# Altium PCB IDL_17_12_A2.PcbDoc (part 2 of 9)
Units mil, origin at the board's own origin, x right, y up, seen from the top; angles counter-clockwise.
Board outline 5119.97 x 10350 mil, 6 copper layers (Top Signal, 3.3 Volt, GND, 5 Volt, Split Plane, Bot Signal), stack 66.2 mil thick; 514 components, 178 nets, 2321 pads, 427 vias.

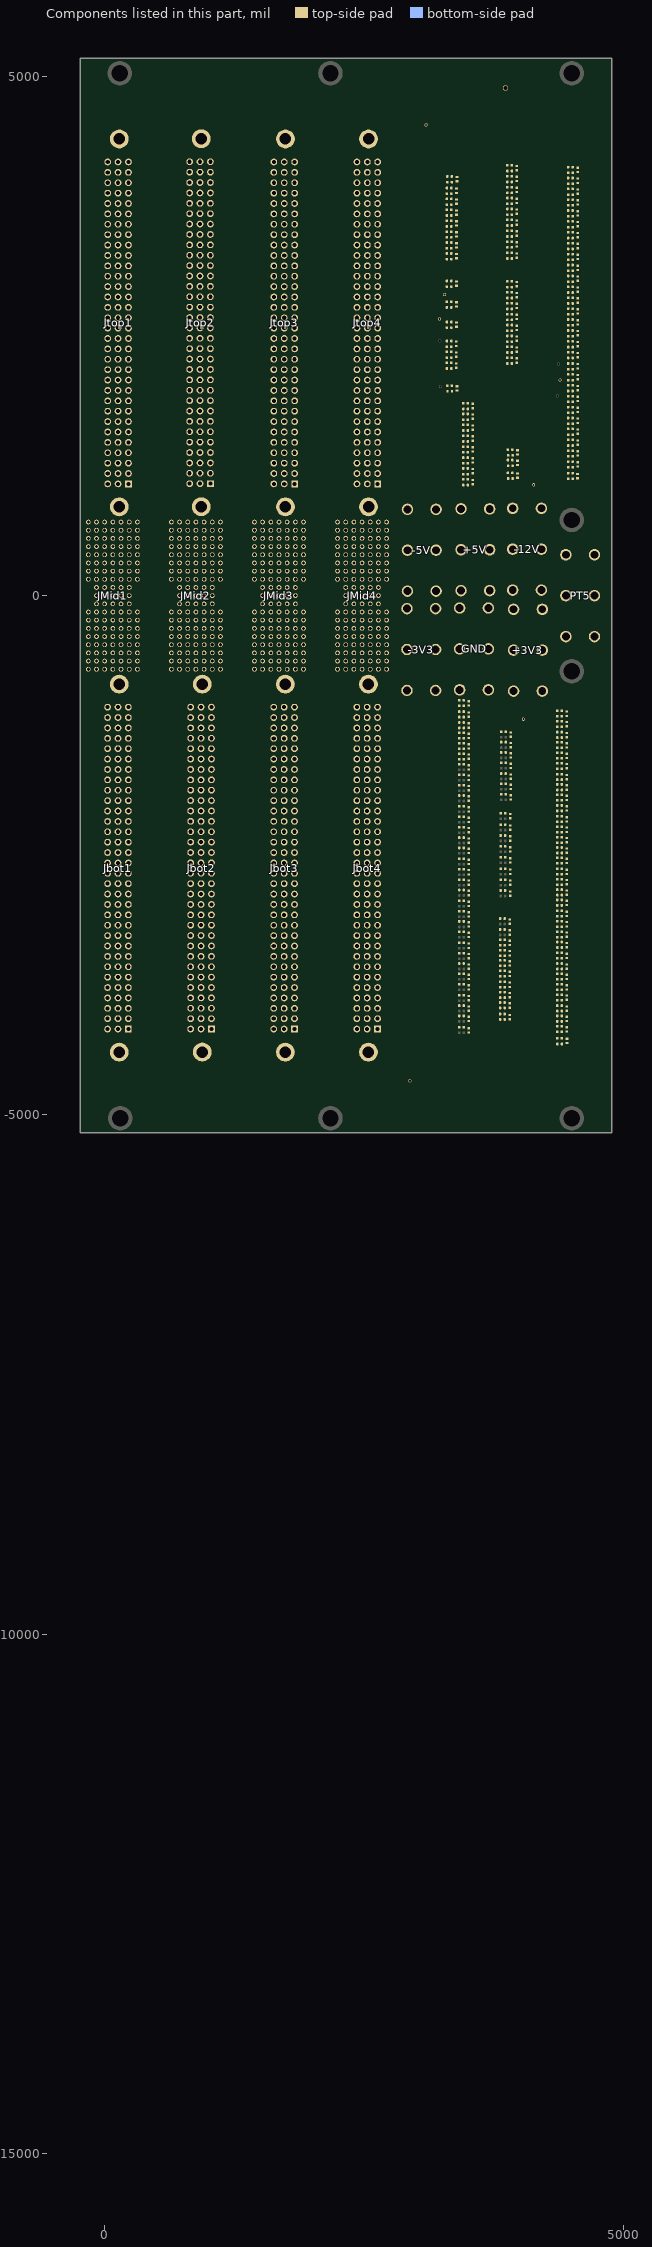
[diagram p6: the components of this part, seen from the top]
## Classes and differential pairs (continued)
component class IDL_17_12_TerB50: CRB_IDL_17_12_TerB50 R1RB_IDL_17_12_TerB50 R2RB_IDL_17_12_TerB50
component class IDL_17_12_TerB51: CRB_IDL_17_12_TerB51 R1RB_IDL_17_12_TerB51 R2RB_IDL_17_12_TerB51
component class IDL_17_12_TerB52: CRB_IDL_17_12_TerB52 R1RB_IDL_17_12_TerB52 R2RB_IDL_17_12_TerB52
component class IDL_17_12_TerB53: CRB_IDL_17_12_TerB53 R1RB_IDL_17_12_TerB53 R2RB_IDL_17_12_TerB53
component class IDL_17_12_TerB54: CRB_IDL_17_12_TerB54 R1RB_IDL_17_12_TerB54 R2RB_IDL_17_12_TerB54
component class IDL_17_12_TerB55: CRB_IDL_17_12_TerB55 R1RB_IDL_17_12_TerB55 R2RB_IDL_17_12_TerB55
component class IDL_17_12_TerB56: CRB_IDL_17_12_TerB56 R1RB_IDL_17_12_TerB56 R2RB_IDL_17_12_TerB56
component class IDL_17_12_TerB57: CRB_IDL_17_12_TerB57 R1RB_IDL_17_12_TerB57 R2RB_IDL_17_12_TerB57
component class IDL_17_12_TerB58: CRB_IDL_17_12_TerB58 R1RB_IDL_17_12_TerB58 R2RB_IDL_17_12_TerB58
component class IDL_17_12_TerB59: CRB_IDL_17_12_TerB59 R1RB_IDL_17_12_TerB59 R2RB_IDL_17_12_TerB59
component class IDL_17_12_TerB60: CRB_IDL_17_12_TerB60 R1RB_IDL_17_12_TerB60 R2RB_IDL_17_12_TerB60
component class IDL_17_12_TerB61: CRB_IDL_17_12_TerB61 R1RB_IDL_17_12_TerB61 R2RB_IDL_17_12_TerB61
component class IDL_17_12_TerB62: CRB_IDL_17_12_TerB62 R1RB_IDL_17_12_TerB62 R2RB_IDL_17_12_TerB62
component class IDL_17_12_TerB63: CRB_IDL_17_12_TerB63 R1RB_IDL_17_12_TerB63 R2RB_IDL_17_12_TerB63
component class IDL_17_12_TerB64: CRB_IDL_17_12_TerB64 R1RB_IDL_17_12_TerB64 R2RB_IDL_17_12_TerB64
component class IDL_17_12_TerB65: CRB_IDL_17_12_TerB65 R1RB_IDL_17_12_TerB65 R2RB_IDL_17_12_TerB65
component class IDL_17_12_TerB66: CRB_IDL_17_12_TerB66 R1RB_IDL_17_12_TerB66 R2RB_IDL_17_12_TerB66
component class IDL_17_12_TerB67: CRB_IDL_17_12_TerB67 R1RB_IDL_17_12_TerB67 R2RB_IDL_17_12_TerB67
component class IDL_17_12_TerB68: CRB_IDL_17_12_TerB68 R1RB_IDL_17_12_TerB68 R2RB_IDL_17_12_TerB68
component class IDL_17_12_TerB69: CRB_IDL_17_12_TerB69 R1RB_IDL_17_12_TerB69 R2RB_IDL_17_12_TerB69
component class IDL_17_12_TerB70: CRB_IDL_17_12_TerB70 R1RB_IDL_17_12_TerB70 R2RB_IDL_17_12_TerB70
component class IDL_17_12_TerB71: CRB_IDL_17_12_TerB71 R1RB_IDL_17_12_TerB71 R2RB_IDL_17_12_TerB71
component class IDL_17_12_TerB72: CRB_IDL_17_12_TerB72 R1RB_IDL_17_12_TerB72 R2RB_IDL_17_12_TerB72
component class IDL_17_12_TerB73: CRB_IDL_17_12_TerB73 R1RB_IDL_17_12_TerB73 R2RB_IDL_17_12_TerB73
component class IDL_17_12_TerB74: CRB_IDL_17_12_TerB74 R1RB_IDL_17_12_TerB74 R2RB_IDL_17_12_TerB74
component class IDL_17_12_TerB75: CRB_IDL_17_12_TerB75 R1RB_IDL_17_12_TerB75 R2RB_IDL_17_12_TerB75
component class IDL_17_12_TerB76: CRB_IDL_17_12_TerB76 R1RB_IDL_17_12_TerB76 R2RB_IDL_17_12_TerB76
component class IDL_17_12_TerB77: CRB_IDL_17_12_TerB77 R1RB_IDL_17_12_TerB77 R2RB_IDL_17_12_TerB77
component class IDL_17_12_TerB78: CRB_IDL_17_12_TerB78 R1RB_IDL_17_12_TerB78 R2RB_IDL_17_12_TerB78
component class IDL_17_12_TerB79: CRB_IDL_17_12_TerB79 R1RB_IDL_17_12_TerB79 R2RB_IDL_17_12_TerB79
component class IDL_17_12_TerB80: CRB_IDL_17_12_TerB80 R1RB_IDL_17_12_TerB80 R2RB_IDL_17_12_TerB80
component class IDL_17_12_TerB81: CRB_IDL_17_12_TerB81 R1RB_IDL_17_12_TerB81 R2RB_IDL_17_12_TerB81
component class IDL_17_12_TerB82: CRB_IDL_17_12_TerB82 R1RB_IDL_17_12_TerB82 R2RB_IDL_17_12_TerB82
component class IDL_17_12_TerB83: CRB_IDL_17_12_TerB83 R1RB_IDL_17_12_TerB83 R2RB_IDL_17_12_TerB83
component class IDL_17_12_TerB84: CRB_IDL_17_12_TerB84 R1RB_IDL_17_12_TerB84 R2RB_IDL_17_12_TerB84
component class IDL_17_12_TerB85: CRB_IDL_17_12_TerB85 R1RB_IDL_17_12_TerB85 R2RB_IDL_17_12_TerB85
component class IDL_17_12_TerB86: CRB_IDL_17_12_TerB86 R1RB_IDL_17_12_TerB86 R2RB_IDL_17_12_TerB86
component class IDL_17_12_TerB87: CRB_IDL_17_12_TerB87 R1RB_IDL_17_12_TerB87 R2RB_IDL_17_12_TerB87
component class IDL_17_12_TerB88: CRB_IDL_17_12_TerB88 R1RB_IDL_17_12_TerB88 R2RB_IDL_17_12_TerB88
component class IDL_17_12_Top: +3V3 +5V -3V3 -5V -12V GND PT5
net class JB[1..89]: JB1 JB2 JB3 JB4 JB5 JB6 JB7 JB8 JB9 JB10 JB11 JB12 JB13 JB14 JB15 JB16 JB17 JB18 JB19 JB20 JB21 JB22 JB23 JB24 JB25 JB26 JB27 JB28 JB29 JB30 JB31 JB32 JB33 JB34 JB35 JB36 JB37 JB38 JB39 JB40 JB41 JB42 JB43 JB44 JB45 JB46 JB47 JB48 JB49 JB50 JB51 JB52 JB53 JB54 JB55 JB56 JB57 JB58 JB59 JB60 JB61 JB62 JB63 JB64 JB65 JB66 JB67 JB68 JB69 JB70 JB71 JB72 JB73 JB74 JB75 JB76 JB77 JB78 JB79 JB80 JB81 JB82 JB83 JB84 JB85 JB86 JB87 JB88 JB89
net class JT[1..72]: JT1 JT2 JT3 JT4 JT5 JT6 JT7 JT8 JT9 JT10 JT11 JT12 JT13 JT14 JT15 JT16 JT17 JT18 JT19 JT20 JT21 JT22 JT23 JT24 JT25 JT26 JT27 JT28 JT29 JT30 JT31 JT32 JT33 JT34 JT35 JT36 JT37 JT38 JT39 JT40 JT41 JT42 JT43 JT44 JT45 JT46 JT47 JT48 JT49 JT50 JT51 JT52 JT53 JT54 JT55 JT56 JT57 JT58 JT59 JT60 JT61 JT62 JT63 JT64 JT65 JT66 JT67 JT68 JT69 JT70 JT71 JT72
channel class IDL_17_12_TerA: IDL_17_12_TerA1 IDL_17_12_TerA2 IDL_17_12_TerA3 IDL_17_12_TerA4 IDL_17_12_TerA5 IDL_17_12_TerA6 IDL_17_12_TerA7 IDL_17_12_TerA8 IDL_17_12_TerA9 IDL_17_12_TerA10 IDL_17_12_TerA11 IDL_17_12_TerA12 IDL_17_12_TerA13 IDL_17_12_TerA14 IDL_17_12_TerA15 IDL_17_12_TerA16 IDL_17_12_TerA17 IDL_17_12_TerA18 IDL_17_12_TerA19 IDL_17_12_TerA20 IDL_17_12_TerA21 IDL_17_12_TerA22 IDL_17_12_TerA23 IDL_17_12_TerA24 IDL_17_12_TerA25 IDL_17_12_TerA26 IDL_17_12_TerA27 IDL_17_12_TerA28 IDL_17_12_TerA29 IDL_17_12_TerA30 IDL_17_12_TerA31 IDL_17_12_TerA32 IDL_17_12_TerA33 IDL_17_12_TerA34 IDL_17_12_TerA35 IDL_17_12_TerA36 IDL_17_12_TerA37 IDL_17_12_TerA38 IDL_17_12_TerA39 IDL_17_12_TerA40 IDL_17_12_TerA41 IDL_17_12_TerA42 IDL_17_12_TerA43 IDL_17_12_TerA44 IDL_17_12_TerA45 IDL_17_12_TerA46 IDL_17_12_TerA47 IDL_17_12_TerA48 IDL_17_12_TerA49 IDL_17_12_TerA50 IDL_17_12_TerA51 IDL_17_12_TerA52 IDL_17_12_TerA53 IDL_17_12_TerA54 IDL_17_12_TerA55 IDL_17_12_TerA56 IDL_17_12_TerA57 IDL_17_12_TerA58 IDL_17_12_TerA59 IDL_17_12_TerA60 IDL_17_12_TerA61 IDL_17_12_TerA62 IDL_17_12_TerA63 IDL_17_12_TerA64 IDL_17_12_TerA65 IDL_17_12_TerA66 IDL_17_12_TerA67 IDL_17_12_TerA68 IDL_17_12_TerA69 IDL_17_12_TerA70 IDL_17_12_TerA71
channel class IDL_17_12_TerB: IDL_17_12_TerB1 IDL_17_12_TerB2 IDL_17_12_TerB3 IDL_17_12_TerB4 IDL_17_12_TerB5 IDL_17_12_TerB6 IDL_17_12_TerB7 IDL_17_12_TerB8 IDL_17_12_TerB9 IDL_17_12_TerB10 IDL_17_12_TerB11 IDL_17_12_TerB12 IDL_17_12_TerB13 IDL_17_12_TerB14 IDL_17_12_TerB15 IDL_17_12_TerB16 IDL_17_12_TerB17 IDL_17_12_TerB18 IDL_17_12_TerB19 IDL_17_12_TerB20 IDL_17_12_TerB21 IDL_17_12_TerB22 IDL_17_12_TerB23 IDL_17_12_TerB24 IDL_17_12_TerB25 IDL_17_12_TerB26 IDL_17_12_TerB27 IDL_17_12_TerB28 IDL_17_12_TerB29 IDL_17_12_TerB30 IDL_17_12_TerB31 IDL_17_12_TerB32 IDL_17_12_TerB33 IDL_17_12_TerB34 IDL_17_12_TerB35 IDL_17_12_TerB36 IDL_17_12_TerB37 IDL_17_12_TerB38 IDL_17_12_TerB39 IDL_17_12_TerB40 IDL_17_12_TerB41 IDL_17_12_TerB42 IDL_17_12_TerB43 IDL_17_12_TerB44 IDL_17_12_TerB45 IDL_17_12_TerB46 IDL_17_12_TerB47 IDL_17_12_TerB48 IDL_17_12_TerB49 IDL_17_12_TerB50 IDL_17_12_TerB51 IDL_17_12_TerB52 IDL_17_12_TerB53 IDL_17_12_TerB54 IDL_17_12_TerB55 IDL_17_12_TerB56 IDL_17_12_TerB57 IDL_17_12_TerB58 IDL_17_12_TerB59 IDL_17_12_TerB60 IDL_17_12_TerB61 IDL_17_12_TerB62 IDL_17_12_TerB63 IDL_17_12_TerB64 IDL_17_12_TerB65 IDL_17_12_TerB66 IDL_17_12_TerB67 IDL_17_12_TerB68 IDL_17_12_TerB69 IDL_17_12_TerB70 IDL_17_12_TerB71 IDL_17_12_TerB72 IDL_17_12_TerB73 IDL_17_12_TerB74 IDL_17_12_TerB75 IDL_17_12_TerB76 IDL_17_12_TerB77 IDL_17_12_TerB78 IDL_17_12_TerB79 IDL_17_12_TerB80 IDL_17_12_TerB81 IDL_17_12_TerB82 IDL_17_12_TerB83 IDL_17_12_TerB84 IDL_17_12_TerB85 IDL_17_12_TerB86 IDL_17_12_TerB87 IDL_17_12_TerB88
component class IDL_17_12_TerB89: CRB_IDL_17_12_TerB89 R1RB_IDL_17_12_TerB89 R2RB_IDL_17_12_TerB89

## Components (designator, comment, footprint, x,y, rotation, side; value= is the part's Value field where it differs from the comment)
+3V3 "*" PowerTap 3938.12,-919.16 r90 top (schematic designator PT2)
+5V "*" PowerTap 3431.95,48.27 r90 top (schematic designator PT7)
-3V3 "*" PowerTap 2911,-912.72 r90 top (schematic designator PT3)
-5V "*" PowerTap 2915.56,43.52 r90 top (schematic designator PT1)
-12V "*" PowerTap 3929.35,53.22 r90 top (schematic designator PT6)
AS "Comment" TPH0.5S#1 3272.63,2898.29 r0 top
BERR "Comment" TPH0.5S#1 4386.58,2076.24 r0 top
CR_IDL_17_12_TerA1 ".1uF" CC0402N1X 3392.34,4010.25 r90 top (schematic designator CR)
CR_IDL_17_12_TerA2 ".1uF" CC0402N1X 3387.34,3899.01 r90 top (schematic designator CR)
CR_IDL_17_12_TerA3 ".1uF" CC0402N1X 3387.34,3794.01 r90 top (schematic designator CR)
CR_IDL_17_12_TerA4 ".1uF" CC0402N1X 3387.34,3689.01 r90 top (schematic designator CR)
CR_IDL_17_12_TerA5 ".1uF" CC0402N1X 3387.34,3584.01 r90 top (schematic designator CR)
CR_IDL_17_12_TerA6 ".1uF" CC0402N1X 3387.34,3479.01 r90 top (schematic designator CR)
CR_IDL_17_12_TerA7 ".1uF" CC0402N1X 3387.34,3374.01 r90 top (schematic designator CR)
CR_IDL_17_12_TerA8 ".1uF" CC0402N1X 3387.34,3269.01 r90 top (schematic designator CR)
CR_IDL_17_12_TerA9 ".1uF" CC0402N1X 3387.34,3004.01 r90 top (schematic designator CR)
CR_IDL_17_12_TerA10 ".1uF" CC0402N1X 3387.34,2804.01 r90 top (schematic designator CR)
CR_IDL_17_12_TerA11 ".1uF" CC0402N1X 3387.34,2609.01 r90 top (schematic designator CR)
CR_IDL_17_12_TerA12 ".1uF" CC0402N1X 3386.98,2425.8 r90 top (schematic designator CR)
CR_IDL_17_12_TerA13 ".1uF" CC0402N1X 3386.98,2320.8 r90 top (schematic designator CR)
CR_IDL_17_12_TerA14 ".1uF" CC0402N1X 3386.98,2215.8 r90 top (schematic designator CR)
CR_IDL_17_12_TerA15 ".1uF" CC0402N1X 3392.98,1995.86 r90 top (schematic designator CR)
CR_IDL_17_12_TerA16 ".1uF" CC0402N1X 3545.25,1826.49 r90 top (schematic designator CR)
CR_IDL_17_12_TerA17 ".1uF" CC0402N1X 3545.25,1723.49 r90 top (schematic designator CR)
CR_IDL_17_12_TerA18 ".1uF" CC0402N1X 3545.25,1618.49 r90 top (schematic designator CR)
CR_IDL_17_12_TerA19 ".1uF" CC0402N1X 3545.25,1513.49 r90 top (schematic designator CR)
CR_IDL_17_12_TerA20 ".1uF" CC0402N1X 3545.25,1408.49 r90 top (schematic designator CR)
CR_IDL_17_12_TerA21 ".1uF" CC0402N1X 3545.25,1303.49 r90 top (schematic designator CR)
CR_IDL_17_12_TerA22 ".1uF" CC0402N1X 3545.25,1198.49 r90 top (schematic designator CR)
CR_IDL_17_12_TerA23 ".1uF" CC0402N1X 3545.25,1093.49 r90 top (schematic designator CR)
CR_IDL_17_12_TerA24 ".1uF" CC0402N1X 3969.9,4117.6 r90 top (schematic designator CR)
CR_IDL_17_12_TerA25 ".1uF" CC0402N1X 3969.9,4012.6 r90 top (schematic designator CR)
CR_IDL_17_12_TerA26 ".1uF" CC0402N1X 3969.9,3907.6 r90 top (schematic designator CR)
CR_IDL_17_12_TerA27 ".1uF" CC0402N1X 3969.9,3802.6 r90 top (schematic designator CR)
CR_IDL_17_12_TerA28 ".1uF" CC0402N1X 3969.9,3697.6 r90 top (schematic designator CR)
CR_IDL_17_12_TerA29 ".1uF" CC0402N1X 3969.9,3592.6 r90 top (schematic designator CR)
CR_IDL_17_12_TerA30 ".1uF" CC0402N1X 3969.9,3487.6 r90 top (schematic designator CR)
CR_IDL_17_12_TerA31 ".1uF" CC0402N1X 3969.9,3382.6 r90 top (schematic designator CR)
CR_IDL_17_12_TerA32 ".1uF" CC0402N1X 3969.9,3274.6 r90 top (schematic designator CR)
CR_IDL_17_12_TerA33 ".1uF" CC0402N1X 3969.9,2999.6 r90 top (schematic designator CR)
CR_IDL_17_12_TerA34 ".1uF" CC0402N1X 3969.9,2894.6 r90 top (schematic designator CR)
CR_IDL_17_12_TerA35 ".1uF" CC0402N1X 3969.9,2789.6 r90 top (schematic designator CR)
CR_IDL_17_12_TerA36 ".1uF" CC0402N1X 3969.9,2684.6 r90 top (schematic designator CR)
CR_IDL_17_12_TerA37 ".1uF" CC0402N1X 3969.9,2579.6 r90 top (schematic designator CR)
CR_IDL_17_12_TerA38 ".1uF" CC0402N1X 3969.9,2474.6 r90 top (schematic designator CR)
CR_IDL_17_12_TerA39 ".1uF" CC0402N1X 3969.9,2369.6 r90 top (schematic designator CR)
CR_IDL_17_12_TerA40 ".1uF" CC0402N1X 3969.9,2264.6 r90 top (schematic designator CR)
CR_IDL_17_12_TerA41 ".1uF" CC0402N1X 3975.8,1379.07 r90 top (schematic designator CR)
CR_IDL_17_12_TerA42 ".1uF" CC0402N1X 3975.8,1279.07 r90 top (schematic designator CR)
CR_IDL_17_12_TerA43 ".1uF" CC0402N1X 3975.73,1156.1 r90 top (schematic designator CR)
CR_IDL_17_12_TerA44 ".1uF" CC0402N1X 4555.17,4100.26 r90 top (schematic designator CR)
CR_IDL_17_12_TerA45 ".1uF" CC0402N1X 4555.17,3995.26 r90 top (schematic designator CR)
CR_IDL_17_12_TerA46 ".1uF" CC0402N1X 4555.17,3890.26 r90 top (schematic designator CR)
CR_IDL_17_12_TerA47 ".1uF" CC0402N1X 4555.17,3787.26 r90 top (schematic designator CR)
CR_IDL_17_12_TerA48 ".1uF" CC0402N1X 4555.17,3682.26 r90 top (schematic designator CR)
CR_IDL_17_12_TerA49 ".1uF" CC0402N1X 4555.17,3577.26 r90 top (schematic designator CR)
CR_IDL_17_12_TerA50 ".1uF" CC0402N1X 4555.17,3472.26 r90 top (schematic designator CR)
CR_IDL_17_12_TerA51 ".1uF" CC0402N1X 4555.17,3367.26 r90 top (schematic designator CR)
CR_IDL_17_12_TerA52 ".1uF" CC0402N1X 4555.17,3262.26 r90 top (schematic designator CR)
CR_IDL_17_12_TerA53 ".1uF" CC0402N1X 4555.17,3157.26 r90 top (schematic designator CR)
CR_IDL_17_12_TerA54 ".1uF" CC0402N1X 4555.17,3052.26 r90 top (schematic designator CR)
CR_IDL_17_12_TerA55 ".1uF" CC0402N1X 4555.17,2947.26 r90 top (schematic designator CR)
CR_IDL_17_12_TerA56 ".1uF" CC0402N1X 4555.17,2842.26 r90 top (schematic designator CR)
CR_IDL_17_12_TerA57 ".1uF" CC0402N1X 4555.17,2737.26 r90 top (schematic designator CR)
CR_IDL_17_12_TerA58 ".1uF" CC0402N1X 4555.17,2632.26 r90 top (schematic designator CR)
CR_IDL_17_12_TerA59 ".1uF" CC0402N1X 4555.17,2527.26 r90 top (schematic designator CR)
CR_IDL_17_12_TerA60 ".1uF" CC0402N1X 4555.17,2422.26 r90 top (schematic designator CR)
CR_IDL_17_12_TerA61 ".1uF" CC0402N1X 4555.17,2317.26 r90 top (schematic designator CR)
CR_IDL_17_12_TerA62 ".1uF" CC0402N1X 4555.17,2209.26 r90 top (schematic designator CR)
CR_IDL_17_12_TerA63 ".1uF" CC0402N1X 4555.17,2104.26 r90 top (schematic designator CR)
CR_IDL_17_12_TerA64 ".1uF" CC0402N1X 4555.17,1999.26 r90 top (schematic designator CR)
CR_IDL_17_12_TerA65 ".1uF" CC0402N1X 4555.17,1894.26 r90 top (schematic designator CR)
CR_IDL_17_12_TerA66 ".1uF" CC0402N1X 4555.17,1789.26 r90 top (schematic designator CR)
CR_IDL_17_12_TerA67 ".1uF" CC0402N1X 4555.17,1684.26 r90 top (schematic designator CR)
CR_IDL_17_12_TerA68 ".1uF" CC0402N1X 4555.17,1579.26 r90 top (schematic designator CR)
CR_IDL_17_12_TerA69 ".1uF" CC0402N1X 4555.17,1474.26 r90 top (schematic designator CR)
CR_IDL_17_12_TerA70 ".1uF" CC0402N1X 4555.17,1369.26 r90 top (schematic designator CR)
CR_IDL_17_12_TerA71 ".1uF" CC0402N1X 4555.17,1264.26 r90 top (schematic designator CR)
CR_IDL_17_12_TerA72 ".1uF" CC0402N1X 4553.87,1151.8 r90 top (schematic designator CR)
CRB_IDL_17_12_TerB1 ".1uF" CC0402N1X 3505.91,-1038.01 r90 top (schematic designator CRB)
CRB_IDL_17_12_TerB2 ".1uF" CC0402N1X 3506.6,-1145.48 r90 top (schematic designator CRB)
CRB_IDL_17_12_TerB3 ".1uF" CC0402N1X 3506.6,-1250.48 r90 top (schematic designator CRB)
CRB_IDL_17_12_TerB4 ".1uF" CC0402N1X 3506.6,-1350.48 r90 top (schematic designator CRB)
CRB_IDL_17_12_TerB5 ".1uF" CC0402N1X 3506.6,-1450.48 r90 top (schematic designator CRB)
CRB_IDL_17_12_TerB6 ".1uF" CC0402N1X 3506.6,-1550.48 r90 top (schematic designator CRB)
CRB_IDL_17_12_TerB7 ".1uF" CC0402N1X 3506.6,-1653.48 r90 top (schematic designator CRB)
CRB_IDL_17_12_TerB8 ".1uF" CC0402N1X 3506.6,-1753.48 r90 top (schematic designator CRB)
CRB_IDL_17_12_TerB9 ".1uF" CC0402N1X 3506.6,-1853.48 r90 top (schematic designator CRB)
CRB_IDL_17_12_TerB10 ".1uF" CC0402N1X 3506.6,-1953.48 r90 top (schematic designator CRB)
CRB_IDL_17_12_TerB11 ".1uF" CC0402N1X 3506.6,-2058.48 r90 top (schematic designator CRB)
CRB_IDL_17_12_TerB12 ".1uF" CC0402N1X 3506.6,-2158.48 r90 top (schematic designator CRB)
CRB_IDL_17_12_TerB13 ".1uF" CC0402N1X 3506.6,-2258.48 r90 top (schematic designator CRB)
CRB_IDL_17_12_TerB14 ".1uF" CC0402N1X 3506.6,-2358.48 r90 top (schematic designator CRB)
CRB_IDL_17_12_TerB15 ".1uF" CC0402N1X 3506.6,-2458.48 r90 top (schematic designator CRB)
CRB_IDL_17_12_TerB16 ".1uF" CC0402N1X 3506.6,-2563.48 r90 top (schematic designator CRB)
CRB_IDL_17_12_TerB17 ".1uF" CC0402N1X 3506.6,-2663.48 r90 top (schematic designator CRB)
CRB_IDL_17_12_TerB18 ".1uF" CC0402N1X 3506.6,-2763.48 r90 top (schematic designator CRB)
CRB_IDL_17_12_TerB19 ".1uF" CC0402N1X 3506.6,-2863.48 r90 top (schematic designator CRB)
CRB_IDL_17_12_TerB20 ".1uF" CC0402N1X 3506.6,-2968.48 r90 top (schematic designator CRB)
CRB_IDL_17_12_TerB21 ".1uF" CC0402N1X 3506.6,-3068.48 r90 top (schematic designator CRB)
CRB_IDL_17_12_TerB22 ".1uF" CC0402N1X 3506.6,-3166.48 r90 top (schematic designator CRB)
CRB_IDL_17_12_TerB23 ".1uF" CC0402N1X 3506.6,-3266.48 r90 top (schematic designator CRB)
CRB_IDL_17_12_TerB24 ".1uF" CC0402N1X 3506.6,-3371.48 r90 top (schematic designator CRB)
CRB_IDL_17_12_TerB25 ".1uF" CC0402N1X 3506.6,-3471.48 r90 top (schematic designator CRB)
CRB_IDL_17_12_TerB26 ".1uF" CC0402N1X 3506.6,-3571.48 r90 top (schematic designator CRB)
CRB_IDL_17_12_TerB27 ".1uF" CC0402N1X 3506.6,-3671.48 r90 top (schematic designator CRB)
CRB_IDL_17_12_TerB28 ".1uF" CC0402N1X 3506.6,-3771.48 r90 top (schematic designator CRB)
CRB_IDL_17_12_TerB29 ".1uF" CC0402N1X 3506.6,-3876.48 r90 top (schematic designator CRB)
CRB_IDL_17_12_TerB30 ".1uF" CC0402N1X 3506.6,-3976.48 r90 top (schematic designator CRB)
CRB_IDL_17_12_TerB31 ".1uF" CC0402N1X 3506.6,-4076.48 r90 top (schematic designator CRB)
CRB_IDL_17_12_TerB32 ".1uF" CC0402N1X 3506.2,-4185.54 r90 top (schematic designator CRB)
CRB_IDL_17_12_TerB33 ".1uF" CC0402N1X 3910.55,-1339.06 r90 top (schematic designator CRB)
CRB_IDL_17_12_TerB34 ".1uF" CC0402N1X 3910.55,-1439.06 r90 top (schematic designator CRB)
CRB_IDL_17_12_TerB35 ".1uF" CC0402N1X 3910.55,-1539.06 r90 top (schematic designator CRB)
CRB_IDL_17_12_TerB36 ".1uF" CC0402N1X 3910.55,-1639.06 r90 top (schematic designator CRB)
CRB_IDL_17_12_TerB37 ".1uF" CC0402N1X 3910.55,-1742.06 r90 top (schematic designator CRB)
CRB_IDL_17_12_TerB38 ".1uF" CC0402N1X 3910.55,-1842.06 r90 top (schematic designator CRB)
CRB_IDL_17_12_TerB39 ".1uF" CC0402N1X 3910.55,-1942.06 r90 top (schematic designator CRB)
CRB_IDL_17_12_TerB40 ".1uF" CC0402N1X 3905.55,-2123.71 r90 top (schematic designator CRB)
CRB_IDL_17_12_TerB41 ".1uF" CC0402N1X 3905.55,-2233.71 r90 top (schematic designator CRB)
CRB_IDL_17_12_TerB42 ".1uF" CC0402N1X 3905.55,-2338.71 r90 top (schematic designator CRB)
CRB_IDL_17_12_TerB43 ".1uF" CC0402N1X 3905.55,-2443.71 r90 top (schematic designator CRB)
CRB_IDL_17_12_TerB44 ".1uF" CC0402N1X 3905.55,-2548.71 r90 top (schematic designator CRB)
CRB_IDL_17_12_TerB45 ".1uF" CC0402N1X 3905.55,-2658.71 r90 top (schematic designator CRB)
CRB_IDL_17_12_TerB46 ".1uF" CC0402N1X 3905.55,-2763.71 r90 top (schematic designator CRB)
CRB_IDL_17_12_TerB47 ".1uF" CC0402N1X 3905.55,-2868.71 r90 top (schematic designator CRB)
CRB_IDL_17_12_TerB48 ".1uF" CC0402N1X 3900.55,-3138.71 r90 top (schematic designator CRB)
CRB_IDL_17_12_TerB49 ".1uF" CC0402N1X 3900.55,-3243.71 r90 top (schematic designator CRB)
CRB_IDL_17_12_TerB50 ".1uF" CC0402N1X 3900.55,-3343.71 r90 top (schematic designator CRB)
CRB_IDL_17_12_TerB51 ".1uF" CC0402N1X 3900.55,-3443.71 r90 top (schematic designator CRB)
CRB_IDL_17_12_TerB52 ".1uF" CC0402N1X 3900.55,-3541.71 r90 top (schematic designator CRB)
CRB_IDL_17_12_TerB53 ".1uF" CC0402N1X 3900.55,-3641.71 r90 top (schematic designator CRB)
CRB_IDL_17_12_TerB54 ".1uF" CC0402N1X 3900.55,-3746.71 r90 top (schematic designator CRB)
CRB_IDL_17_12_TerB55 ".1uF" CC0402N1X 3900.55,-3846.71 r90 top (schematic designator CRB)
CRB_IDL_17_12_TerB56 ".1uF" CC0402N1X 3900.55,-3946.71 r90 top (schematic designator CRB)
CRB_IDL_17_12_TerB57 ".1uF" CC0402N1X 3900.51,-4057.69 r90 top (schematic designator CRB)
CRB_IDL_17_12_TerB58 ".1uF" CC0402N1X 4450.29,-1137.42 r90 top (schematic designator CRB)
CRB_IDL_17_12_TerB59 ".1uF" CC0402N1X 4450.29,-1237.42 r90 top (schematic designator CRB)
CRB_IDL_17_12_TerB60 ".1uF" CC0402N1X 4450.29,-1342.42 r90 top (schematic designator CRB)
CRB_IDL_17_12_TerB61 ".1uF" CC0402N1X 4450.29,-1442.42 r90 top (schematic designator CRB)
CRB_IDL_17_12_TerB62 ".1uF" CC0402N1X 4450.29,-1542.42 r90 top (schematic designator CRB)
CRB_IDL_17_12_TerB63 ".1uF" CC0402N1X 4450.29,-1642.42 r90 top (schematic designator CRB)
CRB_IDL_17_12_TerB64 ".1uF" CC0402N1X 4450.29,-1747.42 r90 top (schematic designator CRB)
CRB_IDL_17_12_TerB65 ".1uF" CC0402N1X 4450.29,-1847.42 r90 top (schematic designator CRB)
CRB_IDL_17_12_TerB66 ".1uF" CC0402N1X 4450.29,-1947.42 r90 top (schematic designator CRB)
CRB_IDL_17_12_TerB67 ".1uF" CC0402N1X 4450.29,-2049.42 r90 top (schematic designator CRB)
CRB_IDL_17_12_TerB68 ".1uF" CC0402N1X 4450.29,-2154.42 r90 top (schematic designator CRB)
CRB_IDL_17_12_TerB69 ".1uF" CC0402N1X 4450.29,-2254.42 r90 top (schematic designator CRB)
CRB_IDL_17_12_TerB70 ".1uF" CC0402N1X 4450.29,-2354.42 r90 top (schematic designator CRB)
CRB_IDL_17_12_TerB71 ".1uF" CC0402N1X 4450.29,-2454.42 r90 top (schematic designator CRB)
CRB_IDL_17_12_TerB72 ".1uF" CC0402N1X 4450.29,-2554.42 r90 top (schematic designator CRB)
CRB_IDL_17_12_TerB73 ".1uF" CC0402N1X 4450.29,-2659.42 r90 top (schematic designator CRB)
CRB_IDL_17_12_TerB74 ".1uF" CC0402N1X 4450.29,-2759.42 r90 top (schematic designator CRB)
CRB_IDL_17_12_TerB75 ".1uF" CC0402N1X 4450.29,-2859.42 r90 top (schematic designator CRB)
CRB_IDL_17_12_TerB76 ".1uF" CC0402N1X 4450.29,-2959.42 r90 top (schematic designator CRB)
CRB_IDL_17_12_TerB77 ".1uF" CC0402N1X 4450.29,-3064.42 r90 top (schematic designator CRB)
CRB_IDL_17_12_TerB78 ".1uF" CC0402N1X 4450.29,-3164.42 r90 top (schematic designator CRB)
CRB_IDL_17_12_TerB79 ".1uF" CC0402N1X 4450.29,-3264.42 r90 top (schematic designator CRB)
CRB_IDL_17_12_TerB80 ".1uF" CC0402N1X 4450.29,-3364.42 r90 top (schematic designator CRB)
CRB_IDL_17_12_TerB81 ".1uF" CC0402N1X 4450.29,-3469.42 r90 top (schematic designator CRB)
CRB_IDL_17_12_TerB82 ".1uF" CC0402N1X 4450.29,-3571.42 r90 top (schematic designator CRB)
CRB_IDL_17_12_TerB83 ".1uF" CC0402N1X 4450.29,-3671.42 r90 top (schematic designator CRB)
CRB_IDL_17_12_TerB84 ".1uF" CC0402N1X 4450.29,-3771.42 r90 top (schematic designator CRB)
CRB_IDL_17_12_TerB85 ".1uF" CC0402N1X 4450.29,-3871.42 r90 top (schematic designator CRB)
CRB_IDL_17_12_TerB86 ".1uF" CC0402N1X 4450.29,-3976.42 r90 top (schematic designator CRB)
CRB_IDL_17_12_TerB87 ".1uF" CC0402N1X 4450.29,-4076.42 r90 top (schematic designator CRB)
CRB_IDL_17_12_TerB88 ".1uF" CC0402N1X 4450.29,-4176.42 r90 top (schematic designator CRB)
CRB_IDL_17_12_TerB89 ".1uF" CC0402N1X 4451.51,-4288.13 r90 top (schematic designator CRB)
DTACK "Comment" TPH0.5S#1 3224.81,2663 r0 top
GND "*" PowerTap 3418.77,-906.67 r90 top (schematic designator PT4)
GND "Comment" TPH0.5S#1 4032.27,-1189.75 r0 top
GND "Comment" TPH0.5S#1 2938.82,-4671.37 r0 top
GND "Comment" TPH0.5S#1 3095.22,4533.28 r0 top
GND "Comment" TPH0.5S#1 4130.79,1067.56 r0 top
GND1 "Comment" TPH0.5S#2 3859.27,4888.64 r0 top
Jbot1 "" 0903296x825 128.26,-2623.77 r90 top
Jbot2 "" 0903296x825 928.19,-2623.35 r90 top
Jbot3 "" 0903296x825 1728.19,-2623.77 r90 top
Jbot4 "" 0903296x825 2528.19,-2623.77 r90 top
JMid1 "" "127-Pin Conncector" 74.8,23.74 r90 top
JMid2 "" "127-Pin Conncector" 874.8,23.74 r90 top
JMid3 "" "127-Pin Conncector" 1674.8,23.74 r90 top
JMid4 "" "127-Pin Conncector" 2474.8,23.74 r90 top
Jtop1 "" 0903296x825 129.28,2626.24 r90 top
Jtop2 "" 0903296x825 918.19,2628.35 r90 top
Jtop3 "" 0903296x825 1729.28,2626.24 r90 top
Jtop4 "" 0903296x825 2529.28,2626.24 r90 top
PT5 "*" PowerTap 4440.81,-394.17 r90 top
R1R_IDL_17_12_TerA1 "330R" RC0402N1R 3321.73,4036.83 r0 top (schematic designator R1R)
R1R_IDL_17_12_TerA2 "330R" RC0402N1R 3316.73,3925.59 r0 top (schematic designator R1R)
R1R_IDL_17_12_TerA3 "330R" RC0402N1R 3316.73,3820.59 r0 top (schematic designator R1R)
R1R_IDL_17_12_TerA4 "330R" RC0402N1R 3316.73,3715.59 r0 top (schematic designator R1R)
R1R_IDL_17_12_TerA5 "330R" RC0402N1R 3316.73,3610.59 r0 top (schematic designator R1R)
R1R_IDL_17_12_TerA6 "330R" RC0402N1R 3316.73,3505.59 r0 top (schematic designator R1R)
R1R_IDL_17_12_TerA7 "330R" RC0402N1R 3316.73,3400.59 r0 top (schematic designator R1R)
R1R_IDL_17_12_TerA8 "330R" RC0402N1R 3316.73,3295.59 r0 top (schematic designator R1R)
R1R_IDL_17_12_TerA9 "330R" RC0402N1R 3316.73,3030.59 r0 top (schematic designator R1R)
R1R_IDL_17_12_TerA10 "330R" RC0402N1R 3316.73,2830.59 r0 top (schematic designator R1R)
R1R_IDL_17_12_TerA11 "330R" RC0402N1R 3316.73,2635.59 r0 top (schematic designator R1R)
R1R_IDL_17_12_TerA12 "330R" RC0402N1R 3316.36,2452.38 r0 top (schematic designator R1R)
R1R_IDL_17_12_TerA13 "330R" RC0402N1R 3316.36,2347.38 r0 top (schematic designator R1R)
R1R_IDL_17_12_TerA14 "330R" RC0402N1R 3316.36,2242.38 r0 top (schematic designator R1R)
R1R_IDL_17_12_TerA15 "330R" RC0402N1R 3322.37,2022.44 r0 top (schematic designator R1R)
R1R_IDL_17_12_TerA16 "330R" RC0402N1R 3474.64,1853.07 r0 top (schematic designator R1R)
R1R_IDL_17_12_TerA17 "330R" RC0402N1R 3474.64,1750.07 r0 top (schematic designator R1R)
R1R_IDL_17_12_TerA18 "330R" RC0402N1R 3474.64,1645.07 r0 top (schematic designator R1R)
R1R_IDL_17_12_TerA19 "330R" RC0402N1R 3474.64,1540.07 r0 top (schematic designator R1R)
R1R_IDL_17_12_TerA20 "330R" RC0402N1R 3474.64,1435.07 r0 top (schematic designator R1R)
R1R_IDL_17_12_TerA21 "330R" RC0402N1R 3474.64,1330.07 r0 top (schematic designator R1R)
R1R_IDL_17_12_TerA22 "330R" RC0402N1R 3474.64,1225.07 r0 top (schematic designator R1R)
R1R_IDL_17_12_TerA23 "330R" RC0402N1R 3474.64,1120.07 r0 top (schematic designator R1R)
R1R_IDL_17_12_TerA24 "330R" RC0402N1R 3899.29,4144.18 r0 top (schematic designator R1R)
R1R_IDL_17_12_TerA25 "330R" RC0402N1R 3899.29,4039.18 r0 top (schematic designator R1R)
R1R_IDL_17_12_TerA26 "330R" RC0402N1R 3899.29,3934.18 r0 top (schematic designator R1R)
R1R_IDL_17_12_TerA27 "330R" RC0402N1R 3899.29,3829.18 r0 top (schematic designator R1R)
R1R_IDL_17_12_TerA28 "330R" RC0402N1R 3899.29,3724.18 r0 top (schematic designator R1R)
R1R_IDL_17_12_TerA29 "330R" RC0402N1R 3899.29,3619.18 r0 top (schematic designator R1R)
R1R_IDL_17_12_TerA30 "330R" RC0402N1R 3899.29,3514.18 r0 top (schematic designator R1R)
R1R_IDL_17_12_TerA31 "330R" RC0402N1R 3899.29,3409.18 r0 top (schematic designator R1R)
R1R_IDL_17_12_TerA32 "330R" RC0402N1R 3899.29,3301.18 r0 top (schematic designator R1R)
R1R_IDL_17_12_TerA33 "330R" RC0402N1R 3899.29,3026.18 r0 top (schematic designator R1R)
R1R_IDL_17_12_TerA34 "330R" RC0402N1R 3899.29,2921.18 r0 top (schematic designator R1R)
R1R_IDL_17_12_TerA35 "330R" RC0402N1R 3899.29,2816.18 r0 top (schematic designator R1R)
R1R_IDL_17_12_TerA36 "330R" RC0402N1R 3899.29,2711.18 r0 top (schematic designator R1R)
R1R_IDL_17_12_TerA37 "330R" RC0402N1R 3899.29,2606.18 r0 top (schematic designator R1R)
R1R_IDL_17_12_TerA38 "330R" RC0402N1R 3899.29,2501.18 r0 top (schematic designator R1R)
R1R_IDL_17_12_TerA39 "330R" RC0402N1R 3899.29,2396.18 r0 top (schematic designator R1R)
R1R_IDL_17_12_TerA40 "330R" RC0402N1R 3899.29,2291.18 r0 top (schematic designator R1R)
R1R_IDL_17_12_TerA41 "330R" RC0402N1R 3905.19,1405.65 r0 top (schematic designator R1R)
R1R_IDL_17_12_TerA42 "330R" RC0402N1R 3905.19,1305.65 r0 top (schematic designator R1R)
R1R_IDL_17_12_TerA43 "330R" RC0402N1R 3905.11,1182.68 r0 top (schematic designator R1R)
R1R_IDL_17_12_TerA44 "330R" RC0402N1R 4484.56,4126.84 r0 top (schematic designator R1R)
R1R_IDL_17_12_TerA45 "330R" RC0402N1R 4484.56,4021.84 r0 top (schematic designator R1R)
R1R_IDL_17_12_TerA46 "330R" RC0402N1R 4484.56,3916.84 r0 top (schematic designator R1R)
R1R_IDL_17_12_TerA47 "330R" RC0402N1R 4484.56,3813.84 r0 top (schematic designator R1R)
R1R_IDL_17_12_TerA48 "330R" RC0402N1R 4484.56,3708.84 r0 top (schematic designator R1R)
R1R_IDL_17_12_TerA49 "330R" RC0402N1R 4484.56,3603.84 r0 top (schematic designator R1R)
R1R_IDL_17_12_TerA50 "330R" RC0402N1R 4484.56,3498.84 r0 top (schematic designator R1R)
R1R_IDL_17_12_TerA51 "330R" RC0402N1R 4484.56,3393.84 r0 top (schematic designator R1R)
R1R_IDL_17_12_TerA52 "330R" RC0402N1R 4484.56,3288.84 r0 top (schematic designator R1R)
R1R_IDL_17_12_TerA53 "330R" RC0402N1R 4484.56,3183.84 r0 top (schematic designator R1R)
R1R_IDL_17_12_TerA54 "330R" RC0402N1R 4484.56,3078.84 r0 top (schematic designator R1R)
R1R_IDL_17_12_TerA55 "330R" RC0402N1R 4484.56,2973.84 r0 top (schematic designator R1R)
R1R_IDL_17_12_TerA56 "330R" RC0402N1R 4484.56,2868.84 r0 top (schematic designator R1R)
R1R_IDL_17_12_TerA57 "330R" RC0402N1R 4484.56,2763.84 r0 top (schematic designator R1R)
R1R_IDL_17_12_TerA58 "330R" RC0402N1R 4484.56,2658.84 r0 top (schematic designator R1R)
R1R_IDL_17_12_TerA59 "330R" RC0402N1R 4484.56,2553.84 r0 top (schematic designator R1R)
R1R_IDL_17_12_TerA60 "330R" RC0402N1R 4484.56,2448.84 r0 top (schematic designator R1R)
R1R_IDL_17_12_TerA61 "330R" RC0402N1R 4484.56,2343.84 r0 top (schematic designator R1R)
R1R_IDL_17_12_TerA62 "330R" RC0402N1R 4484.56,2235.84 r0 top (schematic designator R1R)
R1R_IDL_17_12_TerA63 "330R" RC0402N1R 4484.56,2130.84 r0 top (schematic designator R1R)
R1R_IDL_17_12_TerA64 "330R" RC0402N1R 4484.56,2025.84 r0 top (schematic designator R1R)
R1R_IDL_17_12_TerA65 "330R" RC0402N1R 4484.56,1920.84 r0 top (schematic designator R1R)
R1R_IDL_17_12_TerA66 "330R" RC0402N1R 4484.56,1815.84 r0 top (schematic designator R1R)
R1R_IDL_17_12_TerA67 "330R" RC0402N1R 4484.56,1710.84 r0 top (schematic designator R1R)
R1R_IDL_17_12_TerA68 "330R" RC0402N1R 4484.56,1605.84 r0 top (schematic designator R1R)
R1R_IDL_17_12_TerA69 "330R" RC0402N1R 4484.56,1500.84 r0 top (schematic designator R1R)
R1R_IDL_17_12_TerA70 "330R" RC0402N1R 4484.56,1395.84 r0 top (schematic designator R1R)
R1R_IDL_17_12_TerA71 "330R" RC0402N1R 4484.56,1290.84 r0 top (schematic designator R1R)
R1R_IDL_17_12_TerA72 "330R" RC0402N1R 4484.58,1180.28 r0 top (schematic designator R1R)
R1RB_IDL_17_12_TerB1 "330R" RC0402N1R 3435.44,-1008.84 r0 top (schematic designator R1RB)
R1RB_IDL_17_12_TerB2 "330R" RC0402N1R 3436.13,-1116.31 r0 top (schematic designator R1RB)
R1RB_IDL_17_12_TerB3 "330R" RC0402N1R 3436.13,-1221.31 r0 top (schematic designator R1RB)
R1RB_IDL_17_12_TerB4 "330R" RC0402N1R 3436.13,-1321.31 r0 top (schematic designator R1RB)
R1RB_IDL_17_12_TerB5 "330R" RC0402N1R 3436.13,-1421.31 r0 top (schematic designator R1RB)
R1RB_IDL_17_12_TerB6 "330R" RC0402N1R 3436.13,-1521.31 r0 top (schematic designator R1RB)
R1RB_IDL_17_12_TerB7 "330R" RC0402N1R 3436.13,-1624.31 r0 top (schematic designator R1RB)
R1RB_IDL_17_12_TerB8 "330R" RC0402N1R 3436.13,-1724.31 r0 top (schematic designator R1RB)
R1RB_IDL_17_12_TerB9 "330R" RC0402N1R 3436.13,-1824.31 r0 top (schematic designator R1RB)
R1RB_IDL_17_12_TerB10 "330R" RC0402N1R 3436.13,-1924.31 r0 top (schematic designator R1RB)
R1RB_IDL_17_12_TerB11 "330R" RC0402N1R 3436.13,-2029.31 r0 top (schematic designator R1RB)
R1RB_IDL_17_12_TerB12 "330R" RC0402N1R 3436.13,-2129.31 r0 top (schematic designator R1RB)
R1RB_IDL_17_12_TerB13 "330R" RC0402N1R 3436.13,-2229.31 r0 top (schematic designator R1RB)
R1RB_IDL_17_12_TerB14 "330R" RC0402N1R 3436.13,-2329.31 r0 top (schematic designator R1RB)
R1RB_IDL_17_12_TerB15 "330R" RC0402N1R 3436.13,-2429.31 r0 top (schematic designator R1RB)
R1RB_IDL_17_12_TerB16 "330R" RC0402N1R 3436.13,-2534.31 r0 top (schematic designator R1RB)
R1RB_IDL_17_12_TerB17 "330R" RC0402N1R 3436.13,-2634.31 r0 top (schematic designator R1RB)
R1RB_IDL_17_12_TerB18 "330R" RC0402N1R 3436.13,-2734.31 r0 top (schematic designator R1RB)
R1RB_IDL_17_12_TerB19 "330R" RC0402N1R 3436.13,-2834.31 r0 top (schematic designator R1RB)
R1RB_IDL_17_12_TerB20 "330R" RC0402N1R 3436.13,-2939.31 r0 top (schematic designator R1RB)
R1RB_IDL_17_12_TerB21 "330R" RC0402N1R 3436.13,-3039.31 r0 top (schematic designator R1RB)
R1RB_IDL_17_12_TerB22 "330R" RC0402N1R 3436.13,-3137.31 r0 top (schematic designator R1RB)
R1RB_IDL_17_12_TerB23 "330R" RC0402N1R 3436.13,-3237.31 r0 top (schematic designator R1RB)
R1RB_IDL_17_12_TerB24 "330R" RC0402N1R 3436.13,-3342.31 r0 top (schematic designator R1RB)
R1RB_IDL_17_12_TerB25 "330R" RC0402N1R 3436.13,-3442.31 r0 top (schematic designator R1RB)
R1RB_IDL_17_12_TerB26 "330R" RC0402N1R 3436.13,-3542.31 r0 top (schematic designator R1RB)
R1RB_IDL_17_12_TerB27 "330R" RC0402N1R 3436.13,-3642.31 r0 top (schematic designator R1RB)
R1RB_IDL_17_12_TerB28 "330R" RC0402N1R 3436.13,-3742.31 r0 top (schematic designator R1RB)
R1RB_IDL_17_12_TerB29 "330R" RC0402N1R 3436.13,-3847.31 r0 top (schematic designator R1RB)
R1RB_IDL_17_12_TerB30 "330R" RC0402N1R 3436.13,-3947.31 r0 top (schematic designator R1RB)
R1RB_IDL_17_12_TerB31 "330R" RC0402N1R 3436.13,-4047.31 r0 top (schematic designator R1RB)
R1RB_IDL_17_12_TerB32 "330R" RC0402N1R 3435.73,-4156.37 r0 top (schematic designator R1RB)
R1RB_IDL_17_12_TerB33 "330R" RC0402N1R 3840.08,-1309.89 r0 top (schematic designator R1RB)
R1RB_IDL_17_12_TerB34 "330R" RC0402N1R 3840.08,-1409.89 r0 top (schematic designator R1RB)
R1RB_IDL_17_12_TerB35 "330R" RC0402N1R 3840.08,-1509.89 r0 top (schematic designator R1RB)
R1RB_IDL_17_12_TerB36 "330R" RC0402N1R 3840.08,-1609.89 r0 top (schematic designator R1RB)
R1RB_IDL_17_12_TerB37 "330R" RC0402N1R 3840.08,-1712.89 r0 top (schematic designator R1RB)
R1RB_IDL_17_12_TerB38 "330R" RC0402N1R 3840.08,-1812.89 r0 top (schematic designator R1RB)
R1RB_IDL_17_12_TerB39 "330R" RC0402N1R 3840.08,-1912.89 r0 top (schematic designator R1RB)
R1RB_IDL_17_12_TerB40 "330R" RC0402N1R 3835.08,-2094.54 r0 top (schematic designator R1RB)
R1RB_IDL_17_12_TerB41 "330R" RC0402N1R 3835.08,-2204.54 r0 top (schematic designator R1RB)
R1RB_IDL_17_12_TerB42 "330R" RC0402N1R 3835.08,-2309.54 r0 top (schematic designator R1RB)
R1RB_IDL_17_12_TerB43 "330R" RC0402N1R 3835.08,-2414.54 r0 top (schematic designator R1RB)
R1RB_IDL_17_12_TerB44 "330R" RC0402N1R 3835.08,-2519.54 r0 top (schematic designator R1RB)
R1RB_IDL_17_12_TerB45 "330R" RC0402N1R 3835.08,-2629.54 r0 top (schematic designator R1RB)
R1RB_IDL_17_12_TerB46 "330R" RC0402N1R 3835.08,-2734.54 r0 top (schematic designator R1RB)
R1RB_IDL_17_12_TerB47 "330R" RC0402N1R 3835.08,-2839.54 r0 top (schematic designator R1RB)
R1RB_IDL_17_12_TerB48 "330R" RC0402N1R 3830.08,-3109.54 r0 top (schematic designator R1RB)
R1RB_IDL_17_12_TerB49 "330R" RC0402N1R 3830.08,-3214.54 r0 top (schematic designator R1RB)
R1RB_IDL_17_12_TerB50 "330R" RC0402N1R 3830.08,-3314.54 r0 top (schematic designator R1RB)
R1RB_IDL_17_12_TerB51 "330R" RC0402N1R 3830.08,-3414.54 r0 top (schematic designator R1RB)
R1RB_IDL_17_12_TerB52 "330R" RC0402N1R 3830.08,-3512.54 r0 top (schematic designator R1RB)
R1RB_IDL_17_12_TerB53 "330R" RC0402N1R 3830.08,-3612.54 r0 top (schematic designator R1RB)
R1RB_IDL_17_12_TerB54 "330R" RC0402N1R 3830.08,-3717.54 r0 top (schematic designator R1RB)
R1RB_IDL_17_12_TerB55 "330R" RC0402N1R 3830.08,-3817.54 r0 top (schematic designator R1RB)
R1RB_IDL_17_12_TerB56 "330R" RC0402N1R 3830.08,-3917.54 r0 top (schematic designator R1RB)
R1RB_IDL_17_12_TerB57 "330R" RC0402N1R 3830.04,-4028.52 r0 top (schematic designator R1RB)
R1RB_IDL_17_12_TerB58 "330R" RC0402N1R 4379.81,-1108.25 r0 top (schematic designator R1RB)
R1RB_IDL_17_12_TerB59 "330R" RC0402N1R 4379.81,-1208.25 r0 top (schematic designator R1RB)
R1RB_IDL_17_12_TerB60 "330R" RC0402N1R 4379.81,-1313.25 r0 top (schematic designator R1RB)
R1RB_IDL_17_12_TerB61 "330R" RC0402N1R 4379.81,-1413.25 r0 top (schematic designator R1RB)
R1RB_IDL_17_12_TerB62 "330R" RC0402N1R 4379.81,-1513.25 r0 top (schematic designator R1RB)
R1RB_IDL_17_12_TerB63 "330R" RC0402N1R 4379.81,-1613.25 r0 top (schematic designator R1RB)
R1RB_IDL_17_12_TerB64 "330R" RC0402N1R 4379.81,-1718.25 r0 top (schematic designator R1RB)
R1RB_IDL_17_12_TerB65 "330R" RC0402N1R 4379.81,-1818.25 r0 top (schematic designator R1RB)
R1RB_IDL_17_12_TerB66 "330R" RC0402N1R 4379.81,-1918.25 r0 top (schematic designator R1RB)
R1RB_IDL_17_12_TerB67 "330R" RC0402N1R 4379.81,-2020.25 r0 top (schematic designator R1RB)
R1RB_IDL_17_12_TerB68 "330R" RC0402N1R 4379.81,-2125.25 r0 top (schematic designator R1RB)
R1RB_IDL_17_12_TerB69 "330R" RC0402N1R 4379.81,-2225.25 r0 top (schematic designator R1RB)
R1RB_IDL_17_12_TerB70 "330R" RC0402N1R 4379.81,-2325.25 r0 top (schematic designator R1RB)
R1RB_IDL_17_12_TerB71 "330R" RC0402N1R 4379.81,-2425.25 r0 top (schematic designator R1RB)
R1RB_IDL_17_12_TerB72 "330R" RC0402N1R 4379.81,-2525.25 r0 top (schematic designator R1RB)
R1RB_IDL_17_12_TerB73 "330R" RC0402N1R 4379.81,-2630.25 r0 top (schematic designator R1RB)
R1RB_IDL_17_12_TerB74 "330R" RC0402N1R 4379.81,-2730.25 r0 top (schematic designator R1RB)
R1RB_IDL_17_12_TerB75 "330R" RC0402N1R 4379.81,-2830.25 r0 top (schematic designator R1RB)
R1RB_IDL_17_12_TerB76 "330R" RC0402N1R 4379.81,-2930.25 r0 top (schematic designator R1RB)
R1RB_IDL_17_12_TerB77 "330R" RC0402N1R 4379.81,-3035.25 r0 top (schematic designator R1RB)
R1RB_IDL_17_12_TerB78 "330R" RC0402N1R 4379.81,-3135.25 r0 top (schematic designator R1RB)
R1RB_IDL_17_12_TerB79 "330R" RC0402N1R 4379.81,-3235.25 r0 top (schematic designator R1RB)
R1RB_IDL_17_12_TerB80 "330R" RC0402N1R 4379.81,-3335.25 r0 top (schematic designator R1RB)
R1RB_IDL_17_12_TerB81 "330R" RC0402N1R 4379.81,-3440.25 r0 top (schematic designator R1RB)
R1RB_IDL_17_12_TerB82 "330R" RC0402N1R 4379.81,-3542.25 r0 top (schematic designator R1RB)
R1RB_IDL_17_12_TerB83 "330R" RC0402N1R 4379.81,-3642.25 r0 top (schematic designator R1RB)
R1RB_IDL_17_12_TerB84 "330R" RC0402N1R 4379.81,-3742.25 r0 top (schematic designator R1RB)
R1RB_IDL_17_12_TerB85 "330R" RC0402N1R 4379.81,-3842.25 r0 top (schematic designator R1RB)
R1RB_IDL_17_12_TerB86 "330R" RC0402N1R 4379.81,-3947.25 r0 top (schematic designator R1RB)
R1RB_IDL_17_12_TerB87 "330R" RC0402N1R 4379.81,-4047.25 r0 top (schematic designator R1RB)
R1RB_IDL_17_12_TerB88 "330R" RC0402N1R 4379.81,-4147.25 r0 top (schematic designator R1RB)
R1RB_IDL_17_12_TerB89 "330R" RC0402N1R 4381.76,-4262.25 r0 top (schematic designator R1RB)
R2R_IDL_17_12_TerA1 "470R" RC0402N1R 3322.61,3981.81 r180 top (schematic designator R2R)
R2R_IDL_17_12_TerA2 "470R" RC0402N1R 3317.61,3870.57 r180 top (schematic designator R2R)
R2R_IDL_17_12_TerA3 "470R" RC0402N1R 3317.61,3765.57 r180 top (schematic designator R2R)
R2R_IDL_17_12_TerA4 "470R" RC0402N1R 3317.61,3660.57 r180 top (schematic designator R2R)
R2R_IDL_17_12_TerA5 "470R" RC0402N1R 3317.61,3555.57 r180 top (schematic designator R2R)
R2R_IDL_17_12_TerA6 "470R" RC0402N1R 3317.61,3450.57 r180 top (schematic designator R2R)
R2R_IDL_17_12_TerA7 "470R" RC0402N1R 3317.61,3345.57 r180 top (schematic designator R2R)
R2R_IDL_17_12_TerA8 "470R" RC0402N1R 3317.61,3240.57 r180 top (schematic designator R2R)
R2R_IDL_17_12_TerA9 "470R" RC0402N1R 3317.61,2975.57 r180 top (schematic designator R2R)
R2R_IDL_17_12_TerA10 "470R" RC0402N1R 3317.61,2775.57 r180 top (schematic designator R2R)
R2R_IDL_17_12_TerA11 "470R" RC0402N1R 3317.61,2580.57 r180 top (schematic designator R2R)
R2R_IDL_17_12_TerA12 "470R" RC0402N1R 3317.24,2397.36 r180 top (schematic designator R2R)
R2R_IDL_17_12_TerA13 "470R" RC0402N1R 3317.24,2292.36 r180 top (schematic designator R2R)
R2R_IDL_17_12_TerA14 "470R" RC0402N1R 3317.24,2187.36 r180 top (schematic designator R2R)
R2R_IDL_17_12_TerA15 "470R" RC0402N1R 3323.25,1967.42 r180 top (schematic designator R2R)
R2R_IDL_17_12_TerA16 "470R" RC0402N1R 3475.52,1798.05 r180 top (schematic designator R2R)
R2R_IDL_17_12_TerA17 "470R" RC0402N1R 3475.52,1695.05 r180 top (schematic designator R2R)
R2R_IDL_17_12_TerA18 "470R" RC0402N1R 3475.52,1590.05 r180 top (schematic designator R2R)
R2R_IDL_17_12_TerA19 "470R" RC0402N1R 3475.52,1485.05 r180 top (schematic designator R2R)
R2R_IDL_17_12_TerA20 "470R" RC0402N1R 3475.52,1380.05 r180 top (schematic designator R2R)
R2R_IDL_17_12_TerA21 "470R" RC0402N1R 3475.52,1275.05 r180 top (schematic designator R2R)
R2R_IDL_17_12_TerA22 "470R" RC0402N1R 3475.52,1170.05 r180 top (schematic designator R2R)
R2R_IDL_17_12_TerA23 "470R" RC0402N1R 3475.52,1065.05 r180 top (schematic designator R2R)
R2R_IDL_17_12_TerA24 "470R" RC0402N1R 3900.16,4089.16 r180 top (schematic designator R2R)
R2R_IDL_17_12_TerA25 "470R" RC0402N1R 3900.16,3984.16 r180 top (schematic designator R2R)
R2R_IDL_17_12_TerA26 "470R" RC0402N1R 3900.16,3879.16 r180 top (schematic designator R2R)
R2R_IDL_17_12_TerA27 "470R" RC0402N1R 3900.16,3774.16 r180 top (schematic designator R2R)
R2R_IDL_17_12_TerA28 "470R" RC0402N1R 3900.16,3669.16 r180 top (schematic designator R2R)
R2R_IDL_17_12_TerA29 "470R" RC0402N1R 3900.16,3564.16 r180 top (schematic designator R2R)
R2R_IDL_17_12_TerA30 "470R" RC0402N1R 3900.16,3459.16 r180 top (schematic designator R2R)
R2R_IDL_17_12_TerA31 "470R" RC0402N1R 3900.16,3354.16 r180 top (schematic designator R2R)
R2R_IDL_17_12_TerA32 "470R" RC0402N1R 3900.16,3246.16 r180 top (schematic designator R2R)
R2R_IDL_17_12_TerA33 "470R" RC0402N1R 3900.16,2971.16 r180 top (schematic designator R2R)
R2R_IDL_17_12_TerA34 "470R" RC0402N1R 3900.16,2866.16 r180 top (schematic designator R2R)
R2R_IDL_17_12_TerA35 "470R" RC0402N1R 3900.16,2761.16 r180 top (schematic designator R2R)
R2R_IDL_17_12_TerA36 "470R" RC0402N1R 3900.16,2656.16 r180 top (schematic designator R2R)
R2R_IDL_17_12_TerA37 "470R" RC0402N1R 3900.16,2551.16 r180 top (schematic designator R2R)
R2R_IDL_17_12_TerA38 "470R" RC0402N1R 3900.16,2446.16 r180 top (schematic designator R2R)
R2R_IDL_17_12_TerA39 "470R" RC0402N1R 3900.16,2341.16 r180 top (schematic designator R2R)
R2R_IDL_17_12_TerA40 "470R" RC0402N1R 3900.16,2236.16 r180 top (schematic designator R2R)
R2R_IDL_17_12_TerA41 "470R" RC0402N1R 3906.06,1350.63 r180 top (schematic designator R2R)
R2R_IDL_17_12_TerA42 "470R" RC0402N1R 3906.06,1250.63 r180 top (schematic designator R2R)
R2R_IDL_17_12_TerA43 "470R" RC0402N1R 3905.99,1127.66 r180 top (schematic designator R2R)
R2R_IDL_17_12_TerA44 "470R" RC0402N1R 4485.44,4071.82 r180 top (schematic designator R2R)
R2R_IDL_17_12_TerA45 "470R" RC0402N1R 4485.44,3966.82 r180 top (schematic designator R2R)
R2R_IDL_17_12_TerA46 "470R" RC0402N1R 4485.44,3861.82 r180 top (schematic designator R2R)
R2R_IDL_17_12_TerA47 "470R" RC0402N1R 4485.44,3758.82 r180 top (schematic designator R2R)
R2R_IDL_17_12_TerA48 "470R" RC0402N1R 4485.44,3653.82 r180 top (schematic designator R2R)
R2R_IDL_17_12_TerA49 "470R" RC0402N1R 4485.44,3548.82 r180 top (schematic designator R2R)
R2R_IDL_17_12_TerA50 "470R" RC0402N1R 4485.44,3443.82 r180 top (schematic designator R2R)
R2R_IDL_17_12_TerA51 "470R" RC0402N1R 4485.44,3338.82 r180 top (schematic designator R2R)
R2R_IDL_17_12_TerA52 "470R" RC0402N1R 4485.44,3233.82 r180 top (schematic designator R2R)
R2R_IDL_17_12_TerA53 "470R" RC0402N1R 4485.44,3128.82 r180 top (schematic designator R2R)
R2R_IDL_17_12_TerA54 "470R" RC0402N1R 4485.44,3023.82 r180 top (schematic designator R2R)
R2R_IDL_17_12_TerA55 "470R" RC0402N1R 4485.44,2918.82 r180 top (schematic designator R2R)
R2R_IDL_17_12_TerA56 "470R" RC0402N1R 4485.44,2813.82 r180 top (schematic designator R2R)
R2R_IDL_17_12_TerA57 "470R" RC0402N1R 4485.44,2708.82 r180 top (schematic designator R2R)
R2R_IDL_17_12_TerA58 "470R" RC0402N1R 4485.44,2603.82 r180 top (schematic designator R2R)
R2R_IDL_17_12_TerA59 "470R" RC0402N1R 4485.44,2498.82 r180 top (schematic designator R2R)
R2R_IDL_17_12_TerA60 "470R" RC0402N1R 4485.44,2393.82 r180 top (schematic designator R2R)
R2R_IDL_17_12_TerA61 "470R" RC0402N1R 4485.44,2288.82 r180 top (schematic designator R2R)
R2R_IDL_17_12_TerA62 "470R" RC0402N1R 4485.44,2180.82 r180 top (schematic designator R2R)
R2R_IDL_17_12_TerA63 "470R" RC0402N1R 4485.44,2075.82 r180 top (schematic designator R2R)
R2R_IDL_17_12_TerA64 "470R" RC0402N1R 4485.44,1970.82 r180 top (schematic designator R2R)
R2R_IDL_17_12_TerA65 "470R" RC0402N1R 4485.44,1865.82 r180 top (schematic designator R2R)
R2R_IDL_17_12_TerA66 "470R" RC0402N1R 4485.44,1760.82 r180 top (schematic designator R2R)
R2R_IDL_17_12_TerA67 "470R" RC0402N1R 4485.44,1655.82 r180 top (schematic designator R2R)
R2R_IDL_17_12_TerA68 "470R" RC0402N1R 4485.44,1550.82 r180 top (schematic designator R2R)
R2R_IDL_17_12_TerA69 "470R" RC0402N1R 4485.44,1445.82 r180 top (schematic designator R2R)
R2R_IDL_17_12_TerA70 "470R" RC0402N1R 4485.44,1340.82 r180 top (schematic designator R2R)
R2R_IDL_17_12_TerA71 "470R" RC0402N1R 4485.44,1235.82 r180 top (schematic designator R2R)
R2R_IDL_17_12_TerA72 "470R" RC0402N1R 4484.31,1125.78 r180 top (schematic designator R2R)
R2RB_IDL_17_12_TerB1 "470R" RC0402N1R 3435.95,-1061.69 r180 top (schematic designator R2RB)
R2RB_IDL_17_12_TerB2 "470R" RC0402N1R 3436.64,-1169.17 r180 top (schematic designator R2RB)
R2RB_IDL_17_12_TerB3 "470R" RC0402N1R 3436.64,-1274.17 r180 top (schematic designator R2RB)
R2RB_IDL_17_12_TerB4 "470R" RC0402N1R 3436.64,-1374.17 r180 top (schematic designator R2RB)
R2RB_IDL_17_12_TerB5 "470R" RC0402N1R 3436.64,-1474.17 r180 top (schematic designator R2RB)
R2RB_IDL_17_12_TerB6 "470R" RC0402N1R 3436.64,-1574.17 r180 top (schematic designator R2RB)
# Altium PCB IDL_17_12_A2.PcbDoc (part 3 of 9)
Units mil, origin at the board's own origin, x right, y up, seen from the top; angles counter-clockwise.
Board outline 5119.97 x 10350 mil, 6 copper layers (Top Signal, 3.3 Volt, GND, 5 Volt, Split Plane, Bot Signal), stack 66.2 mil thick; 514 components, 178 nets, 2321 pads, 427 vias.

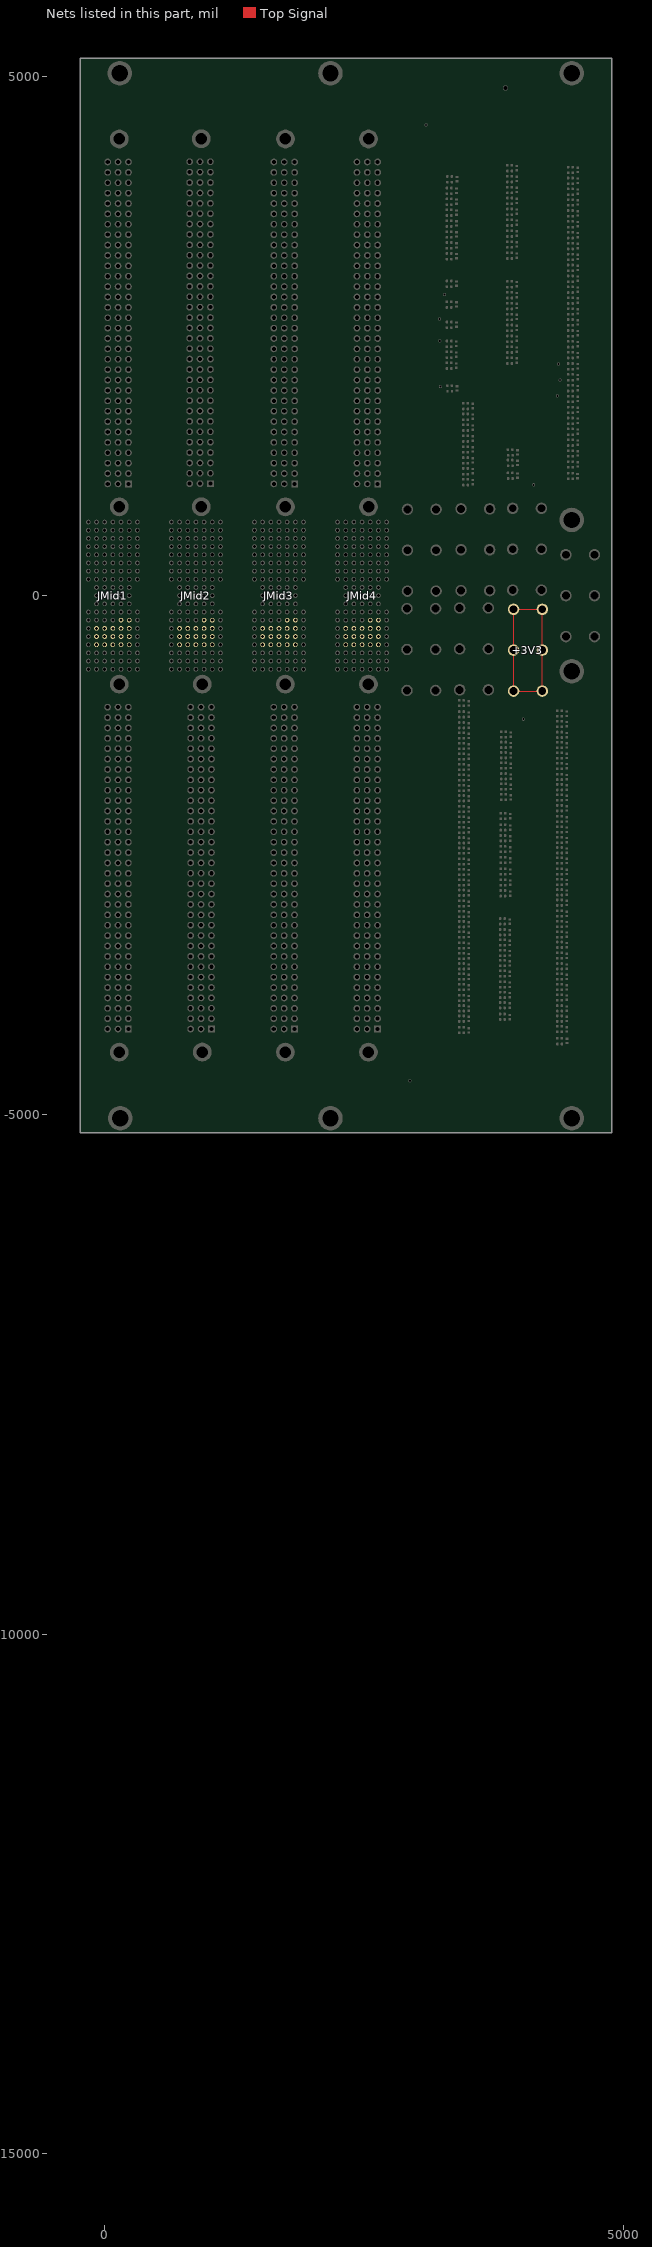
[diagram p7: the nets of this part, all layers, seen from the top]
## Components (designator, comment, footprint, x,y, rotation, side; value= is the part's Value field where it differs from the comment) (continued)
R2RB_IDL_17_12_TerB7 "470R" RC0402N1R 3436.64,-1677.17 r180 top (schematic designator R2RB)
R2RB_IDL_17_12_TerB8 "470R" RC0402N1R 3436.64,-1777.17 r180 top (schematic designator R2RB)
R2RB_IDL_17_12_TerB9 "470R" RC0402N1R 3436.64,-1877.17 r180 top (schematic designator R2RB)
R2RB_IDL_17_12_TerB10 "470R" RC0402N1R 3436.64,-1977.17 r180 top (schematic designator R2RB)
R2RB_IDL_17_12_TerB11 "470R" RC0402N1R 3436.64,-2082.17 r180 top (schematic designator R2RB)
R2RB_IDL_17_12_TerB12 "470R" RC0402N1R 3436.64,-2182.17 r180 top (schematic designator R2RB)
R2RB_IDL_17_12_TerB13 "470R" RC0402N1R 3436.64,-2282.17 r180 top (schematic designator R2RB)
R2RB_IDL_17_12_TerB14 "470R" RC0402N1R 3436.64,-2382.17 r180 top (schematic designator R2RB)
R2RB_IDL_17_12_TerB15 "470R" RC0402N1R 3436.64,-2482.17 r180 top (schematic designator R2RB)
R2RB_IDL_17_12_TerB16 "470R" RC0402N1R 3436.64,-2587.17 r180 top (schematic designator R2RB)
R2RB_IDL_17_12_TerB17 "470R" RC0402N1R 3436.64,-2687.17 r180 top (schematic designator R2RB)
R2RB_IDL_17_12_TerB18 "470R" RC0402N1R 3436.64,-2787.17 r180 top (schematic designator R2RB)
R2RB_IDL_17_12_TerB19 "470R" RC0402N1R 3436.64,-2887.17 r180 top (schematic designator R2RB)
R2RB_IDL_17_12_TerB20 "470R" RC0402N1R 3436.64,-2992.17 r180 top (schematic designator R2RB)
R2RB_IDL_17_12_TerB21 "470R" RC0402N1R 3436.64,-3092.17 r180 top (schematic designator R2RB)
R2RB_IDL_17_12_TerB22 "470R" RC0402N1R 3436.64,-3190.17 r180 top (schematic designator R2RB)
R2RB_IDL_17_12_TerB23 "470R" RC0402N1R 3436.64,-3290.17 r180 top (schematic designator R2RB)
R2RB_IDL_17_12_TerB24 "470R" RC0402N1R 3436.64,-3395.17 r180 top (schematic designator R2RB)
R2RB_IDL_17_12_TerB25 "470R" RC0402N1R 3436.64,-3495.17 r180 top (schematic designator R2RB)
R2RB_IDL_17_12_TerB26 "470R" RC0402N1R 3436.64,-3595.17 r180 top (schematic designator R2RB)
R2RB_IDL_17_12_TerB27 "470R" RC0402N1R 3436.64,-3695.17 r180 top (schematic designator R2RB)
R2RB_IDL_17_12_TerB28 "470R" RC0402N1R 3436.64,-3795.17 r180 top (schematic designator R2RB)
R2RB_IDL_17_12_TerB29 "470R" RC0402N1R 3436.64,-3900.17 r180 top (schematic designator R2RB)
R2RB_IDL_17_12_TerB30 "470R" RC0402N1R 3436.64,-4000.17 r180 top (schematic designator R2RB)
R2RB_IDL_17_12_TerB31 "470R" RC0402N1R 3436.64,-4100.17 r180 top (schematic designator R2RB)
R2RB_IDL_17_12_TerB32 "470R" RC0402N1R 3436.24,-4209.23 r180 top (schematic designator R2RB)
R2RB_IDL_17_12_TerB33 "470R" RC0402N1R 3840.59,-1362.75 r180 top (schematic designator R2RB)
R2RB_IDL_17_12_TerB34 "470R" RC0402N1R 3840.59,-1462.75 r180 top (schematic designator R2RB)
R2RB_IDL_17_12_TerB35 "470R" RC0402N1R 3840.59,-1562.75 r180 top (schematic designator R2RB)
R2RB_IDL_17_12_TerB36 "470R" RC0402N1R 3840.59,-1662.75 r180 top (schematic designator R2RB)
R2RB_IDL_17_12_TerB37 "470R" RC0402N1R 3840.59,-1765.75 r180 top (schematic designator R2RB)
R2RB_IDL_17_12_TerB38 "470R" RC0402N1R 3840.59,-1865.75 r180 top (schematic designator R2RB)
R2RB_IDL_17_12_TerB39 "470R" RC0402N1R 3840.59,-1965.75 r180 top (schematic designator R2RB)
R2RB_IDL_17_12_TerB40 "470R" RC0402N1R 3835.59,-2147.4 r180 top (schematic designator R2RB)
R2RB_IDL_17_12_TerB41 "470R" RC0402N1R 3835.59,-2257.4 r180 top (schematic designator R2RB)
R2RB_IDL_17_12_TerB42 "470R" RC0402N1R 3835.59,-2362.4 r180 top (schematic designator R2RB)
R2RB_IDL_17_12_TerB43 "470R" RC0402N1R 3835.59,-2467.4 r180 top (schematic designator R2RB)
R2RB_IDL_17_12_TerB44 "470R" RC0402N1R 3835.59,-2572.4 r180 top (schematic designator R2RB)
R2RB_IDL_17_12_TerB45 "470R" RC0402N1R 3835.59,-2682.4 r180 top (schematic designator R2RB)
R2RB_IDL_17_12_TerB46 "470R" RC0402N1R 3835.59,-2787.4 r180 top (schematic designator R2RB)
R2RB_IDL_17_12_TerB47 "470R" RC0402N1R 3835.59,-2892.4 r180 top (schematic designator R2RB)
R2RB_IDL_17_12_TerB48 "470R" RC0402N1R 3830.59,-3162.4 r180 top (schematic designator R2RB)
R2RB_IDL_17_12_TerB49 "470R" RC0402N1R 3830.59,-3267.4 r180 top (schematic designator R2RB)
R2RB_IDL_17_12_TerB50 "470R" RC0402N1R 3830.59,-3367.4 r180 top (schematic designator R2RB)
R2RB_IDL_17_12_TerB51 "470R" RC0402N1R 3830.59,-3467.4 r180 top (schematic designator R2RB)
R2RB_IDL_17_12_TerB52 "470R" RC0402N1R 3830.59,-3565.4 r180 top (schematic designator R2RB)
R2RB_IDL_17_12_TerB53 "470R" RC0402N1R 3830.59,-3665.4 r180 top (schematic designator R2RB)
R2RB_IDL_17_12_TerB54 "470R" RC0402N1R 3830.59,-3770.4 r180 top (schematic designator R2RB)
R2RB_IDL_17_12_TerB55 "470R" RC0402N1R 3830.59,-3870.4 r180 top (schematic designator R2RB)
R2RB_IDL_17_12_TerB56 "470R" RC0402N1R 3830.59,-3970.4 r180 top (schematic designator R2RB)
R2RB_IDL_17_12_TerB57 "470R" RC0402N1R 3830.55,-4081.38 r180 top (schematic designator R2RB)
R2RB_IDL_17_12_TerB58 "470R" RC0402N1R 4380.33,-1161.11 r180 top (schematic designator R2RB)
R2RB_IDL_17_12_TerB59 "470R" RC0402N1R 4380.33,-1261.11 r180 top (schematic designator R2RB)
R2RB_IDL_17_12_TerB60 "470R" RC0402N1R 4380.33,-1366.11 r180 top (schematic designator R2RB)
R2RB_IDL_17_12_TerB61 "470R" RC0402N1R 4380.33,-1466.11 r180 top (schematic designator R2RB)
R2RB_IDL_17_12_TerB62 "470R" RC0402N1R 4380.33,-1566.11 r180 top (schematic designator R2RB)
R2RB_IDL_17_12_TerB63 "470R" RC0402N1R 4380.33,-1666.11 r180 top (schematic designator R2RB)
R2RB_IDL_17_12_TerB64 "470R" RC0402N1R 4380.33,-1771.11 r180 top (schematic designator R2RB)
R2RB_IDL_17_12_TerB65 "470R" RC0402N1R 4380.33,-1871.11 r180 top (schematic designator R2RB)
R2RB_IDL_17_12_TerB66 "470R" RC0402N1R 4380.33,-1971.11 r180 top (schematic designator R2RB)
R2RB_IDL_17_12_TerB67 "470R" RC0402N1R 4380.33,-2073.11 r180 top (schematic designator R2RB)
R2RB_IDL_17_12_TerB68 "470R" RC0402N1R 4380.33,-2178.11 r180 top (schematic designator R2RB)
R2RB_IDL_17_12_TerB69 "470R" RC0402N1R 4380.33,-2278.11 r180 top (schematic designator R2RB)
R2RB_IDL_17_12_TerB70 "470R" RC0402N1R 4380.33,-2378.11 r180 top (schematic designator R2RB)
R2RB_IDL_17_12_TerB71 "470R" RC0402N1R 4380.33,-2478.11 r180 top (schematic designator R2RB)
R2RB_IDL_17_12_TerB72 "470R" RC0402N1R 4380.33,-2578.11 r180 top (schematic designator R2RB)
R2RB_IDL_17_12_TerB73 "470R" RC0402N1R 4380.33,-2683.11 r180 top (schematic designator R2RB)
R2RB_IDL_17_12_TerB74 "470R" RC0402N1R 4380.33,-2783.11 r180 top (schematic designator R2RB)
R2RB_IDL_17_12_TerB75 "470R" RC0402N1R 4380.33,-2883.11 r180 top (schematic designator R2RB)
R2RB_IDL_17_12_TerB76 "470R" RC0402N1R 4380.33,-2983.11 r180 top (schematic designator R2RB)
R2RB_IDL_17_12_TerB77 "470R" RC0402N1R 4380.33,-3088.11 r180 top (schematic designator R2RB)
R2RB_IDL_17_12_TerB78 "470R" RC0402N1R 4380.33,-3188.11 r180 top (schematic designator R2RB)
R2RB_IDL_17_12_TerB79 "470R" RC0402N1R 4380.33,-3288.11 r180 top (schematic designator R2RB)
R2RB_IDL_17_12_TerB80 "470R" RC0402N1R 4380.33,-3388.11 r180 top (schematic designator R2RB)
R2RB_IDL_17_12_TerB81 "470R" RC0402N1R 4380.33,-3493.11 r180 top (schematic designator R2RB)
R2RB_IDL_17_12_TerB82 "470R" RC0402N1R 4380.33,-3595.11 r180 top (schematic designator R2RB)
R2RB_IDL_17_12_TerB83 "470R" RC0402N1R 4380.33,-3695.11 r180 top (schematic designator R2RB)
R2RB_IDL_17_12_TerB84 "470R" RC0402N1R 4380.33,-3795.11 r180 top (schematic designator R2RB)
R2RB_IDL_17_12_TerB85 "470R" RC0402N1R 4380.33,-3895.11 r180 top (schematic designator R2RB)
R2RB_IDL_17_12_TerB86 "470R" RC0402N1R 4380.33,-4000.11 r180 top (schematic designator R2RB)
R2RB_IDL_17_12_TerB87 "470R" RC0402N1R 4380.33,-4100.11 r180 top (schematic designator R2RB)
R2RB_IDL_17_12_TerB88 "470R" RC0402N1R 4380.33,-4200.11 r180 top (schematic designator R2RB)
R2RB_IDL_17_12_TerB89 "470R" RC0402N1R 4381.73,-4317.34 r180 top (schematic designator R2RB)
SYSCLK "Comment" TPH0.5S#1 3232.47,2013.01 r180 top
SYSFAIL "Comment" TPH0.5S#1 4359.11,1923.62 r0 top
SYSRESET "Comment" TPH0.5S#1 4369.31,2230.12 r0 top
WRITE "Comment" TPH0.5S#1 3226.9,2453.31 r0 top

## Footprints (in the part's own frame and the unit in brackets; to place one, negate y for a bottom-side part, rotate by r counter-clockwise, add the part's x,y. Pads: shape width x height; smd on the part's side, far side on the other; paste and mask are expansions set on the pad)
"127-Pin Conncector" [mil] "Har-Bus male connector type AB-19"
  round 45 hole 30: 1(-732.28,-240.16) 2(-653.54,-240.16) 3(-574.8,-240.16) 4(-496.06,-240.16) 5(-417.32,-240.16) 6(-338.58,-240.16) 7(-259.84,-240.16) 8(-181.1,-240.16) 9(133.86,-240.16) 10(212.6,-240.16) 11(291.34,-240.16) 12(370.08,-240.16) 13(448.82,-240.16) 14(527.56,-240.16) 15(606.3,-240.16) 16(685.04,-240.16) 17(-732.28,-161.42) 18(-653.54,-161.42) 19(-574.8,-161.42) 20(-496.06,-161.42) 21(-417.32,-161.42) 22(-338.58,-161.42) 23(-259.84,-161.42) 24(-181.1,-161.42) 25(-102.36,-161.42) 26(-23.62,-161.42) 27(55.12,-161.42) 28(133.86,-161.42) 29(212.6,-161.42) 30(291.34,-161.42) 31(370.08,-161.42) 32(448.82,-161.42) 33(527.56,-161.42) 34(606.3,-161.42) 35(685.04,-161.42) 36(-732.28,-82.68) 37(-653.54,-82.68) 38(-574.8,-82.68) 39(-496.06,-82.68) 40(-417.32,-82.68) 41(-338.58,-82.68) 42(-259.84,-82.68) 43(-181.1,-82.68) 44(-102.36,-82.68) 45(-23.62,-82.68) 46(55.12,-82.68) 47(133.86,-82.68) 48(212.6,-82.68) 49(291.34,-82.68) 50(370.08,-82.68) 51(448.82,-82.68) 52(527.56,-82.68) 53(606.3,-82.68) 54(685.04,-82.68) 55(-732.28,-3.94) 56(-653.54,-3.94) 57(-574.8,-3.94) 58(-496.06,-3.94) 59(-417.32,-3.94) 60(-338.58,-3.94) 61(-259.84,-3.94) 62(-181.1,-3.94) 63(-102.36,-3.94) 64(-23.62,-3.94) 65(55.12,-3.94) 66(133.86,-3.94) 67(212.6,-3.94) 68(291.34,-3.94) 69(370.08,-3.94) 70(448.82,-3.94) 71(527.56,-3.94) 72(606.3,-3.94) 73(685.04,-3.94) 74(-732.28,74.8) 75(-653.54,74.8) 76(-574.8,74.8) 77(-496.06,74.8) 78(-417.32,74.8) 79(-338.58,74.8) 80(-259.84,74.8) 81(-181.1,74.8) 82(-102.36,74.8) 83(-23.62,74.8) 84(55.12,74.8) 85(133.86,74.8) 86(212.6,74.8) 87(291.34,74.8) 88(370.08,74.8) 89(448.82,74.8) 90(527.56,74.8) 91(606.3,74.8) 92(685.04,74.8) 93(-732.28,153.54) 94(-653.54,153.54) 95(-574.8,153.54) 96(-496.06,153.54) 97(-417.32,153.54) 98(-338.58,153.54) 99(-259.84,153.54) 100(-181.1,153.54) 101(-102.36,153.54) 102(-23.62,153.54) 103(55.12,153.54) 104(133.86,153.54) 105(212.6,153.54) 106(291.34,153.54) 107(370.08,153.54) 108(448.82,153.54) 109(527.56,153.54) 110(606.3,153.54) 111(685.04,153.54) 112(-732.28,232.28) 113(-653.54,232.28) 114(-574.8,232.28) 115(-496.06,232.28) 116(-417.32,232.28) 117(-338.58,232.28) 118(-259.84,232.28) 119(-181.1,232.28) 120(133.86,232.28) 121(212.6,232.28) 122(291.34,232.28) 123(370.08,232.28) 124(448.82,232.28) 125(527.56,232.28) 126(606.3,232.28) 127(685.04,232.28)
  Top Signal lines w7.87: -771.65,299.21 -771.65,-307.09 724.41,-307.09 724.41,299.21 -771.65,299.21
  body extent -732,-276 685,276, height 528
0903296x825 [mm] "Connector; DIN 41612, Type C, Thru-Hole; Rows a+b+c, 96 Position; Vertical"
  round 4.6 hole 2.8: 33(-45,-0.3) 34(45,-0.3)
  rect 1.65x1.65 hole 1: A1(-39.37,-2.54)
  round 1.65 hole 1: A2(-36.83,-2.54) A3(-34.29,-2.54) A4(-31.75,-2.54) A5(-29.21,-2.54) A6(-26.67,-2.54) A7(-24.13,-2.54) A8(-21.59,-2.54) A9(-19.05,-2.54) A10(-16.51,-2.54) A11(-13.97,-2.54) A12(-11.43,-2.54) A13(-8.89,-2.54) A14(-6.35,-2.54) A15(-3.81,-2.54) A16(-1.27,-2.54) A17(1.27,-2.54) A18(3.81,-2.54) A19(6.35,-2.54) A20(8.89,-2.54) A21(11.43,-2.54) A22(13.97,-2.54) A23(16.51,-2.54) A24(19.05,-2.54) A25(21.59,-2.54) A26(24.13,-2.54) A27(26.67,-2.54) A28(29.21,-2.54) A29(31.75,-2.54) A30(34.29,-2.54) A31(36.83,-2.54) A32(39.37,-2.54) B1(-39.37,0) B2(-36.83,0) B3(-34.29,0) B4(-31.75,0) B5(-29.21,0) B6(-26.67,0) B7(-24.13,0) B8(-21.59,0) B9(-19.05,0) B10(-16.51,0) B11(-13.97,0) B12(-11.43,0) B13(-8.89,0) B14(-6.35,0) B15(-3.81,0) B16(-1.27,0) B17(1.27,0) B18(3.81,0) B19(6.35,0) B20(8.89,0) B21(11.43,0) B22(13.97,0) B23(16.51,0) B24(19.05,0) B25(21.59,0) B26(24.13,0) B27(26.67,0) B28(29.21,0) B29(31.75,0) B30(34.29,0) B31(36.83,0) B32(39.37,0) C1(-39.37,2.54) C2(-36.83,2.54) C3(-34.29,2.54) C4(-31.75,2.54) C5(-29.21,2.54) C6(-26.67,2.54) C7(-24.13,2.54) C8(-21.59,2.54) C9(-19.05,2.54) C10(-16.51,2.54) C11(-13.97,2.54) C12(-11.43,2.54) C13(-8.89,2.54) C14(-6.35,2.54) C15(-3.81,2.54) C16(-1.27,2.54) C17(1.27,2.54) C18(3.81,2.54) C19(6.35,2.54) C20(8.89,2.54) C21(11.43,2.54) C22(13.97,2.54) C23(16.51,2.54) C24(19.05,2.54) C25(21.59,2.54) C26(24.13,2.54) C27(26.67,2.54) C28(29.21,2.54) C29(31.75,2.54) C30(34.29,2.54) C31(36.83,2.54) C32(39.37,2.54)
  silkscreen extent -47.5,-5.55 47.5,5.55
CC0402N1X [mm] "Chip capacitor 0402"
  rect 0.55x0.65 smd mask+0.025: 1(-0.525,0) 2(0.525,0)
  silkscreen extent 0,-0.25 0,0.25, body extent -0.51,-0.25 0.51,0.25, height 0.5
PowerTap [mil] "Power Tap 6 pin"
  round 110 hole 76: 1(0,0) 2(0,-276) 3(394,0) 4(788,0) 5(394,-276) 6(788,-276)
  Top Signal lines w10: 0,0 0,-276 394,-276 788,-276 788,0 394,0 0,0
  body extent 0,-276 788,0, height 453
RC0402N1R [mm] "Chip capacitor 0402 ROUNDED PAD"
  rrect50% 0.6x0.65 smd: 1(-0.55,0) 2(0.55,0)
  silkscreen extent 0,-0.25 0,0.25, body extent -0.51,-0.25 0.51,0.25, height 0.36
TPH0.5S#1 [mil] "Test point TH 0.5mm slim"
  round 30 hole 19.68: 1(0,0)
  silkscreen extent -25,-25 25,25
TPH0.5S#2 [mil] "Test point TH 0.5mm slim"
  round 50 hole 39.37: 1(0,0)
  silkscreen extent -40,-40 40,40

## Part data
+3V3 +5V -3V3 -5V -12V GND PT5: library part PowerTap, "Power tap 6 pin", Manufacturer="Keystone Electronics", Part No.=8197, Supplier Part Number 1=36-8197-ND
CR_IDL_17_12_TerA1 CR_IDL_17_12_TerA2 CR_IDL_17_12_TerA3 CR_IDL_17_12_TerA4 CR_IDL_17_12_TerA5 CR_IDL_17_12_TerA6 CR_IDL_17_12_TerA7 CR_IDL_17_12_TerA8 CR_IDL_17_12_TerA9 CR_IDL_17_12_TerA10 CR_IDL_17_12_TerA11 CR_IDL_17_12_TerA12 CR_IDL_17_12_TerA13 CR_IDL_17_12_TerA14 CR_IDL_17_12_TerA15 CR_IDL_17_12_TerA16 CR_IDL_17_12_TerA17 CR_IDL_17_12_TerA18 CR_IDL_17_12_TerA19 CR_IDL_17_12_TerA20 CR_IDL_17_12_TerA21 CR_IDL_17_12_TerA22 CR_IDL_17_12_TerA23 CR_IDL_17_12_TerA24 CR_IDL_17_12_TerA25 CR_IDL_17_12_TerA26 CR_IDL_17_12_TerA27 CR_IDL_17_12_TerA28 CR_IDL_17_12_TerA29 CR_IDL_17_12_TerA30 CR_IDL_17_12_TerA31 CR_IDL_17_12_TerA32 CR_IDL_17_12_TerA33 CR_IDL_17_12_TerA34 CR_IDL_17_12_TerA35 CR_IDL_17_12_TerA36 CR_IDL_17_12_TerA37 CR_IDL_17_12_TerA38 CR_IDL_17_12_TerA39 CR_IDL_17_12_TerA40 CR_IDL_17_12_TerA41 CR_IDL_17_12_TerA42 CR_IDL_17_12_TerA43 CR_IDL_17_12_TerA44 CR_IDL_17_12_TerA45 CR_IDL_17_12_TerA46 CR_IDL_17_12_TerA47 CR_IDL_17_12_TerA48 CR_IDL_17_12_TerA49 CR_IDL_17_12_TerA50 CR_IDL_17_12_TerA51 CR_IDL_17_12_TerA52 CR_IDL_17_12_TerA53 CR_IDL_17_12_TerA54 CR_IDL_17_12_TerA55 CR_IDL_17_12_TerA56 CR_IDL_17_12_TerA57 CR_IDL_17_12_TerA58 CR_IDL_17_12_TerA59 CR_IDL_17_12_TerA60 CR_IDL_17_12_TerA61 CR_IDL_17_12_TerA62 CR_IDL_17_12_TerA63 CR_IDL_17_12_TerA64 CR_IDL_17_12_TerA65 CR_IDL_17_12_TerA66 CR_IDL_17_12_TerA67 CR_IDL_17_12_TerA68 CR_IDL_17_12_TerA69 CR_IDL_17_12_TerA70 CR_IDL_17_12_TerA71 CR_IDL_17_12_TerA72 CRB_IDL_17_12_TerB1 CRB_IDL_17_12_TerB2 CRB_IDL_17_12_TerB3 CRB_IDL_17_12_TerB4 CRB_IDL_17_12_TerB5 CRB_IDL_17_12_TerB6 CRB_IDL_17_12_TerB7 CRB_IDL_17_12_TerB8 CRB_IDL_17_12_TerB9 CRB_IDL_17_12_TerB10 CRB_IDL_17_12_TerB11 CRB_IDL_17_12_TerB12 CRB_IDL_17_12_TerB13 CRB_IDL_17_12_TerB14 CRB_IDL_17_12_TerB15 CRB_IDL_17_12_TerB16 CRB_IDL_17_12_TerB17 CRB_IDL_17_12_TerB18 CRB_IDL_17_12_TerB19 CRB_IDL_17_12_TerB20 CRB_IDL_17_12_TerB21 CRB_IDL_17_12_TerB22 CRB_IDL_17_12_TerB23 CRB_IDL_17_12_TerB24 CRB_IDL_17_12_TerB25 CRB_IDL_17_12_TerB26 CRB_IDL_17_12_TerB27 CRB_IDL_17_12_TerB28 CRB_IDL_17_12_TerB29 CRB_IDL_17_12_TerB30 CRB_IDL_17_12_TerB31 CRB_IDL_17_12_TerB32 CRB_IDL_17_12_TerB33 CRB_IDL_17_12_TerB34 CRB_IDL_17_12_TerB35 CRB_IDL_17_12_TerB36 CRB_IDL_17_12_TerB37 CRB_IDL_17_12_TerB38 CRB_IDL_17_12_TerB39 CRB_IDL_17_12_TerB40 CRB_IDL_17_12_TerB41 CRB_IDL_17_12_TerB42 CRB_IDL_17_12_TerB43 CRB_IDL_17_12_TerB44 CRB_IDL_17_12_TerB45 CRB_IDL_17_12_TerB46 CRB_IDL_17_12_TerB47 CRB_IDL_17_12_TerB48 CRB_IDL_17_12_TerB49 CRB_IDL_17_12_TerB50 CRB_IDL_17_12_TerB51 CRB_IDL_17_12_TerB52 CRB_IDL_17_12_TerB53 CRB_IDL_17_12_TerB54 CRB_IDL_17_12_TerB55 CRB_IDL_17_12_TerB56 CRB_IDL_17_12_TerB57 CRB_IDL_17_12_TerB58 CRB_IDL_17_12_TerB59 CRB_IDL_17_12_TerB60 CRB_IDL_17_12_TerB61 CRB_IDL_17_12_TerB62 CRB_IDL_17_12_TerB63 CRB_IDL_17_12_TerB64 CRB_IDL_17_12_TerB65 CRB_IDL_17_12_TerB66 CRB_IDL_17_12_TerB67 CRB_IDL_17_12_TerB68 CRB_IDL_17_12_TerB69 CRB_IDL_17_12_TerB70 CRB_IDL_17_12_TerB71 CRB_IDL_17_12_TerB72 CRB_IDL_17_12_TerB73 CRB_IDL_17_12_TerB74 CRB_IDL_17_12_TerB75 CRB_IDL_17_12_TerB76 CRB_IDL_17_12_TerB77 CRB_IDL_17_12_TerB78 CRB_IDL_17_12_TerB79 CRB_IDL_17_12_TerB80 CRB_IDL_17_12_TerB81 CRB_IDL_17_12_TerB82 CRB_IDL_17_12_TerB83 CRB_IDL_17_12_TerB84 CRB_IDL_17_12_TerB85 CRB_IDL_17_12_TerB86 CRB_IDL_17_12_TerB87 CRB_IDL_17_12_TerB88 CRB_IDL_17_12_TerB89: library part CAPCC0402_2_1.0U_50VX7R, "Capacitor chip ceramic 0402 6.3V X7R", Manufacturer=TDK, Manufacturer No=GRM155R70J105KA12D, Package="Cap Chip 0402", Supplier Part Number 1=81-GRM155R70J105KA2D, Voltage rating=6.3V
Jbot1 Jbot2 Jbot3 Jbot4 Jtop1 Jtop2 Jtop3 Jtop4: library part "09 03 296 2825", "Eurocard DIN 41612, Type C, 96 Position, Rows a+b+c, Performance level 1, Female, Lead 4.5 mm, Pitch 2.54 mm", PackageDocument=21-Feb-2002
JMid1 JMid2 JMid3 JMid4: library part "127-pin connector", "127-pin connector", Part No.=17131271201, Supplier Part Number 1=1195-5281-ND
R1R_IDL_17_12_TerA1 R1R_IDL_17_12_TerA2 R1R_IDL_17_12_TerA3 R1R_IDL_17_12_TerA4 R1R_IDL_17_12_TerA5 R1R_IDL_17_12_TerA6 R1R_IDL_17_12_TerA7 R1R_IDL_17_12_TerA8 R1R_IDL_17_12_TerA9 R1R_IDL_17_12_TerA10 R1R_IDL_17_12_TerA11 R1R_IDL_17_12_TerA12 R1R_IDL_17_12_TerA13 R1R_IDL_17_12_TerA14 R1R_IDL_17_12_TerA15 R1R_IDL_17_12_TerA16 R1R_IDL_17_12_TerA17 R1R_IDL_17_12_TerA18 R1R_IDL_17_12_TerA19 R1R_IDL_17_12_TerA20 R1R_IDL_17_12_TerA21 R1R_IDL_17_12_TerA22 R1R_IDL_17_12_TerA23 R1R_IDL_17_12_TerA24 R1R_IDL_17_12_TerA25 R1R_IDL_17_12_TerA26 R1R_IDL_17_12_TerA27 R1R_IDL_17_12_TerA28 R1R_IDL_17_12_TerA29 R1R_IDL_17_12_TerA30 R1R_IDL_17_12_TerA31 R1R_IDL_17_12_TerA32 R1R_IDL_17_12_TerA33 R1R_IDL_17_12_TerA34 R1R_IDL_17_12_TerA35 R1R_IDL_17_12_TerA36 R1R_IDL_17_12_TerA37 R1R_IDL_17_12_TerA38 R1R_IDL_17_12_TerA39 R1R_IDL_17_12_TerA40 R1R_IDL_17_12_TerA41 R1R_IDL_17_12_TerA42 R1R_IDL_17_12_TerA43 R1R_IDL_17_12_TerA44 R1R_IDL_17_12_TerA45 R1R_IDL_17_12_TerA46 R1R_IDL_17_12_TerA47 R1R_IDL_17_12_TerA48 R1R_IDL_17_12_TerA49 R1R_IDL_17_12_TerA50 R1R_IDL_17_12_TerA51 R1R_IDL_17_12_TerA52 R1R_IDL_17_12_TerA53 R1R_IDL_17_12_TerA54 R1R_IDL_17_12_TerA55 R1R_IDL_17_12_TerA56 R1R_IDL_17_12_TerA57 R1R_IDL_17_12_TerA58 R1R_IDL_17_12_TerA59 R1R_IDL_17_12_TerA60 R1R_IDL_17_12_TerA61 R1R_IDL_17_12_TerA62 R1R_IDL_17_12_TerA63 R1R_IDL_17_12_TerA64 R1R_IDL_17_12_TerA65 R1R_IDL_17_12_TerA66 R1R_IDL_17_12_TerA67 R1R_IDL_17_12_TerA68 R1R_IDL_17_12_TerA69 R1R_IDL_17_12_TerA70 R1R_IDL_17_12_TerA71 R1R_IDL_17_12_TerA72 R1RB_IDL_17_12_TerB1 R1RB_IDL_17_12_TerB2 R1RB_IDL_17_12_TerB3 R1RB_IDL_17_12_TerB4 R1RB_IDL_17_12_TerB5 R1RB_IDL_17_12_TerB6 R1RB_IDL_17_12_TerB7 R1RB_IDL_17_12_TerB8 R1RB_IDL_17_12_TerB9 R1RB_IDL_17_12_TerB10 R1RB_IDL_17_12_TerB11 R1RB_IDL_17_12_TerB12 R1RB_IDL_17_12_TerB13 R1RB_IDL_17_12_TerB14 R1RB_IDL_17_12_TerB15 R1RB_IDL_17_12_TerB16 R1RB_IDL_17_12_TerB17 R1RB_IDL_17_12_TerB18 R1RB_IDL_17_12_TerB19 R1RB_IDL_17_12_TerB20 R1RB_IDL_17_12_TerB21 R1RB_IDL_17_12_TerB22 R1RB_IDL_17_12_TerB23 R1RB_IDL_17_12_TerB24 R1RB_IDL_17_12_TerB25 R1RB_IDL_17_12_TerB26 R1RB_IDL_17_12_TerB27 R1RB_IDL_17_12_TerB28 R1RB_IDL_17_12_TerB29 R1RB_IDL_17_12_TerB30 R1RB_IDL_17_12_TerB31 R1RB_IDL_17_12_TerB32 R1RB_IDL_17_12_TerB33 R1RB_IDL_17_12_TerB34 R1RB_IDL_17_12_TerB35 R1RB_IDL_17_12_TerB36 R1RB_IDL_17_12_TerB37 R1RB_IDL_17_12_TerB38 R1RB_IDL_17_12_TerB39 R1RB_IDL_17_12_TerB40 R1RB_IDL_17_12_TerB41 R1RB_IDL_17_12_TerB42 R1RB_IDL_17_12_TerB43 R1RB_IDL_17_12_TerB44 R1RB_IDL_17_12_TerB45 R1RB_IDL_17_12_TerB46 R1RB_IDL_17_12_TerB47 R1RB_IDL_17_12_TerB48 R1RB_IDL_17_12_TerB49 R1RB_IDL_17_12_TerB50 R1RB_IDL_17_12_TerB51 R1RB_IDL_17_12_TerB52 R1RB_IDL_17_12_TerB53 R1RB_IDL_17_12_TerB54 R1RB_IDL_17_12_TerB55 R1RB_IDL_17_12_TerB56 R1RB_IDL_17_12_TerB57 R1RB_IDL_17_12_TerB58 R1RB_IDL_17_12_TerB59 R1RB_IDL_17_12_TerB60 R1RB_IDL_17_12_TerB61 R1RB_IDL_17_12_TerB62 R1RB_IDL_17_12_TerB63 R1RB_IDL_17_12_TerB64 R1RB_IDL_17_12_TerB65 R1RB_IDL_17_12_TerB66 R1RB_IDL_17_12_TerB67 R1RB_IDL_17_12_TerB68 R1RB_IDL_17_12_TerB69 R1RB_IDL_17_12_TerB70 R1RB_IDL_17_12_TerB71 R1RB_IDL_17_12_TerB72 R1RB_IDL_17_12_TerB73 R1RB_IDL_17_12_TerB74 R1RB_IDL_17_12_TerB75 R1RB_IDL_17_12_TerB76 R1RB_IDL_17_12_TerB77 R1RB_IDL_17_12_TerB78 R1RB_IDL_17_12_TerB79 R1RB_IDL_17_12_TerB80 R1RB_IDL_17_12_TerB81 R1RB_IDL_17_12_TerB82 R1RB_IDL_17_12_TerB83 R1RB_IDL_17_12_TerB84 R1RB_IDL_17_12_TerB85 R1RB_IDL_17_12_TerB86 R1RB_IDL_17_12_TerB87 R1RB_IDL_17_12_TerB88 R1RB_IDL_17_12_TerB89 R2R_IDL_17_12_TerA1 R2R_IDL_17_12_TerA2 R2R_IDL_17_12_TerA3 R2R_IDL_17_12_TerA4 R2R_IDL_17_12_TerA5 R2R_IDL_17_12_TerA6 R2R_IDL_17_12_TerA7 R2R_IDL_17_12_TerA8 R2R_IDL_17_12_TerA9 R2R_IDL_17_12_TerA10 R2R_IDL_17_12_TerA11 R2R_IDL_17_12_TerA12 R2R_IDL_17_12_TerA13 R2R_IDL_17_12_TerA14 R2R_IDL_17_12_TerA15 R2R_IDL_17_12_TerA16 R2R_IDL_17_12_TerA17 R2R_IDL_17_12_TerA18 R2R_IDL_17_12_TerA19 R2R_IDL_17_12_TerA20 R2R_IDL_17_12_TerA21 R2R_IDL_17_12_TerA22 R2R_IDL_17_12_TerA23 R2R_IDL_17_12_TerA24 R2R_IDL_17_12_TerA25 R2R_IDL_17_12_TerA26 R2R_IDL_17_12_TerA27 R2R_IDL_17_12_TerA28 R2R_IDL_17_12_TerA29 R2R_IDL_17_12_TerA30 R2R_IDL_17_12_TerA31 R2R_IDL_17_12_TerA32 R2R_IDL_17_12_TerA33 R2R_IDL_17_12_TerA34 R2R_IDL_17_12_TerA35 R2R_IDL_17_12_TerA36 R2R_IDL_17_12_TerA37 R2R_IDL_17_12_TerA38 R2R_IDL_17_12_TerA39 R2R_IDL_17_12_TerA40 R2R_IDL_17_12_TerA41 R2R_IDL_17_12_TerA42 R2R_IDL_17_12_TerA43 R2R_IDL_17_12_TerA44 R2R_IDL_17_12_TerA45 R2R_IDL_17_12_TerA46 R2R_IDL_17_12_TerA47 R2R_IDL_17_12_TerA48 R2R_IDL_17_12_TerA49 R2R_IDL_17_12_TerA50 R2R_IDL_17_12_TerA51 R2R_IDL_17_12_TerA52 R2R_IDL_17_12_TerA53 R2R_IDL_17_12_TerA54 R2R_IDL_17_12_TerA55 R2R_IDL_17_12_TerA56 R2R_IDL_17_12_TerA57 R2R_IDL_17_12_TerA58 R2R_IDL_17_12_TerA59 R2R_IDL_17_12_TerA60 R2R_IDL_17_12_TerA61 R2R_IDL_17_12_TerA62 R2R_IDL_17_12_TerA63 R2R_IDL_17_12_TerA64 R2R_IDL_17_12_TerA65 R2R_IDL_17_12_TerA66 R2R_IDL_17_12_TerA67 R2R_IDL_17_12_TerA68 R2R_IDL_17_12_TerA69 R2R_IDL_17_12_TerA70 R2R_IDL_17_12_TerA71 R2R_IDL_17_12_TerA72 R2RB_IDL_17_12_TerB1 R2RB_IDL_17_12_TerB2 R2RB_IDL_17_12_TerB3 R2RB_IDL_17_12_TerB4 R2RB_IDL_17_12_TerB5 R2RB_IDL_17_12_TerB6 R2RB_IDL_17_12_TerB7 R2RB_IDL_17_12_TerB8 R2RB_IDL_17_12_TerB9 R2RB_IDL_17_12_TerB10 R2RB_IDL_17_12_TerB11 R2RB_IDL_17_12_TerB12 R2RB_IDL_17_12_TerB13 R2RB_IDL_17_12_TerB14 R2RB_IDL_17_12_TerB15 R2RB_IDL_17_12_TerB16 R2RB_IDL_17_12_TerB17 R2RB_IDL_17_12_TerB18 R2RB_IDL_17_12_TerB19 R2RB_IDL_17_12_TerB20 R2RB_IDL_17_12_TerB21 R2RB_IDL_17_12_TerB22 R2RB_IDL_17_12_TerB23 R2RB_IDL_17_12_TerB24 R2RB_IDL_17_12_TerB25 R2RB_IDL_17_12_TerB26 R2RB_IDL_17_12_TerB27 R2RB_IDL_17_12_TerB28 R2RB_IDL_17_12_TerB29 R2RB_IDL_17_12_TerB30 R2RB_IDL_17_12_TerB31 R2RB_IDL_17_12_TerB32 R2RB_IDL_17_12_TerB33 R2RB_IDL_17_12_TerB34 R2RB_IDL_17_12_TerB35 R2RB_IDL_17_12_TerB36 R2RB_IDL_17_12_TerB37 R2RB_IDL_17_12_TerB38 R2RB_IDL_17_12_TerB39 R2RB_IDL_17_12_TerB40 R2RB_IDL_17_12_TerB41 R2RB_IDL_17_12_TerB42 R2RB_IDL_17_12_TerB43 R2RB_IDL_17_12_TerB44 R2RB_IDL_17_12_TerB45 R2RB_IDL_17_12_TerB46 R2RB_IDL_17_12_TerB47 R2RB_IDL_17_12_TerB48 R2RB_IDL_17_12_TerB49 R2RB_IDL_17_12_TerB50 R2RB_IDL_17_12_TerB51 R2RB_IDL_17_12_TerB52 R2RB_IDL_17_12_TerB53 R2RB_IDL_17_12_TerB54 R2RB_IDL_17_12_TerB55 R2RB_IDL_17_12_TerB56 R2RB_IDL_17_12_TerB57 R2RB_IDL_17_12_TerB58 R2RB_IDL_17_12_TerB59 R2RB_IDL_17_12_TerB60 R2RB_IDL_17_12_TerB61 R2RB_IDL_17_12_TerB62 R2RB_IDL_17_12_TerB63 R2RB_IDL_17_12_TerB64 R2RB_IDL_17_12_TerB65 R2RB_IDL_17_12_TerB66 R2RB_IDL_17_12_TerB67 R2RB_IDL_17_12_TerB68 R2RB_IDL_17_12_TerB69 R2RB_IDL_17_12_TerB70 R2RB_IDL_17_12_TerB71 R2RB_IDL_17_12_TerB72 R2RB_IDL_17_12_TerB73 R2RB_IDL_17_12_TerB74 R2RB_IDL_17_12_TerB75 R2RB_IDL_17_12_TerB76 R2RB_IDL_17_12_TerB77 R2RB_IDL_17_12_TerB78 R2RB_IDL_17_12_TerB79 R2RB_IDL_17_12_TerB80 R2RB_IDL_17_12_TerB81 R2RB_IDL_17_12_TerB82 R2RB_IDL_17_12_TerB83 R2RB_IDL_17_12_TerB84 R2RB_IDL_17_12_TerB85 R2RB_IDL_17_12_TerB86 R2RB_IDL_17_12_TerB87 R2RB_IDL_17_12_TerB88 R2RB_IDL_17_12_TerB89: library part RES0402-0-499R-1%100PPM, "Chip Resistor 0402 62.5mW 1% 100ppm", Manufacturer=Panasonic, Manufacturer No=ERJ-2RKF4990X, Package="Res Chip 0402", Supplier Part Number 1=P499LDKR-ND

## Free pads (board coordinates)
  round 40 / inner round 205 / far side round 40 hole 157 mask+58.5: 1(248.66,-15274.23)
  round 236.22 hole 157: M3(144.72,5031.5) M3(148.83,-5031.5) M3(2174.09,-5031.5) M3(2174.09,5031.5) M3(4497,-5031.5) M3(4497.14,-729) M3(4497.14,729) M3(4497.14,5031.5)

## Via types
v1: diameter 25.59, hole 11.81, Top Signal to Bot Signal, 427 vias

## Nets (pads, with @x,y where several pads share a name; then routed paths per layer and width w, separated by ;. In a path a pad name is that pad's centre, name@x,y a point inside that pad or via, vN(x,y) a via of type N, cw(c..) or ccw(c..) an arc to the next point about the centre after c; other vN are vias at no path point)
3V3: +3V3.1 +3V3.2 +3V3.3 +3V3.4 +3V3.5 +3V3.6 JMid1.20 JMid1.21 JMid1.22 JMid1.23 JMid1.39 JMid1.40 JMid1.41 JMid1.42 JMid1.58 JMid1.59 JMid1.60 JMid1.77 JMid1.78 JMid1.79 JMid1.96 JMid1.97 JMid1.98 JMid2.20 JMid2.21 JMid2.22 JMid2.23 JMid2.39 JMid2.40 JMid2.41 JMid2.42 JMid2.58 JMid2.59 JMid2.60 JMid2.77 JMid2.78 JMid2.79 JMid2.96 JMid2.97 JMid2.98 JMid3.20 JMid3.21 JMid3.22 JMid3.23 JMid3.39 JMid3.40 JMid3.41 JMid3.42 JMid3.58 JMid3.59 JMid3.60 JMid3.77 JMid3.78 JMid3.79 JMid3.96 JMid3.97 JMid3.98 JMid4.20 JMid4.21 JMid4.22 JMid4.23 JMid4.39 JMid4.40 JMid4.41 JMid4.42 JMid4.58 JMid4.59 JMid4.60 JMid4.77 JMid4.78 JMid4.79 JMid4.96 JMid4.97 JMid4.98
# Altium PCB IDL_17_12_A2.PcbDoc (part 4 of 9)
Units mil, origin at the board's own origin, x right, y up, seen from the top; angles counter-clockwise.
Board outline 5119.97 x 10350 mil, 6 copper layers (Top Signal, 3.3 Volt, GND, 5 Volt, Split Plane, Bot Signal), stack 66.2 mil thick; 514 components, 178 nets, 2321 pads, 427 vias.

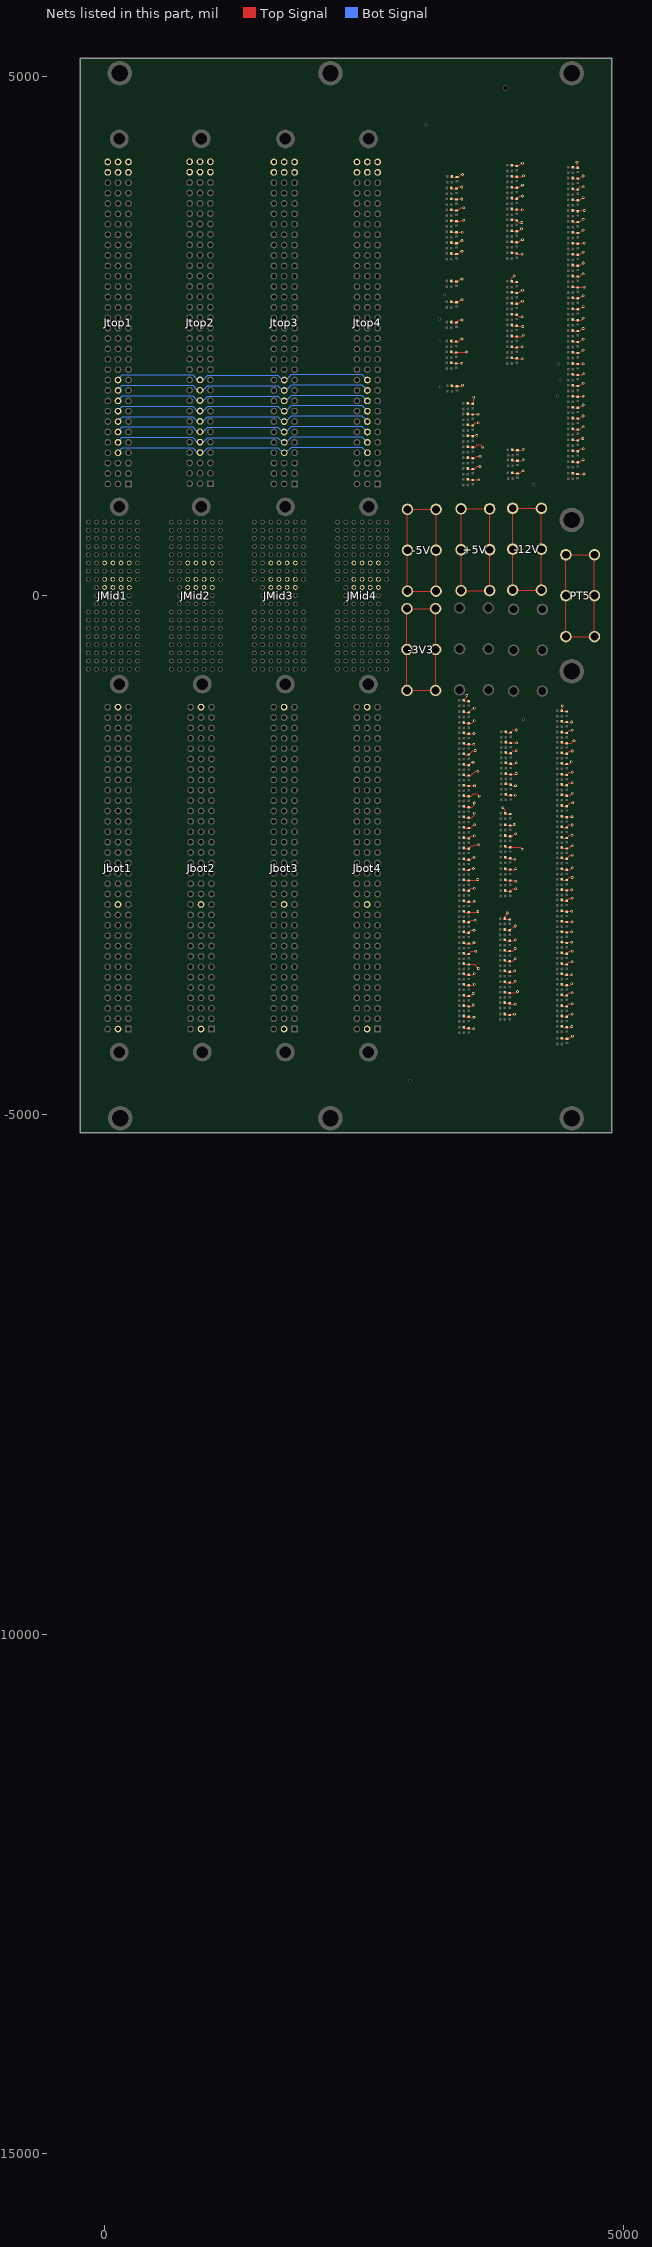
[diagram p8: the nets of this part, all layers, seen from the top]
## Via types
v1: diameter 25.59, hole 11.81, Top Signal to Bot Signal, 427 vias

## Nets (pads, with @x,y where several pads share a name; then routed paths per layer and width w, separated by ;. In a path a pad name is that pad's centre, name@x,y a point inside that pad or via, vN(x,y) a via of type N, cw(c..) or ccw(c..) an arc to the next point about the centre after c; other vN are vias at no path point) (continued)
5V: +5V.1 +5V.2 +5V.3 +5V.4 +5V.5 +5V.6 CR_IDL_17_12_TerA1.2 CR_IDL_17_12_TerA2.2 CR_IDL_17_12_TerA3.2 CR_IDL_17_12_TerA4.2 CR_IDL_17_12_TerA5.2 CR_IDL_17_12_TerA6.2 CR_IDL_17_12_TerA7.2 CR_IDL_17_12_TerA8.2 CR_IDL_17_12_TerA9.2 CR_IDL_17_12_TerA10.2 CR_IDL_17_12_TerA11.2 CR_IDL_17_12_TerA12.2 CR_IDL_17_12_TerA13.2 CR_IDL_17_12_TerA14.2 CR_IDL_17_12_TerA15.2 CR_IDL_17_12_TerA16.2 CR_IDL_17_12_TerA17.2 CR_IDL_17_12_TerA18.2 CR_IDL_17_12_TerA19.2 CR_IDL_17_12_TerA20.2 CR_IDL_17_12_TerA21.2 CR_IDL_17_12_TerA22.2 CR_IDL_17_12_TerA23.2 CR_IDL_17_12_TerA24.2 CR_IDL_17_12_TerA25.2 CR_IDL_17_12_TerA26.2 CR_IDL_17_12_TerA27.2 CR_IDL_17_12_TerA28.2 CR_IDL_17_12_TerA29.2 CR_IDL_17_12_TerA30.2 CR_IDL_17_12_TerA31.2 CR_IDL_17_12_TerA32.2 CR_IDL_17_12_TerA33.2 CR_IDL_17_12_TerA34.2 CR_IDL_17_12_TerA35.2 CR_IDL_17_12_TerA36.2 CR_IDL_17_12_TerA37.2 CR_IDL_17_12_TerA38.2 CR_IDL_17_12_TerA39.2 CR_IDL_17_12_TerA40.2 CR_IDL_17_12_TerA41.2 CR_IDL_17_12_TerA42.2 CR_IDL_17_12_TerA43.2 CR_IDL_17_12_TerA44.2 CR_IDL_17_12_TerA45.2 CR_IDL_17_12_TerA46.2 CR_IDL_17_12_TerA47.2 CR_IDL_17_12_TerA48.2 CR_IDL_17_12_TerA49.2 CR_IDL_17_12_TerA50.2 CR_IDL_17_12_TerA51.2 CR_IDL_17_12_TerA52.2 CR_IDL_17_12_TerA53.2 CR_IDL_17_12_TerA54.2 CR_IDL_17_12_TerA55.2 CR_IDL_17_12_TerA56.2 CR_IDL_17_12_TerA57.2 CR_IDL_17_12_TerA58.2 CR_IDL_17_12_TerA59.2 CR_IDL_17_12_TerA60.2 CR_IDL_17_12_TerA61.2 CR_IDL_17_12_TerA62.2 CR_IDL_17_12_TerA63.2 CR_IDL_17_12_TerA64.2 CR_IDL_17_12_TerA65.2 CR_IDL_17_12_TerA66.2 CR_IDL_17_12_TerA67.2 CR_IDL_17_12_TerA68.2 CR_IDL_17_12_TerA69.2 CR_IDL_17_12_TerA70.2 CR_IDL_17_12_TerA71.2 CR_IDL_17_12_TerA72.2 CRB_IDL_17_12_TerB1.2 CRB_IDL_17_12_TerB2.2 CRB_IDL_17_12_TerB3.2 CRB_IDL_17_12_TerB4.2 CRB_IDL_17_12_TerB5.2 CRB_IDL_17_12_TerB6.2 CRB_IDL_17_12_TerB7.2 CRB_IDL_17_12_TerB8.2 CRB_IDL_17_12_TerB9.2 CRB_IDL_17_12_TerB10.2 CRB_IDL_17_12_TerB11.2 CRB_IDL_17_12_TerB12.2 CRB_IDL_17_12_TerB13.2 CRB_IDL_17_12_TerB14.2 CRB_IDL_17_12_TerB15.2 CRB_IDL_17_12_TerB16.2 CRB_IDL_17_12_TerB17.2 CRB_IDL_17_12_TerB18.2 CRB_IDL_17_12_TerB19.2 CRB_IDL_17_12_TerB20.2 CRB_IDL_17_12_TerB21.2 CRB_IDL_17_12_TerB22.2 CRB_IDL_17_12_TerB23.2 CRB_IDL_17_12_TerB24.2 CRB_IDL_17_12_TerB25.2 CRB_IDL_17_12_TerB26.2 CRB_IDL_17_12_TerB27.2 CRB_IDL_17_12_TerB28.2 CRB_IDL_17_12_TerB29.2 CRB_IDL_17_12_TerB30.2 CRB_IDL_17_12_TerB31.2 CRB_IDL_17_12_TerB32.2 CRB_IDL_17_12_TerB33.2 CRB_IDL_17_12_TerB34.2 CRB_IDL_17_12_TerB35.2 CRB_IDL_17_12_TerB36.2 CRB_IDL_17_12_TerB37.2 CRB_IDL_17_12_TerB38.2 CRB_IDL_17_12_TerB39.2 CRB_IDL_17_12_TerB40.2 CRB_IDL_17_12_TerB41.2 CRB_IDL_17_12_TerB42.2 CRB_IDL_17_12_TerB43.2 CRB_IDL_17_12_TerB44.2 CRB_IDL_17_12_TerB45.2 CRB_IDL_17_12_TerB46.2 CRB_IDL_17_12_TerB47.2 CRB_IDL_17_12_TerB48.2 CRB_IDL_17_12_TerB49.2 CRB_IDL_17_12_TerB50.2 CRB_IDL_17_12_TerB51.2 CRB_IDL_17_12_TerB52.2 CRB_IDL_17_12_TerB53.2 CRB_IDL_17_12_TerB54.2 CRB_IDL_17_12_TerB55.2 CRB_IDL_17_12_TerB56.2 CRB_IDL_17_12_TerB57.2 CRB_IDL_17_12_TerB58.2 CRB_IDL_17_12_TerB59.2 CRB_IDL_17_12_TerB60.2 CRB_IDL_17_12_TerB61.2 CRB_IDL_17_12_TerB62.2 CRB_IDL_17_12_TerB63.2 CRB_IDL_17_12_TerB64.2 CRB_IDL_17_12_TerB65.2 CRB_IDL_17_12_TerB66.2 CRB_IDL_17_12_TerB67.2 CRB_IDL_17_12_TerB68.2 CRB_IDL_17_12_TerB69.2 CRB_IDL_17_12_TerB70.2 CRB_IDL_17_12_TerB71.2 CRB_IDL_17_12_TerB72.2 CRB_IDL_17_12_TerB73.2 CRB_IDL_17_12_TerB74.2 CRB_IDL_17_12_TerB75.2 CRB_IDL_17_12_TerB76.2 CRB_IDL_17_12_TerB77.2 CRB_IDL_17_12_TerB78.2 CRB_IDL_17_12_TerB79.2 CRB_IDL_17_12_TerB80.2 CRB_IDL_17_12_TerB81.2 CRB_IDL_17_12_TerB82.2 CRB_IDL_17_12_TerB83.2 CRB_IDL_17_12_TerB84.2 CRB_IDL_17_12_TerB85.2 CRB_IDL_17_12_TerB86.2 CRB_IDL_17_12_TerB87.2 CRB_IDL_17_12_TerB88.2 CRB_IDL_17_12_TerB89.2 Jbot1.B1 Jbot1.B13 Jbot1.B32 Jbot2.B1 Jbot2.B13 Jbot2.B32 Jbot3.B1 Jbot3.B13 Jbot3.B32 Jbot4.B1 Jbot4.B13 Jbot4.B32 Jtop1.A32 Jtop1.B31 Jtop1.B32 Jtop1.C32 Jtop2.A32 Jtop2.B31 Jtop2.B32 Jtop2.C32 Jtop3.A32 Jtop3.B31 Jtop3.B32 Jtop3.C32 Jtop4.A32 Jtop4.B31 Jtop4.B32 Jtop4.C32 R1R_IDL_17_12_TerA1.2 R1R_IDL_17_12_TerA2.2 R1R_IDL_17_12_TerA3.2 R1R_IDL_17_12_TerA4.2 R1R_IDL_17_12_TerA5.2 R1R_IDL_17_12_TerA6.2 R1R_IDL_17_12_TerA7.2 R1R_IDL_17_12_TerA8.2 R1R_IDL_17_12_TerA9.2 R1R_IDL_17_12_TerA10.2 R1R_IDL_17_12_TerA11.2 R1R_IDL_17_12_TerA12.2 R1R_IDL_17_12_TerA13.2 R1R_IDL_17_12_TerA14.2 R1R_IDL_17_12_TerA15.2 R1R_IDL_17_12_TerA16.2 R1R_IDL_17_12_TerA17.2 R1R_IDL_17_12_TerA18.2 R1R_IDL_17_12_TerA19.2 R1R_IDL_17_12_TerA20.2 R1R_IDL_17_12_TerA21.2 R1R_IDL_17_12_TerA22.2 R1R_IDL_17_12_TerA23.2 R1R_IDL_17_12_TerA24.2 R1R_IDL_17_12_TerA25.2 R1R_IDL_17_12_TerA26.2 R1R_IDL_17_12_TerA27.2 R1R_IDL_17_12_TerA28.2 R1R_IDL_17_12_TerA29.2 R1R_IDL_17_12_TerA30.2 R1R_IDL_17_12_TerA31.2 R1R_IDL_17_12_TerA32.2 R1R_IDL_17_12_TerA33.2 R1R_IDL_17_12_TerA34.2 R1R_IDL_17_12_TerA35.2 R1R_IDL_17_12_TerA36.2 R1R_IDL_17_12_TerA37.2 R1R_IDL_17_12_TerA38.2 R1R_IDL_17_12_TerA39.2 R1R_IDL_17_12_TerA40.2 R1R_IDL_17_12_TerA41.2 R1R_IDL_17_12_TerA42.2 R1R_IDL_17_12_TerA43.2 R1R_IDL_17_12_TerA44.2 R1R_IDL_17_12_TerA45.2 R1R_IDL_17_12_TerA46.2 R1R_IDL_17_12_TerA47.2 R1R_IDL_17_12_TerA48.2 R1R_IDL_17_12_TerA49.2 R1R_IDL_17_12_TerA50.2 R1R_IDL_17_12_TerA51.2 R1R_IDL_17_12_TerA52.2 R1R_IDL_17_12_TerA53.2 R1R_IDL_17_12_TerA54.2 R1R_IDL_17_12_TerA55.2 R1R_IDL_17_12_TerA56.2 R1R_IDL_17_12_TerA57.2 R1R_IDL_17_12_TerA58.2 R1R_IDL_17_12_TerA59.2 R1R_IDL_17_12_TerA60.2 R1R_IDL_17_12_TerA61.2 R1R_IDL_17_12_TerA62.2 R1R_IDL_17_12_TerA63.2 R1R_IDL_17_12_TerA64.2 R1R_IDL_17_12_TerA65.2 R1R_IDL_17_12_TerA66.2 R1R_IDL_17_12_TerA67.2 R1R_IDL_17_12_TerA68.2 R1R_IDL_17_12_TerA69.2 R1R_IDL_17_12_TerA70.2 R1R_IDL_17_12_TerA71.2 R1R_IDL_17_12_TerA72.2 R1RB_IDL_17_12_TerB1.2 R1RB_IDL_17_12_TerB2.2 R1RB_IDL_17_12_TerB3.2 R1RB_IDL_17_12_TerB4.2 R1RB_IDL_17_12_TerB5.2 R1RB_IDL_17_12_TerB6.2 R1RB_IDL_17_12_TerB7.2 R1RB_IDL_17_12_TerB8.2 R1RB_IDL_17_12_TerB9.2 R1RB_IDL_17_12_TerB10.2 R1RB_IDL_17_12_TerB11.2 R1RB_IDL_17_12_TerB12.2 R1RB_IDL_17_12_TerB13.2 R1RB_IDL_17_12_TerB14.2 R1RB_IDL_17_12_TerB15.2 R1RB_IDL_17_12_TerB16.2 R1RB_IDL_17_12_TerB17.2 R1RB_IDL_17_12_TerB18.2 R1RB_IDL_17_12_TerB19.2 R1RB_IDL_17_12_TerB20.2 R1RB_IDL_17_12_TerB21.2 R1RB_IDL_17_12_TerB22.2 R1RB_IDL_17_12_TerB23.2 R1RB_IDL_17_12_TerB24.2 R1RB_IDL_17_12_TerB25.2 R1RB_IDL_17_12_TerB26.2 R1RB_IDL_17_12_TerB27.2 R1RB_IDL_17_12_TerB28.2 R1RB_IDL_17_12_TerB29.2 R1RB_IDL_17_12_TerB30.2 R1RB_IDL_17_12_TerB31.2 R1RB_IDL_17_12_TerB32.2 R1RB_IDL_17_12_TerB33.2 R1RB_IDL_17_12_TerB34.2 R1RB_IDL_17_12_TerB35.2 R1RB_IDL_17_12_TerB36.2 R1RB_IDL_17_12_TerB37.2 R1RB_IDL_17_12_TerB38.2 R1RB_IDL_17_12_TerB39.2 R1RB_IDL_17_12_TerB40.2 R1RB_IDL_17_12_TerB41.2 R1RB_IDL_17_12_TerB42.2 R1RB_IDL_17_12_TerB43.2 R1RB_IDL_17_12_TerB44.2 R1RB_IDL_17_12_TerB45.2 R1RB_IDL_17_12_TerB46.2 R1RB_IDL_17_12_TerB47.2 R1RB_IDL_17_12_TerB48.2 R1RB_IDL_17_12_TerB49.2 R1RB_IDL_17_12_TerB50.2 R1RB_IDL_17_12_TerB51.2 R1RB_IDL_17_12_TerB52.2 R1RB_IDL_17_12_TerB53.2 R1RB_IDL_17_12_TerB54.2 R1RB_IDL_17_12_TerB55.2 R1RB_IDL_17_12_TerB56.2 R1RB_IDL_17_12_TerB57.2 R1RB_IDL_17_12_TerB58.2 R1RB_IDL_17_12_TerB59.2 R1RB_IDL_17_12_TerB60.2 R1RB_IDL_17_12_TerB61.2 R1RB_IDL_17_12_TerB62.2 R1RB_IDL_17_12_TerB63.2 R1RB_IDL_17_12_TerB64.2 R1RB_IDL_17_12_TerB65.2 R1RB_IDL_17_12_TerB66.2 R1RB_IDL_17_12_TerB67.2 R1RB_IDL_17_12_TerB68.2 R1RB_IDL_17_12_TerB69.2 R1RB_IDL_17_12_TerB70.2 R1RB_IDL_17_12_TerB71.2 R1RB_IDL_17_12_TerB72.2 R1RB_IDL_17_12_TerB73.2 R1RB_IDL_17_12_TerB74.2 R1RB_IDL_17_12_TerB75.2 R1RB_IDL_17_12_TerB76.2 R1RB_IDL_17_12_TerB77.2 R1RB_IDL_17_12_TerB78.2 R1RB_IDL_17_12_TerB79.2 R1RB_IDL_17_12_TerB80.2 R1RB_IDL_17_12_TerB81.2 R1RB_IDL_17_12_TerB82.2 R1RB_IDL_17_12_TerB83.2 R1RB_IDL_17_12_TerB84.2 R1RB_IDL_17_12_TerB85.2 R1RB_IDL_17_12_TerB86.2 R1RB_IDL_17_12_TerB87.2 R1RB_IDL_17_12_TerB88.2 R1RB_IDL_17_12_TerB89.2 | length 18549.9
  Top Signal w8: Jtop4.A32@2628.72,4176.52 Jtop4.A32@2628.72,4182.06 ; R1R_IDL_17_12_TerA14.2@3338.02,2242.38 3381.07,2242.38 CR_IDL_17_12_TerA14.2@3386.98,2236.47 3396.15,2236.47 3396.2,2236.52 v1(3439.84,2236.52) ; R1R_IDL_17_12_TerA12.2@3338.02,2452.38 3343.93,2446.47 CR_IDL_17_12_TerA12.2@3386.98,2446.47 3405.31,2446.47 3430.64,2471.8 v1(3440.5,2471.8) ; R1R_IDL_17_12_TerA11.2@3338.39,2635.59 3344.29,2629.68 CR_IDL_17_12_TerA11.2@3387.34,2629.68 3412.67,2655.01 v1(3440.86,2655.01) ; R1R_IDL_17_12_TerA10.2@3338.39,2830.59 3344.29,2824.68 CR_IDL_17_12_TerA10.2@3387.34,2824.68 3405.68,2824.68 3431.01,2850.01 v1(3440.86,2850.01) ; R1R_IDL_17_12_TerA9.2@3338.39,3030.59 3344.29,3024.68 CR_IDL_17_12_TerA9.2@3387.34,3024.68 3405.68,3024.68 3431.01,3050.01 v1(3440.86,3050.01) ; R1R_IDL_17_12_TerA8.2@3338.39,3295.59 3344.29,3289.68 CR_IDL_17_12_TerA8.2@3387.34,3289.68 3405.68,3289.68 3431.01,3315.01 v1(3440.86,3315.01) ; R1R_IDL_17_12_TerA7.2@3338.39,3400.59 3344.29,3394.68 CR_IDL_17_12_TerA7.2@3387.34,3394.68 3405.68,3394.68 3431.01,3420.01 v1(3440.86,3420.01) ; R1R_IDL_17_12_TerA6.2@3338.39,3506.43 3338.8,3506.01 3345.13,3499.68 CR_IDL_17_12_TerA6.2@3387.34,3499.68 ; R1R_IDL_17_12_TerA5.2@3338.39,3610.59 3381.44,3610.59 CR_IDL_17_12_TerA5.2@3387.34,3604.68 3431.53,3604.68 3440.86,3614.01 v1(3456.86,3614.01) ; R1R_IDL_17_12_TerA4.2@3338.39,3715.59 3344.29,3709.68 CR_IDL_17_12_TerA4.2@3387.34,3709.68 3405.68,3709.68 3431.01,3735.01 v1(3456.86,3735.01) ; R1R_IDL_17_12_TerA2.2@3338.39,3925.59 3344.29,3919.68 CR_IDL_17_12_TerA2.2@3387.34,3919.68 3403.63,3935.97 v1(3438.78,3935.97) ; R1R_IDL_17_12_TerA13.2@3341.09,2346.29 3340,2347.38 R1R_IDL_17_12_TerA13.2@3338.02,2347.38 3343.93,2341.47 CR_IDL_17_12_TerA13.2@3386.98,2341.47 3391.79,2346.29 v1(3483.99,2346.29) ; R1R_IDL_17_12_TerA3.2@3343.27,3819.57 3343.91,3820.22 3387.34,3820.22 v1(3438.44,3820.22) ; R1R_IDL_17_12_TerA1.2@3343.39,4036.83 3349.29,4030.92 CR_IDL_17_12_TerA1.2@3392.34,4030.92 3410.68,4030.92 3436.01,4056.25 v1(3445.86,4056.25) ; R1R_IDL_17_12_TerA15.2@3344.02,2022.44 3349.93,2016.53 CR_IDL_17_12_TerA15.2@3392.98,2016.53 3437.17,2016.53 v1(3446.5,2025.86) ; CR_IDL_17_12_TerA6.2@3394.79,3500.13 v1(3444.58,3500.13) ; R1RB_IDL_17_12_TerB31.2@3457.78,-4047.31 3457.78,-4055.81 CRB_IDL_17_12_TerB31.2@3506.6,-4055.81 3512.11,-4061.32 v1(3556.4,-4061.32) ; R1RB_IDL_17_12_TerB30.2@3457.78,-3947.31 3498.1,-3947.31 CRB_IDL_17_12_TerB30.2@3506.6,-3955.81 3535.75,-3955.81 v1(3549.99,-3941.58) ; R1RB_IDL_17_12_TerB29.2@3457.78,-3847.31 3466.29,-3855.81 CRB_IDL_17_12_TerB29.2@3506.6,-3855.81 3524.94,-3855.81 v1(3550.27,-3830.48) ; R1RB_IDL_17_12_TerB28.2@3457.78,-3742.31 3466.29,-3750.81 CRB_IDL_17_12_TerB28.2@3506.6,-3750.81 3550.79,-3750.81 v1(3560.12,-3741.48) ; R1RB_IDL_17_12_TerB27.2@3457.78,-3642.31 3466.29,-3650.81 CRB_IDL_17_12_TerB27.2@3506.6,-3650.81 3550.79,-3650.81 v1(3560.12,-3641.48) ; R1RB_IDL_17_12_TerB26.2@3457.78,-3542.31 3466.29,-3550.81 CRB_IDL_17_12_TerB26.2@3506.6,-3550.81 ; R1RB_IDL_17_12_TerB25.2@3457.78,-3442.31 3466.29,-3450.81 CRB_IDL_17_12_TerB25.2@3506.6,-3450.81 3532.34,-3425.08 v1(3574.01,-3425.08) 3579.11,-3425.08 3582.06,-3428.02 v1@3574.01,-3428.02 ; R1RB_IDL_17_12_TerB23.2@3457.78,-3237.31 3466.29,-3245.81 CRB_IDL_17_12_TerB23.2@3506.6,-3245.81 3529,-3223.41 v1(3557.19,-3223.41) ; R1RB_IDL_17_12_TerB22.2@3457.78,-3137.31 3466.29,-3145.81 CRB_IDL_17_12_TerB22.2@3506.6,-3145.81 3525.99,-3126.43 v1(3569.38,-3126.43) ; R1RB_IDL_17_12_TerB21.2@3457.78,-3039.31 3466.29,-3047.81 CRB_IDL_17_12_TerB21.2@3506.6,-3047.81 3588.51,-3047.81 v1(3594.38,-3041.94) ; R1RB_IDL_17_12_TerB20.2@3457.78,-2939.31 3466.29,-2947.81 CRB_IDL_17_12_TerB20.2@3506.6,-2947.81 3551.14,-2947.81 v1(3557.68,-2941.28) ; R1RB_IDL_17_12_TerB19.2@3457.78,-2834.31 3466.29,-2842.81 CRB_IDL_17_12_TerB19.2@3506.6,-2842.81 3531.93,-2817.48 v1(3560.12,-2817.48) ; R1RB_IDL_17_12_TerB18.2@3457.78,-2734.31 3466.29,-2742.81 CRB_IDL_17_12_TerB18.2@3506.6,-2742.81 3582.79,-2742.81 v1(3592.12,-2733.48) ; R1RB_IDL_17_12_TerB17.2@3457.78,-2634.31 3466.29,-2642.81 CRB_IDL_17_12_TerB17.2@3506.6,-2642.81 3521.78,-2627.63 v1(3551.65,-2627.63) ; R1RB_IDL_17_12_TerB16.2@3457.78,-2534.31 3466.29,-2542.81 CRB_IDL_17_12_TerB16.2@3506.6,-2542.81 3524.94,-2542.81 3550.27,-2517.48 v1(3560.12,-2517.48) ; R1RB_IDL_17_12_TerB15.2@3457.78,-2429.31 3469,-2429.31 3477.5,-2437.81 CRB_IDL_17_12_TerB15.2@3506.6,-2437.81 3534.91,-2409.51 3554.87,-2409.51 3566.41,-2397.97 v1(3603.72,-2397.97) ; R1RB_IDL_17_12_TerB14.2@3457.78,-2329.31 3498.1,-2329.31 CRB_IDL_17_12_TerB14.2@3506.6,-2337.81 3525.45,-2318.96 3553.64,-2318.96 v1(3560.12,-2312.48) ; R1RB_IDL_17_12_TerB13.2@3457.78,-2229.31 3466.29,-2237.81 CRB_IDL_17_12_TerB13.2@3506.6,-2237.81 3524.94,-2237.81 3560.12,-2202.63 3563.45,-2205.96 v1(3564.24,-2205.96) ; R1RB_IDL_17_12_TerB12.2@3457.78,-2129.31 3466.29,-2137.81 CRB_IDL_17_12_TerB12.2@3506.6,-2137.81 3534.79,-2137.81 3560.12,-2112.48 v1(3560.12,-2096.48) ; R1RB_IDL_17_12_TerB11.2@3457.78,-2029.31 3466.29,-2037.81 CRB_IDL_17_12_TerB11.2@3506.6,-2037.81 3534.79,-2037.81 3560.12,-2012.48 v1(3560.12,-1996.48) ; R1RB_IDL_17_12_TerB10.2@3457.78,-1924.31 3466.29,-1932.81 CRB_IDL_17_12_TerB10.2@3506.6,-1932.81 3527.88,-1932.81 3550.68,-1910.02 3583.33,-1910.02 3605.89,-1932.58 v1@3606.12,-1932.81 ; R1RB_IDL_17_12_TerB9.2@3457.78,-1824.31 3466.29,-1832.81 CRB_IDL_17_12_TerB9.2@3506.6,-1832.81 3559.96,-1832.81 v1(3560.95,-1831.82) ; R1RB_IDL_17_12_TerB8.2@3457.78,-1724.31 3466.29,-1732.81 CRB_IDL_17_12_TerB8.2@3506.6,-1732.81 3527.31,-1732.81 3568.64,-1691.48 v1(3592.12,-1691.48) ; R1RB_IDL_17_12_TerB7.2@3457.78,-1624.31 3466.29,-1632.81 CRB_IDL_17_12_TerB7.2@3506.6,-1632.81 3536.29,-1603.13 v1(3546.97,-1603.13) ; R1RB_IDL_17_12_TerB6.2@3457.78,-1521.31 3466.29,-1529.81 CRB_IDL_17_12_TerB6.2@3506.6,-1529.81 3544.9,-1491.52 v1(3569.4,-1491.52) ; R1RB_IDL_17_12_TerB5.2@3457.78,-1421.31 3466.29,-1429.81 CRB_IDL_17_12_TerB5.2@3506.6,-1429.81 v1@3553.65,-1429.81 ; R1RB_IDL_17_12_TerB4.2@3457.78,-1321.31 3466.29,-1329.81 CRB_IDL_17_12_TerB4.2@3506.6,-1329.81 v1@3556.23,-1329.81 ; R1RB_IDL_17_12_TerB3.2@3457.78,-1221.31 3466.29,-1229.81 CRB_IDL_17_12_TerB3.2@3506.6,-1229.81 3534.79,-1229.81 v1(3560.12,-1204.48) ; R1RB_IDL_17_12_TerB2.2@3457.78,-1116.31 3466.29,-1124.81 CRB_IDL_17_12_TerB2.2@3506.6,-1124.81 3547.93,-1083.48 v1(3560.12,-1083.48) ; R1RB_IDL_17_12_TerB32.2@3457.87,-4164.87 CRB_IDL_17_12_TerB32.2@3506.2,-4164.87 3513.39,-4172.06 v1(3554.44,-4172.06) ; v1(3487.68,-960.63) 3486.47,-960.63 3486.47,-979.46 R1RB_IDL_17_12_TerB1.2@3457.09,-1008.84 3465.59,-1017.34 CRB_IDL_17_12_TerB1.2@3505.91,-1017.34 ; R1R_IDL_17_12_TerA23.2@3496.29,1120.07 3502.2,1114.16 CR_IDL_17_12_TerA23.2@3545.25,1114.16 3545.74,1114.66 v1(3601.29,1114.66) ; R1R_IDL_17_12_TerA22.2@3496.29,1225.07 3502.2,1219.16 CR_IDL_17_12_TerA22.2@3545.25,1219.16 3563.59,1219.16 3588.92,1244.49 v1(3614.77,1244.49) ; R1R_IDL_17_12_TerA21.2@3496.29,1330.07 3539.34,1330.07 CR_IDL_17_12_TerA21.2@3545.25,1324.16 3563.59,1324.16 3581.55,1342.12 v1(3614.97,1342.12) ; R1R_IDL_17_12_TerA20.2@3496.29,1435.07 3539.34,1435.07 CR_IDL_17_12_TerA20.2@3545.25,1429.16 3546.67,1430.58 3568.1,1430.58 3589.33,1451.8 3619.87,1451.8 v1(3641.09,1430.58) ; R1R_IDL_17_12_TerA19.2@3496.29,1540.07 3499.72,1543.49 3545.25,1543.49 v1(3582.77,1543.49) ; R1R_IDL_17_12_TerA18.2@3496.29,1645.07 3502.2,1639.16 CR_IDL_17_12_TerA18.2@3545.25,1639.16 3570.58,1664.49 v1(3598.77,1664.49) ; R1R_IDL_17_12_TerA17.2@3496.29,1747.68 3545.25,1747.68 v1(3595.34,1747.68) ; R1R_IDL_17_12_TerA16.2@3496.29,1853.07 3502.2,1847.16 CR_IDL_17_12_TerA16.2@3545.25,1847.16 3552.63,1854.55 v1(3552.63,1911.09) ; CRB_IDL_17_12_TerB26.2@3506.59,-3550.24 3514.6,-3550.08 3558.63,-3550.08 v1(3598.99,-3590.44) ; v1@3560.44,-3344.08 v1(3556.33,-3344.08) 3549.59,-3350.81 CRB_IDL_17_12_TerB24.2@3506.6,-3350.81 3477.5,-3350.81 ; v1(3835.08,-2041.02) 3856.73,-2062.68 R1RB_IDL_17_12_TerB40.2@3856.73,-2094.54 3865.24,-2103.05 CRB_IDL_17_12_TerB40.2@3905.55,-2103.05 ; R1RB_IDL_17_12_TerB57.2@3847.52,-4037.02 3851.69,-4037.02 CRB_IDL_17_12_TerB57.2@3900.51,-4037.02 3907.21,-4030.33 v1(3946.67,-4030.33) ; R1RB_IDL_17_12_TerB56.2@3851.73,-3917.54 3851.73,-3926.05 CRB_IDL_17_12_TerB56.2@3900.55,-3926.05 3908.32,-3933.81 v1(3953.35,-3933.81) ; R1RB_IDL_17_12_TerB55.2@3851.73,-3817.54 3860.24,-3826.05 CRB_IDL_17_12_TerB55.2@3900.55,-3826.05 3961.69,-3826.05 v1(3975.74,-3812) ; R1RB_IDL_17_12_TerB54.2@3851.73,-3717.54 3851.73,-3726.05 CRB_IDL_17_12_TerB54.2@3900.55,-3726.05 3939.37,-3726.05 v1(3952.88,-3712.54) ; R1RB_IDL_17_12_TerB53.2@3851.73,-3612.54 3860.24,-3621.05 CRB_IDL_17_12_TerB53.2@3900.55,-3621.05 3939.18,-3621.05 ; R1RB_IDL_17_12_TerB52.2@3851.73,-3512.54 3860.24,-3521.05 CRB_IDL_17_12_TerB52.2@3900.55,-3521.05 3928.74,-3521.05 v1(3954.07,-3495.72) ; R1RB_IDL_17_12_TerB51.2@3851.73,-3414.54 3860.24,-3423.05 CRB_IDL_17_12_TerB51.2@3900.55,-3423.05 3928.74,-3423.05 v1(3954.07,-3397.72) ; R1RB_IDL_17_12_TerB50.2@3851.73,-3314.54 3860.24,-3323.05 CRB_IDL_17_12_TerB50.2@3900.55,-3323.05 3944.74,-3323.05 v1(3954.07,-3313.72) ; R1RB_IDL_17_12_TerB49.2@3852.45,-3223.05 CRB_IDL_17_12_TerB49.2@3900.55,-3223.05 3941.88,-3181.72 v1(3954.07,-3181.72) ; R1RB_IDL_17_12_TerB47.2@3854.98,-2848.05 3856.73,-2848.05 CRB_IDL_17_12_TerB47.2@3905.55,-2848.05 3930.88,-2822.72 v1(3959.07,-2822.72) ; R1RB_IDL_17_12_TerB46.2@3856.66,-2743.05 3856.73,-2743.05 CRB_IDL_17_12_TerB46.2@3905.55,-2743.05 3952.4,-2743.05 v1(3959.07,-2749.72) ; R1RB_IDL_17_12_TerB44.2@3856.73,-2519.54 3856.73,-2528.05 CRB_IDL_17_12_TerB44.2@3905.55,-2528.05 3914.52,-2537.01 v1(3948.08,-2537.01) ; R1RB_IDL_17_12_TerB43.2@3856.73,-2414.54 3865.24,-2423.05 CRB_IDL_17_12_TerB43.2@3905.55,-2423.05 4000.4,-2423.05 v1(4021.07,-2443.72) ; R1RB_IDL_17_12_TerB42.2@3856.73,-2309.54 3865.24,-2318.05 CRB_IDL_17_12_TerB42.2@3905.55,-2318.05 3923.89,-2318.05 3949.22,-2292.72 v1(3959.07,-2292.72) ; R1RB_IDL_17_12_TerB41.2@3856.76,-2213.05 CRB_IDL_17_12_TerB41.2@3905.55,-2213.05 3933.74,-2213.05 v1(3943.07,-2203.72) ; R1RB_IDL_17_12_TerB45.2@3858.06,-2638.05 CRB_IDL_17_12_TerB45.2@3905.55,-2638.05 3949.74,-2638.05 v1(3959.07,-2628.72) ; R1RB_IDL_17_12_TerB39.2@3861.73,-1912.89 3861.73,-1921.39 CRB_IDL_17_12_TerB39.2@3910.55,-1921.39 v1@3955.44,-1921.39 ; R1RB_IDL_17_12_TerB38.2@3861.73,-1812.89 3902.05,-1812.89 CRB_IDL_17_12_TerB38.2@3910.55,-1821.39 3918.34,-1829.18 v1(3955.89,-1829.18) ; R1RB_IDL_17_12_TerB37.2@3861.73,-1712.89 3870.24,-1721.39 CRB_IDL_17_12_TerB37.2@3910.55,-1721.39 3954.74,-1721.39 v1(3964.07,-1712.06) ; R1RB_IDL_17_12_TerB36.2@3861.73,-1609.89 3870.24,-1618.39 CRB_IDL_17_12_TerB36.2@3910.55,-1618.39 3953.59,-1618.39 v1(3962.92,-1609.06) ; R1RB_IDL_17_12_TerB35.2@3861.73,-1509.89 3870.24,-1518.39 CRB_IDL_17_12_TerB35.2@3910.55,-1518.39 3935.88,-1493.06 v1(3964.07,-1493.06) ; R1RB_IDL_17_12_TerB34.2@3861.73,-1409.89 3870.24,-1418.39 CRB_IDL_17_12_TerB34.2@3910.55,-1418.39 v1@3968.21,-1418.39 ; R1RB_IDL_17_12_TerB33.2@3863.95,-1318.39 CRB_IDL_17_12_TerB33.2@3910.55,-1318.39 3935.88,-1293.06 v1(3964.07,-1293.06) ; v1(3876.08,-3056.02) 3876.08,-3066.37 3851.73,-3090.71 R1RB_IDL_17_12_TerB48.2@3851.73,-3109.54 3860.24,-3118.05 CRB_IDL_17_12_TerB48.2@3900.55,-3118.05 ; R1R_IDL_17_12_TerA40.2@3920.94,2291.18 3926.85,2285.27 CR_IDL_17_12_TerA40.2@3969.9,2285.27 ; R1R_IDL_17_12_TerA39.2@3920.94,2396.18 3926.85,2390.27 CR_IDL_17_12_TerA39.2@3969.9,2390.27 3976.45,2396.82 v1(4021.26,2396.82) ; R1R_IDL_17_12_TerA38.2@3920.94,2501.18 3926.85,2495.27 CR_IDL_17_12_TerA38.2@3969.9,2495.27 4016.63,2495.27 v1(4030.43,2509.06) ; R1R_IDL_17_12_TerA37.2@3920.94,2606.18 3926.85,2600.27 CR_IDL_17_12_TerA37.2@3969.9,2600.27 3978.01,2592.16 v1(4026.76,2592.16) ; R1R_IDL_17_12_TerA36.2@3920.94,2711.18 3949.24,2705.27 CR_IDL_17_12_TerA36.2@3969.9,2705.27 3990.41,2684.75 v1(4021.17,2684.75) ; R1R_IDL_17_12_TerA35.2@3920.94,2816.18 3926.85,2810.27 CR_IDL_17_12_TerA35.2@3969.9,2810.27 3988.24,2810.27 4013.57,2835.6 v1(4023.42,2835.6) ; R1R_IDL_17_12_TerA34.2@3920.94,2921.18 3963.99,2921.18 CR_IDL_17_12_TerA34.2@3969.9,2915.27 3988.24,2915.27 4013.57,2940.6 v1(4023.42,2940.6) ; R1R_IDL_17_12_TerA32.2@3920.94,3301.18 3963.99,3301.18 CR_IDL_17_12_TerA32.2@3969.9,3295.27 3977.31,3287.85 v1(4021.79,3287.85) ; R1R_IDL_17_12_TerA31.2@3920.94,3409.18 3926.85,3403.27 CR_IDL_17_12_TerA31.2@3969.9,3403.27 3988.24,3403.27 4013.57,3428.6 v1(4023.42,3428.6) ; R1R_IDL_17_12_TerA30.2@3920.94,3514.18 3926.85,3508.27 CR_IDL_17_12_TerA30.2@3969.9,3508.27 3988.24,3508.27 v1(4013.57,3533.6) ; R1R_IDL_17_12_TerA29.2@3920.94,3619.18 3963.99,3619.18 CR_IDL_17_12_TerA29.2@3969.9,3613.27 3990.08,3593.08 v1(4015.98,3593.08) ; R1R_IDL_17_12_TerA28.2@3920.94,3724.18 3926.85,3718.27 CR_IDL_17_12_TerA28.2@3969.9,3718.27 4019.97,3718.27 v1(4022.54,3715.7) ; R1R_IDL_17_12_TerA27.2@3920.94,3829.18 3926.85,3823.27 CR_IDL_17_12_TerA27.2@3969.9,3823.27 3995.23,3848.6 v1(4023.42,3848.6) ; R1R_IDL_17_12_TerA26.2@3920.94,3934.18 3926.85,3928.27 CR_IDL_17_12_TerA26.2@3969.9,3928.27 3988.24,3928.27 4013.57,3953.6 v1(4023.42,3953.6) ; R1R_IDL_17_12_TerA25.2@3920.94,4039.18 3926.85,4033.27 CR_IDL_17_12_TerA25.2@3969.9,4033.27 CR_IDL_17_12_TerA25.2@3971.36,4033.27 ; R1R_IDL_17_12_TerA24.2@3920.94,4144.18 3963.99,4144.18 CR_IDL_17_12_TerA24.2@3969.9,4138.27 3988.24,4138.27 4013.57,4163.6 v1(4023.42,4163.6) ; R1R_IDL_17_12_TerA43.2@3926.77,1176.77 CR_IDL_17_12_TerA43.2@3975.73,1176.77 3997.27,1176.77 4022.38,1201.89 v1(4030.31,1201.89) ; R1R_IDL_17_12_TerA42.2@3926.84,1305.65 3932.75,1299.74 CR_IDL_17_12_TerA42.2@3975.8,1299.74 4019.99,1299.74 v1(4029.32,1309.07) ; R1R_IDL_17_12_TerA41.2@3926.84,1399.74 CR_IDL_17_12_TerA41.2@3975.8,1399.74 4019.99,1399.74 v1(4029.32,1409.07) ; v1(3945.29,3079.7) 3920.94,3055.35 R1R_IDL_17_12_TerA33.2@3920.94,3026.18 3926.85,3020.27 CR_IDL_17_12_TerA33.2@3969.9,3020.27 ; CR_IDL_17_12_TerA25.2@3969.63,4031.54 3970.63,4032.54 CR_IDL_17_12_TerA25.2@3971.36,4033.27 ; CR_IDL_17_12_TerA40.2@3969.9,2280.56 v1(4019.62,2280.56) ; v1(4033.1,4044.15) 4022.22,4033.27 CR_IDL_17_12_TerA25.2@3971.36,4033.27 ; R1RB_IDL_17_12_TerB88.2@4401.47,-4147.25 4409.97,-4155.75 CRB_IDL_17_12_TerB88.2@4450.29,-4155.75 4491.11,-4155.75 v1(4498.65,-4148.21) ; R1RB_IDL_17_12_TerB87.2@4401.47,-4047.25 4409.97,-4055.75 CRB_IDL_17_12_TerB87.2@4450.29,-4055.75 4475.62,-4030.42 v1(4503.81,-4030.42) ; R1RB_IDL_17_12_TerB86.2@4401.47,-3947.25 4409.97,-3955.75 CRB_IDL_17_12_TerB86.2@4450.29,-3955.75 4475.62,-3930.42 v1(4503.81,-3930.42) ; R1RB_IDL_17_12_TerB85.2@4401.47,-3842.25 4409.97,-3850.75 CRB_IDL_17_12_TerB85.2@4450.29,-3850.75 4475.62,-3825.42 v1(4503.81,-3825.42) ; R1RB_IDL_17_12_TerB84.2@4401.47,-3742.25 4409.97,-3750.75 CRB_IDL_17_12_TerB84.2@4450.29,-3750.75 4483.81,-3750.75 v1(4496.45,-3738.11) ; R1RB_IDL_17_12_TerB83.2@4401.47,-3642.25 4402.47,-3641.25 4411.39,-3650.17 4450.29,-3650.17 v1(4499.28,-3650.17) ; R1RB_IDL_17_12_TerB82.2@4401.47,-3542.25 4409.97,-3550.75 CRB_IDL_17_12_TerB82.2@4450.29,-3550.75 4475.62,-3525.42 v1(4503.81,-3525.42) ; R1RB_IDL_17_12_TerB81.2@4401.47,-3440.25 4409.97,-3448.75 CRB_IDL_17_12_TerB81.2@4450.29,-3448.75 4475.62,-3423.42 v1(4503.81,-3423.42) ; R1RB_IDL_17_12_TerB80.2@4401.47,-3335.25 4404.19,-3337.97 4450.29,-3337.97 v1(4498.45,-3337.97) ; R1RB_IDL_17_12_TerB79.2@4401.47,-3235.25 4402.54,-3236.32 4450.29,-3236.32 v1(4497.78,-3236.32) ; R1RB_IDL_17_12_TerB78.2@4401.47,-3135.25 4406.56,-3140.34 CRB_IDL_17_12_TerB78.2@4450.29,-3140.34 ; R1RB_IDL_17_12_TerB77.2@4401.47,-3035.25 4404.48,-3038.27 4450.29,-3038.27 v1(4498.52,-3038.27) ; R1RB_IDL_17_12_TerB76.2@4401.47,-2930.25 4409.97,-2938.75 CRB_IDL_17_12_TerB76.2@4450.29,-2938.75 4475.62,-2913.42 v1(4503.81,-2913.42) ; R1RB_IDL_17_12_TerB75.2@4401.47,-2830.25 4403.4,-2832.18 4450.29,-2832.18 v1(4497.12,-2832.18) ; R1RB_IDL_17_12_TerB74.2@4401.47,-2730.25 4409.97,-2738.75 CRB_IDL_17_12_TerB74.2@4450.29,-2738.75 4475.62,-2713.42 v1(4503.81,-2713.42) ; R1RB_IDL_17_12_TerB73.2@4401.47,-2630.25 4409.97,-2638.75 CRB_IDL_17_12_TerB73.2@4450.29,-2638.75 4483.92,-2638.75 v1(4502.24,-2620.43) ; R1RB_IDL_17_12_TerB72.2@4401.47,-2525.25 4409.97,-2533.75 CRB_IDL_17_12_TerB72.2@4450.29,-2533.75 4485.47,-2498.56 v1(4503.81,-2498.56) ; R1RB_IDL_17_12_TerB71.2@4401.47,-2425.25 4409.97,-2433.75 CRB_IDL_17_12_TerB71.2@4450.29,-2433.75 4468.62,-2433.75 4493.95,-2408.42 v1(4503.81,-2408.42) ; R1RB_IDL_17_12_TerB70.2@4401.47,-2325.25 4409.97,-2333.75 CRB_IDL_17_12_TerB70.2@4450.29,-2333.75 4475.62,-2308.42 v1(4503.81,-2308.42) ; R1RB_IDL_17_12_TerB69.2@4401.47,-2225.25 4409.97,-2233.75 CRB_IDL_17_12_TerB69.2@4450.29,-2233.75 4475.62,-2208.42 v1(4503.81,-2208.42) ; R1RB_IDL_17_12_TerB68.2@4401.47,-2125.25 4403.97,-2127.76 CRB_IDL_17_12_TerB68.2@4450.29,-2127.76 ; R1RB_IDL_17_12_TerB67.2@4401.47,-2020.25 4409.97,-2028.75 CRB_IDL_17_12_TerB67.2@4450.29,-2028.75 4483.32,-1995.71 v1(4506.08,-1995.71) ; R1RB_IDL_17_12_TerB66.2@4401.47,-1918.25 4441.78,-1918.25 CRB_IDL_17_12_TerB66.2@4450.29,-1926.75 4478.48,-1926.75 v1(4503.81,-1901.42) ; R1RB_IDL_17_12_TerB65.2@4401.47,-1818.25 4409.97,-1826.75 CRB_IDL_17_12_TerB65.2@4450.29,-1826.75 4475.62,-1801.42 v1(4503.81,-1801.42) ; R1RB_IDL_17_12_TerB64.2@4401.47,-1718.25 4409.97,-1726.75 CRB_IDL_17_12_TerB64.2@4450.29,-1726.75 4475.62,-1701.42 v1(4503.81,-1701.42) ; R1RB_IDL_17_12_TerB63.2@4401.47,-1613.25 4409.97,-1621.75 CRB_IDL_17_12_TerB63.2@4450.29,-1621.75 4471.57,-1621.75 v1(4494.36,-1598.96) ; R1RB_IDL_17_12_TerB62.2@4401.47,-1513.25 4409.97,-1521.75 CRB_IDL_17_12_TerB62.2@4450.29,-1521.75 4475.62,-1496.42 v1(4503.81,-1496.42) ; R1RB_IDL_17_12_TerB61.2@4401.47,-1413.25 4409.97,-1421.75 CRB_IDL_17_12_TerB61.2@4450.29,-1421.75 4491.27,-1421.75 4516.6,-1396.42 v1(4519.81,-1396.42) ; R1RB_IDL_17_12_TerB60.2@4401.47,-1313.25 4409.97,-1321.75 CRB_IDL_17_12_TerB60.2@4450.29,-1321.75 4475.62,-1296.42 v1(4503.81,-1296.42) ; R1RB_IDL_17_12_TerB59.2@4401.47,-1208.25 4409.97,-1216.75 CRB_IDL_17_12_TerB59.2@4450.29,-1216.75 4498.05,-1216.75 v1(4498.56,-1217.26) ; R1RB_IDL_17_12_TerB58.2@4401.47,-1114.15 CRB_IDL_17_12_TerB58.2@4450.29,-1114.15 ; R1RB_IDL_17_12_TerB58.2@4401.47,-1108.25 4407.57,-1102.15 v1(4407.57,-1058.61) ; R1RB_IDL_17_12_TerB89.2@4403.41,-4262.25 4408.62,-4267.46 CRB_IDL_17_12_TerB89.2@4451.51,-4267.46 4469.85,-4267.46 4495.18,-4242.13 v1(4505.03,-4242.13) ; CRB_IDL_17_12_TerB78.2@4450.29,-3143.75 CRB_IDL_17_12_TerB78.2@4450.29,-3140.34 ; CRB_IDL_17_12_TerB68.2@4450.29,-2133.75 CRB_IDL_17_12_TerB68.2@4450.29,-2127.76 ; v1(4500.57,-2127.76) CRB_IDL_17_12_TerB68.2@4450.29,-2127.76 ; v1(4502.78,-3140.34) CRB_IDL_17_12_TerB78.2@4450.29,-3140.34 ; R1R_IDL_17_12_TerA71.2@4506.21,1290.84 4512.12,1284.93 CR_IDL_17_12_TerA71.2@4555.17,1284.93 4573.51,1284.93 4598.84,1310.26 v1(4608.69,1310.26) ; R1R_IDL_17_12_TerA70.2@4506.21,1395.84 4549.26,1395.84 CR_IDL_17_12_TerA70.2@4555.17,1389.93 4580.5,1415.26 v1(4608.69,1415.26) ; R1R_IDL_17_12_TerA69.2@4506.21,1500.84 4512.12,1494.93 CR_IDL_17_12_TerA69.2@4555.17,1494.93 4573.37,1513.13 v1(4605.44,1513.13) ; R1R_IDL_17_12_TerA68.2@4506.21,1605.84 4512.12,1599.93 CR_IDL_17_12_TerA68.2@4555.17,1599.93 4573.51,1599.93 4598.84,1625.26 v1(4608.69,1625.26) ; R1R_IDL_17_12_TerA67.2@4506.21,1710.84 4512.12,1704.93 CR_IDL_17_12_TerA67.2@4555.17,1704.93 4573.51,1704.93 4598.84,1730.26 v1(4608.69,1730.26) ; R1R_IDL_17_12_TerA66.2@4506.21,1815.84 4512.12,1809.93 CR_IDL_17_12_TerA66.2@4555.17,1809.93 4573.51,1809.93 4598.84,1835.26 v1(4608.69,1835.26) ; R1R_IDL_17_12_TerA65.2@4506.21,1920.84 4506.78,1921.41 4555.17,1921.41 v1(4607.39,1921.41) ; R1R_IDL_17_12_TerA64.2@4506.21,2025.84 4512.12,2019.93 CR_IDL_17_12_TerA64.2@4555.17,2019.93 4573.51,2019.93 4598.84,2045.26 v1(4608.69,2045.26) ; R1R_IDL_17_12_TerA63.2@4506.21,2130.84 4512.12,2124.93 CR_IDL_17_12_TerA63.2@4555.17,2124.93 4603.38,2124.93 v1(4614.59,2136.14) ; R1R_IDL_17_12_TerA61.2@4506.21,2343.84 4512.12,2337.93 CR_IDL_17_12_TerA61.2@4555.17,2337.93 4573.51,2337.93 4598.84,2363.26 v1(4608.69,2363.26) ; R1R_IDL_17_12_TerA60.2@4506.21,2448.84 4512.12,2442.93 CR_IDL_17_12_TerA60.2@4555.17,2442.93 4573.51,2442.93 4598.84,2468.26 v1(4608.69,2468.26) ; R1R_IDL_17_12_TerA59.2@4506.21,2553.84 4512.12,2547.93 CR_IDL_17_12_TerA59.2@4555.17,2547.93 4573.51,2547.93 4598.84,2573.26 v1(4608.69,2573.26) ; R1R_IDL_17_12_TerA57.2@4506.21,2763.84 4512.12,2757.93 CR_IDL_17_12_TerA57.2@4555.17,2757.93 4573.51,2757.93 4598.84,2783.26 v1(4608.69,2783.26) ; R1R_IDL_17_12_TerA56.2@4506.21,2868.84 4512.12,2862.93 CR_IDL_17_12_TerA56.2@4555.17,2862.93 4573.51,2862.93 4598.84,2888.26 v1(4608.69,2888.26) ; R1R_IDL_17_12_TerA55.2@4506.21,2973.84 4510.37,2969.68 4555.17,2969.68 v1(4617.06,2969.68) ; R1R_IDL_17_12_TerA54.2@4506.21,3078.84 4512.12,3072.93 CR_IDL_17_12_TerA54.2@4555.17,3072.93 4573.51,3072.93 4598.84,3098.26 v1(4608.69,3098.26) ; R1R_IDL_17_12_TerA53.2@4506.21,3183.84 4512.12,3177.93 CR_IDL_17_12_TerA53.2@4555.17,3177.93 4573.51,3177.93 4598.84,3203.26 v1(4608.69,3203.26) ; R1R_IDL_17_12_TerA52.2@4506.21,3288.84 4512.12,3282.93 CR_IDL_17_12_TerA52.2@4555.17,3282.93 4573.51,3282.93 4598.84,3308.26 v1(4608.69,3308.26) ; R1R_IDL_17_12_TerA50.2@4506.21,3498.84 4512.12,3492.93 CR_IDL_17_12_TerA50.2@4555.17,3492.93 4573.51,3492.93 4598.84,3518.26 v1(4608.69,3518.26) ; R1R_IDL_17_12_TerA49.2@4506.21,3603.84 4512.12,3597.93 CR_IDL_17_12_TerA49.2@4555.17,3597.93 4573.51,3597.93 4598.84,3623.26 v1(4608.69,3623.26) ; R1R_IDL_17_12_TerA48.2@4506.21,3708.84 4507.08,3709.7 4555.17,3709.7 v1(4618.83,3709.7) ; R1R_IDL_17_12_TerA47.2@4506.21,3813.84 4512.12,3807.93 CR_IDL_17_12_TerA47.2@4555.17,3807.93 4573.51,3807.93 4598.84,3833.26 v1(4608.69,3833.26) ; R1R_IDL_17_12_TerA46.2@4506.21,3916.84 4512.12,3910.93 CR_IDL_17_12_TerA46.2@4555.17,3910.93 4580.5,3936.26 v1(4608.69,3936.26) ; R1R_IDL_17_12_TerA45.2@4506.21,4021.84 4512.12,4015.93 CR_IDL_17_12_TerA45.2@4555.17,4015.93 4573.51,4015.93 4598.84,4041.26 v1(4608.69,4041.26) ; R1R_IDL_17_12_TerA44.2@4506.21,4126.84 4512.12,4120.93 CR_IDL_17_12_TerA44.2@4555.17,4120.93 4548.95,4127.15 v1(4548.95,4173.18) ; R1R_IDL_17_12_TerA72.2@4506.23,1180.28 4514.04,1172.47 CR_IDL_17_12_TerA72.2@4550.78,1172.47 ; R1R_IDL_17_12_TerA51.2@4506.21,3393.84 4555.17,3393.82 v1(4617.57,3393.82) ; R1R_IDL_17_12_TerA62.2@4511.09,2235.84 R1R_IDL_17_12_TerA62.2@4506.21,2235.84 4509.86,2232.19 4555.17,2232.19 v1(4609.47,2232.19) ; R1R_IDL_17_12_TerA58.2@4511.23,2663.86 R1R_IDL_17_12_TerA58.2@4506.21,2658.84 4512.12,2652.93 CR_IDL_17_12_TerA58.2@4555.17,2652.93 4589.79,2652.93 v1(4607.84,2670.98) ; CR_IDL_17_12_TerA72.2@4553.87,1172.47 CR_IDL_17_12_TerA72.2@4550.78,1172.47 ; v1(4615.25,1170.83) 4556.3,1170.83 4555.9,1170.43 4554.36,1168.89 4552.32,1170.93 CR_IDL_17_12_TerA72.2@4550.78,1172.47 ; 3477.5,-3350.81 3466.29,-3350.81 R1RB_IDL_17_12_TerB24.2@3457.78,-3342.31 3469,-3342.31 3477.5,-3350.81
  other v1: 3949.95,-3612.7 3608.27,-1930.2 3955.44,-1921.61 3553.65,-1432.21 3968.21,-1416.77 3556.23,-1327.37
12V: Jtop1.C31 Jtop2.C31 Jtop3.C31 Jtop4.C31 PT5.1 PT5.2 PT5.3 PT5.4 PT5.5 PT5.6
-3V3: -3V3.1 -3V3.2 -3V3.3 -3V3.4 -3V3.5 -3V3.6 JMid1.27 JMid1.28 JMid1.46 JMid1.47 JMid1.65 JMid1.66 JMid1.83 JMid1.84 JMid1.85 JMid2.27 JMid2.28 JMid2.46 JMid2.47 JMid2.65 JMid2.66 JMid2.83 JMid2.84 JMid2.85 JMid3.27 JMid3.28 JMid3.46 JMid3.47 JMid3.65 JMid3.66 JMid3.83 JMid3.84 JMid3.85 JMid4.27 JMid4.28 JMid4.46 JMid4.47 JMid4.65 JMid4.66 JMid4.83 JMid4.84 JMid4.85
-5V: -5V.1 -5V.2 -5V.3 -5V.4 -5V.5 -5V.6 JMid1.30 JMid1.49 JMid1.68 JMid1.87 JMid2.30 JMid2.49 JMid2.68 JMid2.87 JMid3.30 JMid3.49 JMid3.68 JMid3.87 JMid4.30 JMid4.49 JMid4.68 JMid4.87
-12V: -12V.1 -12V.2 -12V.3 -12V.4 -12V.5 -12V.6 Jtop1.A31 Jtop2.A31 Jtop3.A31 Jtop4.A31
BG0IN_5: Jtop1.B4 Jtop2.B4 Jtop3.B4 Jtop4.B4 | length 2505.9
  Bot Signal w8: Jtop1.B4@128.79,1382.06 171.69,1424.96 846.32,1424.96 888.8,1382.48 918.19,1382.48 Jtop2.B4@928.72,1382.48 ; Jtop2.B4@948.2,1379.26 991.1,1422.16 1665.73,1422.16 1708.21,1379.68 1729.28,1379.68 Jtop3.B4@1748.13,1379.68 ; Jtop3.B4@1756.8,1388.51 1799.7,1431.41 2474.33,1431.41 2516.81,1388.93 2529.28,1388.93 Jtop4.B4@2556.73,1388.93
BG0OUT_5: Jtop1.B5 Jtop2.B5 Jtop3.B5 Jtop4.B5 | length 2505.9
  Bot Signal w8: Jtop1.B5@128.79,1482.06 171.69,1524.96 846.32,1524.96 888.8,1482.48 918.19,1482.48 Jtop2.B5@928.72,1482.48 ; Jtop2.B5@948.2,1479.26 991.1,1522.16 1665.73,1522.16 1708.21,1479.68 1729.28,1479.68 Jtop3.B5@1748.13,1479.68 ; Jtop3.B5@1756.8,1488.51 1799.7,1531.41 2474.33,1531.41 2516.81,1488.93 2529.28,1488.93 Jtop4.B5@2556.73,1488.93
BG1IN_5: Jtop1.B6 Jtop2.B6 Jtop3.B6 Jtop4.B6 | length 2505.9
  Bot Signal w8: Jtop1.B6@128.79,1582.06 171.69,1624.96 846.32,1624.96 888.8,1582.48 918.19,1582.48 Jtop2.B6@928.72,1582.48 ; Jtop2.B6@948.2,1579.26 991.1,1622.16 1665.73,1622.16 1708.21,1579.68 1729.28,1579.68 Jtop3.B6@1748.13,1579.68 ; Jtop3.B6@1756.8,1588.51 1799.7,1631.41 2474.33,1631.41 2516.81,1588.93 2529.28,1588.93 Jtop4.B6@2556.73,1588.93
BG1OUT_5: Jtop1.B7 Jtop2.B7 Jtop3.B7 Jtop4.B7 | length 2505.9
  Bot Signal w8: Jtop1.B7@128.79,1682.06 171.69,1724.96 846.32,1724.96 888.8,1682.48 918.19,1682.48 Jtop2.B7@928.72,1682.48 ; Jtop2.B7@948.2,1679.26 991.1,1722.16 1665.73,1722.16 1708.21,1679.68 1729.28,1679.68 Jtop3.B7@1748.13,1679.68 ; Jtop3.B7@1756.8,1688.51 1799.7,1731.41 2474.33,1731.41 2516.81,1688.93 2529.28,1688.93 Jtop4.B7@2556.73,1688.93
BG2IN_5: Jtop1.B8 Jtop2.B8 Jtop3.B8 Jtop4.B8 | length 2505.9
  Bot Signal w8: Jtop1.B8@128.79,1782.06 171.69,1824.96 846.32,1824.96 888.8,1782.48 918.19,1782.48 Jtop2.B8@928.72,1782.48 ; Jtop2.B8@948.2,1779.26 991.1,1822.16 1665.73,1822.16 1708.21,1779.68 1729.28,1779.68 Jtop3.B8@1748.13,1779.68 ; Jtop3.B8@1756.8,1788.51 1799.7,1831.41 2474.33,1831.41 2516.81,1788.93 2529.28,1788.93 Jtop4.B8@2556.73,1788.93
BG2OUT_5: Jtop1.B9 Jtop2.B9 Jtop3.B9 Jtop4.B9 | length 2505.9
  Bot Signal w8: Jtop1.B9@128.79,1882.06 171.69,1924.96 846.32,1924.96 888.8,1882.48 918.19,1882.48 Jtop2.B9@928.72,1882.48 ; Jtop2.B9@948.2,1879.26 991.1,1922.16 1665.73,1922.16 1708.21,1879.68 1729.28,1879.68 Jtop3.B9@1748.13,1879.68 ; Jtop3.B9@1756.8,1888.51 1799.7,1931.41 2474.33,1931.41 2516.81,1888.93 2529.28,1888.93 Jtop4.B9@2556.73,1888.93
BG3IN_5: Jtop1.B10 Jtop2.B10 Jtop3.B10 Jtop4.B10 | length 2505.9
  Bot Signal w8: Jtop1.B10@128.79,1982.06 171.69,2024.96 846.32,2024.96 888.8,1982.48 918.19,1982.48 Jtop2.B10@928.72,1982.48 ; Jtop2.B10@948.2,1979.26 991.1,2022.16 1665.73,2022.16 1708.21,1979.68 1729.28,1979.68 Jtop3.B10@1748.13,1979.68 ; Jtop3.B10@1756.8,1988.51 1799.7,2031.41 2474.33,2031.41 2516.81,1988.93 2529.28,1988.93 Jtop4.B10@2556.73,1988.93
BG3OUT_5: Jtop1.B11 Jtop2.B11 Jtop3.B11 Jtop4.B11 | length 2505.9
  Bot Signal w8: Jtop1.B11@128.79,2082.06 171.69,2124.96 846.32,2124.96 888.8,2082.48 918.19,2082.48 Jtop2.B11@928.72,2082.48 ; Jtop2.B11@948.2,2079.26 991.1,2122.16 1665.73,2122.16 1708.21,2079.68 1729.28,2079.68 Jtop3.B11@1748.13,2079.68 ; Jtop3.B11@1756.8,2088.51 1799.7,2131.41 2474.33,2131.41 2516.81,2088.93 2529.28,2088.93 Jtop4.B11@2556.73,2088.93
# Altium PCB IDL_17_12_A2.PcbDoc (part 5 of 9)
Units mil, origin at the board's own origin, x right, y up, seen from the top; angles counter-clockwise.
Board outline 5119.97 x 10350 mil, 6 copper layers (Top Signal, 3.3 Volt, GND, 5 Volt, Split Plane, Bot Signal), stack 66.2 mil thick; 514 components, 178 nets, 2321 pads, 427 vias.

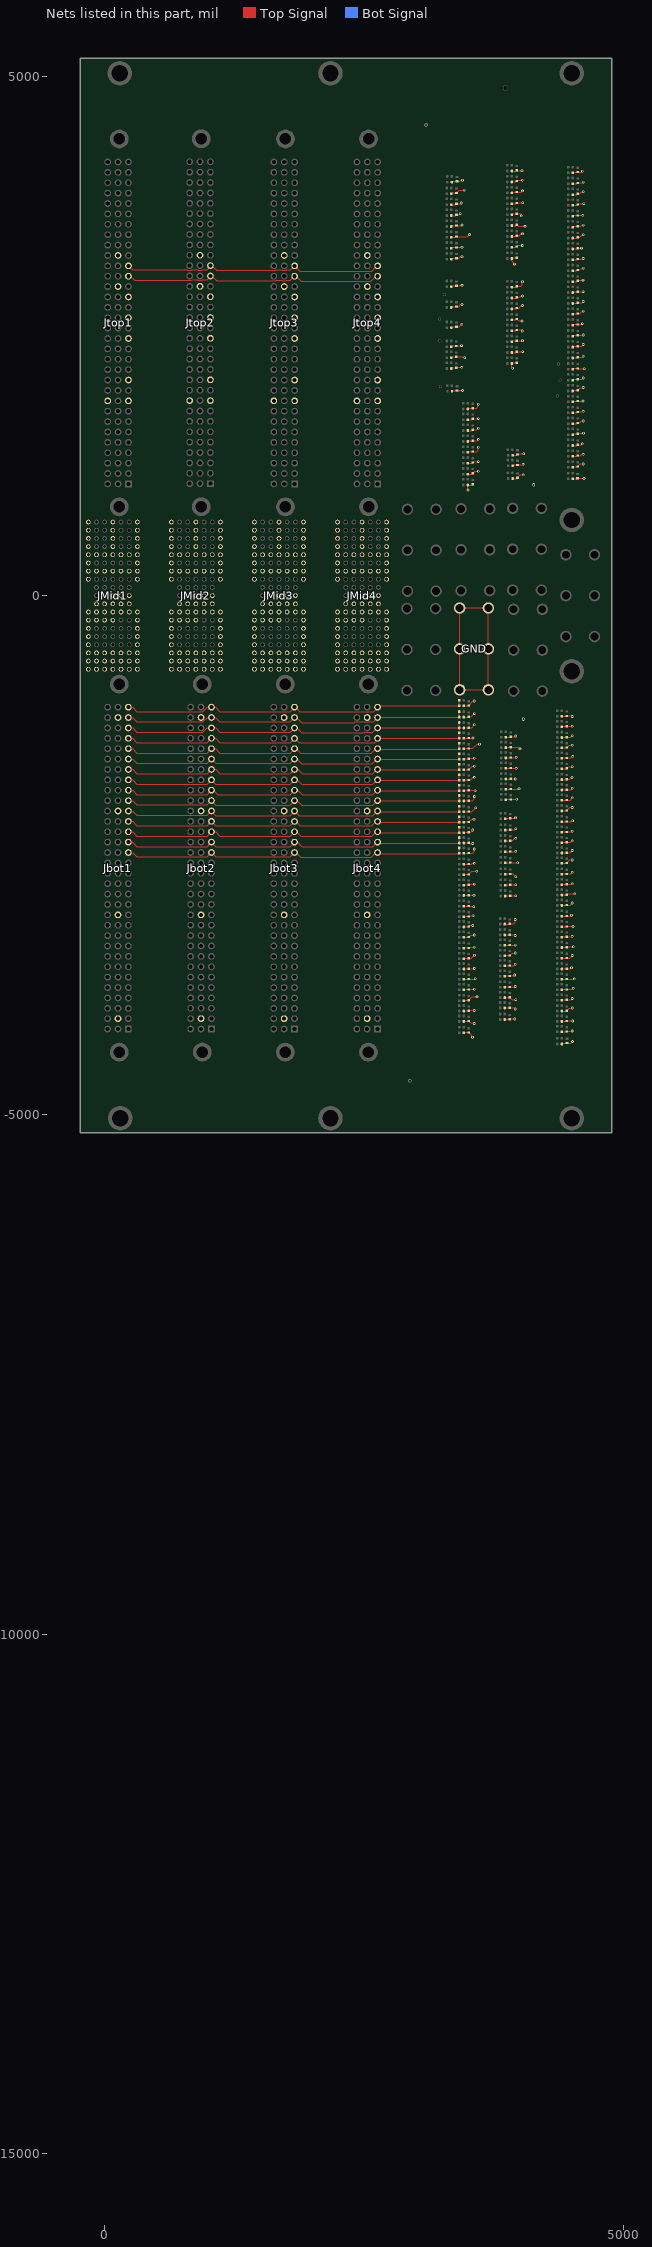
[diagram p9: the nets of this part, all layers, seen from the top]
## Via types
v1: diameter 25.59, hole 11.81, Top Signal to Bot Signal, 427 vias

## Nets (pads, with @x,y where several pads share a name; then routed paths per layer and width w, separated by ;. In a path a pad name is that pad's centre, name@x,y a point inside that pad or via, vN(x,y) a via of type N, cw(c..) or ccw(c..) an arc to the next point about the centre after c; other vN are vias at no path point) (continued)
GND: CR_IDL_17_12_TerA1.1 CR_IDL_17_12_TerA2.1 CR_IDL_17_12_TerA3.1 CR_IDL_17_12_TerA4.1 CR_IDL_17_12_TerA5.1 CR_IDL_17_12_TerA6.1 CR_IDL_17_12_TerA7.1 CR_IDL_17_12_TerA8.1 CR_IDL_17_12_TerA9.1 CR_IDL_17_12_TerA10.1 CR_IDL_17_12_TerA11.1 CR_IDL_17_12_TerA12.1 CR_IDL_17_12_TerA13.1 CR_IDL_17_12_TerA14.1 CR_IDL_17_12_TerA15.1 CR_IDL_17_12_TerA16.1 CR_IDL_17_12_TerA17.1 CR_IDL_17_12_TerA18.1 CR_IDL_17_12_TerA19.1 CR_IDL_17_12_TerA20.1 CR_IDL_17_12_TerA21.1 CR_IDL_17_12_TerA22.1 CR_IDL_17_12_TerA23.1 CR_IDL_17_12_TerA24.1 CR_IDL_17_12_TerA25.1 CR_IDL_17_12_TerA26.1 CR_IDL_17_12_TerA27.1 CR_IDL_17_12_TerA28.1 CR_IDL_17_12_TerA29.1 CR_IDL_17_12_TerA30.1 CR_IDL_17_12_TerA31.1 CR_IDL_17_12_TerA32.1 CR_IDL_17_12_TerA33.1 CR_IDL_17_12_TerA34.1 CR_IDL_17_12_TerA35.1 CR_IDL_17_12_TerA36.1 CR_IDL_17_12_TerA37.1 CR_IDL_17_12_TerA38.1 CR_IDL_17_12_TerA39.1 CR_IDL_17_12_TerA40.1 CR_IDL_17_12_TerA41.1 CR_IDL_17_12_TerA42.1 CR_IDL_17_12_TerA43.1 CR_IDL_17_12_TerA44.1 CR_IDL_17_12_TerA45.1 CR_IDL_17_12_TerA46.1 CR_IDL_17_12_TerA47.1 CR_IDL_17_12_TerA48.1 CR_IDL_17_12_TerA49.1 CR_IDL_17_12_TerA50.1 CR_IDL_17_12_TerA51.1 CR_IDL_17_12_TerA52.1 CR_IDL_17_12_TerA53.1 CR_IDL_17_12_TerA54.1 CR_IDL_17_12_TerA55.1 CR_IDL_17_12_TerA56.1 CR_IDL_17_12_TerA57.1 CR_IDL_17_12_TerA58.1 CR_IDL_17_12_TerA59.1 CR_IDL_17_12_TerA60.1 CR_IDL_17_12_TerA61.1 CR_IDL_17_12_TerA62.1 CR_IDL_17_12_TerA63.1 CR_IDL_17_12_TerA64.1 CR_IDL_17_12_TerA65.1 CR_IDL_17_12_TerA66.1 CR_IDL_17_12_TerA67.1 CR_IDL_17_12_TerA68.1 CR_IDL_17_12_TerA69.1 CR_IDL_17_12_TerA70.1 CR_IDL_17_12_TerA71.1 CR_IDL_17_12_TerA72.1 CRB_IDL_17_12_TerB1.1 CRB_IDL_17_12_TerB2.1 CRB_IDL_17_12_TerB3.1 CRB_IDL_17_12_TerB4.1 CRB_IDL_17_12_TerB5.1 CRB_IDL_17_12_TerB6.1 CRB_IDL_17_12_TerB7.1 CRB_IDL_17_12_TerB8.1 CRB_IDL_17_12_TerB9.1 CRB_IDL_17_12_TerB10.1 CRB_IDL_17_12_TerB11.1 CRB_IDL_17_12_TerB12.1 CRB_IDL_17_12_TerB13.1 CRB_IDL_17_12_TerB14.1 CRB_IDL_17_12_TerB15.1 CRB_IDL_17_12_TerB16.1 CRB_IDL_17_12_TerB17.1 CRB_IDL_17_12_TerB18.1 CRB_IDL_17_12_TerB19.1 CRB_IDL_17_12_TerB20.1 CRB_IDL_17_12_TerB21.1 CRB_IDL_17_12_TerB22.1 CRB_IDL_17_12_TerB23.1 CRB_IDL_17_12_TerB24.1 CRB_IDL_17_12_TerB25.1 CRB_IDL_17_12_TerB26.1 CRB_IDL_17_12_TerB27.1 CRB_IDL_17_12_TerB28.1 CRB_IDL_17_12_TerB29.1 CRB_IDL_17_12_TerB30.1 CRB_IDL_17_12_TerB31.1 CRB_IDL_17_12_TerB32.1 CRB_IDL_17_12_TerB33.1 CRB_IDL_17_12_TerB34.1 CRB_IDL_17_12_TerB35.1 CRB_IDL_17_12_TerB36.1 CRB_IDL_17_12_TerB37.1 CRB_IDL_17_12_TerB38.1 CRB_IDL_17_12_TerB39.1 CRB_IDL_17_12_TerB40.1 CRB_IDL_17_12_TerB41.1 CRB_IDL_17_12_TerB42.1 CRB_IDL_17_12_TerB43.1 CRB_IDL_17_12_TerB44.1 CRB_IDL_17_12_TerB45.1 CRB_IDL_17_12_TerB46.1 CRB_IDL_17_12_TerB47.1 CRB_IDL_17_12_TerB48.1 CRB_IDL_17_12_TerB49.1 CRB_IDL_17_12_TerB50.1 CRB_IDL_17_12_TerB51.1 CRB_IDL_17_12_TerB52.1 CRB_IDL_17_12_TerB53.1 CRB_IDL_17_12_TerB54.1 CRB_IDL_17_12_TerB55.1 CRB_IDL_17_12_TerB56.1 CRB_IDL_17_12_TerB57.1 CRB_IDL_17_12_TerB58.1 CRB_IDL_17_12_TerB59.1 CRB_IDL_17_12_TerB60.1 CRB_IDL_17_12_TerB61.1 CRB_IDL_17_12_TerB62.1 CRB_IDL_17_12_TerB63.1 CRB_IDL_17_12_TerB64.1 CRB_IDL_17_12_TerB65.1 CRB_IDL_17_12_TerB66.1 CRB_IDL_17_12_TerB67.1 CRB_IDL_17_12_TerB68.1 CRB_IDL_17_12_TerB69.1 CRB_IDL_17_12_TerB70.1 CRB_IDL_17_12_TerB71.1 CRB_IDL_17_12_TerB72.1 CRB_IDL_17_12_TerB73.1 CRB_IDL_17_12_TerB74.1 CRB_IDL_17_12_TerB75.1 CRB_IDL_17_12_TerB76.1 CRB_IDL_17_12_TerB77.1 CRB_IDL_17_12_TerB78.1 CRB_IDL_17_12_TerB79.1 CRB_IDL_17_12_TerB80.1 CRB_IDL_17_12_TerB81.1 CRB_IDL_17_12_TerB82.1 CRB_IDL_17_12_TerB83.1 CRB_IDL_17_12_TerB84.1 CRB_IDL_17_12_TerB85.1 CRB_IDL_17_12_TerB86.1 CRB_IDL_17_12_TerB87.1 CRB_IDL_17_12_TerB88.1 CRB_IDL_17_12_TerB89.1 GND.1 GND.2 GND.3 GND.4 GND.5 GND.6 Jbot1.B2 Jbot1.B12 Jbot1.B22 Jbot1.B31 Jbot2.B2 Jbot2.B12 Jbot2.B22 Jbot2.B31 Jbot3.B2 Jbot3.B12 Jbot3.B22 Jbot3.B31 Jbot4.B2 Jbot4.B12 Jbot4.B22 Jbot4.B31 JMid1.1 JMid1.2 JMid1.3 JMid1.4 JMid1.5 JMid1.6 JMid1.7 JMid1.8 JMid1.9 JMid1.10 JMid1.11 JMid1.12 JMid1.13 JMid1.14 JMid1.15 JMid1.16 JMid1.17 JMid1.18 JMid1.19 JMid1.24 JMid1.25 JMid1.26 JMid1.29 JMid1.31 JMid1.36 JMid1.37 JMid1.38 JMid1.43 JMid1.44 JMid1.45 JMid1.48 JMid1.50 JMid1.55 JMid1.56 JMid1.57 JMid1.61 JMid1.62 JMid1.63 JMid1.64 JMid1.67 JMid1.69 JMid1.70 JMid1.71 JMid1.72 JMid1.73 JMid1.74 JMid1.75 JMid1.76 JMid1.80 JMid1.81 JMid1.82 JMid1.86 JMid1.88 JMid1.93 JMid1.94 JMid1.95 JMid1.99 JMid1.100 JMid1.101 JMid1.105 JMid1.107 JMid1.112 JMid1.113 JMid1.114 JMid1.115 JMid1.116 JMid1.117 JMid1.118 JMid1.119 JMid1.120 JMid1.121 JMid1.122 JMid1.123 JMid1.124 JMid1.125 JMid1.126 JMid1.127 JMid2.1 JMid2.2 JMid2.3 JMid2.4 JMid2.5 JMid2.6 JMid2.7 JMid2.8 JMid2.9 JMid2.10 JMid2.11 JMid2.12 JMid2.13 JMid2.14 JMid2.15 JMid2.16 JMid2.17 JMid2.18 JMid2.19 JMid2.24 JMid2.25 JMid2.26 JMid2.29 JMid2.31 JMid2.36 JMid2.37 JMid2.38 JMid2.43 JMid2.44 JMid2.45 JMid2.48 JMid2.50 JMid2.55 JMid2.56 JMid2.57 JMid2.61 JMid2.62 JMid2.63 JMid2.64 JMid2.67 JMid2.69 JMid2.70 JMid2.71 JMid2.72 JMid2.73 JMid2.74 JMid2.75 JMid2.76 JMid2.80 JMid2.81 JMid2.82 JMid2.86 JMid2.88 JMid2.93 JMid2.94 JMid2.95 JMid2.99 JMid2.100 JMid2.101 JMid2.105 JMid2.107 JMid2.112 JMid2.113 JMid2.114 JMid2.115 JMid2.116 JMid2.117 JMid2.118 JMid2.119 JMid2.120 JMid2.121 JMid2.122 JMid2.123 JMid2.124 JMid2.125 JMid2.126 JMid2.127 JMid3.1 JMid3.2 JMid3.3 JMid3.4 JMid3.5 JMid3.6 JMid3.7 JMid3.8 JMid3.9 JMid3.10 JMid3.11 JMid3.12 JMid3.13 JMid3.14 JMid3.15 JMid3.16 JMid3.17 JMid3.18 JMid3.19 JMid3.24 JMid3.25 JMid3.26 JMid3.29 JMid3.31 JMid3.36 JMid3.37 JMid3.38 JMid3.43 JMid3.44 JMid3.45 JMid3.48 JMid3.50 JMid3.55 JMid3.56 JMid3.57 JMid3.61 JMid3.62 JMid3.63 JMid3.64 JMid3.67 JMid3.69 JMid3.70 JMid3.71 JMid3.72 JMid3.73 JMid3.74 JMid3.75 JMid3.76 JMid3.80 JMid3.81 JMid3.82 JMid3.86 JMid3.88 JMid3.93 JMid3.94 JMid3.95 JMid3.99 JMid3.100 JMid3.101 JMid3.105 JMid3.107 JMid3.112 JMid3.113 JMid3.114 JMid3.115 JMid3.116 JMid3.117 JMid3.118 JMid3.119 JMid3.120 JMid3.121 JMid3.122 JMid3.123 JMid3.124 JMid3.125 JMid3.126 JMid3.127 JMid4.1 JMid4.2 JMid4.3 JMid4.4 JMid4.5 JMid4.6 JMid4.7 JMid4.8 JMid4.9 JMid4.10 JMid4.11 JMid4.12 JMid4.13 JMid4.14 JMid4.15 JMid4.16 JMid4.17 JMid4.18 JMid4.19 JMid4.24 JMid4.25 JMid4.26 JMid4.29 JMid4.31 JMid4.36 JMid4.37 JMid4.38 JMid4.43 JMid4.44 JMid4.45 JMid4.48 JMid4.50 JMid4.55 JMid4.56 JMid4.57 JMid4.61 JMid4.62 JMid4.63 JMid4.64 JMid4.67 JMid4.69 JMid4.70 JMid4.71 JMid4.72 JMid4.73 JMid4.74 JMid4.75 JMid4.76 JMid4.80 JMid4.81 JMid4.82 JMid4.86 JMid4.88 JMid4.93 JMid4.94 JMid4.95 JMid4.99 JMid4.100 JMid4.101 JMid4.105 JMid4.107 JMid4.112 JMid4.113 JMid4.114 JMid4.115 JMid4.116 JMid4.117 JMid4.118 JMid4.119 JMid4.120 JMid4.121 JMid4.122 JMid4.123 JMid4.124 JMid4.125 JMid4.126 JMid4.127 Jtop1.A9 Jtop1.A11 Jtop1.A15 Jtop1.A17 Jtop1.A19 Jtop1.B20 Jtop1.B23 Jtop1.C9 Jtop2.A9 Jtop2.A11 Jtop2.A15 Jtop2.A17 Jtop2.A19 Jtop2.B20 Jtop2.B23 Jtop2.C9 Jtop3.A9 Jtop3.A11 Jtop3.A15 Jtop3.A17 Jtop3.A19 Jtop3.B20 Jtop3.B23 Jtop3.C9 Jtop4.A9 Jtop4.A11 Jtop4.A15 Jtop4.A17 Jtop4.A19 Jtop4.B20 Jtop4.B23 Jtop4.C9 R2R_IDL_17_12_TerA1.1 R2R_IDL_17_12_TerA2.1 R2R_IDL_17_12_TerA3.1 R2R_IDL_17_12_TerA4.1 R2R_IDL_17_12_TerA5.1 R2R_IDL_17_12_TerA6.1 R2R_IDL_17_12_TerA7.1 R2R_IDL_17_12_TerA8.1 R2R_IDL_17_12_TerA9.1 R2R_IDL_17_12_TerA10.1 R2R_IDL_17_12_TerA11.1 R2R_IDL_17_12_TerA12.1 R2R_IDL_17_12_TerA13.1 R2R_IDL_17_12_TerA14.1 R2R_IDL_17_12_TerA15.1 R2R_IDL_17_12_TerA16.1 R2R_IDL_17_12_TerA17.1 R2R_IDL_17_12_TerA18.1 R2R_IDL_17_12_TerA19.1 R2R_IDL_17_12_TerA20.1 R2R_IDL_17_12_TerA21.1 R2R_IDL_17_12_TerA22.1 R2R_IDL_17_12_TerA23.1 R2R_IDL_17_12_TerA24.1 R2R_IDL_17_12_TerA25.1 R2R_IDL_17_12_TerA26.1 R2R_IDL_17_12_TerA27.1 R2R_IDL_17_12_TerA28.1 R2R_IDL_17_12_TerA29.1 R2R_IDL_17_12_TerA30.1 R2R_IDL_17_12_TerA31.1 R2R_IDL_17_12_TerA32.1 R2R_IDL_17_12_TerA33.1 R2R_IDL_17_12_TerA34.1 R2R_IDL_17_12_TerA35.1 R2R_IDL_17_12_TerA36.1 R2R_IDL_17_12_TerA37.1 R2R_IDL_17_12_TerA38.1 R2R_IDL_17_12_TerA39.1 R2R_IDL_17_12_TerA40.1 R2R_IDL_17_12_TerA41.1 R2R_IDL_17_12_TerA42.1 R2R_IDL_17_12_TerA43.1 R2R_IDL_17_12_TerA44.1 R2R_IDL_17_12_TerA45.1 R2R_IDL_17_12_TerA46.1 R2R_IDL_17_12_TerA47.1 R2R_IDL_17_12_TerA48.1 R2R_IDL_17_12_TerA49.1 R2R_IDL_17_12_TerA50.1 R2R_IDL_17_12_TerA51.1 R2R_IDL_17_12_TerA52.1 R2R_IDL_17_12_TerA53.1 R2R_IDL_17_12_TerA54.1 R2R_IDL_17_12_TerA55.1 R2R_IDL_17_12_TerA56.1 R2R_IDL_17_12_TerA57.1 R2R_IDL_17_12_TerA58.1 R2R_IDL_17_12_TerA59.1 R2R_IDL_17_12_TerA60.1 R2R_IDL_17_12_TerA61.1 R2R_IDL_17_12_TerA62.1 R2R_IDL_17_12_TerA63.1 R2R_IDL_17_12_TerA64.1 R2R_IDL_17_12_TerA65.1 R2R_IDL_17_12_TerA66.1 R2R_IDL_17_12_TerA67.1 R2R_IDL_17_12_TerA68.1 R2R_IDL_17_12_TerA69.1 R2R_IDL_17_12_TerA70.1 R2R_IDL_17_12_TerA71.1 R2R_IDL_17_12_TerA72.1 R2RB_IDL_17_12_TerB1.1 R2RB_IDL_17_12_TerB2.1 R2RB_IDL_17_12_TerB3.1 R2RB_IDL_17_12_TerB4.1 R2RB_IDL_17_12_TerB5.1 R2RB_IDL_17_12_TerB6.1 R2RB_IDL_17_12_TerB7.1 R2RB_IDL_17_12_TerB8.1 R2RB_IDL_17_12_TerB9.1 R2RB_IDL_17_12_TerB10.1 R2RB_IDL_17_12_TerB11.1 R2RB_IDL_17_12_TerB12.1 R2RB_IDL_17_12_TerB13.1 R2RB_IDL_17_12_TerB14.1 R2RB_IDL_17_12_TerB15.1 R2RB_IDL_17_12_TerB16.1 R2RB_IDL_17_12_TerB17.1 R2RB_IDL_17_12_TerB18.1 R2RB_IDL_17_12_TerB19.1 R2RB_IDL_17_12_TerB20.1 R2RB_IDL_17_12_TerB21.1 R2RB_IDL_17_12_TerB22.1 R2RB_IDL_17_12_TerB23.1 R2RB_IDL_17_12_TerB24.1 R2RB_IDL_17_12_TerB25.1 R2RB_IDL_17_12_TerB26.1 R2RB_IDL_17_12_TerB27.1 R2RB_IDL_17_12_TerB28.1 R2RB_IDL_17_12_TerB29.1 R2RB_IDL_17_12_TerB30.1 R2RB_IDL_17_12_TerB31.1 R2RB_IDL_17_12_TerB32.1 R2RB_IDL_17_12_TerB33.1 R2RB_IDL_17_12_TerB34.1 R2RB_IDL_17_12_TerB35.1 R2RB_IDL_17_12_TerB36.1 R2RB_IDL_17_12_TerB37.1 R2RB_IDL_17_12_TerB38.1 R2RB_IDL_17_12_TerB39.1 R2RB_IDL_17_12_TerB40.1 R2RB_IDL_17_12_TerB41.1 R2RB_IDL_17_12_TerB42.1 R2RB_IDL_17_12_TerB43.1 R2RB_IDL_17_12_TerB44.1 R2RB_IDL_17_12_TerB45.1 R2RB_IDL_17_12_TerB46.1 R2RB_IDL_17_12_TerB47.1 R2RB_IDL_17_12_TerB48.1 R2RB_IDL_17_12_TerB49.1 R2RB_IDL_17_12_TerB50.1 R2RB_IDL_17_12_TerB51.1 R2RB_IDL_17_12_TerB52.1 R2RB_IDL_17_12_TerB53.1 R2RB_IDL_17_12_TerB54.1 R2RB_IDL_17_12_TerB55.1 R2RB_IDL_17_12_TerB56.1 R2RB_IDL_17_12_TerB57.1 R2RB_IDL_17_12_TerB58.1 R2RB_IDL_17_12_TerB59.1 R2RB_IDL_17_12_TerB60.1 R2RB_IDL_17_12_TerB61.1 R2RB_IDL_17_12_TerB62.1 R2RB_IDL_17_12_TerB63.1 R2RB_IDL_17_12_TerB64.1 R2RB_IDL_17_12_TerB65.1 R2RB_IDL_17_12_TerB66.1 R2RB_IDL_17_12_TerB67.1 R2RB_IDL_17_12_TerB68.1 R2RB_IDL_17_12_TerB69.1 R2RB_IDL_17_12_TerB70.1 R2RB_IDL_17_12_TerB71.1 R2RB_IDL_17_12_TerB72.1 R2RB_IDL_17_12_TerB73.1 R2RB_IDL_17_12_TerB74.1 R2RB_IDL_17_12_TerB75.1 R2RB_IDL_17_12_TerB76.1 R2RB_IDL_17_12_TerB77.1 R2RB_IDL_17_12_TerB78.1 R2RB_IDL_17_12_TerB79.1 R2RB_IDL_17_12_TerB80.1 R2RB_IDL_17_12_TerB81.1 R2RB_IDL_17_12_TerB82.1 R2RB_IDL_17_12_TerB83.1 R2RB_IDL_17_12_TerB84.1 R2RB_IDL_17_12_TerB85.1 R2RB_IDL_17_12_TerB86.1 R2RB_IDL_17_12_TerB87.1 R2RB_IDL_17_12_TerB88.1 R2RB_IDL_17_12_TerB89.1 | length 17970.2
  Top Signal w8: Jtop1.A11@228.79,2082.06 Jtop1.A11@229.21,2082.48 ; Jtop3.C9@1628.3,1882.48 Jtop3.C9@1628.72,1882.06 ; Jtop3.A19@1817.47,2880.07 Jtop3.A19@1826.73,2880.07 ; Jtop3.A19@1828.72,2882.06 Jtop3.A19@1826.73,2880.07 ; Jtop3.A19@1857.75,2880.07 1829.28,2880.07 Jtop3.A19@1826.73,2880.07 ; R2R_IDL_17_12_TerA14.1@3338.89,2187.36 3346.67,2195.13 CR_IDL_17_12_TerA14.1@3386.98,2195.13 3389.8,2197.95 v1(3438.25,2197.95) ; R2R_IDL_17_12_TerA13.1@3338.89,2292.36 3346.67,2300.13 CR_IDL_17_12_TerA13.1@3386.98,2300.13 3456.61,2300.13 v1(3466.47,2290.27) ; R2R_IDL_17_12_TerA12.1@3338.89,2397.36 3346.67,2405.13 CR_IDL_17_12_TerA12.1@3386.98,2405.13 3433.35,2405.13 v1(3436.1,2407.89) ; R2R_IDL_17_12_TerA11.1@3339.26,2580.57 3347.03,2588.34 CR_IDL_17_12_TerA11.1@3387.34,2588.34 3413.81,2588.34 v1(3439.82,2614.35) ; R2R_IDL_17_12_TerA10.1@3339.26,2775.57 3347.03,2783.34 CR_IDL_17_12_TerA10.1@3387.34,2783.34 3408.02,2783.34 3428.68,2804 v1(3440.86,2804) ; R2R_IDL_17_12_TerA9.1@3339.26,2975.57 3347.03,2983.34 CR_IDL_17_12_TerA9.1@3387.34,2983.34 3416.02,2983.34 3420.68,2988 v1(3440.86,2988) ; R2R_IDL_17_12_TerA8.1@3339.26,3240.57 3347.03,3248.34 CR_IDL_17_12_TerA8.1@3387.34,3248.34 3410.52,3248.34 3426.18,3264 v1(3440.86,3264) ; R2R_IDL_17_12_TerA7.1@3339.26,3345.57 3347.03,3353.34 CR_IDL_17_12_TerA7.1@3387.34,3353.34 3417.02,3353.34 3419.68,3356 v1(3440.86,3356) ; R2R_IDL_17_12_TerA6.1@3339.26,3450.57 3379.57,3450.57 CR_IDL_17_12_TerA6.1@3387.34,3458.34 3493.78,3458.34 v1(3513.87,3478.43) ; R2R_IDL_17_12_TerA5.1@3339.26,3555.57 3347.03,3563.34 CR_IDL_17_12_TerA5.1@3387.34,3563.34 3434.21,3563.34 v1(3440.86,3570) ; R2R_IDL_17_12_TerA4.1@3339.26,3660.57 3379.57,3660.57 CR_IDL_17_12_TerA4.1@3387.34,3668.34 3413.52,3668.34 3423.18,3678 v1(3424.86,3678) ; R2R_IDL_17_12_TerA3.1@3339.26,3765.57 3379.57,3765.57 CR_IDL_17_12_TerA3.1@3387.34,3773.34 3424.75,3773.34 v1(3432.8,3781.4) ; R2R_IDL_17_12_TerA2.1@3339.26,3870.57 3347.03,3878.34 CR_IDL_17_12_TerA2.1@3387.34,3878.34 3414.43,3905.43 v1(3463.8,3905.43) ; R2R_IDL_17_12_TerA1.1@3344.26,3981.81 3352.03,3989.58 CR_IDL_17_12_TerA1.1@3392.34,3989.58 3418.14,3989.58 3428.56,4000 v1(3445.86,4000) ; R2R_IDL_17_12_TerA15.1@3352.67,1975.19 CR_IDL_17_12_TerA15.1@3392.98,1975.19 3423.58,1975.19 3424.39,1976 v1(3446.5,1976) ; R2RB_IDL_17_12_TerB1.1@3457.61,-1061.69 3502.89,-1061.69 CRB_IDL_17_12_TerB1.1@3505.91,-1058.68 3550.59,-1014 v1(3559.43,-1014) ; R2RB_IDL_17_12_TerB30.1@3458.3,-4000.17 3461.31,-3997.15 CRB_IDL_17_12_TerB30.1@3506.6,-3997.15 3509.55,-3994.21 v1(3559.31,-3994.21) ; R2RB_IDL_17_12_TerB29.1@3458.3,-3900.17 3461.31,-3897.15 CRB_IDL_17_12_TerB29.1@3506.6,-3897.15 3540.08,-3863.68 v1(3585.44,-3863.68) ; R2RB_IDL_17_12_TerB28.1@3458.3,-3795.17 3461.31,-3792.15 CRB_IDL_17_12_TerB28.1@3506.6,-3792.15 3557.97,-3792.15 v1(3560.12,-3790) ; R2RB_IDL_17_12_TerB27.1@3458.3,-3695.17 3461.31,-3692.15 CRB_IDL_17_12_TerB27.1@3506.6,-3692.15 3566.01,-3692.15 v1(3569.31,-3688.85) ; R2RB_IDL_17_12_TerB26.1@3458.3,-3595.17 3461.31,-3592.15 CRB_IDL_17_12_TerB26.1@3506.6,-3592.15 3557.97,-3592.15 v1(3560.12,-3590) ; R2RB_IDL_17_12_TerB25.1@3458.3,-3495.17 3461.31,-3492.15 CRB_IDL_17_12_TerB25.1@3506.6,-3492.15 3531.92,-3492.15 v1(3560.76,-3463.32) ; R2RB_IDL_17_12_TerB24.1@3458.3,-3395.17 3461.31,-3392.15 CRB_IDL_17_12_TerB24.1@3506.6,-3392.15 3514.35,-3384.4 v1(3559.62,-3384.4) ; R2RB_IDL_17_12_TerB23.1@3458.3,-3290.17 3461.31,-3287.15 CRB_IDL_17_12_TerB23.1@3506.6,-3287.15 3525.75,-3268 v1(3560.12,-3268) ; R2RB_IDL_17_12_TerB22.1@3458.3,-3190.17 3461.31,-3187.15 CRB_IDL_17_12_TerB22.1@3506.6,-3187.15 3521.67,-3172.08 3540.2,-3172.08 v1(3544.12,-3176) ; R2RB_IDL_17_12_TerB21.1@3458.3,-3092.17 3461.31,-3089.15 CRB_IDL_17_12_TerB21.1@3506.6,-3089.15 3512.92,-3082.83 v1(3548.27,-3082.83) ; R2RB_IDL_17_12_TerB20.1@3458.3,-2992.17 3503.59,-2992.17 CRB_IDL_17_12_TerB20.1@3506.6,-2989.15 3546.79,-2989.15 v1(3553.18,-2995.54) ; R2RB_IDL_17_12_TerB19.1@3458.3,-2887.17 3506.6,-2887.17 3551.61,-2887.17 3554.63,-2884.15 v1(3556.39,-2885.92) ; R2RB_IDL_17_12_TerB18.1@3458.3,-2787.17 3461.31,-2784.15 CRB_IDL_17_12_TerB18.1@3506.6,-2784.15 3512.75,-2778 v1(3560.12,-2778) ; R2RB_IDL_17_12_TerB17.1@3458.3,-2687.17 3461.31,-2684.15 CRB_IDL_17_12_TerB17.1@3506.6,-2684.15 3535.8,-2654.95 v1(3583.75,-2654.95) ; R2RB_IDL_17_12_TerB16.1@3458.3,-2587.17 3461.31,-2584.15 CRB_IDL_17_12_TerB16.1@3506.6,-2584.15 3534.53,-2584.15 3540.68,-2578 v1(3560.12,-2578) ; R2RB_IDL_17_12_TerB15.1@3458.3,-2482.17 3481,-2482.17 3484.02,-2479.15 CRB_IDL_17_12_TerB15.1@3506.6,-2479.15 3544,-2479.15 3560.12,-2463.03 v1(3560.12,-2440) ; R2RB_IDL_17_12_TerB14.1@3458.3,-2382.17 3461.31,-2379.15 CRB_IDL_17_12_TerB14.1@3506.6,-2379.15 3514.16,-2386.71 v1(3545.43,-2386.71) ; R2RB_IDL_17_12_TerB13.1@3458.3,-2282.17 3461.31,-2279.15 CRB_IDL_17_12_TerB13.1@3506.6,-2279.15 3525.4,-2279.15 3544.12,-2260.43 v1(3544.12,-2256) ; R2RB_IDL_17_12_TerB12.1@3458.3,-2182.17 3461.31,-2179.15 CRB_IDL_17_12_TerB12.1@3506.6,-2179.15 3533.23,-2152.53 v1(3555.98,-2152.53) ; R2RB_IDL_17_12_TerB11.1@3458.3,-2082.17 3461.31,-2079.15 CRB_IDL_17_12_TerB11.1@3506.6,-2079.15 3536.97,-2079.15 v1(3572.88,-2043.24) ; R2RB_IDL_17_12_TerB10.1@3458.3,-1977.17 3461.31,-1974.15 CRB_IDL_17_12_TerB10.1@3506.6,-1974.15 3544,-1974.15 3560.12,-1958.03 v1(3560.12,-1934) ; R2RB_IDL_17_12_TerB9.1@3458.3,-1877.17 3461.31,-1874.15 CRB_IDL_17_12_TerB9.1@3506.6,-1874.15 3562.02,-1874.15 v1(3567.05,-1879.19) ; R2RB_IDL_17_12_TerB8.1@3458.3,-1777.17 3481,-1777.17 3484.02,-1774.15 CRB_IDL_17_12_TerB8.1@3506.6,-1774.15 3525.53,-1774.15 3549.68,-1750 v1(3560.12,-1750) ; R2RB_IDL_17_12_TerB7.1@3458.3,-1677.17 3461.31,-1674.15 CRB_IDL_17_12_TerB7.1@3506.6,-1674.15 3538.75,-1642 v1(3560.12,-1642) ; R2RB_IDL_17_12_TerB6.1@3458.3,-1574.17 3461.31,-1571.15 CRB_IDL_17_12_TerB6.1@3506.6,-1571.15 3511.75,-1566 v1(3560.12,-1566) ; R2RB_IDL_17_12_TerB5.1@3458.3,-1474.17 3461.31,-1471.15 CRB_IDL_17_12_TerB5.1@3506.6,-1471.15 3546.94,-1471.15 3587.39,-1430.7 v1(3608.85,-1430.7) ; R2RB_IDL_17_12_TerB4.1@3458.3,-1374.17 3461.31,-1371.15 CRB_IDL_17_12_TerB4.1@3506.6,-1371.15 v1(3546.62,-1371.15) ; R2RB_IDL_17_12_TerB3.1@3458.3,-1274.17 3461.31,-1271.15 CRB_IDL_17_12_TerB3.1@3506.6,-1271.15 3532.97,-1271.15 v1(3560.12,-1244) ; R2RB_IDL_17_12_TerB2.1@3458.3,-1169.17 3503.59,-1169.17 CRB_IDL_17_12_TerB2.1@3506.6,-1166.15 3529.97,-1166.15 v1(3560.12,-1136) ; R2RB_IDL_17_12_TerB31.1@3463.14,-4097.15 CRB_IDL_17_12_TerB31.1@3506.6,-4097.15 3529.08,-4119.63 v1(3558.85,-4119.63) ; R2RB_IDL_17_12_TerB32.1@3465.91,-4206.21 CRB_IDL_17_12_TerB32.1@3506.2,-4206.21 3541.7,-4241.71 v1(3541.7,-4252.42) ; R2R_IDL_17_12_TerA22.1@3497.17,1170.05 3537.48,1170.05 CR_IDL_17_12_TerA22.1@3545.25,1177.82 3566.44,1199.01 v1(3598.77,1199.01) ; R2R_IDL_17_12_TerA21.1@3497.17,1275.05 3537.48,1275.05 CR_IDL_17_12_TerA21.1@3545.25,1282.82 3553.44,1291.01 v1(3598.77,1291.01) ; R2R_IDL_17_12_TerA20.1@3497.17,1380.05 3504.94,1387.82 CR_IDL_17_12_TerA20.1@3545.25,1387.82 3582.65,1387.82 3598.77,1403.94 v1(3598.77,1429.01) ; R2R_IDL_17_12_TerA19.1@3497.17,1485.05 3504.94,1492.82 CR_IDL_17_12_TerA19.1@3545.25,1492.82 3586.59,1492.82 v1(3598.77,1505.01) ; R2R_IDL_17_12_TerA18.1@3497.17,1590.05 3537.48,1590.05 CR_IDL_17_12_TerA18.1@3545.25,1597.82 3583.59,1597.82 v1(3598.77,1613.01) ; R2R_IDL_17_12_TerA17.1@3497.17,1695.05 3537.48,1695.05 CR_IDL_17_12_TerA17.1@3545.25,1702.82 3547.44,1705.01 v1(3598.77,1705.01) ; R2R_IDL_17_12_TerA16.1@3497.17,1798.05 3504.94,1805.82 CR_IDL_17_12_TerA16.1@3545.25,1805.82 3582.65,1805.82 3598.77,1821.94 v1(3598.77,1843.01) ; v1(3498.16,1017.74) 3498.16,1064.06 R2R_IDL_17_12_TerA23.1@3497.17,1065.05 3537.48,1065.05 CR_IDL_17_12_TerA23.1@3545.25,1072.82 ; R2RB_IDL_17_12_TerB57.1@3849,-4081.98 3850.9,-4080.08 3852.62,-4078.36 CRB_IDL_17_12_TerB57.1@3900.51,-4078.36 3902.59,-4076.28 v1(3949.29,-4076.28) ; R2RB_IDL_17_12_TerB47.1@3851.47,-2889.39 3857.25,-2889.39 CRB_IDL_17_12_TerB47.1@3905.55,-2889.39 v1@3959.07,-2889.39 ; R2RB_IDL_17_12_TerB55.1@3852.25,-3870.4 3897.54,-3870.4 CRB_IDL_17_12_TerB55.1@3900.55,-3867.39 3923.27,-3890.1 v1(3959.21,-3890.1) ; R2RB_IDL_17_12_TerB53.1@3852.25,-3665.4 3855.26,-3662.39 CRB_IDL_17_12_TerB53.1@3900.55,-3662.39 3937.95,-3662.39 v1(3947.65,-3652.6) v1(3947.65,-3652.6) v1(3947.65,-3652.6) ; R2RB_IDL_17_12_TerB52.1@3852.25,-3565.4 3855.26,-3562.39 CRB_IDL_17_12_TerB52.1@3900.55,-3562.39 3940.92,-3562.39 v1(3954.07,-3549.23) ; R2RB_IDL_17_12_TerB51.1@3852.25,-3467.4 3855.26,-3464.39 CRB_IDL_17_12_TerB51.1@3900.55,-3464.39 3923.7,-3441.23 v1(3954.07,-3441.23) ; R2RB_IDL_17_12_TerB50.1@3852.25,-3367.4 3855.26,-3364.39 CRB_IDL_17_12_TerB50.1@3900.55,-3364.39 3953.22,-3364.39 v1(3954.07,-3365.23) ; R2RB_IDL_17_12_TerB48.1@3852.25,-3162.4 3897.54,-3162.4 CRB_IDL_17_12_TerB48.1@3900.55,-3159.39 3937.95,-3159.39 3954.07,-3143.27 v1(3954.07,-3119.23) ; R2RB_IDL_17_12_TerB56.1@3854.52,-3967.39 CRB_IDL_17_12_TerB56.1@3900.55,-3967.39 3941.41,-3967.39 v1(3954.7,-3980.68) ; R2RB_IDL_17_12_TerB41.1@3855.13,-2254.39 3857.25,-2254.39 CRB_IDL_17_12_TerB41.1@3905.55,-2254.39 3949.92,-2254.39 v1(3959.07,-2245.23) ; R2RB_IDL_17_12_TerB54.1@3855.52,-3767.39 CRB_IDL_17_12_TerB54.1@3900.55,-3767.39 3949.92,-3767.39 v1(3954.07,-3763.23) ; R2RB_IDL_17_12_TerB49.1@3857.2,-3264.39 CRB_IDL_17_12_TerB49.1@3900.55,-3264.39 3945.22,-3264.39 v1(3954.07,-3273.23) ; R2RB_IDL_17_12_TerB43.1@3857.25,-2467.4 3879.95,-2467.4 3882.97,-2464.39 CRB_IDL_17_12_TerB43.1@3905.55,-2464.39 3955.92,-2464.39 v1(3959.07,-2461.23) ; R2RB_IDL_17_12_TerB42.1@3857.25,-2362.4 3902.54,-2362.4 CRB_IDL_17_12_TerB42.1@3905.55,-2359.39 3925.48,-2359.39 3947.63,-2337.23 v1(3959.07,-2337.23) ; R2RB_IDL_17_12_TerB40.1@3857.25,-2147.4 3860.26,-2144.39 CRB_IDL_17_12_TerB40.1@3905.55,-2144.39 3951.51,-2144.39 v1(3955.76,-2140.13) ; R2RB_IDL_17_12_TerB46.1@3857.78,-2784.39 CRB_IDL_17_12_TerB46.1@3905.55,-2784.39 3957.92,-2784.39 v1(3959.07,-2783.23) ; R2RB_IDL_17_12_TerB44.1@3858.34,-2571.76 3905.55,-2571.76 v1(3976.53,-2571.76) ; R2RB_IDL_17_12_TerB45.1@3858.62,-2679.39 CRB_IDL_17_12_TerB45.1@3905.55,-2679.39 3931.22,-2679.39 v1(3959.07,-2707.23) ; R2RB_IDL_17_12_TerB38.1@3862.25,-1865.75 3865.26,-1862.73 CRB_IDL_17_12_TerB38.1@3910.55,-1862.73 3985.91,-1862.73 v1(3990.07,-1858.57) ; R2RB_IDL_17_12_TerB36.1@3862.25,-1662.75 3865.26,-1659.73 CRB_IDL_17_12_TerB36.1@3910.55,-1659.73 3960.57,-1659.73 v1(3964.07,-1663.23) ; R2RB_IDL_17_12_TerB35.1@3862.25,-1562.75 3865.26,-1559.73 CRB_IDL_17_12_TerB35.1@3910.55,-1559.73 3959.57,-1559.73 v1(3964.07,-1555.23) ; R2RB_IDL_17_12_TerB34.1@3862.25,-1462.75 3865.26,-1459.73 CRB_IDL_17_12_TerB34.1@3910.55,-1459.73 3979.92,-1459.73 ; R2RB_IDL_17_12_TerB33.1@3862.25,-1362.75 3907.54,-1362.75 CRB_IDL_17_12_TerB33.1@3910.55,-1359.73 3947.95,-1359.73 3957.33,-1350.36 3958.34,-1349.34 v1(3958.34,-1351.37) ; R2RB_IDL_17_12_TerB37.1@3865.26,-1762.73 R2RB_IDL_17_12_TerB37.1@3862.25,-1765.75 3907.54,-1765.75 CRB_IDL_17_12_TerB37.1@3910.55,-1762.73 3955.31,-1762.73 3956.57,-1762.73 3955.31,-1763.99 v1(3955.31,-1765.31) ; R2RB_IDL_17_12_TerB39.1@3866.86,-1962.73 CRB_IDL_17_12_TerB39.1@3910.55,-1962.73 3911.66,-1961.63 v1(3967.03,-1961.63) ; CRB_IDL_17_12_TerB44.1@3905.55,-2569.39 CRB_IDL_17_12_TerB44.1@3907.7,-2567.23 ; R2R_IDL_17_12_TerA39.1@3921.82,2341.16 3962.13,2341.16 CR_IDL_17_12_TerA39.1@3969.9,2348.93 3971.19,2350.22 v1(4024.81,2350.22) ; R2R_IDL_17_12_TerA38.1@3921.82,2446.16 3929.59,2453.93 CR_IDL_17_12_TerA38.1@3969.9,2453.93 3971.05,2455.08 v1(4023.93,2455.08) ; R2R_IDL_17_12_TerA37.1@3921.82,2551.16 3962.13,2551.16 CR_IDL_17_12_TerA37.1@3969.9,2558.93 4009.46,2558.93 v1(4020.49,2547.9) ; R2R_IDL_17_12_TerA36.1@3921.82,2656.16 3962.13,2656.16 CR_IDL_17_12_TerA36.1@3969.9,2663.93 3988.46,2645.37 v1(4019.38,2645.37) ; R2R_IDL_17_12_TerA35.1@3921.82,2761.16 3962.13,2761.16 CR_IDL_17_12_TerA35.1@3969.9,2768.93 3988.57,2768.93 4013.23,2793.58 v1(4023.42,2793.58) ; R2R_IDL_17_12_TerA34.1@3921.82,2866.16 3962.13,2866.16 CR_IDL_17_12_TerA34.1@3969.9,2873.93 3995.07,2873.93 4006.73,2885.58 v1(4023.42,2885.58) ; R2R_IDL_17_12_TerA33.1@3921.82,2971.16 3962.13,2971.16 CR_IDL_17_12_TerA33.1@3969.9,2978.93 4007.3,2978.93 4023.42,2995.05 v1(4023.42,3023.58) ; R2R_IDL_17_12_TerA31.1@3921.82,3354.16 3962.13,3354.16 CR_IDL_17_12_TerA31.1@3969.9,3361.93 3980.56,3372.59 v1(4022.89,3372.59) ; R2R_IDL_17_12_TerA30.1@3921.82,3459.16 3962.13,3459.16 CR_IDL_17_12_TerA30.1@3969.9,3466.93 3992.57,3466.93 4009.23,3483.58 v1(4023.42,3483.58) ; R2R_IDL_17_12_TerA29.1@3921.82,3564.16 3962.13,3564.16 CR_IDL_17_12_TerA29.1@3969.9,3571.93 3985.43,3556.39 4047.24,3556.39 v1(4047.42,3556.21) ; R2R_IDL_17_12_TerA28.1@3921.82,3669.16 3929.59,3676.93 CR_IDL_17_12_TerA28.1@3969.9,3676.93 4007.3,3676.93 4013.26,3670.96 v1(4013.26,3657.1) ; R2R_IDL_17_12_TerA27.1@3921.82,3774.16 3962.13,3774.16 CR_IDL_17_12_TerA27.1@3969.9,3781.93 3970.86,3782.89 v1(4025.25,3782.89) ; R2R_IDL_17_12_TerA26.1@3921.82,3879.16 3929.59,3886.93 CR_IDL_17_12_TerA26.1@3969.9,3886.93 4012.76,3886.93 v1(4023.42,3897.58) ; R2R_IDL_17_12_TerA25.1@3921.82,3984.16 3961.09,3984.16 3968.87,3991.93 CR_IDL_17_12_TerA25.1@3969.9,3991.93 3977.48,3999.51 v1(4022.55,3999.51) ; R2R_IDL_17_12_TerA24.1@3921.82,4089.16 3962.13,4089.16 CR_IDL_17_12_TerA24.1@3969.9,4096.93 3974.48,4092.35 v1(4019.29,4092.35) ; R2R_IDL_17_12_TerA43.1@3927.64,1127.66 3967.95,1127.66 CR_IDL_17_12_TerA43.1@3975.73,1135.43 4003.17,1162.88 v1(4030.31,1162.88) ; R2R_IDL_17_12_TerA41.1@3927.72,1350.63 3968.03,1350.63 CR_IDL_17_12_TerA41.1@3975.8,1358.4 3982.94,1365.54 v1(4034.49,1365.54) ; v1(3928.2,2190.79) 3921.82,2197.18 R2R_IDL_17_12_TerA40.1@3921.82,2236.16 3929.59,2243.93 CR_IDL_17_12_TerA40.1@3969.9,2243.93 ; R2R_IDL_17_12_TerA42.1@3931.32,1258.4 CR_IDL_17_12_TerA42.1@3975.8,1258.4 4023.66,1258.4 v1(4029.32,1264.06) ; v1(3946.16,3192.64) 3946.16,3202.98 3921.82,3227.33 R2R_IDL_17_12_TerA32.1@3921.82,3246.16 3929.59,3253.93 CR_IDL_17_12_TerA32.1@3969.9,3253.93 ; 3980.17,-1459.71 3995.86,-1475.4 v1(3999.54,-1475.4) ; R2RB_IDL_17_12_TerB88.1@4401.98,-4200.11 4447.27,-4200.11 CRB_IDL_17_12_TerB88.1@4450.29,-4197.09 4487.69,-4197.09 4497.19,-4187.59 4501.53,-4183.25 v1(4501.53,-4191.94) ; R2RB_IDL_17_12_TerB87.1@4401.98,-4100.11 4405,-4097.09 CRB_IDL_17_12_TerB87.1@4450.29,-4097.09 4452.08,-4095.3 v1(4506.46,-4095.3) ; R2RB_IDL_17_12_TerB86.1@4401.98,-4000.11 4447.27,-4000.11 CRB_IDL_17_12_TerB86.1@4450.29,-3997.09 4475.92,-3971.46 v1(4503.81,-3971.46) ; R2RB_IDL_17_12_TerB85.1@4401.98,-3895.11 4405,-3892.09 CRB_IDL_17_12_TerB85.1@4450.29,-3892.09 4491.17,-3892.09 v1(4503.81,-3879.46) ; R2RB_IDL_17_12_TerB84.1@4401.98,-3795.11 4405,-3792.09 CRB_IDL_17_12_TerB84.1@4450.29,-3792.09 4502.4,-3792.09 v1(4513.2,-3781.29) ; R2RB_IDL_17_12_TerB83.1@4401.98,-3695.11 4447.27,-3695.11 CRB_IDL_17_12_TerB83.1@4450.29,-3692.09 4521.75,-3692.09 v1(4523.3,-3690.54) ; R2RB_IDL_17_12_TerB82.1@4401.98,-3595.11 4405,-3592.09 CRB_IDL_17_12_TerB82.1@4450.29,-3592.09 4487.69,-3592.09 v1(4495.75,-3584.03) ; R2RB_IDL_17_12_TerB81.1@4401.98,-3493.11 4405,-3490.09 CRB_IDL_17_12_TerB81.1@4450.29,-3490.09 4479.17,-3490.09 v1(4503.81,-3465.46) ; R2RB_IDL_17_12_TerB80.1@4401.98,-3388.11 4405,-3385.09 CRB_IDL_17_12_TerB80.1@4450.29,-3385.09 4455.39,-3379.98 v1(4513.61,-3379.98) ; R2RB_IDL_17_12_TerB79.1@4401.98,-3288.11 4405,-3285.09 CRB_IDL_17_12_TerB79.1@4450.29,-3285.09 4500.17,-3285.09 v1(4503.81,-3281.46) ; R2RB_IDL_17_12_TerB78.1@4401.98,-3188.11 4447.27,-3188.11 CRB_IDL_17_12_TerB78.1@4450.29,-3185.09 4508.68,-3185.09 v1(4509.36,-3185.77) ; R2RB_IDL_17_12_TerB77.1@4401.98,-3088.11 4405,-3085.09 CRB_IDL_17_12_TerB77.1@4450.29,-3085.09 4487.69,-3085.09 v1(4495.75,-3077.03) ; R2RB_IDL_17_12_TerB76.1@4401.98,-2983.11 4405,-2980.09 CRB_IDL_17_12_TerB76.1@4450.29,-2980.09 4483.17,-2980.09 v1(4503.81,-2959.46) ; R2RB_IDL_17_12_TerB75.1@4401.98,-2883.11 4405,-2880.09 CRB_IDL_17_12_TerB75.1@4450.29,-2880.09 4458.66,-2871.72 v1(4526.24,-2871.72) ; R2RB_IDL_17_12_TerB74.1@4401.98,-2783.11 4405,-2780.09 CRB_IDL_17_12_TerB74.1@4450.29,-2780.09 4499.17,-2780.09 v1(4503.81,-2775.46) ; R2RB_IDL_17_12_TerB73.1@4401.98,-2683.11 4405,-2680.09 CRB_IDL_17_12_TerB73.1@4450.29,-2680.09 4487.69,-2680.09 v1(4503.81,-2663.97) ; R2RB_IDL_17_12_TerB72.1@4401.98,-2578.11 4405,-2575.09 CRB_IDL_17_12_TerB72.1@4450.29,-2575.09 4479.92,-2545.46 v1(4503.81,-2545.46) ; R2RB_IDL_17_12_TerB71.1@4401.98,-2478.11 4405,-2475.09 CRB_IDL_17_12_TerB71.1@4450.29,-2475.09 4482.17,-2475.09 v1(4503.81,-2453.46) ; R2RB_IDL_17_12_TerB70.1@4401.98,-2378.11 4405,-2375.09 CRB_IDL_17_12_TerB70.1@4450.29,-2375.09 4490.17,-2375.09 v1(4503.81,-2361.46) ; R2RB_IDL_17_12_TerB69.1@4401.98,-2278.11 4405,-2275.09 CRB_IDL_17_12_TerB69.1@4450.29,-2275.09 4498.17,-2275.09 v1(4503.81,-2269.46) ; R2RB_IDL_17_12_TerB68.1@4401.98,-2178.11 4405,-2175.09 CRB_IDL_17_12_TerB68.1@4450.29,-2175.09 4497.94,-2175.09 v1(4506.16,-2166.87) ; R2RB_IDL_17_12_TerB67.1@4401.98,-2073.11 4447.27,-2073.11 CRB_IDL_17_12_TerB67.1@4450.29,-2070.09 4480.92,-2039.46 v1(4503.81,-2039.46) ; R2RB_IDL_17_12_TerB66.1@4401.98,-1971.11 4405,-1968.09 CRB_IDL_17_12_TerB66.1@4450.29,-1968.09 4483.17,-1968.09 v1(4503.81,-1947.46) ; R2RB_IDL_17_12_TerB65.1@4401.98,-1871.11 4405,-1868.09 CRB_IDL_17_12_TerB65.1@4450.29,-1868.09 4491.17,-1868.09 v1(4503.81,-1855.46) ; R2RB_IDL_17_12_TerB64.1@4401.98,-1771.11 4447.27,-1771.11 CRB_IDL_17_12_TerB64.1@4450.29,-1768.09 4478.97,-1768.09 4495.84,-1751.22 v1(4500.23,-1751.22) ; R2RB_IDL_17_12_TerB63.1@4401.98,-1666.11 4447.27,-1666.11 CRB_IDL_17_12_TerB63.1@4450.29,-1663.09 4466.4,-1646.97 v1(4503.81,-1646.97) ; R2RB_IDL_17_12_TerB62.1@4401.98,-1566.11 4405,-1563.09 CRB_IDL_17_12_TerB62.1@4450.29,-1563.09 4492.79,-1563.09 v1(4508.25,-1547.63) ; R2RB_IDL_17_12_TerB61.1@4401.98,-1466.11 4447.27,-1466.11 CRB_IDL_17_12_TerB61.1@4450.29,-1463.09 4471.92,-1441.46 v1(4503.81,-1441.46) ; R2RB_IDL_17_12_TerB60.1@4401.98,-1366.11 4405,-1363.09 CRB_IDL_17_12_TerB60.1@4450.29,-1363.09 4490.17,-1363.09 v1(4503.81,-1349.46) ; R2RB_IDL_17_12_TerB59.1@4401.98,-1261.11 4405,-1258.09 CRB_IDL_17_12_TerB59.1@4450.29,-1258.09 4503.17,-1258.09 v1(4503.81,-1257.46) ; R2RB_IDL_17_12_TerB58.1@4401.98,-1161.11 4447.27,-1161.11 CRB_IDL_17_12_TerB58.1@4450.29,-1158.09 4498.31,-1158.09 v1(4503.8,-1163.58) ; R2RB_IDL_17_12_TerB89.1@4403.38,-4317.34 4411.92,-4308.8 CRB_IDL_17_12_TerB89.1@4451.51,-4308.8 4489.69,-4308.8 v1(4505.03,-4293.46) ; R2R_IDL_17_12_TerA72.1@4505.96,1125.78 4548.51,1125.78 CR_IDL_17_12_TerA72.1@4553.87,1131.13 4556.18,1128.82 v1(4615.25,1128.82) ; R2R_IDL_17_12_TerA71.1@4507.09,1235.82 4514.86,1243.59 CR_IDL_17_12_TerA71.1@4555.17,1243.59 4579.83,1268.25 v1(4608.69,1268.25) ; R2R_IDL_17_12_TerA70.1@4507.09,1340.82 4547.4,1340.82 CR_IDL_17_12_TerA70.1@4555.17,1348.59 4580.35,1348.59 4592,1360.25 v1(4608.69,1360.25) ; R2R_IDL_17_12_TerA69.1@4507.09,1445.82 4547.4,1445.82 CR_IDL_17_12_TerA69.1@4555.17,1453.59 4592.57,1453.59 v1(4600.63,1461.65) ; R2R_IDL_17_12_TerA68.1@4507.09,1550.82 4514.86,1558.59 CR_IDL_17_12_TerA68.1@4555.17,1558.59 4559.58,1563 v1(4611.36,1563) ; R2R_IDL_17_12_TerA67.1@4507.09,1655.82 4547.4,1655.82 CR_IDL_17_12_TerA67.1@4555.17,1663.59 4576.85,1663.59 4595.5,1682.25 v1(4608.69,1682.25) ; R2R_IDL_17_12_TerA66.1@4507.09,1760.82 4547.4,1760.82 CR_IDL_17_12_TerA66.1@4555.17,1768.59 4603.04,1768.59 v1(4608.69,1774.25) ; R2R_IDL_17_12_TerA65.1@4507.09,1865.82 4514.86,1873.59 CR_IDL_17_12_TerA65.1@4555.17,1873.59 4555.72,1874.14 v1(4605.57,1874.14) ; R2R_IDL_17_12_TerA64.1@4507.09,1970.82 4514.86,1978.59 CR_IDL_17_12_TerA64.1@4555.17,1978.59 4580.83,2004.25 v1(4608.69,2004.25) ; R2R_IDL_17_12_TerA63.1@4507.09,2075.82 4514.86,2083.59 CR_IDL_17_12_TerA63.1@4555.17,2083.59 4596.04,2083.59 v1(4608.69,2096.25) ; R2R_IDL_17_12_TerA62.1@4507.09,2180.82 4514.86,2188.59 CR_IDL_17_12_TerA62.1@4555.17,2188.59 4558.43,2185.33 v1(4618.25,2185.33) ; R2R_IDL_17_12_TerA61.1@4507.09,2288.82 4547.4,2288.82 CR_IDL_17_12_TerA61.1@4555.17,2296.59 4598.91,2296.59 v1(4607.4,2305.07) ; R2R_IDL_17_12_TerA60.1@4507.09,2393.82 4514.86,2401.59 CR_IDL_17_12_TerA60.1@4555.17,2401.59 4592.04,2401.59 v1(4608.69,2418.25) ; R2R_IDL_17_12_TerA59.1@4507.09,2498.82 4514.86,2506.59 CR_IDL_17_12_TerA59.1@4555.17,2506.59 4605.04,2506.59 v1(4608.69,2510.25) ; R2R_IDL_17_12_TerA58.1@4507.09,2603.82 4514.86,2611.59 CR_IDL_17_12_TerA58.1@4555.17,2611.59 4592.57,2611.59 v1(4600.63,2619.65) ; R2R_IDL_17_12_TerA57.1@4507.09,2708.82 4514.86,2716.59 CR_IDL_17_12_TerA57.1@4555.17,2716.59 4574.35,2716.59 4598,2740.25 v1(4608.69,2740.25) ; R2R_IDL_17_12_TerA56.1@4507.09,2813.82 4547.4,2813.82 CR_IDL_17_12_TerA56.1@4555.17,2821.59 4598.04,2821.59 v1(4608.69,2832.25) ; R2R_IDL_17_12_TerA55.1@4507.09,2918.82 4514.86,2926.59 CR_IDL_17_12_TerA55.1@4555.17,2926.59 4556.64,2928.06 v1(4607.09,2928.06) ; R2R_IDL_17_12_TerA54.1@4507.09,3023.82 4547.4,3023.82 CR_IDL_17_12_TerA54.1@4555.17,3031.59 4562.22,3038.64 v1(4606.52,3038.64) ; R2R_IDL_17_12_TerA53.1@4507.09,3128.82 4547.4,3128.82 CR_IDL_17_12_TerA53.1@4555.17,3136.59 4577.35,3136.59 4595,3154.25 v1(4608.69,3154.25) ; R2R_IDL_17_12_TerA52.1@4507.09,3233.82 4547.4,3233.82 CR_IDL_17_12_TerA52.1@4555.17,3241.59 4583.85,3241.59 4588.5,3246.25 v1(4608.69,3246.25) ; R2R_IDL_17_12_TerA51.1@4507.09,3338.82 4547.4,3338.82 CR_IDL_17_12_TerA51.1@4555.17,3346.59 v1(4592.57,3346.59) ; R2R_IDL_17_12_TerA50.1@4507.09,3443.82 4547.4,3443.82 CR_IDL_17_12_TerA50.1@4555.17,3451.59 4573.85,3451.59 4598.5,3476.25 v1(4608.69,3476.25) ; R2R_IDL_17_12_TerA49.1@4507.09,3548.82 4514.86,3556.59 CR_IDL_17_12_TerA49.1@4555.17,3556.59 4580.35,3556.59 4592,3568.25 v1(4608.69,3568.25) ; R2R_IDL_17_12_TerA48.1@4507.09,3653.82 4514.86,3661.59 CR_IDL_17_12_TerA48.1@4555.17,3661.59 v1@4603.5,3661.59 ; R2R_IDL_17_12_TerA47.1@4507.09,3758.82 4547.4,3758.82 CR_IDL_17_12_TerA47.1@4555.17,3766.59 4563.69,3775.1 v1(4614.37,3775.1) ; R2R_IDL_17_12_TerA46.1@4507.09,3861.82 4547.4,3861.82 CR_IDL_17_12_TerA46.1@4555.17,3869.59 4575.85,3869.59 4596.5,3890.25 v1(4608.69,3890.25) ; R2R_IDL_17_12_TerA45.1@4507.09,3966.82 4547.4,3966.82 CR_IDL_17_12_TerA45.1@4555.17,3974.59 4601.04,3974.59 v1(4608.69,3982.25) ; R2R_IDL_17_12_TerA44.1@4507.09,4071.82 4514.86,4079.59 CR_IDL_17_12_TerA44.1@4555.17,4079.59 4592.57,4079.59 v1(4600.63,4087.65)
  Bot Signal w8: Jtop1.B23@128.79,3282.06 129.28,3282.06 Jtop1.B23@132.51,3282.06 ; Jtop3.B20@1708.21,2979.68 1729.28,2979.68 Jtop3.B20@1748.13,2979.68
  other v1: 3959.07,-2889.23 4603.5,3662.12
IACKIN_5: Jtop1.A21 Jtop2.A21 Jtop3.A21 Jtop4.A21 | length 2525.3
  Top Signal w8: Jtop1.A21@228.79,3082.06 229.28,3082.06 241.64,3082.06 287.83,3035.87 835.78,3035.87 841.3,3041.38 895.08,3041.38 900.59,3035.87 935.78,3035.87 941.3,3041.38 987.61,3041.38 1021.39,3075.15 1028.72,3082.48 1077.45,3033.76 1646.87,3033.76 1652.75,3039.63 1705.81,3039.63 1711.68,3033.76 1746.87,3033.76 1752.75,3039.63 1786.29,3039.63 Jtop3.A21@1823.97,3077.31 ; Jtop3.A21@1805.98,3077.31 Jtop3.A21@1823.97,3077.31 ; Jtop3.A21@1828.72,3082.06 1826.09,3079.43 Jtop3.A21@1823.97,3077.31 ; Jtop4.A21@2605.98,3071.78 2563.73,3029.52 1894.05,3029.52 1846.26,3077.31 1829.28,3077.31 Jtop3.A21@1823.97,3077.31
IACKOUT_5: Jtop1.A22 Jtop2.A22 Jtop3.A22 Jtop4.A22 | length 2525.9
  Top Signal w8: Jtop1.A22@228.79,3182.06 231.95,3178.91 270.85,3140 796.46,3140 800.59,3135.87 835.78,3135.87 839.92,3140 896.46,3140 900.59,3135.87 935.78,3135.87 939.92,3140 986.24,3140 Jtop2.A22@1018.19,3171.95 ; Jtop2.A22@1018.19,3178.35 Jtop2.A22@1018.19,3171.95 ; Jtop4.A22@2622.31,3177.05 2569.81,3124.54 1880.97,3124.54 Jtop3.A22@1829.28,3176.24 1790.6,3137.55 1750.67,3137.55 1746.87,3133.76 1711.68,3133.76 1707.89,3137.55 1650.67,3137.55 1646.87,3133.76 1077.45,3133.76 1028.72,3182.48 1021.39,3175.15 Jtop2.A22@1018.19,3171.95
JB1: Jbot1.A32 Jbot2.A32 Jbot3.A32 Jbot4.A32 R1RB_IDL_17_12_TerB1.1 R2RB_IDL_17_12_TerB1.2 | length 3349.7
  Top Signal w8: Jbot1.A32@228.26,-1073.77 268.54,-1073.77 310.6,-1115.83 857.77,-1115.83 ; 857.79,-1115.8 910.57,-1115.8 ; 910.59,-1115.83 945.79,-1115.83 988.27,-1073.35 Jbot2.A32@1028.19,-1073.35 1067.63,-1073.35 1110.53,-1116.25 1785.71,-1116.25 Jbot3.A32@1828.19,-1073.77 1837.73,-1073.77 1880.21,-1116.25 2591.25,-1116.25 2630.96,-1076.54 2645.8,-1061.69 R2RB_IDL_17_12_TerB1.2@3414.3,-1061.69 3414.3,-1036 3413.79,-1035.49 R1RB_IDL_17_12_TerB1.1@3413.79,-1008.84
JB2: Jbot1.A31 Jbot2.A31 Jbot3.A31 Jbot4.A31 R1RB_IDL_17_12_TerB2.1 R2RB_IDL_17_12_TerB2.2 | length 3352.3
  Top Signal w8: Jbot1.A31@228.26,-1173.77 268.54,-1173.77 310.6,-1215.83 945.79,-1215.83 988.27,-1173.35 Jbot2.A31@1028.19,-1173.35 1067.63,-1173.35 1110.53,-1216.25 1785.71,-1216.25 Jbot3.A31@1828.19,-1173.77 ; Jbot3.A31@1830.51,-1173.38 1847.8,-1173.38 1899.29,-1224.87 2401.97,-1224.87 2410.59,-1216.25 2593.18,-1216.25 2631.92,-1177.5 2640.26,-1169.17 R2RB_IDL_17_12_TerB2.2@3414.99,-1169.17 3414.99,-1143 3414.48,-1142.49 R1RB_IDL_17_12_TerB2.1@3414.48,-1116.31
JB3: Jbot1.A30 Jbot2.A30 Jbot3.A30 Jbot4.A30 R1RB_IDL_17_12_TerB3.1 R2RB_IDL_17_12_TerB3.2 | length 3345
  Top Signal w8: Jbot1.A30@228.26,-1273.77 268.54,-1273.77 310.6,-1315.83 858.56,-1315.83 858.98,-1315.4 910.17,-1315.4 910.59,-1315.83 945.79,-1315.83 988.27,-1273.35 Jbot2.A30@1028.19,-1273.35 1067.63,-1273.35 1110.53,-1316.25 1785.71,-1316.25 Jbot3.A30@1825.49,-1276.46 ; Jbot3.A30@1815.45,-1276.46 Jbot3.A30@1825.49,-1276.46 ; Jbot3.A30@1828.19,-1273.77 Jbot3.A30@1825.49,-1276.46 ; Jbot4.A30@2615.45,-1282 2578.51,-1318.94 2553.24,-1318.94 2551.58,-1317.29 2504.8,-1317.29 2503.14,-1318.94 1898.21,-1318.94 1855.73,-1276.46 1828.19,-1276.46 Jbot3.A30@1825.49,-1276.46 ; Jbot4.A30@2628.19,-1273.77 2628.59,-1274.17 R2RB_IDL_17_12_TerB3.2@3414.99,-1274.17 3414.99,-1248 3414.48,-1247.49 R1RB_IDL_17_12_TerB3.1@3414.48,-1221.31
JB4: Jbot1.A29 Jbot2.A29 Jbot3.A29 Jbot4.A29 R1RB_IDL_17_12_TerB4.1 R2RB_IDL_17_12_TerB4.2 | length 3354.2
  Top Signal w8: Jbot1.A29@228.26,-1373.77 268.54,-1373.77 310.6,-1415.83 985.71,-1415.83 Jbot2.A29@1028.19,-1373.35 1067.63,-1373.35 1110.53,-1416.25 1785.71,-1416.25 Jbot3.A29@1828.19,-1373.77 1871.82,-1417.4 2504.68,-1417.4 2504.8,-1417.29 2551.58,-1417.29 2551.7,-1417.4 2601.67,-1417.4 2636.75,-1382.32 Jbot4.A29@2638.61,-1380.46 ; Jbot4.A29@2628.19,-1373.77 2628.59,-1374.17 R2RB_IDL_17_12_TerB4.2@3414.99,-1374.17 3414.99,-1348 3414.48,-1347.49 R1RB_IDL_17_12_TerB4.1@3414.48,-1321.31
JB5: Jbot1.A28 Jbot2.A28 Jbot3.A28 Jbot4.A28 R1RB_IDL_17_12_TerB5.1 R2RB_IDL_17_12_TerB5.2 | length 3346.6
  Top Signal w8: Jbot1.A28@228.26,-1473.77 268.54,-1473.77 310.6,-1515.83 985.71,-1515.83 Jbot2.A28@1028.19,-1473.35 1067.63,-1473.35 1110.53,-1516.25 1785.71,-1516.25 Jbot3.A28@1828.19,-1473.77 ; Jbot3.A28@1806.18,-1473.37 1828.19,-1473.37 1846.46,-1473.37 1889.34,-1516.25 2568.85,-1516.25 Jbot4.A28@2606.18,-1478.91 ; Jbot4.A28@2628.19,-1473.77 2632.22,-1477.8 3411.36,-1477.8 R2RB_IDL_17_12_TerB5.2@3414.99,-1474.17 3414.99,-1448 3414.48,-1447.49 R1RB_IDL_17_12_TerB5.1@3414.48,-1421.31
JB6: Jbot1.A27 Jbot2.A27 Jbot3.A27 Jbot4.A27 R1RB_IDL_17_12_TerB6.1 R2RB_IDL_17_12_TerB6.2 | length 3343.2
  Top Signal w8: Jbot1.A27@228.26,-1573.77 268.54,-1573.77 310.6,-1615.83 985.71,-1615.83 Jbot2.A27@1028.19,-1573.35 1071.09,-1616.25 1785.71,-1616.25 Jbot3.A27@1826.06,-1575.9 ; Jbot3.A27@1815.13,-1575.9 Jbot3.A27@1826.06,-1575.9 ; Jbot3.A27@1828.19,-1573.77 Jbot3.A27@1826.06,-1575.9 ; Jbot4.A27@2615.13,-1581.44 2578.19,-1618.38 1897.89,-1618.38 1855.4,-1575.9 1828.19,-1575.9 Jbot3.A27@1826.06,-1575.9 ; Jbot4.A27@2628.19,-1573.77 2628.59,-1574.17 R2RB_IDL_17_12_TerB6.2@3414.99,-1574.17 3414.99,-1548 3414.48,-1547.49 R1RB_IDL_17_12_TerB6.1@3414.48,-1521.31
JB7: Jbot1.A26 Jbot2.A26 Jbot3.A26 Jbot4.A26 R1RB_IDL_17_12_TerB7.1 R2RB_IDL_17_12_TerB7.2 | length 3345.4
  Top Signal w8: Jbot1.A26@228.26,-1673.77 268.54,-1673.77 310.6,-1715.83 985.71,-1715.83 Jbot2.A26@1028.19,-1673.35 1067.63,-1673.35 1110.53,-1716.25 1785.71,-1716.25 Jbot3.A26@1828.19,-1673.77 ; Jbot3.A26@1819.36,-1672.7 1828.19,-1672.7 1859.64,-1672.7 1903.18,-1716.25 2581.36,-1716.25 Jbot4.A26@2619.36,-1678.24 ; Jbot4.A26@2628.19,-1673.77 2631.59,-1677.17 R2RB_IDL_17_12_TerB7.2@3414.99,-1677.17 3414.99,-1651 3414.48,-1650.49 R1RB_IDL_17_12_TerB7.1@3414.48,-1624.31
JB8: Jbot1.A25 Jbot2.A25 Jbot3.A25 Jbot4.A25 R1RB_IDL_17_12_TerB8.1 R2RB_IDL_17_12_TerB8.2 | length 3345.1
  Top Signal w8: Jbot1.A25@228.26,-1773.77 268.54,-1773.77 310.6,-1815.83 985.71,-1815.83 Jbot2.A25@1028.19,-1773.35 1071.09,-1816.25 1785.71,-1816.25 Jbot3.A25@1826.4,-1775.56 ; Jbot3.A25@1816.34,-1775.56 Jbot3.A25@1826.4,-1775.56 ; Jbot3.A25@1828.19,-1773.77 Jbot3.A25@1826.4,-1775.56 ; Jbot4.A25@2616.34,-1781.1 2579.4,-1818.04 2552.34,-1818.04 2551.58,-1817.29 2504.8,-1817.29 2504.04,-1818.04 1899.1,-1818.04 1856.61,-1775.56 1828.19,-1775.56 Jbot3.A25@1826.4,-1775.56 ; Jbot4.A25@2628.19,-1773.77 2631.59,-1777.17 R2RB_IDL_17_12_TerB8.2@3414.99,-1777.17 3414.99,-1724.82 R1RB_IDL_17_12_TerB8.1@3414.48,-1724.31
JB9: Jbot1.A24 Jbot2.A24 Jbot3.A24 Jbot4.A24 R1RB_IDL_17_12_TerB9.1 R2RB_IDL_17_12_TerB9.2 | length 3344.6
  Top Signal w8: Jbot1.A24@228.26,-1873.77 268.54,-1873.77 310.6,-1915.83 985.71,-1915.83 Jbot2.A24@1028.19,-1873.35 1044.05,-1873.35 1086.95,-1916.25 1785.71,-1916.25 Jbot3.A24@1827.17,-1874.79 ; Jbot3.A24@1818.15,-1874.79 Jbot3.A24@1827.17,-1874.79 ; Jbot3.A24@1828.19,-1873.77 Jbot3.A24@1827.17,-1874.79 ; Jbot4.A24@2618.15,-1880.33 2581.21,-1917.27 1900.91,-1917.27 1858.43,-1874.79 1828.19,-1874.79 Jbot3.A24@1827.17,-1874.79 ; Jbot4.A24@2628.19,-1873.77 2631.73,-1877.31 3022.26,-1877.31 3022.4,-1877.17 R2RB_IDL_17_12_TerB9.2@3414.99,-1877.17 3414.99,-1851 3414.48,-1850.49 R1RB_IDL_17_12_TerB9.1@3414.48,-1824.31
JB10: Jbot1.A23 Jbot2.A23 Jbot3.A23 Jbot4.A23 R1RB_IDL_17_12_TerB10.1 R2RB_IDL_17_12_TerB10.2 | length 3345
  Top Signal w8: Jbot1.A23@228.26,-1973.77 268.54,-1973.77 310.6,-2015.83 985.71,-2015.83 Jbot2.A23@1028.19,-1973.35 1071.66,-2016.81 1785.14,-2016.81 Jbot3.A23@1823.71,-1978.25 ; Jbot3.A23@1816.94,-1978.25 Jbot3.A23@1823.71,-1978.25 ; Jbot3.A23@1828.19,-1973.77 Jbot3.A23@1823.71,-1978.25 ; Jbot4.A23@2616.94,-1983.79 2580,-2020.73 1899.7,-2020.73 1857.22,-1978.25 1828.19,-1978.25 Jbot3.A23@1823.71,-1978.25 ; Jbot4.A23@2628.19,-1973.77 2631.63,-1977.21 3022.36,-1977.21 3022.4,-1977.17 R2RB_IDL_17_12_TerB10.2@3414.99,-1977.17 3414.99,-1951 3414.48,-1950.49 R1RB_IDL_17_12_TerB10.1@3414.48,-1924.31
JB11: Jbot1.A22 Jbot2.A22 Jbot3.A22 Jbot4.A22 R1RB_IDL_17_12_TerB11.1 R2RB_IDL_17_12_TerB11.2 | length 3348.6
  Top Signal w8: Jbot1.A22@228.26,-2073.77 268.54,-2073.77 310.6,-2115.83 985.71,-2115.83 Jbot2.A22@1028.19,-2073.35 1072.03,-2117.18 1784.77,-2117.18 Jbot3.A22@1828.19,-2073.77 ; Jbot3.A22@1821.78,-2073.24 1828.19,-2073.24 1828.45,-2073.5 1872.23,-2117.28 2583.28,-2117.28 Jbot4.A22@2621.78,-2078.78 ; Jbot4.A22@2628.19,-2073.77 2636.59,-2082.17 R2RB_IDL_17_12_TerB11.2@3414.99,-2082.17 3414.99,-2056 3414.48,-2055.49 R1RB_IDL_17_12_TerB11.1@3414.48,-2029.31
JB12: Jbot1.A21 Jbot2.A21 Jbot3.A21 Jbot4.A21 R1RB_IDL_17_12_TerB12.1 R2RB_IDL_17_12_TerB12.2 | length 3343.2
  Top Signal w8: Jbot1.A21@228.26,-2173.77 268.54,-2173.77 310.6,-2215.83 985.71,-2215.83 Jbot2.A21@1028.19,-2173.35 1071.09,-2216.25 1785.71,-2216.25 Jbot3.A21@1823.44,-2178.51 ; Jbot3.A21@1805.45,-2178.51 Jbot3.A21@1823.44,-2178.51 ; Jbot3.A21@1828.19,-2173.77 Jbot3.A21@1823.44,-2178.51 ; Jbot4.A21@2605.45,-2184.05 2572.51,-2216.99 1884.2,-2216.99 1845.72,-2178.51 1828.19,-2178.51 Jbot3.A21@1823.44,-2178.51 ; Jbot4.A21@2628.19,-2173.77 2636.59,-2182.17 R2RB_IDL_17_12_TerB12.2@3414.99,-2182.17 3414.99,-2156 3414.48,-2155.49 R1RB_IDL_17_12_TerB12.1@3414.48,-2129.31
JB13: Jbot1.A20 Jbot2.A20 Jbot3.A20 Jbot4.A20 R1RB_IDL_17_12_TerB13.1 R2RB_IDL_17_12_TerB13.2 | length 3344.4
  Top Signal w8: Jbot1.A20@228.26,-2273.77 268.54,-2273.77 310.6,-2315.83 985.71,-2315.83 Jbot2.A20@1028.19,-2273.35 1067.63,-2273.35 1110.53,-2316.25 1785.71,-2316.25 Jbot3.A20@1825.43,-2276.53 ; Jbot3.A20@1807.26,-2276.53 Jbot3.A20@1825.43,-2276.53 ; Jbot3.A20@1828.19,-2273.77 Jbot3.A20@1825.43,-2276.53 ; Jbot4.A20@2607.26,-2282.07 2572.98,-2316.35 1887.36,-2316.35 1847.54,-2276.53 1828.19,-2276.53 Jbot3.A20@1825.43,-2276.53 ; Jbot4.A20@2628.19,-2273.77 2636.59,-2282.17 R2RB_IDL_17_12_TerB13.2@3414.99,-2282.17 3414.99,-2256 3414.48,-2255.49 R1RB_IDL_17_12_TerB13.1@3414.48,-2229.31
JB14: Jbot1.A19 Jbot2.A19 Jbot3.A19 Jbot4.A19 R1RB_IDL_17_12_TerB14.1 R2RB_IDL_17_12_TerB14.2 | length 3347.3
  Top Signal w8: Jbot1.A19@228.26,-2373.77 268.54,-2373.77 310.6,-2415.83 985.71,-2415.83 Jbot2.A19@1028.19,-2373.35 1071.09,-2416.25 1785.71,-2416.25 Jbot3.A19@1826.2,-2375.76 ; Jbot3.A19@1816.94,-2375.76 Jbot3.A19@1826.2,-2375.76 ; Jbot3.A19@1828.19,-2373.77 Jbot3.A19@1826.2,-2375.76 ; Jbot4.A19@2616.94,-2381.3 2580,-2418.24 2552.54,-2418.24 2551.58,-2417.29 2504.8,-2417.29 2503.84,-2418.24 1899.7,-2418.24 1857.22,-2375.76 1828.19,-2375.76 Jbot3.A19@1826.2,-2375.76 ; Jbot4.A19@2628.19,-2373.77 2636.59,-2382.17 R2RB_IDL_17_12_TerB14.2@3414.99,-2382.17 3414.99,-2356 3414.48,-2355.49 R1RB_IDL_17_12_TerB14.1@3414.48,-2329.31
JB15: Jbot1.A18 Jbot2.A18 Jbot3.A18 Jbot4.A18 R1RB_IDL_17_12_TerB15.1 R2RB_IDL_17_12_TerB15.2 | length 3349.2
  Top Signal w8: Jbot1.A18@228.26,-2473.77 268.54,-2473.77 310.6,-2515.83 985.71,-2515.83 Jbot2.A18@1028.19,-2473.35 1071.09,-2516.25 1785.71,-2516.25 Jbot3.A18@1826.37,-2475.59 ; Jbot3.A18@1804.84,-2475.59 Jbot3.A18@1826.37,-2475.59 ; Jbot3.A18@1828.19,-2473.77 Jbot3.A18@1826.37,-2475.59 ; Jbot4.A18@2604.84,-2481.13 2567.9,-2518.07 1887.6,-2518.07 1845.12,-2475.59 1828.19,-2475.59 Jbot3.A18@1826.37,-2475.59 ; Jbot4.A18@2628.19,-2473.77 2639.79,-2485.36 3411.8,-2485.36 R2RB_IDL_17_12_TerB15.2@3414.99,-2482.17 3414.99,-2456 3414.48,-2455.49 R1RB_IDL_17_12_TerB15.1@3414.48,-2429.31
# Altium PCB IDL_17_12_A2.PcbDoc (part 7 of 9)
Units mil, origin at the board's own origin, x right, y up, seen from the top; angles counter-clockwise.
Board outline 5119.97 x 10350 mil, 6 copper layers (Top Signal, 3.3 Volt, GND, 5 Volt, Split Plane, Bot Signal), stack 66.2 mil thick; 514 components, 178 nets, 2321 pads, 427 vias.

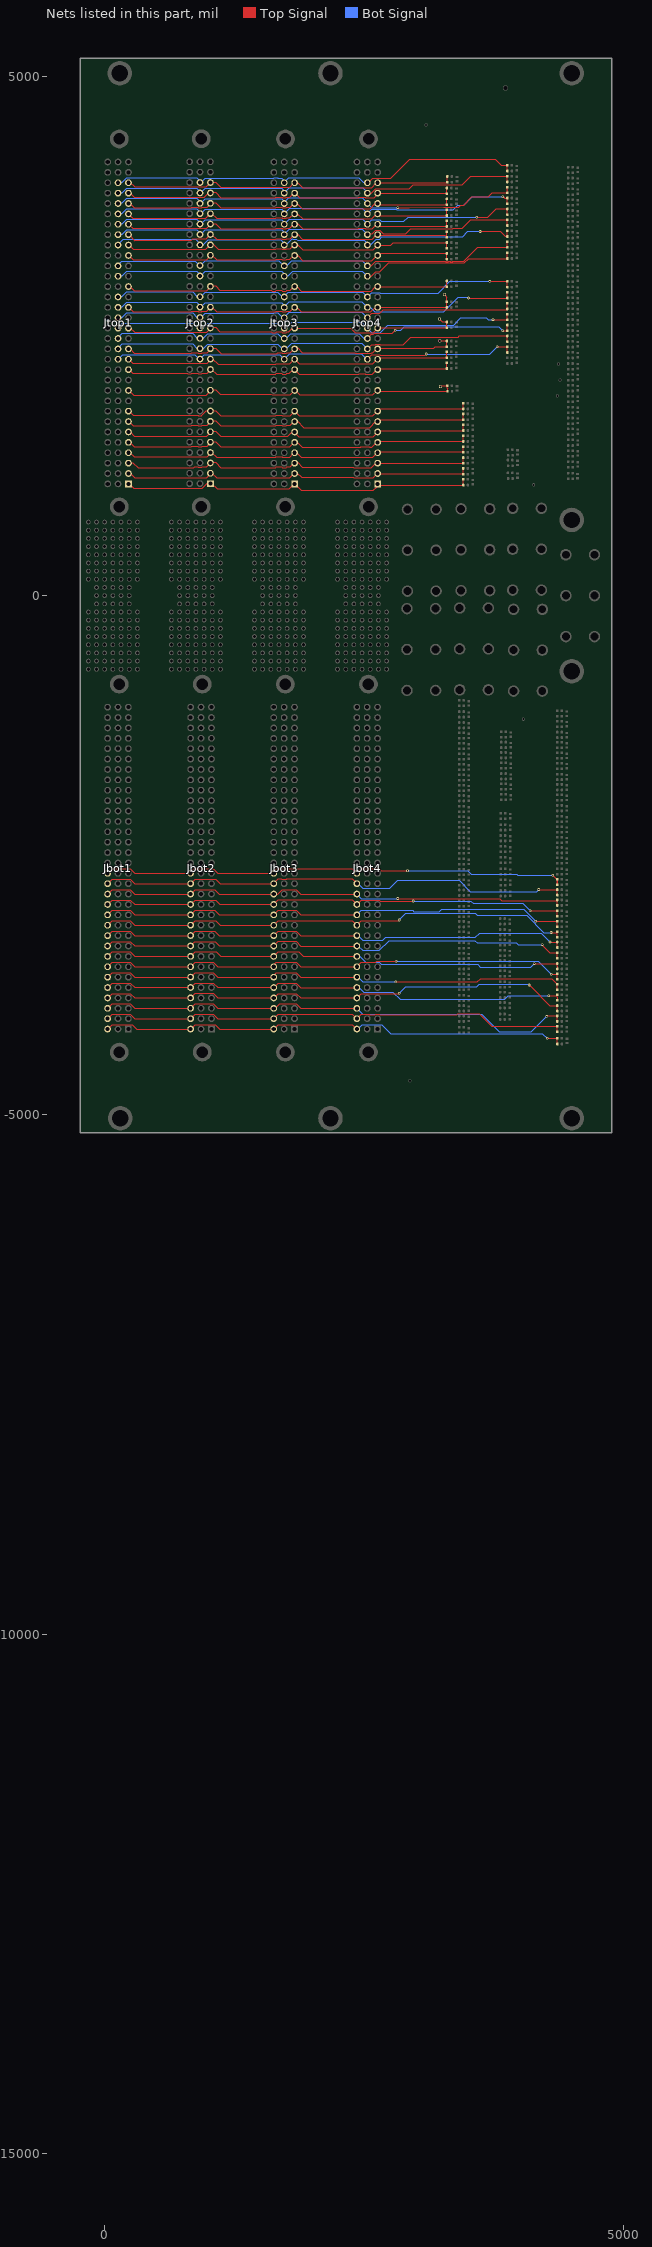
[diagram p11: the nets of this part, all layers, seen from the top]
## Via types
v1: diameter 25.59, hole 11.81, Top Signal to Bot Signal, 427 vias

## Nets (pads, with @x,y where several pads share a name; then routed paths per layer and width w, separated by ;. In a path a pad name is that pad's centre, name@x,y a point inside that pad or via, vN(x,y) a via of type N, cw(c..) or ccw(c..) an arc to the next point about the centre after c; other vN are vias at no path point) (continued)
JB74: Jbot1.C16 Jbot2.C16 Jbot3.C16 Jbot4.C16 R1RB_IDL_17_12_TerB74.1 R2RB_IDL_17_12_TerB74.2 | length 4608.1
  Top Signal w8: Jbot1.C16@28.26,-2673.77 70.74,-2631.29 245.86,-2631.29 287.92,-2673.35 Jbot2.C16@828.19,-2673.35 828.19,-2662.25 859.57,-2630.87 1045.79,-2630.87 1088.27,-2673.35 1608.49,-2673.35 1618.13,-2663.7 1650.55,-2631.29 2385.71,-2631.29 Jbot4.C16@2428.19,-2673.77 2470.67,-2631.29 2645.79,-2631.29 2664.14,-2649.64 v1(2916.16,-2649.64) ; v1(4315.57,-2692.8) 4355.59,-2732.82 4356.82,-2734.05 4358.16,-2750.98 ; R1RB_IDL_17_12_TerB74.1@4358.16,-2730.25 4358.16,-2750.98 ; 4358.16,-2750.98 4360.69,-2782.95 4360.88,-2785.31 R2RB_IDL_17_12_TerB74.2@4358.67,-2783.11 4358.16,-2782.6 4358.16,-2750.98
  Bot Signal w8: v1(2916.16,-2649.64) 3494.17,-2649.64 3528.97,-2684.44 3968.51,-2684.44 3976.87,-2692.8 v1(4315.57,-2692.8)
JB75: Jbot1.C15 Jbot2.C15 Jbot3.C15 Jbot4.C15 R1RB_IDL_17_12_TerB75.1 R2RB_IDL_17_12_TerB75.2 | length 4595.1
  Top Signal w8: Jbot1.C15@28.26,-2773.77 70.74,-2731.29 245.86,-2731.29 287.92,-2773.35 Jbot2.C15@828.19,-2773.35 870.67,-2730.87 1071.16,-2730.87 1113.64,-2773.35 1627.77,-2773.35 Jbot3.C15@1628.19,-2773.77 1673.84,-2728.12 1702.67,-2728.12 1704.79,-2730.25 1751.58,-2730.25 1753.71,-2728.12 2382.54,-2728.12 Jbot4.C15@2428.19,-2773.77 ; v1(4179.33,-2830.25) R1RB_IDL_17_12_TerB75.1@4358.16,-2830.25 4358.16,-2856.94 4358.67,-2857.46 R2RB_IDL_17_12_TerB75.2@4358.67,-2883.11
  Bot Signal w8: Jbot4.C15@2428.19,-2773.77 2442.94,-2773.77 2487.26,-2818.08 2604,-2818.08 2604.8,-2817.29 2651.58,-2817.29 2652.38,-2818.08 2747.11,-2818.08 2822.66,-2742.54 3413.54,-2742.54 3520,-2849 4160.58,-2849 v1(4179.33,-2830.25)
JB76: Jbot1.C14 Jbot2.C14 Jbot3.C14 Jbot4.C14 R1RB_IDL_17_12_TerB76.1 R2RB_IDL_17_12_TerB76.2 | length 4520.8
  Top Signal w8: Jbot1.C14@28.26,-2873.77 70.74,-2831.29 245.86,-2831.29 287.92,-2873.35 Jbot2.C14@828.19,-2873.35 870.67,-2830.87 1061.41,-2830.87 1103.89,-2873.35 1627.77,-2873.35 Jbot3.C14@1628.19,-2873.77 1668.11,-2873.77 1710.59,-2831.29 1750.99,-2831.29 1752.47,-2829.8 1844.3,-2829.8 1888.27,-2873.77 Jbot4.C14@2428.19,-2873.77 ; v1(2821.33,-2916.52) 3401.98,-2916.52 3802.76,-2916.51 3825.67,-2939.42 4348.99,-2939.42 R1RB_IDL_17_12_TerB76.1@4358.16,-2930.25 4358.16,-2956.94 4358.67,-2957.46 R2RB_IDL_17_12_TerB76.2@4358.67,-2983.11
  Bot Signal w8: Jbot4.C14@2428.19,-2873.77 2470.94,-2916.52 v1(2821.33,-2916.52)
JB77: Jbot1.C13 Jbot2.C13 Jbot3.C13 Jbot4.C13 R1RB_IDL_17_12_TerB77.1 R2RB_IDL_17_12_TerB77.2 | length 4550.1
  Top Signal w8: Jbot1.C13@28.26,-2973.77 70.74,-2931.29 245.86,-2931.29 287.92,-2973.35 Jbot2.C13@828.19,-2973.35 870.67,-2930.87 1067.91,-2930.87 1110.39,-2973.35 1627.77,-2973.35 Jbot3.C13@1628.19,-2973.77 1671.71,-2930.25 2384.67,-2930.25 Jbot4.C13@2428.19,-2973.77 2470.67,-2931.29 2645.79,-2931.29 2655.2,-2940.7 v1(2971.76,-2940.7) ; v1(4096.79,-3035.25) R1RB_IDL_17_12_TerB77.1@4358.16,-3035.25 4358.16,-3061.94 4358.67,-3062.46 R2RB_IDL_17_12_TerB77.2@4358.67,-3088.11
  Bot Signal w8: v1(2971.76,-2940.7) 3524.86,-2940.7 3548.24,-2964.07 4025.61,-2964.07 v1(4096.79,-3035.25)
JB78: Jbot1.C12 Jbot2.C12 Jbot3.C12 Jbot4.C12 R1RB_IDL_17_12_TerB78.1 R2RB_IDL_17_12_TerB78.2 | length 4569.5
  Top Signal w8: Jbot1.C12@28.26,-3073.77 70.74,-3031.29 245.86,-3031.29 287.92,-3073.35 Jbot2.C12@828.19,-3073.35 870.67,-3030.87 1062.13,-3030.87 1104.61,-3073.35 1627.77,-3073.35 Jbot3.C12@1628.19,-3073.77 1671.99,-3029.97 1704.52,-3029.97 1704.8,-3030.25 1751.58,-3030.25 1751.86,-3029.97 1844.47,-3029.97 1888.27,-3073.77 Jbot4.C12@2428.19,-3073.77 ; v1(4151.68,-3135.25) R1RB_IDL_17_12_TerB78.1@4358.16,-3135.25 4358.67,-3135.76 R2RB_IDL_17_12_TerB78.2@4358.67,-3188.11
  Bot Signal w8: Jbot4.C12@2428.19,-3073.77 2470.67,-3031.29 2967.69,-3031.29 2978.45,-3042.05 3220.99,-3042.05 3243.9,-3019.15 4035.58,-3019.15 v1(4151.68,-3135.25)
JB79: Jbot1.C11 Jbot2.C11 Jbot3.C11 Jbot4.C11 R1RB_IDL_17_12_TerB79.1 R2RB_IDL_17_12_TerB79.2 | length 4617.8
  Top Signal w8: Jbot1.C11@28.26,-3173.77 70.74,-3131.29 245.86,-3131.29 287.92,-3173.35 Jbot2.C11@828.19,-3173.35 870.67,-3130.87 1069.53,-3130.87 1111.84,-3173.17 1111.84,-3173.35 1627.77,-3173.35 Jbot3.C11@1628.19,-3173.77 1672.34,-3129.61 1704.16,-3129.61 1704.8,-3130.25 1751.58,-3130.25 1752.22,-3129.61 2384.04,-3129.61 Jbot4.C11@2428.19,-3173.77 2470.67,-3131.29 2827.29,-3131.29 v1(2835.72,-3122.86) ; v1(4298.99,-3244.35) 4349.06,-3244.35 R1RB_IDL_17_12_TerB79.1@4358.16,-3235.25 4358.16,-3287.6 R2RB_IDL_17_12_TerB79.2@4358.67,-3288.11
  Bot Signal w8: v1(2835.72,-3122.86) 2898.54,-3060.04 3568.4,-3060.04 3587.18,-3078.82 4062.43,-3078.82 4227.97,-3244.35 v1(4298.99,-3244.35)
JB80: Jbot1.C10 Jbot2.C10 Jbot3.C10 Jbot4.C10 R1RB_IDL_17_12_TerB80.1 R2RB_IDL_17_12_TerB80.2 | length 4570.5
  Top Signal w8: Jbot1.C10@28.26,-3273.77 70.74,-3231.29 245.86,-3231.29 287.92,-3273.35 Jbot2.C10@828.19,-3273.35 870.67,-3230.87 1060.69,-3230.87 1103.17,-3273.35 1627.77,-3273.35 Jbot3.C10@1628.19,-3273.77 1671.99,-3229.97 1704.52,-3229.97 1704.8,-3230.25 1751.58,-3230.25 1751.86,-3229.97 1844.47,-3229.97 1888.27,-3273.77 Jbot4.C10@2428.19,-3273.77 ; v1(4288.68,-3335.25) R1RB_IDL_17_12_TerB80.1@4358.16,-3335.25 4358.16,-3387.6 R2RB_IDL_17_12_TerB80.2@4358.67,-3388.11
  Bot Signal w8: Jbot4.C10@2428.19,-3273.77 2442.94,-3273.77 2486.18,-3317 2486.93,-3316.25 2679.84,-3316.25 2705.3,-3290.8 3569.56,-3290.8 3609.92,-3250.44 4203.87,-3250.44 v1(4288.68,-3335.25)
JB81: Jbot1.C9 Jbot2.C9 Jbot3.C9 Jbot4.C9 R1RB_IDL_17_12_TerB81.1 R2RB_IDL_17_12_TerB81.2 | length 4603.5
  Top Signal w8: Jbot1.C9@28.26,-3373.77 70.74,-3331.29 245.86,-3331.29 287.92,-3373.35 Jbot2.C9@828.19,-3373.35 868.69,-3332.84 908.62,-3332.84 910.59,-3330.87 1062.85,-3330.87 1105.33,-3373.35 1627.77,-3373.35 Jbot3.C9@1628.19,-3373.77 1671.99,-3329.97 1704.52,-3329.97 1704.79,-3330.25 1751.58,-3330.25 1751.86,-3329.97 1844.47,-3329.97 1888.27,-3373.77 Jbot4.C9@2428.19,-3373.77 ; v1(4213.24,-3360.4) 4209.54,-3364.11 4285.68,-3440.25 R1RB_IDL_17_12_TerB81.1@4358.16,-3440.25 4358.16,-3466.94 4358.67,-3467.46 R2RB_IDL_17_12_TerB81.2@4358.67,-3493.11
  Bot Signal w8: Jbot4.C9@2428.19,-3373.77 2442.94,-3373.77 2485.43,-3416.25 2645.79,-3416.25 2740.75,-3321.28 3565.77,-3321.28 3586.93,-3342.44 3963.51,-3342.44 3981.48,-3360.4 v1(4213.24,-3360.4)
JB82: Jbot1.C8 Jbot2.C8 Jbot3.C8 Jbot4.C8 R1RB_IDL_17_12_TerB82.1 R2RB_IDL_17_12_TerB82.2 | length 4546.5
  Top Signal w8: Jbot1.C8@28.26,-3473.77 70.74,-3431.29 245.86,-3431.29 287.92,-3473.35 Jbot2.C8@828.19,-3473.35 870.67,-3430.87 1075.14,-3430.87 1117.62,-3473.35 1627.77,-3473.35 Jbot3.C8@1628.19,-3473.77 1671.99,-3429.97 1704.52,-3429.97 1704.8,-3430.25 1751.58,-3430.25 1751.86,-3429.97 1869.72,-3429.97 1913.52,-3473.77 Jbot4.C8@2428.19,-3473.77 ; v1(4137.6,-3543.46) R1RB_IDL_17_12_TerB82.1@4358.16,-3543.46 ; R1RB_IDL_17_12_TerB82.1@4358.16,-3542.25 R1RB_IDL_17_12_TerB82.1@4358.16,-3543.46 ; R2RB_IDL_17_12_TerB82.2@4358.67,-3595.11 4358.16,-3568.94 R1RB_IDL_17_12_TerB82.1@4358.16,-3543.46
  Bot Signal w8: Jbot4.C8@2428.19,-3473.77 2455.15,-3473.77 2512.67,-3531.29 2645.79,-3531.29 2665.7,-3551.2 3591.99,-3551.2 3617.94,-3577.16 4103.89,-3577.16 v1(4137.6,-3543.46)
JB83: Jbot1.C7 Jbot2.C7 Jbot3.C7 Jbot4.C7 R1RB_IDL_17_12_TerB83.1 R2RB_IDL_17_12_TerB83.2 | length 4563.4
  Top Signal w8: Jbot1.C7@28.26,-3573.77 70.74,-3531.29 245.86,-3531.29 287.92,-3573.35 Jbot2.C7@828.19,-3573.35 871.62,-3529.92 1044.84,-3529.92 1088.27,-3573.35 1608.49,-3573.35 1618.13,-3563.7 1650.55,-3531.29 1845.79,-3531.29 1888.27,-3573.77 Jbot4.C7@2428.19,-3573.77 2470.67,-3531.29 2610.59,-3531.29 2620.76,-3521.12 2800.73,-3521.12 2803.47,-3523.87 2806.45,-3526.84 v1(2806.45,-3520.89) ; v1(4299.9,-3645.48) 4354.93,-3645.48 R1RB_IDL_17_12_TerB83.1@4358.16,-3642.25 4358.16,-3694.6 R2RB_IDL_17_12_TerB83.2@4358.67,-3695.11
  Bot Signal w8: v1@2815.7,-3521.75 2816.79,-3520.66 4175.08,-3520.66 v1(4299.9,-3645.48)
JB84: Jbot1.C6 Jbot2.C6 Jbot3.C6 Jbot4.C6 R1RB_IDL_17_12_TerB84.1 R2RB_IDL_17_12_TerB84.2 | length 4543.9
  Top Signal w8: Jbot1.C6@28.26,-3673.77 70.74,-3631.29 245.86,-3631.29 287.92,-3673.35 Jbot2.C6@828.19,-3673.35 871.01,-3630.52 1045.44,-3630.52 1088.27,-3673.35 1608.49,-3673.35 1618.13,-3663.7 1650.55,-3631.29 1845.79,-3631.29 1888.27,-3673.77 Jbot4.C6@2428.19,-3673.77 ; v1(2802.08,-3719.17) 3550.2,-3719.17 3550.68,-3718.69 3586.72,-3718.69 3587.94,-3719.9 3620.16,-3687.68 3748.83,-3687.68 3749.35,-3688.2 4304.11,-3688.2 R1RB_IDL_17_12_TerB84.1@4358.16,-3742.25 4358.16,-3768.94 4358.67,-3769.46 R2RB_IDL_17_12_TerB84.2@4358.67,-3795.11
  Bot Signal w8: Jbot4.C6@2428.19,-3673.77 2442.94,-3673.77 2486.46,-3717.29 2800.2,-3717.29 v1(2802.08,-3719.17)
JB85: Jbot1.C5 Jbot2.C5 Jbot3.C5 Jbot4.C5 R1RB_IDL_17_12_TerB85.1 R2RB_IDL_17_12_TerB85.2 | length 4551
  Top Signal w8: Jbot1.C5@28.26,-3773.77 70.74,-3731.29 245.86,-3731.29 287.92,-3773.35 Jbot2.C5@828.19,-3773.35 870.67,-3730.87 1045.79,-3730.87 1088.27,-3773.35 1627.77,-3773.35 Jbot3.C5@1628.19,-3773.77 1670.67,-3731.29 1845.79,-3731.29 1888.27,-3773.77 Jbot4.C5@2428.19,-3773.77 ; v1(4275.93,-3852.46) R1RB_IDL_17_12_TerB85.1@4358.16,-3852.46 ; R1RB_IDL_17_12_TerB85.1@4358.16,-3842.25 R1RB_IDL_17_12_TerB85.1@4358.16,-3852.46 ; R2RB_IDL_17_12_TerB85.2@4358.67,-3895.11 4358.16,-3868.94 R1RB_IDL_17_12_TerB85.1@4358.16,-3852.46
  Bot Signal w8: Jbot4.C5@2428.19,-3773.77 2451.37,-3773.77 2497.23,-3819.62 2774.9,-3819.62 2844.07,-3888.8 3851.52,-3888.8 3887.86,-3852.46 v1(4275.93,-3852.46)
JB86: Jbot1.C4 Jbot2.C4 Jbot3.C4 Jbot4.C4 R1RB_IDL_17_12_TerB86.1 R2RB_IDL_17_12_TerB86.2 | length 4630.8
  Top Signal w8: Jbot1.C4@28.26,-3873.77 70.74,-3831.29 245.86,-3831.29 287.92,-3873.35 Jbot2.C4@828.19,-3873.35 870.67,-3830.87 1045.79,-3830.87 1088.27,-3873.35 1627.77,-3873.35 Jbot3.C4@1628.19,-3873.77 1670.67,-3831.29 1845.79,-3831.29 1888.27,-3873.77 Jbot4.C4@2428.19,-3873.77 2470.67,-3831.29 2834.4,-3831.29 v1(2836.02,-3829.66) ; v1(4087.23,-3750) 4100.68,-3763.46 4101.89,-3763.46 4285.68,-3947.25 R1RB_IDL_17_12_TerB86.1@4358.16,-3947.25 4358.16,-3973.94 4358.67,-3974.46 R2RB_IDL_17_12_TerB86.2@4358.67,-4000.11
  Bot Signal w8: v1(2836.02,-3829.66) 2836.02,-3827.35 2899.09,-3764.28 3582.92,-3764.28 3606.76,-3740.44 4077.66,-3740.44 v1(4087.23,-3750)
JB87: Jbot1.C3 Jbot2.C3 Jbot3.C3 Jbot4.C3 R1RB_IDL_17_12_TerB87.1 R2RB_IDL_17_12_TerB87.2 | length 4645
  Top Signal w8: Jbot1.C3@28.26,-3973.77 70.74,-3931.29 245.86,-3931.29 287.92,-3973.35 Jbot2.C3@828.19,-3973.35 870.67,-3930.87 1045.79,-3930.87 1088.27,-3973.35 1627.77,-3973.35 Jbot3.C3@1628.19,-3973.77 1642.67,-3973.77 1685.9,-3930.53 ; 1685.9,-3930.25 1844.68,-3930.25 ; 1844.68,-3930.18 1888.27,-3973.77 Jbot4.C3@2428.19,-3973.77 ; v1(4256.68,-4051.46) 4260.89,-4047.25 R1RB_IDL_17_12_TerB87.1@4358.16,-4047.25 4358.16,-4099.6 R2RB_IDL_17_12_TerB87.2@4358.67,-4100.11
  Bot Signal w8: Jbot4.C3@2428.19,-3973.77 2485.71,-4031.29 3631.64,-4031.29 3798.81,-4198.46 4109.68,-4198.46 v1(4256.68,-4051.46)
JB88: Jbot1.C2 Jbot2.C2 Jbot3.C2 Jbot4.C2 R1RB_IDL_17_12_TerB88.1 R2RB_IDL_17_12_TerB88.2 | length 4564.8
  Top Signal w8: Jbot1.C2@28.26,-4073.77 70.74,-4031.29 245.86,-4031.29 287.92,-4073.35 Jbot2.C2@828.19,-4073.35 870.67,-4030.87 1045.79,-4030.87 1088.27,-4073.35 1627.77,-4073.35 Jbot3.C2@1628.19,-4073.77 1670.67,-4031.29 2385.71,-4031.29 Jbot4.C2@2428.19,-4073.77 2470.67,-4031.29 2545.78,-4031.29 2548.82,-4034.32 2607.56,-4034.32 2610.59,-4031.29 2645.78,-4031.29 2648.82,-4034.32 3392.18,-4034.32 3401.98,-4024.51 3607.12,-4024.51 3729.86,-4147.25 R1RB_IDL_17_12_TerB88.1@4358.16,-4147.25 4358.16,-4173.94 4358.67,-4174.46 R2RB_IDL_17_12_TerB88.2@4358.67,-4200.11
JB89: Jbot1.C1 Jbot2.C1 Jbot3.C1 Jbot4.C1 R1RB_IDL_17_12_TerB89.1 R2RB_IDL_17_12_TerB89.2 | length 4564.4
  Top Signal w8: Jbot1.C1@28.26,-4173.77 70.74,-4131.29 264.88,-4131.29 306.94,-4173.35 Jbot2.C1@828.19,-4173.35 870.67,-4130.87 1064.81,-4130.87 1107.29,-4173.35 1627.77,-4173.35 Jbot3.C1@1628.19,-4173.77 1670.67,-4131.29 2385.71,-4131.29 Jbot4.C1@2428.19,-4173.77 ; v1(4261.68,-4262.25) R1RB_IDL_17_12_TerB89.1@4360.11,-4262.25 4360.11,-4290.42 ; R2RB_IDL_17_12_TerB89.2@4360.08,-4317.34 4360.08,-4290.46
  Bot Signal w8: Jbot4.C1@2428.19,-4173.77 2436.88,-4173.77 2479.36,-4131.29 2670.67,-4131.29 2755.84,-4216.46 4215.89,-4216.46 v1(4261.68,-4262.25)
JT1: Jtop1.A30 Jtop2.A30 Jtop3.A30 Jtop4.A30 R1R_IDL_17_12_TerA1.1 R2R_IDL_17_12_TerA1.2 | length 3249
  Top Signal w8: Jtop1.A30@228.79,3982.06 229.28,3982.06 241.96,3982.06 288.16,3935.87 978.39,3935.87 1018.19,3975.66 Jtop2.A30@1018.19,3978.35 ; Jtop2.A30@1018.19,3982.48 1068.16,3982.48 1116.89,3933.76 1646.87,3933.76 1648.28,3935.16 1710.28,3935.16 1711.68,3933.76 1780.41,3933.76 Jtop3.A30@1826.02,3979.37 ; Jtop3.A30@1815.98,3979.37 Jtop3.A30@1826.02,3979.37 ; Jtop3.A30@1828.72,3982.06 1826.09,3979.43 Jtop3.A30@1826.02,3979.37 ; Jtop4.A30@2615.98,3973.83 2570.47,3928.31 1907.31,3928.31 1856.26,3979.37 1829.28,3979.37 Jtop3.A30@1826.02,3979.37 ; Jtop4.A30@2629.28,3976.24 3295.38,3976.24 R2R_IDL_17_12_TerA1.2@3300.96,3981.81 3300.96,4008 3300.08,4008.88 R1R_IDL_17_12_TerA1.1@3300.08,4036.83
JT2: Jtop1.A29 Jtop2.A29 Jtop3.A29 Jtop4.A29 R1R_IDL_17_12_TerA2.1 R2R_IDL_17_12_TerA2.2 | length 3240.2
  Top Signal w8: Jtop1.A29@228.79,3882.06 Jtop1.A29@229.28,3882.06 ; Jtop1.A29@229.28,3876.24 245.63,3876.24 286,3835.87 835.78,3835.87 837.4,3837.48 898.98,3837.48 900.59,3835.87 935.78,3835.87 937.4,3837.48 960.44,3837.48 1001.31,3878.35 Jtop2.A29@1018.19,3878.35 ; Jtop2.A29@1028.72,3882.48 1068.16,3882.48 1116.89,3833.76 1646.87,3833.76 1649.86,3836.75 1708.69,3836.75 1711.68,3833.76 1746.87,3833.76 1749.86,3836.75 1783.4,3836.75 1826.09,3879.43 1828.72,3882.06 1831.91,3878.87 1877.03,3833.76 2446.87,3833.76 2447.33,3834.21 2511.23,3834.21 2511.68,3833.76 2597.53,3833.76 2634.64,3870.87 Jtop4.A29@2639.15,3875.37 ; Jtop4.A29@2629.28,3876.24 3290.29,3876.24 R2R_IDL_17_12_TerA2.2@3295.96,3870.57 3295.96,3897 3295.08,3897.88 R1R_IDL_17_12_TerA2.1@3295.08,3925.59
JT3: Jtop1.A28 Jtop2.A28 Jtop3.A28 Jtop4.A28 R1R_IDL_17_12_TerA3.1 R2R_IDL_17_12_TerA3.2 | length 3255.2
  Top Signal w8: Jtop1.A28@228.79,3782.06 229.28,3782.06 237.3,3782.06 283.5,3735.87 835.78,3735.87 839.92,3740 896.46,3740 900.59,3735.87 935.78,3735.87 939.92,3740 986.24,3740 1021.39,3775.15 1028.72,3782.48 1068.16,3782.48 1116.89,3733.76 1646.87,3733.76 1651.44,3738.32 1707.12,3738.32 1711.68,3733.76 1746.87,3733.76 1751.44,3738.32 1784.98,3738.32 1826.09,3779.43 Jtop3.A28@1828.72,3782.06 ; Jtop3.A28@1806.71,3782.46 1829.28,3782.46 1846.99,3782.46 1901.62,3727.83 2557.62,3727.83 Jtop4.A28@2606.71,3776.92 ; Jtop4.A28@2629.28,3776.24 2639.94,3765.57 R2R_IDL_17_12_TerA3.2@3295.96,3765.57 3295.96,3819.72 R1R_IDL_17_12_TerA3.1@3295.08,3820.59
JT4: Jtop1.A27 Jtop2.A27 Jtop3.A27 Jtop4.A27 R1R_IDL_17_12_TerA4.1 R2R_IDL_17_12_TerA4.2 | length 3236.1
  Top Signal w8: Jtop1.A27@228.79,3682.06 Jtop1.A27@229.28,3682.06 ; Jtop1.A27@229.28,3676.24 270.54,3634.97 974.81,3634.97 Jtop2.A27@1018.19,3678.35 ; Jtop2.A27@1028.72,3682.48 1077.45,3633.76 1646.87,3633.76 1650.52,3637.4 1708.04,3637.4 1711.68,3633.76 1746.87,3633.76 1750.52,3637.4 1784.06,3637.4 1826.09,3679.43 Jtop3.A27@1826.59,3679.93 ; Jtop3.A27@1815.66,3679.93 Jtop3.A27@1826.59,3679.93 ; Jtop3.A27@1828.72,3682.06 Jtop3.A27@1826.59,3679.93 ; Jtop4.A27@2615.66,3674.39 2570.25,3628.98 1906.89,3628.98 1855.94,3679.93 1829.28,3679.93 Jtop3.A27@1826.59,3679.93 ; Jtop4.A27@2629.28,3676.24 2644.94,3660.57 R2R_IDL_17_12_TerA4.2@3295.96,3660.57 3295.96,3687 3295.08,3687.88 R1R_IDL_17_12_TerA4.1@3295.08,3715.59
JT5: Jtop1.A26 Jtop2.A26 Jtop3.A26 Jtop4.A26 R1R_IDL_17_12_TerA5.1 R2R_IDL_17_12_TerA5.2 | length 3252.6
  Top Signal w8: Jtop1.A26@228.79,3582.06 Jtop1.A26@229.28,3582.06 ; Jtop1.A26@229.28,3576.24 269.65,3535.87 835.78,3535.87 838.26,3538.34 898.12,3538.34 900.59,3535.87 982.1,3535.87 1021.39,3575.15 1028.72,3582.48 1068.16,3582.48 1116.89,3533.76 1646.87,3533.76 1650.85,3537.73 1707.71,3537.73 1711.68,3533.76 1746.87,3533.76 1750.85,3537.73 1784.39,3537.73 1826.09,3579.43 Jtop3.A26@1828.72,3582.06 ; Jtop3.A26@1819.89,3583.13 1829.28,3583.13 1860.17,3583.13 1909.54,3533.76 2446.87,3533.76 2449.11,3535.99 2509.44,3535.99 2511.68,3533.76 2576.06,3533.76 Jtop4.A26@2619.89,3577.59 ; Jtop4.A26@2629.28,3576.24 2649.94,3555.57 R2R_IDL_17_12_TerA5.2@3295.96,3555.57 3295.96,3582 3295.08,3582.88 R1R_IDL_17_12_TerA5.1@3295.08,3610.59
JT6: Jtop1.A25 Jtop2.A25 Jtop3.A25 Jtop4.A25 R1R_IDL_17_12_TerA6.1 R2R_IDL_17_12_TerA6.2 | length 3251.5
  Top Signal w8: Jtop1.A25@228.79,3482.06 231.95,3478.91 290.99,3419.86 291.95,3420.83 834.76,3420.83 849.8,3435.87 935.78,3435.87 937.07,3437.15 977,3437.15 Jtop2.A25@1018.19,3478.35 ; Jtop2.A25@1028.72,3482.48 1077.45,3433.76 1646.87,3433.76 1651.93,3438.81 1706.63,3438.81 1711.68,3433.76 1746.87,3433.76 1751.93,3438.81 1785.47,3438.81 1826.09,3479.43 Jtop3.A25@1826.93,3480.27 ; Jtop3.A25@1816.87,3480.27 Jtop3.A25@1826.93,3480.27 ; Jtop3.A25@1828.72,3482.06 Jtop3.A25@1826.93,3480.27 ; Jtop4.A25@2616.87,3474.73 2575.9,3433.76 1903.66,3433.76 1857.15,3480.27 1829.28,3480.27 Jtop3.A25@1826.93,3480.27 ; Jtop4.A25@2629.28,3476.24 2635.77,3469.75 3276.78,3469.75 R2R_IDL_17_12_TerA6.2@3295.08,3451.45 ; R1R_IDL_17_12_TerA6.1@3295.08,3505.59 R2R_IDL_17_12_TerA6.2@3295.08,3451.45 ; R2R_IDL_17_12_TerA6.2@3295.96,3450.57 R2R_IDL_17_12_TerA6.2@3295.08,3451.45
JT7: Jtop1.A24 Jtop2.A24 Jtop3.A24 Jtop4.A24 R1R_IDL_17_12_TerA7.1 R2R_IDL_17_12_TerA7.2 | length 3273.8
  Top Signal w8: Jtop1.A24@228.79,3382.06 231.95,3378.91 274.99,3335.87 975.71,3335.87 Jtop2.A24@1018.19,3378.35 1018.19,3371.95 1021.39,3375.15 1028.72,3382.48 1044.58,3382.48 1093.31,3333.76 1646.87,3333.76 1652.76,3339.64 1705.8,3339.64 1711.68,3333.76 1746.87,3333.76 1752.76,3339.64 1786.3,3339.64 1826.09,3379.43 Jtop3.A24@1827.7,3381.04 ; Jtop3.A24@1818.68,3381.04 Jtop3.A24@1827.7,3381.04 ; Jtop3.A24@1828.72,3382.06 Jtop3.A24@1827.7,3381.04 ; R2R_IDL_17_12_TerA7.2@3295.96,3345.57 3295.96,3372 3295.08,3372.88 R1R_IDL_17_12_TerA7.1@3295.08,3400.59 2780.88,3400.59 2756.52,3376.24 Jtop4.A24@2629.28,3376.24 2584.05,3331.01 1909,3331.01 1858.96,3381.04 1829.28,3381.04 Jtop3.A24@1827.7,3381.04
JT8: Jtop1.A23 Jtop2.A23 Jtop3.A23 Jtop4.A23 R1R_IDL_17_12_TerA8.1 R2R_IDL_17_12_TerA8.2 | length 3265
  Top Signal w8: Jtop1.A23@228.79,3282.06 231.95,3278.91 274.99,3235.87 835.78,3235.87 836.16,3236.25 900.21,3236.25 900.59,3235.87 982.1,3235.87 1021.39,3275.15 1028.72,3282.48 1077.45,3233.76 1646.87,3233.76 1651.09,3237.97 1707.47,3237.97 1711.68,3233.76 1746.87,3233.76 1751.09,3237.97 1784.63,3237.97 Jtop3.A23@1824.24,3277.58 ; Jtop3.A23@1817.47,3277.58 Jtop3.A23@1824.24,3277.58 ; Jtop3.A23@1828.72,3282.06 1826.09,3279.43 Jtop3.A23@1824.24,3277.58 ; R2R_IDL_17_12_TerA8.2@3295.96,3240.57 3295.96,3267 3295.08,3267.88 R1R_IDL_17_12_TerA8.1@3295.08,3295.59 2641.02,3295.59 2625.47,3280.04 2572.07,3226.63 1908.7,3226.63 1857.75,3277.58 1829.28,3277.58 Jtop3.A23@1824.24,3277.58
JT9: Jtop1.A20 Jtop2.A20 Jtop3.A20 Jtop4.A20 R1R_IDL_17_12_TerA9.1 R2R_IDL_17_12_TerA9.2 | length 3244.7
  Top Signal w8: Jtop1.A20@228.79,2982.06 229.28,2982.06 238.83,2982.06 285.02,2935.87 835.78,2935.87 837.51,2937.59 898.87,2937.59 900.59,2935.87 935.78,2935.87 937.51,2937.59 983.83,2937.59 1021.39,2975.15 1028.72,2982.48 1068.16,2982.48 1109.69,2940.95 1604.49,2940.95 1611.68,2933.76 1646.87,2933.76 1654.07,2940.95 1704.49,2940.95 1711.68,2933.76 1746.87,2933.76 1754.07,2940.95 1787.61,2940.95 Jtop3.A20@1825.96,2979.3 ; Jtop3.A20@1807.79,2979.3 Jtop3.A20@1825.96,2979.3 ; Jtop3.A20@1828.72,2982.06 1826.09,2979.43 Jtop3.A20@1825.96,2979.3 ; Jtop4.A20@2607.79,2973.76 2566.59,2932.55 1894.82,2932.55 1848.07,2979.3 1829.28,2979.3 Jtop3.A20@1825.96,2979.3 ; Jtop4.A20@2629.28,2976.24 2629.94,2975.57 R2R_IDL_17_12_TerA9.2@3295.96,2975.57 3295.96,3002 3295.08,3002.88 R1R_IDL_17_12_TerA9.1@3295.08,3030.59
JT10: AS.1 Jtop1.A18 Jtop2.A18 Jtop3.A18 Jtop4.A18 R1R_IDL_17_12_TerA10.1 R2R_IDL_17_12_TerA10.2 | length 3321.3
  Top Signal w8: Jtop1.A18@228.79,2782.06 231.95,2778.91 274.99,2735.87 835.78,2735.87 836.67,2736.76 899.7,2736.76 900.59,2735.87 935.78,2735.87 936.67,2736.76 982.99,2736.76 1021.39,2775.15 1028.72,2782.48 1077.45,2733.76 1646.87,2733.76 1652.99,2739.87 1705.57,2739.87 1711.68,2733.76 1746.87,2733.76 1752.99,2739.87 1786.53,2739.87 1826.09,2779.43 Jtop3.A18@1826.9,2780.24 ; Jtop3.A18@1805.37,2780.24 Jtop3.A18@1826.9,2780.24 ; Jtop3.A18@1828.72,2782.06 Jtop3.A18@1826.9,2780.24 ; Jtop4.A18@2605.37,2774.7 2564.43,2733.76 2511.68,2733.76 2510,2735.44 2448.56,2735.44 2446.87,2733.76 1892.14,2733.76 1845.65,2780.24 1829.28,2780.24 Jtop3.A18@1826.9,2780.24 ; Jtop4.A18@2629.28,2776.24 2629.94,2775.57 R2R_IDL_17_12_TerA10.2@3295.96,2775.57 3295.96,2802 3295.08,2802.88 R1R_IDL_17_12_TerA10.1@3295.08,2830.59 3295.08,2875.85 AS.1@3272.63,2898.29
JT11: DTACK.1 Jtop1.A16 Jtop2.A16 Jtop3.A16 Jtop4.A16 R1R_IDL_17_12_TerA11.1 R2R_IDL_17_12_TerA11.2 | length 3326.8
  Top Signal w8: Jtop1.A16@228.79,2582.06 229.28,2582.06 242.31,2582.06 288.51,2535.87 835.78,2535.87 835.94,2536.02 900.44,2536.02 900.59,2535.87 982.1,2535.87 1021.39,2575.15 1028.72,2582.48 1069,2582.48 1108.96,2542.52 1602.92,2542.52 1611.68,2533.76 1646.87,2533.76 1655.64,2542.52 1702.92,2542.52 1711.68,2533.76 1746.87,2533.76 1754.83,2541.71 1771.16,2541.71 1805.69,2576.24 Jtop3.A16@1829.28,2576.24 2367.9,2576.24 2412.85,2531.29 2584.33,2531.29 Jtop4.A16@2629.28,2576.24 2633.62,2580.57 R2R_IDL_17_12_TerA11.2@3295.96,2580.57 3295.08,2581.45 R1R_IDL_17_12_TerA11.1@3295.08,2635.59 3252.21,2635.59 DTACK.1@3224.81,2663
JT12: Jtop1.A14 Jtop2.A14 Jtop3.A14 Jtop4.A14 R1R_IDL_17_12_TerA12.1 R2R_IDL_17_12_TerA12.2 WRITE.1 | length 3330.4
  Top Signal w8: Jtop1.A14@228.79,2382.06 229.28,2382.06 239.95,2382.06 286.15,2335.87 835.78,2335.87 839.92,2340 896.46,2340 900.59,2335.87 935.78,2335.87 939.92,2340 986.24,2340 1021.39,2375.15 1028.72,2382.48 1069,2382.48 1120.52,2330.97 1657.83,2330.97 1666.44,2339.58 1705.86,2339.58 1711.68,2333.76 1746.87,2333.76 1752.7,2339.58 1786.24,2339.58 1826.09,2379.43 Jtop3.A14@1828.72,2382.06 ; Jtop3.A14@1818.29,2385.05 1829.28,2385.05 1858.56,2385.05 1904.03,2339.58 2405.86,2339.58 2411.68,2333.76 2446.87,2333.76 2449.84,2336.72 2508.72,2336.72 2511.68,2333.76 2567,2333.76 2574.31,2341.07 2579.84,2341.07 Jtop4.A14@2618.29,2379.51 ; Jtop4.A14@2629.28,2376.24 2633.47,2380.43 3168.64,2380.43 3185.57,2397.36 R2R_IDL_17_12_TerA12.2@3295.59,2397.36 3294.71,2398.23 R1R_IDL_17_12_TerA12.1@3294.71,2452.38 3227.83,2452.38 WRITE.1@3226.9,2453.31
JT13: Jtop1.A13 Jtop2.A13 Jtop3.A13 Jtop4.A13 R1R_IDL_17_12_TerA13.1 R2R_IDL_17_12_TerA13.2 | length 3239.3
  Top Signal w8: Jtop1.A13@228.79,2282.06 231.95,2278.91 270.85,2240 796.46,2240 800.59,2235.87 835.78,2235.87 839.92,2240 896.46,2240 900.59,2235.87 935.78,2235.87 939.92,2240 986.24,2240 1021.39,2275.15 1028.72,2282.48 1038.36,2282.48 1091.54,2229.3 1646.32,2229.3 1650.77,2233.76 1780.41,2233.76 Jtop3.A13@1826.09,2279.43 ; Jtop3.A13@1829.28,2276.24 1872.53,2232.99 2581.09,2232.99 Jtop4.A13@2623,2274.9 ; Jtop4.A13@2629.28,2276.24 2645.4,2292.36 R2R_IDL_17_12_TerA13.2@3295.59,2292.36 3294.71,2293.23 R1R_IDL_17_12_TerA13.1@3294.71,2347.38
JT14: Jtop1.A12 Jtop2.A12 Jtop3.A12 Jtop4.A12 R1R_IDL_17_12_TerA14.1 R2R_IDL_17_12_TerA14.2 | length 3250.3
  Top Signal w8: Jtop1.A12@228.79,2182.06 231.95,2178.91 270.85,2140 796.46,2140 800.59,2135.87 835.78,2135.87 839.92,2140 896.46,2140 900.59,2135.87 935.78,2135.87 939.92,2140 986.24,2140 1021.39,2175.15 1028.72,2182.48 1077.45,2133.76 1646.87,2133.76 1653.34,2140.22 1705.22,2140.22 1711.68,2133.76 1746.87,2133.76 1753.34,2140.22 1779.44,2140.22 1815.46,2176.24 Jtop3.A12@1829.28,2176.24 1871.76,2133.76 2446.87,2133.76 2449.86,2136.74 2508.7,2136.74 2511.68,2133.76 2578.6,2133.76 Jtop4.A12@2623,2178.16 ; Jtop3.A12@1823,2183.7 Jtop3.A12@1829.28,2183.7 ; Jtop4.A12@2629.28,2176.24 2640.4,2187.36 R2R_IDL_17_12_TerA14.2@3295.59,2187.36 3295.59,2214 3294.71,2214.88 R1R_IDL_17_12_TerA14.1@3294.71,2242.38
JT15: Jtop1.A10 Jtop2.A10 Jtop3.A10 Jtop4.A10 R1R_IDL_17_12_TerA15.1 R2R_IDL_17_12_TerA15.2 SYSCLK.1 | length 3316.1
  Top Signal w8: Jtop1.A10@228.79,1982.06 231.95,1978.91 280.9,1929.96 976.19,1929.96 1021.39,1975.15 1028.72,1982.48 1069,1982.48 1111.9,1939.58 1605.86,1939.58 1611.68,1933.76 1787.73,1933.76 1829.74,1975.77 1832.38,1978.41 1878.1,1932.69 2583.61,1932.69 Jtop4.A10@2623.79,1972.87 ; Jtop4.A10@2629.28,1976.24 2638.1,1967.42 R2R_IDL_17_12_TerA15.2@3301.59,1967.42 3301.59,1994 3300.72,1994.88 R1R_IDL_17_12_TerA15.1@3300.72,2022.44 3241.91,2022.44 SYSCLK.1@3232.47,2013.01
JT16: Jtop1.A8 Jtop2.A8 Jtop3.A8 Jtop4.A8 R1R_IDL_17_12_TerA16.1 R2R_IDL_17_12_TerA16.2 | length 3408.7
  Top Signal w8: Jtop1.A8@228.79,1782.06 231.95,1778.91 274.99,1735.87 900.53,1735.87 ; 900.56,1735.9 901.63,1734.83 934.75,1734.83 ; 935.78,1735.87 978.27,1778.35 Jtop2.A8@1018.19,1778.35 ; Jtop2.A8@1018.19,1782.48 1069,1782.48 1117.73,1733.76 1646.87,1733.76 1652.68,1739.56 1705.88,1739.56 1711.68,1733.76 1786.77,1733.76 Jtop3.A8@1829.28,1776.24 ; Jtop3.A8@1823,1776.26 1829.28,1776.26 1874.62,1730.93 2504.09,1730.93 2505.88,1732.72 2552.67,1732.72 2554.46,1730.93 2583.21,1730.93 Jtop4.A8@2623,1770.72 ; Jtop3.A8@1826.09,1779.43 Jtop3.A8@1828.72,1782.06 ; Jtop4.A8@2629.28,1776.24 2651.1,1798.05 R2R_IDL_17_12_TerA16.2@3453.86,1798.05 3452.99,1798.93 R1R_IDL_17_12_TerA16.1@3452.99,1853.07
JT17: Jtop1.A7 Jtop2.A7 Jtop3.A7 Jtop4.A7 R1R_IDL_17_12_TerA17.1 R2R_IDL_17_12_TerA17.2 | length 3425
  Top Signal w8: Jtop1.A7@228.79,1682.06 231.95,1678.91 274.99,1635.87 835.78,1635.87 839.23,1639.31 897.15,1639.31 900.59,1635.87 935.78,1635.87 939.92,1640 986.24,1640 1021.39,1675.15 1028.72,1682.48 1069,1682.48 1117.73,1633.76 1646.87,1633.76 1652.68,1639.56 1705.88,1639.56 1711.68,1633.76 1746.87,1633.76 1752.68,1639.56 1786.21,1639.56 1826.09,1679.43 Jtop3.A7@1828.72,1682.06 ; Jtop3.A7@1811.99,1682.66 1829.28,1682.66 1852.27,1682.66 1916.34,1618.59 2411.56,1618.59 2411.68,1618.72 2446.87,1618.72 2447,1618.59 2511.56,1618.59 2511.68,1618.72 2546.87,1618.72 2547,1618.59 2553.46,1618.59 Jtop4.A7@2611.99,1677.12 ; Jtop4.A7@2629.28,1676.24 2648.1,1695.05 R2R_IDL_17_12_TerA17.2@3453.86,1695.05 3453.86,1722.01 3452.99,1722.88 R1R_IDL_17_12_TerA17.1@3452.99,1750.07
JT18: Jtop1.A6 Jtop2.A6 Jtop3.A6 Jtop4.A6 R1R_IDL_17_12_TerA18.1 R2R_IDL_17_12_TerA18.2 | length 3392.3
  Top Signal w8: Jtop1.A6@228.79,1582.06 229.28,1582.06 241.05,1582.06 287.24,1535.87 835.78,1535.87 836.53,1536.61 899.85,1536.61 900.59,1535.87 982.1,1535.87 1021.39,1575.15 1028.72,1582.48 1069,1582.48 1117.73,1533.76 1646.87,1533.76 1649.36,1536.24 1709.2,1536.24 1711.68,1533.76 1764.22,1533.76 1806.7,1576.24 Jtop3.A6@1829.28,1576.24 ; Jtop3.A6@1828.72,1574.12 1871.2,1531.64 2586.06,1531.64 Jtop4.A6@2623,1568.58 ; Jtop4.A6@2629.28,1576.24 2643.1,1590.05 R2R_IDL_17_12_TerA18.2@3453.86,1590.05 3453.86,1617.01 3452.99,1617.88 R1R_IDL_17_12_TerA18.1@3452.99,1645.07
JT19: Jtop1.A5 Jtop2.A5 Jtop3.A5 Jtop4.A5 R1R_IDL_17_12_TerA19.1 R2R_IDL_17_12_TerA19.2 | length 3404.6
  Top Signal w8: Jtop1.A5@228.79,1482.06 229.28,1482.06 236.94,1482.06 283.13,1435.87 835.78,1435.87 839.92,1440 896.46,1440 900.59,1435.87 935.78,1435.87 939.92,1440 986.24,1440 1021.39,1475.15 1028.72,1482.48 1069,1482.48 1117.73,1433.76 1646.87,1433.76 1647.9,1434.78 1710.66,1434.78 1711.68,1433.76 1780.41,1433.76 Jtop3.A5@1824.03,1477.37 ; Jtop3.A5@1815.14,1477.37 Jtop3.A5@1824.03,1477.37 ; Jtop3.A5@1828.72,1482.06 1826.09,1479.43 Jtop3.A5@1824.03,1477.37 ; Jtop4.A5@2615.14,1471.83 2573.96,1430.66 2554.73,1430.66 2552.67,1432.72 2465.96,1432.72 2463.9,1430.66 1902.13,1430.66 1855.42,1477.37 1829.28,1477.37 Jtop3.A5@1824.03,1477.37 ; Jtop4.A5@2629.28,1476.24 2638.1,1485.05 R2R_IDL_17_12_TerA19.2@3453.86,1485.05 3453.86,1512.01 3452.99,1512.88 R1R_IDL_17_12_TerA19.1@3452.99,1540.07
JT20: Jtop1.A4 Jtop2.A4 Jtop3.A4 Jtop4.A4 R1R_IDL_17_12_TerA20.1 R2R_IDL_17_12_TerA20.2 | length 3398.5
  Top Signal w8: Jtop1.A4@228.79,1382.06 229.28,1382.06 238.26,1382.06 284.45,1335.87 835.78,1335.87 839.92,1340 896.46,1340 900.59,1335.87 935.78,1335.87 939.92,1340 986.24,1340 1021.39,1375.15 1028.72,1382.48 1077.45,1333.76 1646.87,1333.76 1648.66,1335.54 1709.9,1335.54 1711.68,1333.76 1780.41,1333.76 Jtop3.A4@1817.06,1370.4 ; Jtop3.A4@1814.35,1370.4 Jtop3.A4@1817.06,1370.4 ; Jtop3.A4@1828.72,1382.06 1826.09,1379.43 Jtop3.A4@1817.06,1370.4 ; Jtop4.A4@2614.35,1364.86 2583.01,1333.52 1891.52,1333.52 1854.63,1370.4 1829.28,1370.4 Jtop3.A4@1817.06,1370.4 ; Jtop4.A4@2629.28,1376.24 2639.43,1386.39 3447.53,1386.39 R2R_IDL_17_12_TerA20.2@3453.86,1380.05 3453.86,1434.2 R1R_IDL_17_12_TerA20.1@3452.99,1435.07
JT21: Jtop1.A3 Jtop2.A3 Jtop3.A3 Jtop4.A3 R1R_IDL_17_12_TerA21.1 R2R_IDL_17_12_TerA21.2 | length 3415
  Top Signal w8: Jtop1.A3@228.79,1282.06 229.28,1282.06 269.07,1282.06 321.24,1229.89 856.33,1229.89 865.4,1238.96 897.5,1238.96 900.59,1235.87 935.78,1235.87 938.88,1238.96 985.2,1238.96 1021.39,1275.15 1028.72,1282.48 1069,1282.48 1117.73,1233.76 1646.87,1233.76 1654.16,1241.04 1704.4,1241.04 1711.68,1233.76 1746.87,1233.76 1752.7,1239.58 1786.24,1239.58 1826.09,1279.43 Jtop3.A3@1828.72,1282.06 ; Jtop3.A3@1816.71,1283.88 1829.28,1283.88 1856.99,1283.88 1902.33,1238.54 2392.04,1238.54 2400.72,1229.86 2568.23,1229.86 Jtop4.A3@2616.71,1278.34 ; Jtop4.A3@2629.28,1276.24 2630.46,1275.05 R2R_IDL_17_12_TerA21.2@3453.86,1275.05 3453.86,1302.01 3452.99,1302.88 R1R_IDL_17_12_TerA21.1@3452.99,1330.07
JT22: Jtop1.A2 Jtop2.A2 Jtop3.A2 Jtop4.A2 R1R_IDL_17_12_TerA22.1 R2R_IDL_17_12_TerA22.2 | length 3432.8
  Top Signal w8: Jtop1.A2@228.79,1182.06 229.28,1182.06 243.29,1182.06 289.49,1135.87 835.78,1135.87 836.21,1136.29 900.16,1136.29 900.59,1135.87 982.1,1135.87 1021.39,1175.15 1028.72,1182.48 1077.69,1133.52 1780.18,1133.52 1826.09,1179.43 Jtop3.A2@1828.72,1182.06 ; Jtop3.A2@1810.42,1184.78 1829.28,1184.78 1850.7,1184.78 1896.93,1138.54 2392.04,1138.54 2396.83,1133.76 2586.8,1133.76 Jtop4.A2@2629.28,1176.24 3447.68,1176.24 R2R_IDL_17_12_TerA22.2@3453.86,1170.05 3453.86,1197.01 3452.99,1197.88 R1R_IDL_17_12_TerA22.1@3452.99,1225.07
  Bot Signal w8: Jtop4.A2@2615.69,1176.24 Jtop4.A2@2629.28,1176.24
JT23: Jtop1.A1 Jtop2.A1 Jtop3.A1 Jtop4.A1 R1R_IDL_17_12_TerA23.1 R2R_IDL_17_12_TerA23.2 | length 3403.3
  Top Signal w8: Jtop1.A1@228.79,1082.06 229.21,1082.48 232.37,1079.33 279.33,1032.36 938.68,1032.36 988.8,1082.48 1018.19,1082.48 1028.72,1082.48 1082.18,1029.03 1775.69,1029.03 Jtop3.A1@1826.09,1079.43 ; Jtop3.A1@1829.28,1076.24 1892.21,1013.3 2587.64,1013.3 Jtop4.A1@2624.58,1050.24 ; Jtop4.A1@2629.28,1076.24 2640.46,1065.05 R2R_IDL_17_12_TerA23.2@3453.86,1065.05 3453.86,1092.01 3452.99,1092.88 R1R_IDL_17_12_TerA23.1@3452.99,1120.07
JT24: Jtop1.B30 Jtop2.B30 Jtop3.B30 Jtop4.B30 R1R_IDL_17_12_TerA24.1 R2R_IDL_17_12_TerA24.2 | length 4044.2
  Top Signal w8: Jtop4.B30@2529.28,3976.24 2540.26,3976.24 2582.8,4018.78 2753.15,4018.78 2935.96,4201.58 3759.55,4201.58 3816.96,4144.18 R1R_IDL_17_12_TerA24.1@3877.63,4144.18 3877.63,4116.46 3878.51,4115.58 R2R_IDL_17_12_TerA24.2@3878.51,4089.16
  Bot Signal w8: Jtop1.B30@128.79,3982.06 129.28,3982.06 168.72,3982.06 211.2,4024.54 810.71,4024.54 811.13,4024.96 846.32,4024.96 846.74,4024.54 886.66,4024.54 925.52,3985.68 928.72,3982.48 967.98,4021.74 1630.11,4021.74 ; 1630.53,4022.16 1665.73,4022.16 1666.15,4021.74 1706.07,4021.74 Jtop3.B30@1737.24,3990.58 ; Jtop3.B30@1728.72,3982.06 Jtop3.B30@1737.24,3990.58 ; Jtop3.B30@1748.13,3979.68 1740.43,3987.39 Jtop3.B30@1737.24,3990.58 ; Jtop4.B30@2528.72,3982.06 2488.8,3982.06 2446.32,4024.54 1771.2,4024.54 Jtop3.B30@1737.24,3990.58
JT25: Jtop1.B29 Jtop2.B29 Jtop3.B29 Jtop4.B29 R1R_IDL_17_12_TerA25.1 R2R_IDL_17_12_TerA25.2 | length 3982.6
  Top Signal w8: Jtop4.B29@2529.28,3876.24 2569.2,3876.24 2611.68,3918.72 2933.05,3918.72 2971.92,3957.59 3428.17,3957.59 3429.34,3958.77 3445.18,3958.77 3525.59,4039.18 R1R_IDL_17_12_TerA25.1@3877.63,4039.18 3877.63,3985.03 R2R_IDL_17_12_TerA25.2@3878.51,3984.16
  Bot Signal w8: Jtop1.B29@128.79,3882.06 129.28,3882.06 168.72,3882.06 211.2,3924.54 810.71,3924.54 811.13,3924.96 846.32,3924.96 846.74,3924.54 886.66,3924.54 925.52,3885.68 928.72,3882.48 967.98,3921.74 1630.11,3921.74 ; 1630.53,3922.16 1706.07,3922.16 ; 1706.07,3921.74 Jtop3.B29@1738.43,3889.39 ; Jtop3.B29@1728.72,3882.06 1729.28,3882.06 1731.1,3882.06 Jtop3.B29@1738.43,3889.39 ; Jtop4.B29@2528.72,3882.06 2483.94,3926.85 1775.88,3926.85 Jtop3.B29@1738.43,3889.39
JT26: Jtop1.B28 Jtop2.B28 Jtop3.B28 Jtop4.B28 R1R_IDL_17_12_TerA26.1 R2R_IDL_17_12_TerA26.2 | length 3994
  Top Signal w8: v1(2821.85,3736.63) 2932.47,3736.63 3267,3740 3410,3740 3428.61,3758.61 3455.6,3758.61 3536.58,3839.58 3692.55,3839.58 3732.13,3879.16 R2R_IDL_17_12_TerA26.2@3878.51,3879.16 3878.51,3905.58 3877.63,3906.46 R1R_IDL_17_12_TerA26.1@3877.63,3934.18
  Bot Signal w8: Jtop1.B28@128.79,3782.06 129.28,3782.06 168.72,3782.06 211.2,3824.54 810.71,3824.54 811.13,3824.96 846.32,3824.96 846.74,3824.54 886.66,3824.54 925.52,3785.68 928.72,3782.48 967.98,3821.74 1630.11,3821.74 ; 1630.53,3822.16 1665.73,3822.16 1666.15,3821.74 1706.07,3821.74 Jtop3.B28@1735.2,3792.61 ; Jtop3.B28@1728.72,3782.06 1728.72,3786.13 Jtop3.B28@1735.2,3792.61 ; Jtop4.B28@2528.72,3782.06 2479.54,3831.24 1773.84,3831.24 Jtop3.B28@1735.2,3792.61 ; Jtop4.B28@2529.28,3776.24 2571.76,3733.76 2818.98,3733.76 v1(2821.85,3736.63)
JT27: Jtop1.B27 Jtop2.B27 Jtop3.B27 Jtop4.B27 R1R_IDL_17_12_TerA27.1 R2R_IDL_17_12_TerA27.2 | length 3999.3
  Top Signal w8: v1(3833.34,3840.58) 3843.15,3840.58 3854.55,3829.18 R1R_IDL_17_12_TerA27.1@3877.63,3829.18 3877.63,3801.46 3878.51,3800.58 R2R_IDL_17_12_TerA27.2@3878.51,3774.16
  Bot Signal w8: Jtop1.B27@128.79,3682.06 129.28,3682.06 168.72,3682.06 211.2,3724.54 810.71,3724.54 811.13,3724.96 846.32,3724.96 846.74,3724.54 886.66,3724.54 925.52,3685.68 928.72,3682.48 967.98,3721.74 1630.11,3721.74 ; 1630.53,3722.16 1665.73,3722.16 1666.15,3721.74 1706.07,3721.74 Jtop3.B27@1739.5,3688.32 ; Jtop3.B27@1728.72,3682.06 1729.28,3682.06 1733.24,3682.06 Jtop3.B27@1739.5,3688.32 ; Jtop4.B27@2528.72,3682.06 2478.57,3732.22 1783.4,3732.22 Jtop3.B27@1739.5,3688.32 ; Jtop4.B27@2529.28,3676.24 2572.8,3719.76 2806.49,3719.76 2812.41,3713.83 3356.83,3713.83 3402,3759 3422.97,3759 3423.36,3758.61 3455.6,3758.61 3537.58,3840.58 v1(3833.34,3840.58)
JT28: Jtop1.B26 Jtop2.B26 Jtop3.B26 Jtop4.B26 R1R_IDL_17_12_TerA28.1 R2R_IDL_17_12_TerA28.2 | length 3989.6
  Top Signal w8: v1(3582.33,3643.4) 3687.84,3643.4 3768.62,3724.18 R1R_IDL_17_12_TerA28.1@3877.63,3724.18 3878.51,3723.3 R2R_IDL_17_12_TerA28.2@3878.51,3669.16
  Bot Signal w8: Jtop1.B26@128.79,3582.06 129.28,3582.06 168.72,3582.06 211.2,3624.54 810.71,3624.54 811.13,3624.96 846.32,3624.96 846.74,3624.54 886.66,3624.54 925.52,3585.68 928.72,3582.48 967.98,3621.74 1630.11,3621.74 ; 1630.53,3622.16 1665.73,3622.16 1666.15,3621.74 1706.07,3621.74 Jtop3.B26@1739.69,3588.12 ; Jtop3.B26@1728.72,3582.06 1729.28,3582.06 1733.63,3582.06 Jtop3.B26@1739.69,3588.12 ; Jtop4.B26@2528.72,3582.06 2485.1,3625.69 1777.25,3625.69 Jtop3.B26@1739.69,3588.12 ; Jtop4.B26@2529.28,3576.24 2571.76,3618.72 2646.88,3618.72 2661.63,3603.97 2882.53,3603.97 2921.97,3643.4 v1(3582.33,3643.4)
JT29: Jtop1.B25 Jtop2.B25 Jtop3.B25 Jtop4.B25 R1R_IDL_17_12_TerA29.1 R2R_IDL_17_12_TerA29.2 | length 4019.6
  Top Signal w8: Jtop4.B25@2529.28,3476.24 2536.79,3483.75 2576.71,3483.75 2611.68,3518.72 2646.88,3518.72 2681.85,3483.75 2897.63,3483.75 2946.66,3532.78 3351.76,3532.78 3356.57,3537.59 3444.19,3537.59 3525.77,3619.18 R1R_IDL_17_12_TerA29.1@3877.63,3619.18 3877.63,3591.46 3878.51,3590.58 R2R_IDL_17_12_TerA29.2@3878.51,3564.16
  Bot Signal w8: Jtop1.B25@128.79,3482.06 129.28,3482.06 168.72,3482.06 211.62,3524.96 846.32,3524.96 847.16,3524.12 887.09,3524.12 925.52,3485.68 928.72,3482.48 968.4,3522.16 1665.73,3522.16 1666.57,3521.32 1706.49,3521.32 Jtop3.B25@1737.24,3490.58 ; Jtop3.B25@1728.72,3482.06 Jtop3.B25@1737.24,3490.58 ; Jtop3.B25@1748.13,3479.68 1740.43,3487.39 Jtop3.B25@1737.24,3490.58 ; Jtop4.B25@2528.72,3482.06 2481.69,3529.09 1775.75,3529.09 Jtop3.B25@1737.24,3490.58
JT30: Jtop1.B24 Jtop2.B24 Jtop3.B24 Jtop4.B24 R1R_IDL_17_12_TerA30.1 R2R_IDL_17_12_TerA30.2 | length 3992.8
  Top Signal w8: v1(3615.41,3507.41) 3810.3,3507.41 3858.55,3459.16 R2R_IDL_17_12_TerA30.2@3878.51,3459.16 3878.51,3485.58 3877.63,3486.46 R1R_IDL_17_12_TerA30.1@3877.63,3514.18
  Bot Signal w8: Jtop1.B24@128.79,3382.06 177.8,3431.07 874.76,3431.07 922.84,3383 923.35,3382.48 Jtop2.B24@928.72,3382.48 ; Jtop2.B24@948.2,3379.26 997.21,3428.28 1694.17,3428.28 1737.74,3384.7 1742.76,3379.68 Jtop3.B24@1748.13,3379.68 ; Jtop3.B24@1756.8,3388.51 1805.81,3437.52 1807.92,3437.52 1811.68,3433.76 1846.88,3433.76 1858.28,3422.35 2498.83,3422.35 2537.11,3384.07 Jtop4.B24@2544.49,3376.69 ; Jtop4.B24@2529.28,3376.24 2556.3,3376.24 2613.82,3433.76 2646.88,3433.76 2669.96,3456.84 3447.74,3456.84 3498.31,3507.41 v1(3615.41,3507.41)
JT31: Jtop1.B22 Jtop2.B22 Jtop3.B22 Jtop4.B22 R1R_IDL_17_12_TerA31.1 R2R_IDL_17_12_TerA31.2 | length 4003.3
  Top Signal w8: Jtop4.B22@2529.28,3176.24 2569.2,3176.24 2611.68,3218.72 3282.52,3218.72 3283.46,3217.78 3308.45,3217.78 3309.39,3218.72 3325.83,3218.72 3326.77,3217.78 3351.76,3217.78 3352.7,3218.72 3458.6,3218.72 3594.04,3354.16 R2R_IDL_17_12_TerA31.2@3878.51,3354.16 3878.51,3380.58 3877.63,3381.46 R1R_IDL_17_12_TerA31.1@3877.63,3409.18
  Bot Signal w8: Jtop1.B22@129.28,3176.24 129.28,3185.24 166.25,3222.2 874.33,3222.2 Jtop2.B22@918.19,3178.35 966.64,3226.8 1678.72,3226.8 Jtop3.B22@1729.28,3176.24 1754.32,3176.24 1802.58,3224.5 2481.02,3224.5 Jtop4.B22@2529.28,3176.24
JT32: Jtop1.B21 Jtop2.B21 Jtop3.B21 Jtop4.B21 R1R_IDL_17_12_TerA32.1 R2R_IDL_17_12_TerA32.2 | length 3998.3
  Top Signal w8: Jtop4.B21@2529.28,3076.24 2569.2,3076.24 2611.68,3118.72 2650.47,3118.72 2735.53,3203.78 3463.46,3203.78 3505.84,3246.16 R2R_IDL_17_12_TerA32.2@3878.51,3246.16 3877.63,3247.03 R1R_IDL_17_12_TerA32.1@3877.63,3301.18
  Bot Signal w8: Jtop1.B21@128.79,3082.06 129.28,3082.06 168.72,3082.06 211.2,3124.54 810.71,3124.54 811.13,3124.96 886.24,3124.96 925.52,3085.68 928.72,3082.48 967.98,3121.74 1630.11,3121.74 ; 1630.53,3122.16 1705.65,3122.16 1740.43,3087.39 Jtop3.B21@1745.75,3082.06 ; Jtop3.B21@1728.72,3082.06 1729.28,3082.06 Jtop3.B21@1745.75,3082.06 ; Jtop3.B21@1748.13,3079.68 Jtop3.B21@1745.75,3082.06 ; Jtop4.B21@2528.72,3082.06 2524.48,3082.06 2482,3124.54 1811.13,3124.54 1768.65,3082.06 Jtop3.B21@1745.75,3082.06
JT33: Jtop1.B19 Jtop2.B19 Jtop3.B19 Jtop4.B19 R1R_IDL_17_12_TerA33.1 R2R_IDL_17_12_TerA33.2 | length 4003.7
  Top Signal w8: v1(3707.32,3026.18) R1R_IDL_17_12_TerA33.1@3877.63,3026.18 3877.63,2972.03 R2R_IDL_17_12_TerA33.2@3878.51,2971.16
  Bot Signal w8: Jtop1.B19@128.79,2882.06 129.28,2882.06 168.72,2882.06 211.2,2924.54 810.71,2924.54 811.13,2924.96 846.32,2924.96 888.8,2882.48 918.19,2882.48 928.72,2882.48 967.98,2921.74 1630.11,2921.74 ; 1630.53,2922.16 1665.73,2922.16 1708.21,2879.68 1729.28,2879.68 Jtop3.B19@1748.13,2879.68 ; Jtop3.B19@1728.72,2882.06 1770.04,2923.38 2431.11,2923.38 2432.87,2921.62 2484.12,2921.62 2516.81,2888.93 2529.28,2888.93 Jtop4.B19@2541.98,2888.93 ; Jtop4.B19@2529.28,2876.24 Jtop4.B19@2541.98,2888.93 ; v1(3707.32,3026.18) 3324.18,3026.18 3210.65,2912.65 2652.94,2912.65 2646.88,2918.72 2571.76,2918.72 Jtop4.B19@2541.98,2888.93
JT34: Jtop1.B18 Jtop2.B18 Jtop3.B18 Jtop4.B18 R1R_IDL_17_12_TerA34.1 R2R_IDL_17_12_TerA34.2 | length 3997.6
  Top Signal w8: v1(3503.02,2866.16) R2R_IDL_17_12_TerA34.2@3878.51,2866.16 3878.51,2892.58 3877.63,2893.46 R1R_IDL_17_12_TerA34.1@3877.63,2921.18
  Bot Signal w8: Jtop1.B18@128.79,2782.06 129.28,2782.06 168.72,2782.06 211.2,2824.54 810.71,2824.54 811.13,2824.96 846.32,2824.96 846.74,2824.54 886.66,2824.54 925.52,2785.68 928.72,2782.48 967.98,2821.74 1630.11,2821.74 ; 1630.53,2822.16 1665.73,2822.16 ; 1666.15,2821.74 1706.07,2821.74 Jtop3.B18@1737.24,2790.58 ; Jtop3.B18@1728.72,2782.06 Jtop3.B18@1737.24,2790.58 ; 2438.72,2830.99 1777.65,2830.99 Jtop3.B18@1737.24,2790.58 ; 2439.14,2831.41 2474.33,2831.41 ; 2474.75,2830.99 2529.39,2776.35 Jtop4.B18@2529.51,2776.24 ; Jtop4.B18@2529.28,2776.24 Jtop4.B18@2529.51,2776.24 ; v1(3503.02,2866.16) 3496.37,2872.81 3403.81,2872.81 3264.75,2733.75 2684.91,2733.75 2599.97,2733.76 2557.49,2776.24 Jtop4.B18@2529.51,2776.24
JT35: Jtop1.B17 Jtop2.B17 Jtop3.B17 Jtop4.B17 R1R_IDL_17_12_TerA35.1 R2R_IDL_17_12_TerA35.2 | length 4001.9
  Top Signal w8: Jtop4.B17@2517.2,2689.59 2515.93,2689.59 Jtop4.B17@2529.28,2676.24 2571.76,2718.72 2646.88,2718.72 2680.94,2752.78 3870.13,2752.78 R2R_IDL_17_12_TerA35.2@3878.51,2761.16 3878.51,2815.3 R1R_IDL_17_12_TerA35.1@3877.63,2816.18
  Bot Signal w8: Jtop1.B17@128.79,2682.06 129.28,2682.06 168.72,2682.06 211.2,2724.54 810.71,2724.54 811.13,2724.96 846.32,2724.96 888.8,2682.48 918.19,2682.48 928.72,2682.48 967.98,2721.74 1630.11,2721.74 ; 1630.53,2722.16 1665.73,2722.16 1708.21,2679.68 1729.28,2679.68 Jtop3.B17@1748.13,2679.68 ; Jtop3.B17@1728.72,2682.06 1777.65,2730.99 2438.72,2730.99 ; 2439.14,2731.41 2474.33,2731.41 2529.39,2676.35 Jtop4.B17@2536.77,2668.97
JT36: Jtop1.B16 Jtop2.B16 Jtop3.B16 Jtop4.B16 R1R_IDL_17_12_TerA36.1 R2R_IDL_17_12_TerA36.2 | length 3958.2
  Top Signal w8: v1(3739.84,2658.39) 3873.89,2658.39 3875.08,2659.58 R2R_IDL_17_12_TerA36.2@3878.51,2656.16 3878.51,2710.3 R1R_IDL_17_12_TerA36.1@3877.63,2711.18
  Bot Signal w8: Jtop1.B16@128.79,2582.06 171.69,2624.96 846.32,2624.96 888.8,2582.48 918.19,2582.48 Jtop2.B16@928.72,2582.48 ; Jtop2.B16@948.2,2579.26 991.1,2622.16 1665.73,2622.16 1708.21,2579.68 1729.28,2579.68 Jtop3.B16@1748.13,2579.68 ; Jtop3.B16@1756.8,2588.51 1799.7,2631.41 2474.33,2631.41 Jtop4.B16@2516.81,2588.93 ; Jtop4.B16@2529.28,2576.24 2572.28,2533.24 2652.53,2533.24 2725.05,2605.75 3359.37,2605.75 3431.42,2677.81 3676.16,2677.81 3695.58,2658.39 v1(3739.84,2658.39)
JT37: Jtop1.B15 Jtop2.B15 Jtop3.B15 Jtop4.B15 R1R_IDL_17_12_TerA37.1 R2R_IDL_17_12_TerA37.2 | length 3946.6
  Top Signal w8: Jtop4.B15@2529.28,2476.24 2568.97,2515.93 2588.77,2515.93 2601.35,2528.5 2769.42,2528.5 v1(2797.19,2556.27) ; v1(3833.55,2550.58) 3878.51,2550.58 R2R_IDL_17_12_TerA37.2@3878.51,2551.16 3878.51,2577.58 3877.63,2578.46 R1R_IDL_17_12_TerA37.1@3877.63,2606.18
  Bot Signal w8: Jtop1.B15@128.79,2482.06 171.69,2524.96 846.32,2524.96 888.8,2482.48 918.19,2482.48 Jtop2.B15@928.72,2482.48 ; Jtop2.B15@948.2,2479.26 991.1,2522.16 1665.73,2522.16 1708.21,2479.68 1729.28,2479.68 Jtop3.B15@1748.13,2479.68 ; Jtop3.B15@1756.8,2488.51 1790.01,2521.72 2452.74,2521.72 2498.23,2476.24 Jtop4.B15@2529.28,2476.24 ; v1(2797.19,2556.27) 2851.27,2556.27 2886.75,2591.75 3430.18,2591.75 3430.38,2591.56 3449.26,2591.56 3449.46,2591.75 3795.08,2591.75 3802.13,2584.7 v1@3831.25,2548.72
JT38: Jtop1.B14 Jtop2.B14 Jtop3.B14 Jtop4.B14 R1R_IDL_17_12_TerA38.1 R2R_IDL_17_12_TerA38.2 | length 3966.1
  Top Signal w8: Jtop4.B14@2529.28,2376.24 2569.88,2416.83 2609.8,2416.83 2611.68,2418.72 2646.88,2418.72 2648.76,2416.83 2873.56,2416.83 2945.6,2488.87 3404.64,2488.87 3416.95,2501.18 R1R_IDL_17_12_TerA38.1@3877.63,2501.18 3877.63,2473.46 3878.51,2472.58 R2R_IDL_17_12_TerA38.2@3878.51,2446.16
  Bot Signal w8: Jtop1.B14@128.79,2382.06 171.69,2424.96 846.32,2424.96 888.8,2382.48 918.19,2382.48 Jtop2.B14@928.72,2382.48 ; Jtop2.B14@948.2,2379.26 991.1,2422.16 1665.73,2422.16 1708.21,2379.68 1729.28,2379.68 Jtop3.B14@1748.13,2379.68 ; Jtop3.B14@1756.8,2388.51 1799.7,2431.41 2474.33,2431.41 2516.81,2388.93 2529.28,2388.93 2541.98,2388.93 Jtop4.B14@2529.28,2376.24
JT39: Jtop1.B13 Jtop2.B13 Jtop3.B13 Jtop4.B13 R1R_IDL_17_12_TerA39.1 R2R_IDL_17_12_TerA39.2 | length 3982.2
  Top Signal w8: Jtop4.B13@2529.28,2276.24 2571.76,2318.72 2646.87,2318.72 2652.59,2313 3082.72,2313 v1(3096.78,2327.07) ; v1(3778.96,2396.18) R1R_IDL_17_12_TerA39.1@3877.63,2396.18 3877.63,2368.46 3878.51,2367.58 R2R_IDL_17_12_TerA39.2@3878.51,2341.16
  Bot Signal w8: Jtop1.B13@129.28,2276.24 174.04,2321 867.56,2321 910.21,2278.35 Jtop2.B13@918.19,2278.35 960.67,2320.83 1684.69,2320.83 Jtop3.B13@1729.28,2276.24 1784.08,2331.03 2471.19,2331.03 2520.2,2282.02 2520.2,2276.24 Jtop4.B13@2529.28,2276.24 ; v1(3096.78,2327.07) 3429.3,2327.07 3432.87,2323.49 3706.28,2323.49 v1(3778.96,2396.18)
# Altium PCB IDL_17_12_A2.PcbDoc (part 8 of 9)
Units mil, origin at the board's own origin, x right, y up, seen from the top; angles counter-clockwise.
Board outline 5119.97 x 10350 mil, 6 copper layers (Top Signal, 3.3 Volt, GND, 5 Volt, Split Plane, Bot Signal), stack 66.2 mil thick; 514 components, 178 nets, 2321 pads, 427 vias.

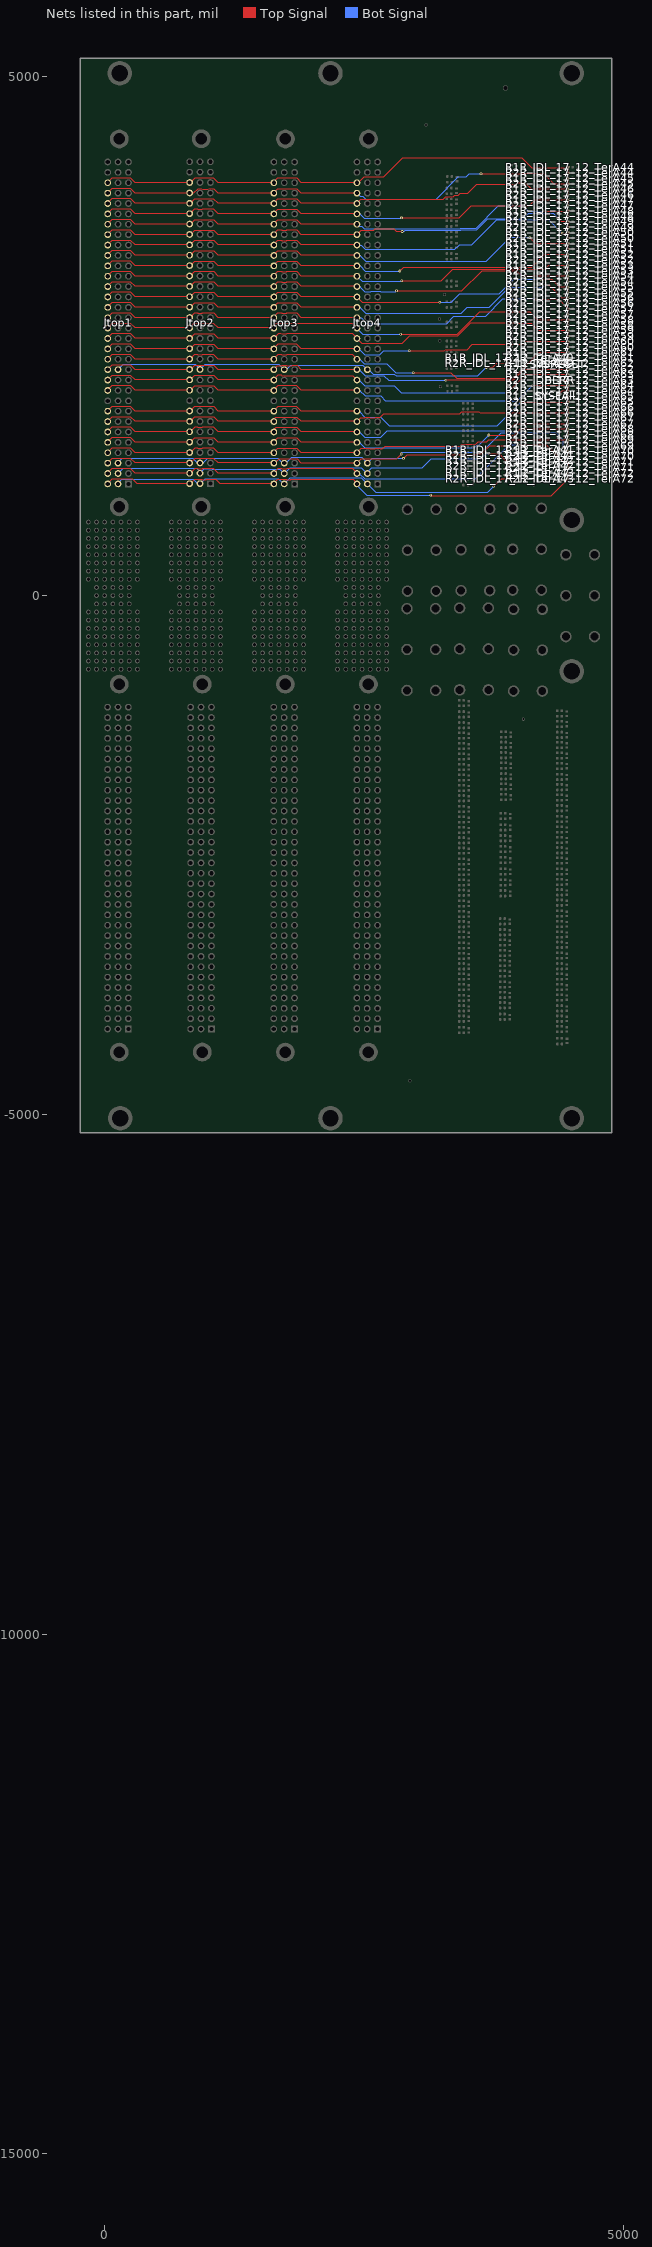
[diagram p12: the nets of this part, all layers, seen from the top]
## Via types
v1: diameter 25.59, hole 11.81, Top Signal to Bot Signal, 427 vias

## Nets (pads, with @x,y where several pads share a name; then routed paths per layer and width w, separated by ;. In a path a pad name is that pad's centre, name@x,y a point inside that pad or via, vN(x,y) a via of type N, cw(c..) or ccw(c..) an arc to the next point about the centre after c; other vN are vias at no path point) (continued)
JT40: Jtop1.B12 Jtop2.B12 Jtop3.B12 Jtop4.B12 R1R_IDL_17_12_TerA40.1 R2R_IDL_17_12_TerA40.2 | length 3998.7
  Top Signal w8: v1(3674.02,2197.72) 3734.91,2197.72 3773.35,2236.16 3877.63,2235.5 3877.64,2236.17 3878.51,2290.3 R1R_IDL_17_12_TerA40.1@3877.63,2291.18
  Bot Signal w8: Jtop1.B12@129.28,2176.24 179.58,2226.54 870,2226.54 Jtop2.B12@918.19,2178.35 968.48,2228.64 1676.88,2228.64 Jtop3.B12@1729.28,2176.24 1747.1,2176.24 1790.82,2219.95 2485.56,2219.95 Jtop4.B12@2529.28,2176.24 2543.7,2176.24 2586.18,2133.76 2646.88,2133.76 2647.05,2133.93 2790.44,2133.93 2808.23,2116.14 3592.44,2116.14 v1(3674.02,2197.72)
JT41: Jtop1.B3 Jtop2.B3 Jtop3.B3 Jtop4.B3 R1R_IDL_17_12_TerA41.1 R2R_IDL_17_12_TerA41.2 | length 3977.4
  Top Signal w8: v1(2877.79,1321.99) 2878.37,1321.99 2913.76,1357.38 3441.24,1357.38 3441.37,1357.26 3466.36,1357.26 3466.48,1357.38 3484.55,1357.38 3484.68,1357.26 3509.66,1357.26 3509.79,1357.38 3576.45,1357.38 3583.99,1364.91 3631.59,1364.91 3710.2,1443.53 3874.06,1443.53 3883.53,1434.06 R1R_IDL_17_12_TerA41.1@3883.53,1405.65 3883.53,1377.93 3884.41,1377.06 R2R_IDL_17_12_TerA41.2@3884.41,1350.63
  Bot Signal w8: Jtop1.B3@128.79,1282.06 171.69,1324.96 846.32,1324.96 888.8,1282.48 918.19,1282.48 Jtop2.B3@928.72,1282.48 ; Jtop2.B3@948.2,1279.26 991.1,1322.16 1665.73,1322.16 1708.21,1279.68 1729.28,1279.68 Jtop3.B3@1748.13,1279.68 ; Jtop3.B3@1756.8,1288.51 1799.7,1331.41 2474.33,1331.41 Jtop4.B3@2516.81,1288.93 ; Jtop4.B3@2529.28,1276.24 2575.04,1321.99 v1(2877.79,1321.99)
JT42: Jtop1.B2 Jtop2.B2 Jtop3.B2 Jtop4.B2 R1R_IDL_17_12_TerA42.1 R2R_IDL_17_12_TerA42.2 | length 4054.9
  Top Signal w8: v1(3704.35,1364.94) 3800.58,1364.94 3859.86,1305.65 R1R_IDL_17_12_TerA42.1@3883.53,1305.65 3883.53,1277.93 3884.41,1277.06 R2R_IDL_17_12_TerA42.2@3884.41,1250.63
  Bot Signal w8: Jtop1.B2@129.28,1176.24 180.84,1227.8 884.6,1227.8 918.19,1194.21 Jtop2.B2@918.19,1178.35 960.67,1220.83 1035.79,1220.83 1037.15,1219.46 1686.05,1219.46 Jtop3.B2@1729.28,1176.24 1786.8,1233.76 2471.76,1233.76 Jtop4.B2@2529.28,1176.24 2529.28,1189.3 2573.5,1233.52 3060.52,1233.52 3143,1316 3625.65,1316 3674.59,1364.94 v1(3704.35,1364.94)
JT43: Jtop1.B1 Jtop2.B1 Jtop3.B1 Jtop4.B1 R1R_IDL_17_12_TerA43.1 R2R_IDL_17_12_TerA43.2 | length 4030.7
  Top Signal w8: v1(3747.41,1052.91) 3822.16,1127.66 R2R_IDL_17_12_TerA43.2@3884.34,1127.66 3884.34,1154.09 3883.46,1154.96 R1R_IDL_17_12_TerA43.1@3883.46,1182.68
  Bot Signal w8: Jtop1.B1@129.28,1076.24 129.28,1084.4 165.71,1120.83 852.17,1120.83 894.66,1078.35 Jtop2.B1@918.19,1078.35 967.64,1127.79 1673.8,1127.79 1725.36,1076.24 Jtop3.B1@1729.28,1076.24 1788.36,1135.32 1810.12,1135.32 1811.68,1133.76 2471.76,1133.76 Jtop4.B1@2529.28,1076.24 2610.16,995.35 3488.31,995.35 3488.72,994.94 3507.6,994.94 3508.01,995.35 3688.63,995.35 3746.19,1052.91 v1(3747.41,1052.91)
JT44: Jtop1.C30 Jtop2.C30 Jtop3.C30 Jtop4.C30 R1R_IDL_17_12_TerA44.1 R2R_IDL_17_12_TerA44.2 | length 4733.4
  Top Signal w8: Jtop1.C30@28.79,3982.06 71.27,4024.54 246.39,4024.54 288.87,3982.06 818.19,3982.06 828.3,3982.06 872.24,4026 1044.44,4026 1070.78,3999.66 ; 1071.2,3999.24 1088.38,3982.06 1628.72,3982.06 1668.82,4022.16 1848.7,4022.16 1888.8,3982.06 Jtop4.C30@2428.72,3982.06 ; Jtop4.C30@2429.28,3976.24 2442.1,3976.24 2498.64,4032.78 2689.9,4032.78 2872.71,4215.58 4017.02,4215.58 4111.36,4121.25 R1R_IDL_17_12_TerA44.1@4462.91,4121.25 ; R2R_IDL_17_12_TerA44.2@4463.78,4071.82 4463.78,4126.84 R1R_IDL_17_12_TerA44.1@4463.78,4129.25
JT45: Jtop1.C29 Jtop2.C29 Jtop3.C29 Jtop4.C29 R1R_IDL_17_12_TerA45.1 R2R_IDL_17_12_TerA45.2 | length 4765.8
  Top Signal w8: Jtop1.C29@28.79,3882.06 71.27,3924.54 246.39,3924.54 288.87,3882.06 Jtop2.C29@818.19,3882.06 ; Jtop2.C29@818.19,3878.35 858.11,3878.35 900.59,3920.83 935.78,3920.83 943.82,3912.79 992.55,3912.79 1000.59,3920.83 1035.78,3920.83 1036.32,3920.3 1050.99,3920.3 1071.2,3900.08 1071.2,3899.24 1088.38,3882.06 1628.72,3882.06 1665.71,3919.05 1851.81,3919.05 1888.8,3882.06 Jtop4.C29@2428.72,3882.06 ; v1(3623.7,4062.02) v1(3623.7,4062.02) 4001.38,4061.97 4007.8,4068.39 4223.69,4068.39 4325.26,3966.82 R2R_IDL_17_12_TerA45.2@4463.78,3966.82 4463.78,3993.25 4462.91,3994.12 R1R_IDL_17_12_TerA45.1@4462.91,4021.84
  Bot Signal w8: Jtop4.C29@2429.28,3876.24 2460.28,3845.24 2485.34,3845.24 2511.87,3818.72 3190.72,3818.72 3404.65,4032.65 3481.07,4032.65 3510.44,4062.02 v1(3623.7,4062.02)
JT46: Jtop1.C28 Jtop2.C28 Jtop3.C28 Jtop4.C28 R1R_IDL_17_12_TerA46.1 R2R_IDL_17_12_TerA46.2 | length 4697.2
  Top Signal w8: Jtop1.C28@28.79,3782.06 71.27,3824.54 246.39,3824.54 288.87,3782.06 818.19,3782.06 828.3,3782.06 869.72,3823.48 893.18,3823.48 894.79,3821.87 941.58,3821.87 943.2,3823.48 1046.96,3823.48 1088.38,3782.06 1628.72,3782.06 1666.46,3819.8 1705.84,3819.8 1705.88,3819.76 1752.67,3819.76 1752.72,3819.8 1851.06,3819.8 1888.8,3782.06 2428.72,3782.06 2466.07,3819.41 3258.61,3819.41 3282.59,3843.39 3356.28,3843.39 3370.41,3857.52 3404.28,3857.52 3422.15,3875.39 3497.75,3875.39 3584.21,3961.85 3865.53,3961.85 3866.02,3961.36 3958.1,3961.36 3967.84,3971.1 3986.84,3971.1 3992.13,3976.39 4046.21,3976.39 4105.77,3916.84 R1R_IDL_17_12_TerA46.1@4462.91,3916.84 4462.91,3889.12 4463.78,3888.25 R2R_IDL_17_12_TerA46.2@4463.78,3861.82
JT47: Jtop1.C27 Jtop2.C27 Jtop3.C27 Jtop4.C27 R1R_IDL_17_12_TerA47.1 R2R_IDL_17_12_TerA47.2 | length 4690.1
  Top Signal w8: Jtop1.C27@28.79,3682.06 71.27,3724.54 246.39,3724.54 288.87,3682.06 818.19,3682.06 828.3,3682.06 869.72,3723.48 893.18,3723.48 894.79,3721.87 941.58,3721.87 943.2,3723.48 1046.96,3723.48 1088.38,3682.06 1628.72,3682.06 1668.82,3722.16 1703.48,3722.16 1705.88,3719.76 1752.67,3719.76 1755.08,3722.16 1848.7,3722.16 1888.8,3682.06 Jtop4.C27@2428.72,3682.06 ; v1(2858.22,3637.78) 3416.88,3637.78 3531.95,3752.85 3864.53,3752.85 3866.02,3751.36 3934.59,3751.36 3935.8,3752.57 4086.79,3752.57 4148.06,3813.84 R1R_IDL_17_12_TerA47.1@4462.91,3813.84 4462.91,3786.12 4463.78,3785.25 R2R_IDL_17_12_TerA47.2@4463.78,3758.82
  Bot Signal w8: Jtop4.C27@2429.28,3676.24 2458.73,3676.24 2497.19,3637.78 ; 2496,3639 2501.24,3633.76 2854.2,3633.76 v1(2858.22,3637.78)
JT48: Jtop1.C26 Jtop2.C26 Jtop3.C26 Jtop4.C26 R1R_IDL_17_12_TerA48.1 R2R_IDL_17_12_TerA48.2 | length 4721.8
  Top Signal w8: Jtop1.C26@28.79,3582.06 71.27,3624.54 246.39,3624.54 288.87,3582.06 818.19,3582.06 828.3,3582.06 867.21,3620.97 1049.47,3620.97 1088.38,3582.06 1628.72,3582.06 1668.82,3622.16 1703.48,3622.16 1705.88,3619.76 1752.67,3619.76 1755.08,3622.16 1848.7,3622.16 1888.8,3582.06 Jtop4.C26@2428.72,3582.06 ; v1(4240.66,3703.89) R1R_IDL_17_12_TerA48.1@4462.91,3703.89 ; R1R_IDL_17_12_TerA48.1@4462.91,3710.25 R1R_IDL_17_12_TerA48.1@4462.91,3708.84 R1R_IDL_17_12_TerA48.1@4462.91,3703.89 ; R2R_IDL_17_12_TerA48.2@4463.78,3653.82 4462.91,3654.69 R1R_IDL_17_12_TerA48.1@4462.91,3703.89
  Bot Signal w8: Jtop4.C26@2429.28,3576.24 2449.99,3555.53 2475.06,3555.53 2497.38,3533.2 3425.61,3533.2 3429.33,3536.92 3575.98,3536.92 3791.62,3752.57 4030.35,3752.57 4079.03,3703.89 v1(4240.66,3703.89)
JT49: Jtop1.C25 Jtop2.C25 Jtop3.C25 Jtop4.C25 R1R_IDL_17_12_TerA49.1 R2R_IDL_17_12_TerA49.2 | length 4734
  Top Signal w8: Jtop1.C25@28.79,3482.06 71.27,3524.54 246.39,3524.54 288.87,3482.06 Jtop2.C25@818.19,3482.06 ; Jtop2.C25@818.19,3478.35 824.58,3478.35 867.06,3520.83 935.78,3520.83 936.52,3520.09 999.86,3520.09 1000.59,3520.83 1049.61,3520.83 1088.38,3482.06 1628.72,3482.06 1668.82,3522.16 1703.48,3522.16 1705.88,3519.76 1752.67,3519.76 1755.08,3522.16 1848.7,3522.16 1888.8,3482.06 Jtop4.C25@2428.72,3482.06 ; Jtop4.C25@2429.28,3476.24 2471.76,3518.72 2591.89,3518.72 2606.92,3533.76 2781.7,3533.76 2808,3507.46 v1(2865.92,3507.46) ; v1(4363.83,3637.25) 4397.24,3603.84 R1R_IDL_17_12_TerA49.1@4462.91,3603.84 4462.91,3576.12 4463.78,3575.25 R2R_IDL_17_12_TerA49.2@4463.78,3548.82
  Bot Signal w8: v1(2865.92,3507.46) 2882.67,3507.46 2893.93,3518.72 3430.92,3518.72 3435.13,3522.92 3581.77,3522.92 3690.65,3631.8 4032.86,3631.8 4082.16,3681.1 4315.8,3681.1 4317.89,3683.19 v1(4363.83,3637.25)
JT50: Jtop1.C24 Jtop2.C24 Jtop3.C24 Jtop4.C24 R1R_IDL_17_12_TerA50.1 R2R_IDL_17_12_TerA50.2 | length 4783.1
  Top Signal w8: Jtop1.C24@28.79,3382.06 71.27,3424.54 246.39,3424.54 288.87,3382.06 818.19,3382.06 828.3,3382.06 867.79,3421.55 1048.89,3421.55 1088.38,3382.06 1628.72,3382.06 1668.82,3422.16 1703.48,3422.16 1705.88,3419.76 1752.67,3419.76 1755.08,3422.16 1848.7,3422.16 1888.8,3382.06 Jtop4.C24@2428.72,3382.06 ; v1(4403.47,3491) 4455.07,3491 R1R_IDL_17_12_TerA50.1@4462.91,3498.84 4462.91,3471.12 4463.78,3470.25 R2R_IDL_17_12_TerA50.2@4463.78,3443.82
  Bot Signal w8: Jtop4.C24@2429.28,3376.24 2469.2,3376.24 2511.68,3333.76 3373.03,3333.76 3418.07,3378.8 3536.37,3378.8 3775.38,3617.8 4276.67,3617.8 v1(4403.47,3491)
JT51: Jtop1.C23 Jtop2.C23 Jtop3.C23 Jtop4.C23 R1R_IDL_17_12_TerA51.1 R2R_IDL_17_12_TerA51.2 | length 4736.6
  Top Signal w8: Jtop1.C23@28.79,3282.06 71.27,3324.54 246.39,3324.54 288.87,3282.06 818.19,3282.06 828.3,3282.06 867.79,3321.55 1048.89,3321.55 1088.38,3282.06 1628.72,3282.06 1669.1,3322.44 1703.2,3322.44 1705.88,3319.76 1752.67,3319.76 1755.36,3322.44 1848.42,3322.44 1888.8,3282.06 Jtop4.C23@2428.72,3282.06 ; v1(4092.22,3448.29) 4146.67,3393.84 R1R_IDL_17_12_TerA51.1@4462.91,3393.84 4462.91,3339.69 R2R_IDL_17_12_TerA51.2@4463.78,3338.82
  Bot Signal w8: Jtop4.C23@2429.28,3276.24 2457.88,3276.24 2515.4,3218.72 3672.69,3218.72 3905.36,3451.39 4089.11,3451.39 v1(4092.22,3448.29)
JT52: Jtop1.C22 Jtop2.C22 Jtop3.C22 Jtop4.C22 R1R_IDL_17_12_TerA52.1 R2R_IDL_17_12_TerA52.2 | length 4680.8
  Top Signal w8: Jtop1.C22@28.79,3182.06 71.27,3224.54 246.39,3224.54 288.87,3182.06 818.19,3182.06 828.3,3182.06 867.79,3221.55 1048.89,3221.55 1088.38,3182.06 1628.72,3182.06 1669.1,3222.44 1703.2,3222.44 1705.88,3219.76 1752.67,3219.76 1755.36,3222.44 1848.42,3222.44 1888.8,3182.06 Jtop4.C22@2428.72,3182.06 ; v1(2842.72,3126) 2881.26,3164.53 4112.52,3164.53 4236.82,3288.84 R1R_IDL_17_12_TerA52.1@4462.91,3288.84 4462.91,3270.51 4463.78,3269.63 R2R_IDL_17_12_TerA52.2@4463.78,3233.82
  Bot Signal w8: Jtop4.C22@2429.28,3176.24 2460.09,3176.24 2510.33,3126 v1(2842.72,3126)
JT53: Jtop1.C21 Jtop2.C21 Jtop3.C21 Jtop4.C21 R1R_IDL_17_12_TerA53.1 R2R_IDL_17_12_TerA53.2 | length 4679
  Top Signal w8: Jtop1.C21@28.79,3082.06 71.27,3124.54 246.39,3124.54 288.87,3082.06 818.19,3082.06 828.3,3082.06 868.47,3122.23 894.43,3122.23 894.79,3121.87 941.58,3121.87 941.95,3122.23 1048.21,3122.23 1088.38,3082.06 1628.72,3082.06 1669.1,3122.44 1703.2,3122.44 1705.88,3119.76 1752.67,3119.76 1755.36,3122.44 1848.42,3122.44 1888.8,3082.06 Jtop4.C21@2428.72,3082.06 ; v1(2861.02,3033) 3239,3033 3350.18,3144.18 4235.65,3144.18 4275.31,3183.84 R1R_IDL_17_12_TerA53.1@4462.91,3183.84 4462.91,3156.12 4463.78,3155.25 R2R_IDL_17_12_TerA53.2@4463.78,3128.82
  Bot Signal w8: Jtop4.C21@2429.28,3076.24 2478.82,3026.7 2854.72,3026.7 v1(2861.02,3033)
JT54: Jtop1.C20 Jtop2.C20 Jtop3.C20 Jtop4.C20 R1R_IDL_17_12_TerA54.1 R2R_IDL_17_12_TerA54.2 | length 4722.3
  Top Signal w8: Jtop1.C20@28.79,2982.06 71.27,3024.54 246.39,3024.54 288.87,2982.06 818.19,2982.06 828.3,2982.06 868.47,3022.23 894.43,3022.23 894.79,3021.87 941.58,3021.87 941.95,3022.23 1048.21,3022.23 1088.38,2982.06 1628.72,2982.06 1669.1,3022.44 1703.2,3022.44 1705.88,3019.76 1752.67,3019.76 1755.36,3022.44 1848.42,3022.44 1888.8,2982.06 Jtop4.C20@2428.72,2982.06 ; v1(2810.61,2935.44) 3441,2935.44 3635.73,3130.18 3964.83,3130.18 4016.17,3078.84 R1R_IDL_17_12_TerA54.1@4462.91,3078.84 4462.91,3024.69 R2R_IDL_17_12_TerA54.2@4463.78,3023.82
  Bot Signal w8: Jtop4.C20@2429.28,2976.24 2456.97,2976.24 2505.24,2927.97 2561.21,2927.97 2565.96,2932.72 2652.67,2932.72 2657.42,2927.97 2803.13,2927.97 v1(2810.61,2935.44)
JT55: Jtop1.C19 Jtop2.C19 Jtop3.C19 Jtop4.C19 R1R_IDL_17_12_TerA55.1 R2R_IDL_17_12_TerA55.2 | length 4737.5
  Top Signal w8: Jtop1.C19@28.79,2882.06 71.27,2924.54 246.39,2924.54 288.87,2882.06 818.19,2882.06 828.3,2882.06 868.47,2922.23 894.43,2922.23 894.79,2921.87 941.58,2921.87 941.95,2922.23 1048.21,2922.23 1088.38,2882.06 1628.72,2882.06 1669.1,2922.44 1703.2,2922.44 1705.88,2919.76 1752.67,2919.76 1755.36,2922.44 1848.42,2922.44 1888.8,2882.06 Jtop4.C19@2428.72,2882.06 ; Jtop4.C19@2429.28,2876.24 2479.52,2826 2883.28,2826 v1(3226.49,2826.02) ; v1(4203.6,3044.61) 4204.23,3045.25 4306.83,3045.25 4378.24,2973.84 R1R_IDL_17_12_TerA55.1@4462.91,2973.84 ; R1R_IDL_17_12_TerA55.1@4462.91,2975.25 R1R_IDL_17_12_TerA55.1@4462.91,2973.84 ; R2R_IDL_17_12_TerA55.2@4463.78,2918.82 4462.91,2919.69 R1R_IDL_17_12_TerA55.1@4462.91,2973.84
  Bot Signal w8: v1(3226.49,2826.02) 3335.98,2826.02 3418,2908 3801.69,2908 3940.07,3046.38 4201.83,3046.38 v1(4203.6,3044.61)
JT56: Jtop1.C18 Jtop2.C18 Jtop3.C18 Jtop4.C18 R1R_IDL_17_12_TerA56.1 R2R_IDL_17_12_TerA56.2 | length 4775.8
  Top Signal w8: Jtop1.C18@28.79,2782.06 71.27,2824.54 246.39,2824.54 288.87,2782.06 818.19,2782.06 828.3,2782.06 868.47,2822.23 1048.21,2822.23 1088.38,2782.06 1628.72,2782.06 1669.1,2822.44 1848.42,2822.44 1888.8,2782.06 Jtop4.C18@2428.72,2782.06 ; v1(4238.04,2989.25) 4282.83,2989.25 4403.24,2868.84 R1R_IDL_17_12_TerA56.1@4462.91,2868.84 4462.91,2841.12 4463.78,2840.25 R2R_IDL_17_12_TerA56.2@4463.78,2813.82
  Bot Signal w8: Jtop4.C18@2429.28,2776.24 2457.93,2776.24 2514.41,2719.76 2679.11,2719.76 3270.55,2719.75 3433.77,2719.76 3491.01,2777 3702.73,2777 3894.14,2968.4 4217.2,2968.4 v1(4238.04,2989.25)
JT57: Jtop1.C17 Jtop2.C17 Jtop3.C17 Jtop4.C17 R1R_IDL_17_12_TerA57.1 R2R_IDL_17_12_TerA57.2 | length 4756.7
  Top Signal w8: Jtop1.C17@28.79,2682.06 71.27,2724.54 246.39,2724.54 288.87,2682.06 818.19,2682.06 828.3,2682.06 868.47,2722.23 894.43,2722.23 894.79,2721.87 941.58,2721.87 941.95,2722.23 1048.21,2722.23 1088.38,2682.06 1628.72,2682.06 1669.1,2722.44 1703.2,2722.44 1705.88,2719.76 1752.67,2719.76 1755.36,2722.44 1848.42,2722.44 1888.8,2682.06 Jtop4.C17@2428.72,2682.06 ; v1(4154.78,2855.25) 4374.83,2855.25 4462.91,2767.17 R1R_IDL_17_12_TerA57.1@4462.91,2763.84 4462.91,2736.12 4463.78,2735.25 R2R_IDL_17_12_TerA57.2@4463.78,2708.82
  Bot Signal w8: Jtop4.C17@2429.28,2676.24 2469.2,2676.24 2525.69,2619.75 3291.94,2619.75 3364,2691.81 3667.78,2691.81 3834.36,2858.39 4151.63,2858.39 v1(4154.78,2855.25)
JT58: Jtop1.C16 Jtop2.C16 Jtop3.C16 Jtop4.C16 R1R_IDL_17_12_TerA58.1 R2R_IDL_17_12_TerA58.2 | length 4746.3
  Top Signal w8: Jtop1.C16@28.79,2582.06 71.27,2624.54 246.39,2624.54 288.45,2582.48 818.19,2582.48 828.72,2582.48 828.72,2593.58 860.1,2624.96 1046.32,2624.96 1088.8,2582.48 1609.02,2582.48 1616.02,2589.49 1651.08,2624.54 2386.24,2624.54 Jtop4.C16@2428.72,2582.06 ; v1(2849.73,2516.87) 3393.05,2516.87 3609.64,2733.47 3864.64,2733.47 3865.14,2733.97 4091.64,2733.97 4166.77,2658.84 R1R_IDL_17_12_TerA58.1@4462.91,2658.84 4462.91,2604.69 R2R_IDL_17_12_TerA58.2@4463.78,2603.82
  Bot Signal w8: Jtop4.C16@2429.28,2576.24 2486.8,2518.72 2519.77,2518.72 2847.89,2518.72 v1(2849.73,2516.87)
JT59: Jtop1.C15 Jtop2.C15 Jtop3.C15 Jtop4.C15 R1R_IDL_17_12_TerA59.1 R2R_IDL_17_12_TerA59.2 | length 4734.4
  Top Signal w8: Jtop1.C15@28.79,2482.06 71.27,2524.54 246.39,2524.54 288.45,2482.48 818.19,2482.48 828.72,2482.48 867.7,2521.47 1049.82,2521.47 1088.8,2482.48 1628.3,2482.48 1628.72,2482.06 1674.37,2527.71 1697.93,2527.71 1705.88,2519.76 1752.67,2519.76 1760.63,2527.71 2383.07,2527.71 Jtop4.C15@2428.72,2482.06 ; Jtop4.C15@2429.28,2476.24 2474.68,2430.83 2604,2430.83 2605.89,2432.72 2652.67,2432.72 2654.56,2430.83 2867.76,2430.83 2939.8,2502.87 3398.84,2502.87 3524.94,2628.97 3933.43,2628.97 3939.84,2622.57 4028.82,2622.57 4028.87,2622.62 4107.01,2622.62 4175.79,2553.84 R1R_IDL_17_12_TerA59.1@4462.91,2553.84 4462.91,2526.12 4463.78,2525.25 R2R_IDL_17_12_TerA59.2@4463.78,2498.82
JT60: Jtop1.C14 Jtop2.C14 Jtop3.C14 Jtop4.C14 R1R_IDL_17_12_TerA60.1 R2R_IDL_17_12_TerA60.2 | length 4670.8
  Top Signal w8: Jtop1.C14@28.79,2382.06 71.27,2424.54 246.39,2424.54 288.45,2382.48 818.19,2382.48 828.72,2382.48 868.24,2422.01 1049.27,2422.01 1088.8,2382.48 1628.3,2382.48 1628.72,2382.06 1672.68,2426.03 1704.88,2426.03 1705.33,2425.58 1752.12,2425.58 1752.56,2426.03 1844.84,2426.03 1888.8,2382.06 Jtop4.C14@2428.72,2382.06 ; v1(2933.55,2357.64) 2935.21,2359.3 3271.34,2359.3 3282.22,2370.17 3492.35,2370.17 3541.47,2419.3 4011.5,2419.3 4011.82,2419.62 4030.7,2419.62 4059.92,2448.84 R1R_IDL_17_12_TerA60.1@4462.91,2448.84 4462.91,2421.12 4463.78,2420.25 R2R_IDL_17_12_TerA60.2@4463.78,2393.82
  Bot Signal w8: Jtop4.C14@2429.28,2376.24 2447.11,2376.24 2503.89,2319.45 2647.19,2319.45 2685.37,2357.64 v1(2933.55,2357.64)
JT61: Jtop1.C13 Jtop2.C13 Jtop3.C13 Jtop4.C13 R1R_IDL_17_12_TerA61.1 R2R_IDL_17_12_TerA61.2 | length 4780.6
  Top Signal w8: Jtop1.C13@28.79,2282.06 71.27,2324.54 246.39,2324.54 288.45,2282.48 818.19,2282.48 828.72,2282.48 869.51,2323.27 893.39,2323.27 894.79,2321.87 941.58,2321.87 942.99,2323.27 1048.01,2323.27 1088.8,2282.48 1628.3,2282.48 1628.72,2282.06 1672.24,2325.58 1700.06,2325.58 1705.88,2319.76 1752.67,2319.76 1758.5,2325.58 2385.2,2325.58 Jtop4.C13@2428.72,2282.06 ; v1(2971.25,2146.24) 3334.6,2146.24 3388.88,2091.96 3932.52,2091.96 4184.39,2343.84 R1R_IDL_17_12_TerA61.1@4462.91,2343.84 4463.78,2342.96 R2R_IDL_17_12_TerA61.2@4463.78,2288.82
  Bot Signal w8: Jtop4.C13@2429.28,2276.24 2456.04,2276.24 2498.53,2233.74 2715.25,2233.74 2802.75,2146.24 v1(2971.25,2146.24)
JT62: Jtop1.C12 Jtop2.C12 Jtop3.C12 Jtop4.C12 R1R_IDL_17_12_TerA62.1 R2R_IDL_17_12_TerA62.2 SYSRESET.1 | length 4773.2
  Top Signal w8: Jtop1.C12@28.79,2182.06 71.27,2224.54 246.39,2224.54 288.45,2182.48 818.19,2182.48 828.72,2182.48 867.31,2221.07 1050.21,2221.07 1088.8,2182.48 1628.3,2182.48 1628.72,2182.06 1660.8,2214.14 1693.88,2214.14 1694.11,2213.91 1706.88,2213.91 1711.68,2218.72 1746.87,2218.72 1751.68,2213.91 1806.88,2213.91 1811.68,2218.72 1852.14,2218.72 1888.8,2182.06 Jtop4.C12@2428.72,2182.06 ; v1(3285.69,2074.83) 3288.83,2077.96 3938.31,2077.96 4041.17,2180.82 R2R_IDL_17_12_TerA62.2@4462.91,2180.82 ; SYSRESET.1@4369.31,2230.12 4375.04,2235.84 R1R_IDL_17_12_TerA62.1@4462.91,2235.84 R2R_IDL_17_12_TerA62.2@4462.91,2180.82 ; R2R_IDL_17_12_TerA62.2@4463.78,2180.82 R2R_IDL_17_12_TerA62.2@4462.91,2180.82
  Bot Signal w8: Jtop4.C12@2429.28,2176.24 2453.93,2176.24 2510.41,2119.76 2652.67,2119.76 2652.85,2119.93 2688.98,2119.93 2734.08,2074.83 v1(3285.69,2074.83)
JT63: BERR.1 Jtop1.C11 Jtop2.C11 Jtop3.C11 Jtop4.C11 R1R_IDL_17_12_TerA63.1 R2R_IDL_17_12_TerA63.2 | length 4797.1
  Top Signal w8: Jtop1.C11@28.79,2082.06 71.27,2124.54 246.39,2124.54 288.45,2082.48 818.19,2082.48 828.72,2082.48 869.23,2122.99 893.67,2122.99 894.79,2121.87 941.58,2121.87 942.7,2122.99 1048.29,2122.99 1088.8,2082.48 1628.3,2082.48 1628.72,2082.06 1672.88,2126.22 1699.42,2126.22 1705.88,2119.76 2391.03,2119.76 Jtop4.C11@2428.72,2082.06 ; v1(3883.01,1956.52) 4057.34,2130.84 R1R_IDL_17_12_TerA63.1@4462.91,2130.84 4463.78,2129.96 R2R_IDL_17_12_TerA63.2@4463.78,2075.82 4387,2075.82 BERR.1@4386.58,2076.24
  Bot Signal w8: Jtop4.C11@2429.28,2076.24 2449.3,2076.24 2505.12,2020.42 2789.76,2020.42 2856.97,1953.2 3879.7,1953.2 v1(3883.01,1956.52)
JT64: Jtop1.C10 Jtop2.C10 Jtop3.C10 Jtop4.C10 R1R_IDL_17_12_TerA64.1 R2R_IDL_17_12_TerA64.2 SYSFAIL.1 | length 4820.6
  Top Signal w8: Jtop1.C10@28.79,1982.06 71.27,2024.54 246.39,2024.54 288.45,1982.48 818.19,1982.48 828.72,1982.48 869.23,2022.99 1048.29,2022.99 1088.8,1982.48 1628.3,1982.48 1628.72,1982.06 1672.52,2025.86 1705.05,2025.86 1705.33,2025.58 1752.12,2025.58 1752.4,2025.86 1845,2025.86 1888.8,1982.06 Jtop4.C10@2428.72,1982.06 ; v1(4117.41,2022.76) 4118.89,2024.25 R1R_IDL_17_12_TerA64.1@4462.91,2024.25 ; SYSFAIL.1@4359.11,1923.62 4406.31,1970.82 R2R_IDL_17_12_TerA64.2@4463.78,1970.82 4462.91,1998.12 R1R_IDL_17_12_TerA64.1@4462.91,2024.25 ; R1R_IDL_17_12_TerA64.1@4462.91,2025.84 R1R_IDL_17_12_TerA64.1@4462.91,2024.25
  Bot Signal w8: Jtop4.C10@2429.28,1976.24 2453.93,1976.24 2507.09,1923.07 2656.26,1923.07 2702.89,1876.45 3971.1,1876.45 v1(4117.41,2022.76)
JT65: Jtop1.C8 Jtop2.C8 Jtop3.C8 Jtop4.C8 R1R_IDL_17_12_TerA65.1 R2R_IDL_17_12_TerA65.2 | length 4750.7
  Top Signal w8: Jtop1.C8@28.79,1782.06 71.27,1824.54 246.39,1824.54 288.45,1782.48 818.19,1782.48 828.72,1782.48 869.23,1822.99 1048.29,1822.99 1088.8,1782.48 1628.3,1782.48 1628.72,1782.06 1672.52,1825.86 1705.05,1825.86 1705.33,1825.58 1752.12,1825.58 1752.4,1825.86 1845,1825.86 1888.8,1782.06 Jtop4.C8@2428.72,1782.06 ; v1(4008.63,1862.04) 4454.84,1862.04 4457.42,1859.45 R2R_IDL_17_12_TerA65.2@4463.78,1865.82 4462.91,1866.69 R1R_IDL_17_12_TerA65.1@4462.91,1920.84
  Bot Signal w8: Jtop4.C8@2429.28,1776.24 2449.77,1776.24 2506.67,1719.34 2658.17,1719.34 2741.7,1635.8 3782.4,1635.8 v1(4008.63,1862.04)
JT66: Jtop1.C7 Jtop2.C7 Jtop3.C7 Jtop4.C7 R1R_IDL_17_12_TerA66.1 R2R_IDL_17_12_TerA66.2 | length 4642.6
  Top Signal w8: Jtop1.C7@28.79,1682.06 71.27,1724.54 246.39,1724.54 288.45,1682.48 818.19,1682.48 828.72,1682.48 867.06,1720.83 940.54,1720.83 941.62,1721.9 1049.38,1721.9 1088.8,1682.48 1609.02,1682.48 1616.02,1689.49 1645.37,1718.84 1852.02,1718.84 1888.8,1682.06 Jtop4.C7@2428.72,1682.06 ; Jtop4.C7@2429.28,1676.24 2464.08,1711.03 2504,1711.03 2511.68,1718.72 2546.87,1718.72 2554.56,1711.03 2604,1711.03 2611.68,1718.72 2646.87,1718.72 2650.99,1714.6 2688.89,1752.5 3420.12,1752.5 3440.49,1772.87 3602.4,1772.87 3614.45,1760.82 R2R_IDL_17_12_TerA66.2@4463.78,1760.82 4462.91,1761.69 R1R_IDL_17_12_TerA66.1@4462.91,1815.84
JT67: Jtop1.C6 Jtop2.C6 Jtop3.C6 Jtop4.C6 R1R_IDL_17_12_TerA67.1 R2R_IDL_17_12_TerA67.2 | length 4672.1
  Top Signal w8: Jtop1.C6@28.79,1582.06 71.27,1624.54 246.39,1624.54 288.45,1582.48 818.19,1582.48 828.72,1582.48 871.55,1625.31 891.35,1625.31 894.79,1621.87 941.58,1621.87 945.03,1625.31 1045.97,1625.31 1088.8,1582.48 1615.4,1582.48 1619.22,1586.3 1653.69,1620.77 1704.87,1620.77 1705.88,1619.76 1752.67,1619.76 1753.69,1620.77 1850.09,1620.77 1888.8,1582.06 Jtop4.C6@2428.72,1582.06 ; v1(3881.01,1589.41) 3947.41,1655.82 R2R_IDL_17_12_TerA67.2@4463.78,1655.82 4463.78,1682.25 4462.91,1683.12 R1R_IDL_17_12_TerA67.1@4462.91,1710.84
  Bot Signal w8: Jtop4.C6@2429.28,1576.24 2453.41,1576.24 2505.56,1524.08 2656.4,1524.08 2721.73,1589.41 v1(3881.01,1589.41)
JT68: Jtop1.C5 Jtop2.C5 Jtop3.C5 Jtop4.C5 R1R_IDL_17_12_TerA68.1 R2R_IDL_17_12_TerA68.2 | length 4684.9
  Top Signal w8: Jtop1.C5@28.79,1482.06 71.27,1524.54 246.39,1524.54 288.45,1482.48 818.19,1482.48 828.72,1482.48 868.05,1521.81 1049.47,1521.81 1088.8,1482.48 1628.3,1482.48 1628.72,1482.06 1665.77,1519.11 1851.75,1519.11 1888.8,1482.06 Jtop4.C5@2428.72,1482.06 ; v1(3699.8,1546.72) 3942.67,1546.72 4001.79,1605.84 R1R_IDL_17_12_TerA68.1@4462.91,1605.84 4462.91,1578.12 4463.78,1577.25 R2R_IDL_17_12_TerA68.2@4463.78,1550.82
  Bot Signal w8: Jtop4.C5@2429.28,1476.24 2450.23,1476.24 2503.15,1423.32 3560.84,1423.32 3589.33,1451.8 3604.89,1451.8 v1(3699.8,1546.72)
JT69: Jtop1.C4 Jtop2.C4 Jtop3.C4 Jtop4.C4 R1R_IDL_17_12_TerA69.1 R2R_IDL_17_12_TerA69.2 | length 4653.9
  Top Signal w8: Jtop1.C4@28.79,1382.06 71.27,1424.54 246.39,1424.54 288.45,1382.48 818.19,1382.48 828.72,1382.48 871.2,1424.96 891.7,1424.96 894.79,1421.87 941.58,1421.87 944.68,1424.96 1046.32,1424.96 1088.8,1382.48 1628.3,1382.48 1628.72,1382.06 1665.84,1419.18 1851.68,1419.18 1888.8,1382.06 Jtop4.C4@2428.72,1382.06 ; Jtop4.C4@2429.28,1376.24 2471.76,1418.72 2546.87,1418.72 2552.69,1412.9 2605.87,1412.9 2611.68,1418.72 2646.87,1418.72 2652.69,1412.9 2674.79,1412.9 2702.6,1440.71 3423.33,1440.71 3440.49,1457.87 3575.59,1457.87 3599.94,1482.21 3681.56,1482.21 3700.18,1500.84 R1R_IDL_17_12_TerA69.1@4462.91,1500.84 4463.78,1499.96 R2R_IDL_17_12_TerA69.2@4463.78,1445.82
JT70: Jtop1.C3 Jtop2.C3 Jtop3.C3 Jtop4.C3 R1R_IDL_17_12_TerA70.1 R2R_IDL_17_12_TerA70.2 | length 4829.7
  Top Signal w8: Jtop1.C3@28.79,1282.06 71.27,1324.54 246.39,1324.54 288.45,1282.48 818.19,1282.48 828.72,1282.48 871.2,1324.96 891.7,1324.96 894.79,1321.87 941.58,1321.87 944.68,1324.96 1046.32,1324.96 1088.8,1282.48 1628.3,1282.48 1628.72,1282.06 1629.28,1282.06 1643.2,1282.06 1679.85,1318.72 1746.87,1318.72 1748.59,1317.01 1809.97,1317.01 1811.68,1318.72 1852.14,1318.72 1888.8,1282.06 Jtop4.C3@2428.72,1282.06 ; Jtop4.C3@2429.28,1276.24 2471.76,1318.72 2811.12,1318.72 v1(2856,1363.59) ; v1(4414.24,1426.43) 4444.83,1395.84 R1R_IDL_17_12_TerA70.1@4462.91,1395.84 4462.91,1368.12 4463.78,1367.25 R2R_IDL_17_12_TerA70.2@4463.78,1340.82
  Bot Signal w8: v1(2856,1363.59) 2856,1368 2866.91,1378.91 3630.84,1378.91 3818.54,1566.62 4346.46,1566.62 4414.24,1498.84 v1(4414.24,1426.43)
JT71: Jtop1.C2 Jtop2.C2 Jtop3.C2 Jtop4.C2 R1R_IDL_17_12_TerA71.1 R2R_IDL_17_12_TerA71.2 | length 4824.7
  Top Signal w8: Jtop1.C2@28.79,1182.06 71.27,1224.54 246.39,1224.54 288.45,1182.48 818.19,1182.48 828.72,1182.48 871.2,1224.96 891.7,1224.96 894.79,1221.87 941.58,1221.87 944.68,1224.96 1046.32,1224.96 1088.8,1182.48 1628.3,1182.48 1628.72,1182.06 1671.2,1224.54 1701.1,1224.54 1705.88,1219.76 1752.67,1219.76 1757.46,1224.54 2386.24,1224.54 Jtop4.C2@2428.72,1182.06 ; v1(3980.95,1451.86) 4253.8,1451.86 4414.83,1290.84 R1R_IDL_17_12_TerA71.1@4462.91,1290.84 4462.91,1263.12 4463.78,1262.25 R2R_IDL_17_12_TerA71.2@4463.78,1235.82
  Bot Signal w8: Jtop4.C2@2429.28,1176.24 2451.87,1176.24 2503.49,1124.61 3569.7,1124.61 3896.96,1451.86 v1(3980.95,1451.86)
JT72: Jtop1.C1 Jtop2.C1 Jtop3.C1 Jtop4.C1 R1R_IDL_17_12_TerA72.1 R2R_IDL_17_12_TerA72.2 | length 4713.2
  Top Signal w8: Jtop1.C1@28.79,1082.06 71.27,1124.54 265.41,1124.54 307.47,1082.48 818.19,1082.48 828.72,1082.48 867.06,1120.83 935.78,1120.83 940.03,1116.58 977.32,1116.58 981.57,1120.83 1069.48,1120.83 1107.82,1082.48 1628.3,1082.48 1628.72,1082.06 1665.37,1118.72 1746.87,1118.72 1749.27,1116.32 1790.26,1116.32 1792.66,1118.72 2392.07,1118.72 Jtop4.C1@2428.72,1082.06 ; v1(3139.02,968.04) 3144.78,962.28 4299.16,962.28 R2R_IDL_17_12_TerA72.2@4462.66,1125.78 4462.92,1126.04 R1R_IDL_17_12_TerA72.1@4462.92,1180.28
  Bot Signal w8: Jtop4.C1@2429.28,1076.24 2429.28,1063.33 2524.58,968.04 v1(3139.02,968.04)
pads on no net: GND1.1 Jbot1.33 Jbot1.34 Jbot2.33 Jbot2.34 Jbot3.33 Jbot3.34 Jbot4.33 Jbot4.34 JMid1.32 JMid1.33 JMid1.34 JMid1.35 JMid1.51 JMid1.52 JMid1.53 JMid1.54 JMid1.89 JMid1.90 JMid1.91 JMid1.92 JMid1.102 JMid1.103 JMid1.104 JMid1.106 JMid1.108 JMid1.109 JMid1.110 JMid1.111 JMid2.32 JMid2.33 JMid2.34 JMid2.35 JMid2.51 JMid2.52 JMid2.53 JMid2.54 JMid2.89 JMid2.90 JMid2.91 JMid2.92 JMid2.102 JMid2.103 JMid2.104 JMid2.106 JMid2.108 JMid2.109 JMid2.110 JMid2.111 JMid3.32 JMid3.33 JMid3.34 JMid3.35 JMid3.51 JMid3.52 JMid3.53 JMid3.54 JMid3.89 JMid3.90 JMid3.91 JMid3.92 JMid3.102 JMid3.103 JMid3.104 JMid3.106 JMid3.108 JMid3.109 JMid3.110 JMid3.111 JMid4.32 JMid4.33 JMid4.34 JMid4.35 JMid4.51 JMid4.52 JMid4.53 JMid4.54 JMid4.89 JMid4.90 JMid4.91 JMid4.92 JMid4.102 JMid4.103 JMid4.104 JMid4.106 JMid4.108 JMid4.109 JMid4.110 JMid4.111 Jtop1.33 Jtop1.34 Jtop2.33 Jtop2.34 Jtop3.33 Jtop3.34 Jtop4.33 Jtop4.34

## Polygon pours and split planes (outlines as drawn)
3V3 on 3.3 Volt (split plane): 4862.88,-5152.9 -215.91,-5152.9 -215.91,5156.9 4862.88,5156.9
GND on GND (split plane): 4862.88,-5152.9 -216.9,-5152.9 -216.9,5156.9 4862.88,5156.9
5V on 5 Volt (split plane): 4862.88,-5152.9 -215.91,-5152.9 -215.91,5156.9 4862.88,5156.9
12V on Split Plane (split plane): 4810.9,4255.78 4810.9,-471.58 4772.4,-510.07 4394.09,-510.07 4326.93,-442.91 4326.93,4079.79 4326.59,4082.4 4325.58,4084.84 4323.98,4086.92 4221.03,4189.87 4218.94,4191.48 4216.51,4192.48 4213.9,4192.83 2648,4192.83 2645.39,4192.48 2642.96,4191.48 2640.87,4189.87 2439.11,3988.11 2411.18,3988.11 2410.24,3988.5 2407.63,3988.85 2302.7,3988.85 2109.93,4181.62 2107.84,4183.22 2105.41,4184.23 2102.8,4184.57 1830.07,4184.57 1827.46,4184.23 1826.75,4183.93 1825.03,4183.22 1822.94,4181.62 1644.3,4002.98 1481.72,4002.98 1306.23,4178.47 1304.15,4180.07 1301.71,4181.08 1299.1,4181.42 1011.18,4181.42 1008.57,4181.08 1007.85,4180.78 1006.13,4180.07 1004.05,4178.47 867.19,4041.61 813.48,3987.91 728.16,3987.91 533.24,4182.83 531.15,4184.44 528.71,4185.44 526.1,4185.79 221.29,4185.79 218.68,4185.44 217.47,4184.94 216.25,4184.44 214.16,4182.83 24.04,3992.72 -74.26,4091.02 -74.26,4582.63 87.1,4744 4322.68,4744
-12V on Split Plane (split plane): 4306.76,4075.61 4306.76,-27.33 3811.52,-27.33 3712.49,71.7 3712.49,1120.64 3712.14,1123.26 3711.13,1125.69 3709.53,1127.78 3254.43,1582.88 3252.34,1584.48 3249.91,1585.49 3247.3,1585.83 29.28,1585.83 27.79,1585.64 27.4,1586.57 25.8,1588.65 -79.33,1693.78 -79.33,3856.12 30.91,3966.37 31.89,3966.49 34.32,3967.5 36.41,3969.1 38.01,3971.19 39.02,3973.63 39.37,3976.24 39.02,3978.85 38.93,3979.07 225.47,4165.62 521.93,4165.62 716.85,3970.69 718.94,3969.08 720.37,3968.49 721.38,3968.08 723.99,3967.73 817.66,3967.73 820.27,3968.08 822.71,3969.08 824.79,3970.69 881.45,4027.35 1015.36,4161.25 1294.92,4161.25 1470.41,3985.76 1472.5,3984.16 1474.94,3983.15 1477.55,3982.8 1653.03,3982.8 1655.64,3983.15 1658.07,3984.16 1660.16,3985.76 1661.76,3987.85 1662.77,3990.28 1663.12,3992.89 1663.07,3993.22 1834.25,4164.4 2098.62,4164.4 2291.39,3971.63 2293.48,3970.02 2294.7,3969.52 2295.91,3969.02 2298.52,3968.67 2404.81,3968.67 2405.75,3968.28 2408.36,3967.94 2443.29,3967.94 2445.9,3968.28 2448.33,3969.29 2450.42,3970.9 2652.18,4172.65 4209.72,4172.65
-3V3 on Split Plane (split plane): 2758.31,99.98 2758.31,39.27 2758.66,36.66 2759.67,34.23 2761.27,32.14 2848.41,-55 2849.39,-55.75 2850.37,-56.53 2850.44,-56.56 2850.5,-56.6 2851.65,-57.08 2852.79,-57.57 2852.86,-57.58 2852.93,-57.61 2854.16,-57.77 2855.39,-57.95 2908.87,-58.74 2908.94,-58.73 2909.02,-58.74 3325.16,-58.74 3327.77,-58.4 3330.2,-57.39 3332.29,-55.79 3427.02,38.94 3542.81,-76.85 3542.81,-768.37 3054.61,-1256.57 229.31,-1256.57 -147.39,-879.87 -147.39,153.42 -73.52,227.3 2631,227.3
-5V on Split Plane (split plane): 3421.86,822.66 3421.86,62.31 3320.98,-38.57 2909.09,-38.57 2859.78,-37.84 2778.49,43.45 2778.49,104.16 2778.14,106.77 2777.14,109.21 2775.53,111.29 2642.31,244.52 2640.22,246.12 2637.79,247.13 2635.18,247.47 -75.6,247.47 -149.83,321.7 -149.83,1398.76 -80.82,1467.77 2776.75,1467.77
no net on Split Plane (split plane): 4862.88,-5152.9 -216.9,-5152.9 -216.9,5156.9 4862.88,5156.9

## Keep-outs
Keep-Out Layer:
  lines w20: -237,-5173 -237,5177

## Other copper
3.3 Volt (plane layer: these items are gaps in the copper):
  lines w20: -226,-5162 -226,5166
5 Volt (plane layer: these items are gaps in the copper):
  lines w20: -226,-5162 -226,5166
Split Plane (plane layer: these items are gaps in the copper):
  lines w20: -78.74,236.34 -157.48,157.6 -157.48,-884.05 225.13,-1266.66 3058.78,-1266.66 3552.9,-772.55 3552.9,-72.67 3431.95,48.27 ; 18.67,1581.52 -89.42,1689.61 -89.42,3860.3 26.52,3976.24 29.28,3976.24 ; 23.75,3978.15 221.29,4175.7 526.1,4175.7 723.99,3977.82 817.66,3977.82 874.32,4034.48 1011.18,4171.33 1299.1,4171.33 1477.55,3992.89 1653.03,3992.89 ; 23.75,3978.75 -84.35,4086.84 -84.35,4586.81 82.92,4754.08 4326.85,4754.08 4820.98,4259.96 4820.98,-475.75 4776.57,-520.16 4389.91,-520.16 4316.84,-447.09 4316.84,4079.79 4213.9,4182.74 2648,4182.74 2443.29,3978.03 2408.36,3978.03 2407.63,3978.76 2298.52,3978.76 2102.8,4174.49 1830.07,4174.49 1650.75,3995.17 ; 29.28,1575.75 3247.3,1575.75 3702.4,1120.64 3702.4,67.52 3807.34,-37.42 4315.22,-37.42 ; -159.92,317.52 -79.78,237.38 2635.18,237.38 2768.4,104.16 2768.4,39.27 2855.54,-47.87 2909.02,-48.66 3325.16,-48.66 3431.95,58.14 3431.95,826.84 2780.93,1477.86 -85,1477.86 -159.92,1402.94 -159.92,317.52

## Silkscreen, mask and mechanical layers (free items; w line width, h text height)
Top Overlay:
  drawing of 160 lines, arcs and shapes, not listed
  text "IDL_17_12 / VME Backplae Rev.A / Designer: Jose Duron" at 3223.2,-4687.76 h60
  text "IDL" at 3398.32,-4827.7 h50
  text "Instrumentation" at 3398.32,-4877.7 h25
  text "Development" at 3398.32,-4917.7 h25
  text "Lab" at 3398.32,-4957.7 h25
Mechanical 2:
  drawing of 252 lines, arcs and shapes, not listed
  text "1" at -13904.31,8306.83 h35
  text "2" at -11929.31,8306.83 h35
  text "3" at -9954.31,8306.83 h35
  text "4" at -7979.31,8306.83 h35
  text "5" at -6004.31,8306.83 h35
  text "6" at -4029.31,8306.83 h35
  text "7" at -2054.31,8306.83 h35
  text "8" at -79.31,8306.83 h35
  text "1" at -14184.39,7643.66 h35
  text "2" at -12209.39,7643.66 h35
  text "3" at -10234.39,7643.66 h35
  text "4" at -8259.39,7643.66 h35
  text "5" at -6284.39,7643.66 h35
  text "6" at -4309.39,7643.66 h35
  text "7" at -2334.39,7643.66 h35
  text "8" at -359.39,7643.66 h35
  text "A" at -14846.86,7349.68 h35
  text "A" at 853.15,7349.68 h35
  text "1" at 2612.73,6786.27 h35
  text "2" at 4587.73,6786.27 h35
  text "3" at 6562.73,6786.27 h35
  text "4" at 8537.73,6786.27 h35
  text "5" at 10512.73,6786.27 h35
  text "6" at 12487.73,6786.27 h35
  text "7" at 14462.73,6786.27 h35
  text "8" at 16437.73,6786.27 h35
  text "A" at -15126.93,6686.51 h35
  text "A" at 573.07,6686.51 h35
  text "1" at -13620.84,6299.24 h35
  text "2" at -11645.84,6299.24 h35
  text "3" at -9670.84,6299.24 h35
  text "4" at -7695.84,6299.24 h35
  text "5" at -5720.84,6299.24 h35
  text "6" at -3745.84,6299.24 h35
  text "7" at -1770.84,6299.24 h35
  text "8" at 204.16,6299.24 h35
  text "A" at 1670.18,5829.12 h35
  text "A" at 17370.18,5829.12 h35
  text "B" at -14846.86,5436.35 h35
  text "B" at 853.15,5436.35 h35
  text "A" at -14563.38,5342.09 h35
  text "A" at 1136.62,5342.09 h35
  text "B" at -15126.93,4773.18 h35
  text "B" at 573.07,4773.18 h35
  text "B" at 1670.18,3915.79 h35
  text "B" at 17370.18,3915.79 h35
  text "C" at -14851.9,3523.01 h35
  text "C" at 848.1,3523.01 h35
  text "B" at -14563.38,3428.76 h35
  text "B" at 1136.62,3428.76 h35
  text "C" at -15131.98,2859.84 h35
  text "C" at 568.02,2859.84 h35
  text "C" at 1665.14,2002.45 h35
  text "C" at 17365.14,2002.45 h35
  text "D" at -14851.9,1609.68 h35
  text "D" at 848.1,1609.68 h35
  text "1" at -9275.06,1545.98 h35
  text "2" at -7300.06,1545.98 h35
  text "3" at -5325.06,1545.98 h35
  text "4" at -3350.06,1545.98 h35
  text "5" at -1375.06,1545.98 h35
  text "6" at 599.94,1545.98 h35
  text "7" at 2574.94,1545.98 h35
  text "8" at 4549.94,1545.98 h35
  text "C" at -14568.43,1515.43 h35
  text "C" at 1131.57,1515.43 h35
  text "D" at -15131.98,946.51 h35
  text "D" at 568.02,946.51 h35
  text "1" at 5628.19,870.06 h35
  text "2" at 7603.19,870.06 h35
  text "3" at 9578.19,870.06 h35
  text "4" at 11553.19,870.06 h35
  text "5" at 13528.19,870.06 h35
  text "6" at 15503.19,870.06 h35
  text "7" at 17478.19,870.06 h35
  text "8" at 19453.19,870.06 h35
  text "A" at -10217.6,588.82 h35
  text "A" at 5482.4,588.82 h35
  text "D" at 1665.14,89.12 h35
  text "D" at 17365.14,89.12 h35
  text "A" at 4685.65,-87.09 h35
  text "A" at 20385.65,-87.09 h35
  text "E" at -14846.86,-303.65 h35
  text "E" at 853.15,-303.65 h35
  text "D" at -14568.43,-397.91 h35
  text "D" at 1131.57,-397.91 h35
  text "E" at -15126.93,-966.82 h35
  text "E" at 573.07,-966.82 h35
  text "B" at -10217.6,-1324.51 h35
  text "B" at 5482.4,-1324.51 h35
  text "E" at 1670.18,-1824.21 h35
  text "E" at 17370.18,-1824.21 h35
  text "B" at 4685.65,-2000.42 h35
  text "B" at 20385.65,-2000.42 h35
  text "F" at -14846.86,-2216.99 h35
  text "F" at 853.15,-2216.99 h35
  text "E" at -14563.38,-2311.24 h35
  text "E" at 1136.62,-2311.24 h35
  text "Designer:" at -5836.63,-2373.65 h100
  text ".Designer" at -5271.63,-2378.65 h100
  text "Revision:" at -4331.63,-2378.65 h100
  text ".RevNum" at -3771.63,-2378.65 h100
  text "File:" at -3331.63,-2378.65 h100
  text ".Pcb_File_Name_No_Path" at -3131.63,-2378.65 h100
  text "Sheet  1 of  1" at -1736.63,-2378.65 h100
  text "Code:" at -1016.63,-2423.65 h100
  text "Drawn By:" at -5836.63,-2493.65 h100
  text ".Drawn_By" at -5271.63,-2493.65 h100
  text "Modif. Date:" at -4331.63,-2498.65 h100
  text "Date" at -3826.63,-2498.65 h100
  text "Variant:" at -3331.63,-2498.65 h100
  text ".VariantName" at -2966.63,-2498.65 h100
  text "ID:" at -1011.63,-2603.65 h100
  text "Approved By:" at -5836.63,-2613.65 h100
  text ".Approved_By" at -5271.63,-2613.65 h100
  text ".Print_Date" at -3884.23,-2618.06 h100
  text "Print Date:" at -4331.63,-2618.65 h100
  text "Signature:" at -3331.63,-2618.65 h100
  text "Size:  A3 H" at -1736.63,-2618.65 h100
  text "Title:" at -5836.63,-2743.65 h100
  text "University of Hawaii at Manoa" at -1010.21,-2751.92 h100
  text "High Energy Physics Group" at -1010.21,-2850.35 h100
  text "F" at -15126.93,-2880.16 h35
  text "F" at 573.07,-2880.16 h35
  text ".Printout_Name" at -5611.63,-2883.65 h160
  text "Instrumentation Development Laboratory" at -1010.21,-2952.71 h100
  text "Designer:" at -6116.71,-3036.82 h100
  text ".Designer" at -5551.71,-3041.82 h100
  text "Revision:" at -4611.71,-3041.82 h100
  text ".RevNum" at -4051.71,-3041.82 h100
  text "File:" at -3611.71,-3041.82 h100
  text ".Pcb_File_Name_No_Path" at -3411.71,-3041.82 h100
  text "Sheet  1 of  1" at -2016.71,-3041.82 h100
  text "1" at -13904.31,-3073.17 h35
  text "2" at -11929.31,-3073.17 h35
  text "3" at -9954.31,-3073.17 h35
  text "4" at -7979.31,-3073.17 h35
  text "5" at -6004.31,-3073.17 h35
  text "6" at -4029.31,-3073.17 h35
  text "7" at -2054.31,-3073.17 h35
  text "8" at -79.31,-3073.17 h35
  text "Code:" at -1296.71,-3086.82 h100
  text "Drawn By:" at -6116.71,-3156.82 h100
  text ".Drawn_By" at -5551.71,-3156.82 h100
  text "Modif. Date:" at -4611.71,-3161.82 h100
  text "Date" at -4106.71,-3161.82 h100
  text "Variant:" at -3611.71,-3161.82 h100
  text ".VariantName" at -3246.71,-3161.82 h100
  text "C" at -10222.65,-3237.84 h35
  text "C" at 5477.35,-3237.84 h35
  text "ID:" at -1291.71,-3266.82 h100
  text "Approved By:" at -6116.71,-3276.82 h100
  text ".Approved_By" at -5551.71,-3276.82 h100
  text ".Print_Date" at -4164.31,-3281.23 h100
  text "Print Date:" at -4611.71,-3281.82 h100
  text "Signature:" at -3611.71,-3281.82 h100
  text "Size:  A3 H" at -2016.71,-3281.82 h100
  text "Title:" at -6116.71,-3406.82 h100
  text "University of Hawaii at Manoa" at -1290.29,-3415.09 h100
  text "High Energy Physics Group" at -1290.29,-3513.52 h100
  text ".Printout_Name" at -5891.71,-3546.82 h160
  text "Instrumentation Development Laboratory" at -1290.29,-3615.88 h100
  text "1" at -14184.39,-3736.34 h35
  text "2" at -12209.39,-3736.34 h35
  text "3" at -10234.39,-3736.34 h35
  text "4" at -8259.39,-3736.34 h35
  text "5" at -6284.39,-3736.34 h35
  text "6" at -4309.39,-3736.34 h35
  text "7" at -2334.39,-3736.34 h35
  text "8" at -359.39,-3736.34 h35
  text "F" at 1670.18,-3737.55 h35
  text "F" at 17370.18,-3737.55 h35
  text "Designer:" at 10680.41,-3894.21 h100
  text ".Designer" at 11245.41,-3899.21 h100
  text "Revision:" at 12185.41,-3899.21 h100
  text ".RevNum" at 12745.41,-3899.21 h100
  text "File:" at 13185.41,-3899.21 h100
  text ".Pcb_File_Name_No_Path" at 13385.41,-3899.21 h100
  text "Sheet  1 of  1" at 14780.41,-3899.21 h100
  text "C" at 4680.6,-3913.75 h35
  text "C" at 20380.6,-3913.75 h35
  text "Code:" at 15500.41,-3944.21 h100
  text "Drawn By:" at 10680.41,-4014.21 h100
  text ".Drawn_By" at 11245.41,-4014.21 h100
  text "Modif. Date:" at 12185.41,-4019.21 h100
  text "Date" at 12690.41,-4019.21 h100
  text "Variant:" at 13185.41,-4019.21 h100
  text ".VariantName" at 13550.41,-4019.21 h100
  text "ID:" at 15505.41,-4124.21 h100
  text "Approved By:" at 10680.41,-4134.21 h100
  text ".Approved_By" at 11245.41,-4134.21 h100
  text "Print Date:" at 12185.41,-4139.21 h100
  text ".Print_Date" at 12632.81,-4138.62 h100
  text "Signature:" at 13185.41,-4139.21 h100
  text "Size:  A3 H" at 14780.41,-4139.21 h100
  text "F" at -14563.38,-4224.57 h35
  text "F" at 1136.62,-4224.57 h35
  text "Title:" at 10680.41,-4264.21 h100
  text "University of Hawaii at Manoa" at 15506.82,-4272.48 h100
  text "High Energy Physics Group" at 15506.82,-4370.91 h100
  text "Designer:" at -5553.16,-4381.24 h100
  text ".Designer" at -4988.16,-4386.24 h100
  text "Revision:" at -4048.16,-4386.24 h100
  text ".RevNum" at -3488.16,-4386.24 h100
  text "File:" at -3048.16,-4386.24 h100
  text ".Pcb_File_Name_No_Path" at -2848.16,-4386.24 h100
  text "Sheet  1 of  1" at -1453.16,-4386.24 h100
  text ".Printout_Name" at 10905.41,-4404.21 h160
  text "Code:" at -733.16,-4431.24 h100
  text "Instrumentation Development Laboratory" at 15506.82,-4473.27 h100
  text "Drawn By:" at -5553.16,-4501.24 h100
  text ".Drawn_By" at -4988.16,-4501.24 h100
  text "Modif. Date:" at -4048.16,-4506.24 h100
  text "Date" at -3543.16,-4506.24 h100
  text "Variant:" at -3048.16,-4506.24 h100
  text ".VariantName" at -2683.16,-4506.24 h100
  text "1" at 2612.73,-4593.73 h35
  text "2" at 4587.73,-4593.73 h35
  text "3" at 6562.73,-4593.73 h35
  text "4" at 8537.73,-4593.73 h35
  text "5" at 10512.73,-4593.73 h35
  text "6" at 12487.73,-4593.73 h35
  text "7" at 14462.73,-4593.73 h35
  text "8" at 16437.73,-4593.73 h35
  text "ID:" at -728.16,-4611.24 h100
  text "Approved By:" at -5553.16,-4621.24 h100
  text ".Approved_By" at -4988.16,-4621.24 h100
  text "Print Date:" at -4048.16,-4626.24 h100
  text ".Print_Date" at -3600.76,-4625.65 h100
  text "Signature:" at -3048.16,-4626.24 h100
  text "Size:  A3 H" at -1453.16,-4626.24 h100
  text "Title:" at -5553.16,-4751.24 h100
  text "University of Hawaii at Manoa" at -726.74,-4759.51 h100
  text "High Energy Physics Group" at -726.74,-4857.93 h100
  text ".Printout_Name" at -5328.16,-4891.24 h160
  text "Instrumentation Development Laboratory" at -726.74,-4960.3 h100
  text "1" at -13620.84,-5080.76 h35
  text "2" at -11645.84,-5080.76 h35
  text "3" at -9670.84,-5080.76 h35
  text "4" at -7695.84,-5080.76 h35
  text "5" at -5720.84,-5080.76 h35
  text "6" at -3745.84,-5080.76 h35
  text "7" at -1770.84,-5080.76 h35
  text "8" at 204.16,-5080.76 h35
  text "D" at -10222.65,-5151.18 h35
  text "D" at 5477.35,-5151.18 h35
  text "D" at 4680.6,-5827.09 h35
  text "D" at 20380.6,-5827.09 h35
  text "E" at -10217.6,-7064.51 h35
  text "E" at 5482.4,-7064.51 h35
  text "E" at 4685.65,-7740.42 h35
  text "E" at 20385.65,-7740.42 h35
  text "F" at -10217.6,-8977.84 h35
  text "F" at 5482.4,-8977.84 h35
  text "Designer:" at -1207.38,-9134.51 h100
  text ".Designer" at -642.38,-9139.51 h100
  text "Revision:" at 297.62,-9139.51 h100
  text ".RevNum" at 857.62,-9139.51 h100
  text "File:" at 1297.62,-9139.51 h100
  text ".Pcb_File_Name_No_Path" at 1497.62,-9139.51 h100
  text "Sheet  1 of  1" at 2892.62,-9139.51 h100
  text "Code:" at 3612.62,-9184.51 h100
  text "Drawn By:" at -1207.38,-9254.51 h100
  text ".Drawn_By" at -642.38,-9254.51 h100
  text "Modif. Date:" at 297.62,-9259.51 h100
  text "Date" at 802.62,-9259.51 h100
  text "Variant:" at 1297.62,-9259.51 h100
  text ".VariantName" at 1662.62,-9259.51 h100
  text "ID:" at 3617.62,-9364.51 h100
  text "Approved By:" at -1207.38,-9374.51 h100
  text ".Approved_By" at -642.38,-9374.51 h100
  text ".Print_Date" at 745.02,-9378.92 h100
  text "Print Date:" at 297.62,-9379.51 h100
  text "Signature:" at 1297.62,-9379.51 h100
  text "Size:  A3 H" at 2892.62,-9379.51 h100
  text "Title:" at -1207.38,-9504.51 h100
  text "University of Hawaii at Manoa" at 3619.04,-9512.78 h100
  text "High Energy Physics Group" at 3619.04,-9611.2 h100
  text ".Printout_Name" at -982.38,-9644.51 h160
  text "F" at 4685.65,-9653.75 h35
  text "F" at 20385.65,-9653.75 h35
  text "Instrumentation Development Laboratory" at 3619.04,-9713.56 h100
  text "Designer:" at 13695.87,-9810.42 h100
  text ".Designer" at 14260.87,-9815.42 h100
  text "Revision:" at 15200.87,-9815.42 h100
  text ".RevNum" at 15760.87,-9815.42 h100
  text "File:" at 16200.87,-9815.42 h100
  text ".Pcb_File_Name_No_Path" at 16400.87,-9815.42 h100
  text "Sheet  1 of  1" at 17795.87,-9815.42 h100
  text "1" at -9275.06,-9834.02 h35
  text "2" at -7300.06,-9834.02 h35
  text "3" at -5325.06,-9834.02 h35
  text "4" at -3350.06,-9834.02 h35
  text "5" at -1375.06,-9834.02 h35
  text "6" at 599.94,-9834.02 h35
  text "7" at 2574.94,-9834.02 h35
  text "8" at 4549.94,-9834.02 h35
  text "Code:" at 18515.87,-9860.42 h100
  text "Drawn By:" at 13695.87,-9930.42 h100
  text ".Drawn_By" at 14260.87,-9930.42 h100
  text "Modif. Date:" at 15200.87,-9935.42 h100
  text "Date" at 15705.87,-9935.42 h100
  text "Variant:" at 16200.87,-9935.42 h100
  text ".VariantName" at 16565.87,-9935.42 h100
  text "ID:" at 18520.87,-10040.42 h100
  text "Approved By:" at 13695.87,-10050.42 h100
  text ".Approved_By" at 14260.87,-10050.42 h100
  text "Print Date:" at 15200.87,-10055.42 h100
  text ".Print_Date" at 15648.27,-10054.83 h100
  text "Signature:" at 16200.87,-10055.42 h100
  text "Size:  A3 H" at 17795.87,-10055.42 h100
  text "Title:" at 13695.87,-10180.42 h100
  text "University of Hawaii at Manoa" at 18522.29,-10188.69 h100
  text "High Energy Physics Group" at 18522.29,-10287.12 h100
  text ".Printout_Name" at 13920.87,-10320.42 h160
  text "Instrumentation Development Laboratory" at 18522.29,-10389.48 h100
  text "1" at 5628.19,-10509.94 h35
  text "2" at 7603.19,-10509.94 h35
  text "3" at 9578.19,-10509.94 h35
  text "4" at 11553.19,-10509.94 h35
  text "5" at 13528.19,-10509.94 h35
  text "6" at 15503.19,-10509.94 h35
  text "7" at 17478.19,-10509.94 h35
  text "8" at 19453.19,-10509.94 h35
Board Outline:
  lines w20: -237,-5173 4880.39,-5173 4880.39,5174.4 4880.55,5174.55 -234.55,5174.55 -237,5177 -237,-5173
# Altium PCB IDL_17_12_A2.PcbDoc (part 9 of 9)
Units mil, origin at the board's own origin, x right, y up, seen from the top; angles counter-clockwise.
Board outline 5119.97 x 10350 mil, 6 copper layers (Top Signal, 3.3 Volt, GND, 5 Volt, Split Plane, Bot Signal), stack 66.2 mil thick; 514 components, 178 nets, 2321 pads, 427 vias.

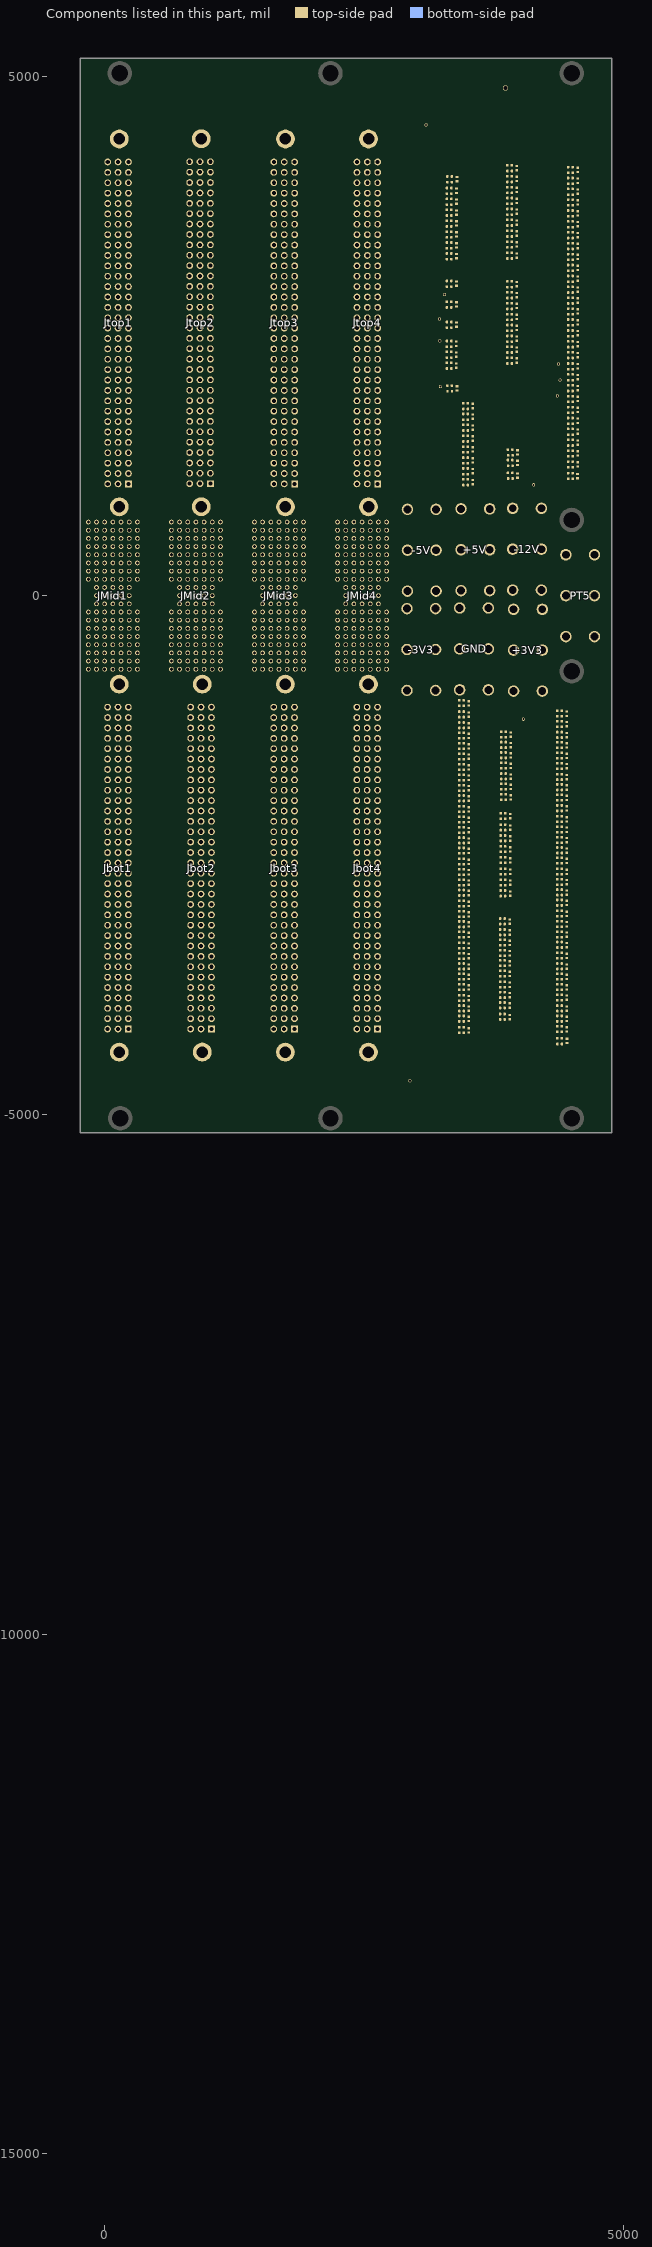
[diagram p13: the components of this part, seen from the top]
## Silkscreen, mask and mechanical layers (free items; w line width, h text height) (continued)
Sheet Top:
  lines w3.9: -2026.33,-3719.49 -1926.33,-3719.49 ; -2026.33,-1806.16 -1926.33,-1806.16 ; -2026.33,107.18 -1926.33,107.18 ; -2026.33,2020.51 -1926.33,2020.51 ; -2026.33,3933.84 -1926.33,3933.84 ; -51.33,-5632.82 -51.33,-5532.82 ; -51.33,5747.18 -51.33,5847.18 ; 1923.67,-5632.82 1923.67,-5532.82 ; 1923.67,5747.18 1923.67,5847.18 ; 3898.67,-5632.82 3898.67,-5532.82 ; 3898.67,5747.18 3898.67,5847.18 ; 5873.67,-5632.82 5873.67,-5532.82 ; 5873.67,5747.18 5873.67,5847.18 ; 7848.67,-5632.82 7848.67,-5532.82 ; 7848.67,5747.18 7848.67,5847.18 ; 9823.67,-5632.82 9823.67,-5532.82 ; 9823.67,5747.18 9823.67,5847.18 ; 11798.67,-5632.82 11798.67,-5532.82 ; 11798.67,5747.18 11798.67,5847.18 ; 13673.67,-3719.49 13773.67,-3719.49 ; 13673.67,-1806.16 13773.67,-1806.16 ; 13673.67,107.18 13773.67,107.18 ; 13673.67,2020.51 13773.67,2020.51 ; 13673.67,3933.84 13773.67,3933.84 ; -2026.33,-5632.73 13773.58,-5632.73 13773.58,5847.18 -2026.33,5847.18 -2026.33,-5632.73 ; -1926.07,-5533.02 13673.32,-5533.02 13673.32,5747.47 -1926.07,5747.47 -1926.07,-5533.02
  lines w3.94: 6983.67,-5533.02 6983.67,-4822.82 13673.32,-4822.82 ; 6983.67,-5182.06 13673.67,-5182.06 ; 6983.67,-5062.82 11803.67,-5062.82 ; 6983.67,-4942.82 11803.67,-4942.82 ; 8488.67,-5182.06 8488.67,-4822.82 ; 9488.67,-5182.06 9488.67,-4822.82 ; 11078.67,-5182.06 11078.67,-4822.82 ; 11803.67,-5533.02 11803.67,-4822.82 ; 11803.67,-5002.82 13673.32,-5002.82
  text "1" at -1059.01,5767.66 h35
  text "2" at 915.99,5767.66 h35
  text "3" at 2890.99,5767.66 h35
  text "4" at 4865.99,5767.66 h35
  text "5" at 6840.99,5767.66 h35
  text "6" at 8815.99,5767.66 h35
  text "7" at 10790.99,5767.66 h35
  text "8" at 12765.99,5767.66 h35
  text "A" at -2001.56,4810.51 h35
  text "A" at 13698.45,4810.51 h35
  text "B" at -2001.56,2897.18 h35
  text "B" at 13698.45,2897.18 h35
  text "C" at -2006.6,983.84 h35
  text "C" at 13693.4,983.84 h35
  text "D" at -2006.6,-929.49 h35
  text "D" at 13693.4,-929.49 h35
  text "E" at -2001.56,-2842.82 h35
  text "E" at 13698.45,-2842.82 h35
  text "F" at -2001.56,-4756.16 h35
  text "F" at 13698.45,-4756.16 h35
  text "Designer:" at 7008.67,-4912.82 h100
  text ".Designer" at 7573.67,-4917.82 h100
  text "Revision:" at 8513.67,-4917.82 h100
  text ".RevNum" at 9073.67,-4917.82 h100
  text "File:" at 9513.67,-4917.82 h100
  text ".Pcb_File_Name_No_Path" at 9713.67,-4917.82 h100
  text "Sheet  1 of  1" at 11108.67,-4917.82 h100
  text "Code:" at 11828.67,-4962.82 h100
  text "Drawn By:" at 7008.67,-5032.82 h100
  text ".Drawn_By" at 7573.67,-5032.82 h100
  text "Modif. Date:" at 8513.67,-5037.82 h100
  text "Date" at 9018.67,-5037.82 h100
  text "Variant:" at 9513.67,-5037.82 h100
  text ".VariantName" at 9878.67,-5037.82 h100
  text "ID:" at 11833.67,-5142.82 h100
  text "Approved By:" at 7008.67,-5152.82 h100
  text ".Approved_By" at 7573.67,-5152.82 h100
  text ".Print_Date" at 8961.07,-5157.23 h100
  text "Print Date:" at 8513.67,-5157.82 h100
  text "Signature:" at 9513.67,-5157.82 h100
  text "Size:  A3 H" at 11108.67,-5157.82 h100
  text "Title:" at 7008.67,-5282.82 h100
  text "University of Hawaii at Manoa" at 11835.08,-5291.09 h100
  text "High Energy Physics Group" at 11835.08,-5389.52 h100
  text ".Printout_Name" at 7233.67,-5422.82 h160
  text "Instrumentation Development Laboratory" at 11835.08,-5491.88 h100
  text "1" at -1059.01,-5612.34 h35
  text "2" at 915.99,-5612.34 h35
  text "3" at 2890.99,-5612.34 h35
  text "4" at 4865.99,-5612.34 h35
  text "5" at 6840.99,-5612.34 h35
  text "6" at 8815.99,-5612.34 h35
  text "7" at 10790.99,-5612.34 h35
  text "8" at 12765.99,-5612.34 h35
Drill Drawing:
  drawing of 468 lines, arcs and shapes, not listed
  text "Notes:" at 7727.76,3850.27 h130
  text "1. Board shall be fabricated - performace class II as per IPC-6011 and IPC6012" at 7727.76,3725.27 h100
  text "2.All of bottom edge and sides edges up to 3.2mm of PCB needs to be plated with 35um copper." at 7727.76,3600.27 h100
  text "3. Silkscreen printed on both sides" at 7727.76,3493.78 h100
  text "4. Material: high temperature FR4 class epoxy glass rated UL94V-0. UL symbol and rating shall be marked farside" at 7727.76,3368.78 h100
  text "35um copper for external and internal layers" at 7827.78,3268.78 h100
  text "Must be RoHS compliant and survive a lead-free assembly max reflow of 260 deg C (5 passes)" at 7827.76,3168.78 h100
  text "Td rating: >340 deg C" at 7877.76,3043.78 h100
  text "Tg = 150 deg C (min)" at 7881.79,2933.52 h100
  text "5. Solder mask: SMOBC per IPC-SM-840C, class T must be Rohs compliant, 0.001\" max measured over bare copper plating," at 7727.76,2823.7 h100
  text "must clear all lands as indicated on gerber solder mask layers, color= GREEN" at 7827.76,2723.7 h100
  text "6. Finish: electro-less nickel immersion gold (ENIG), 0.05-0.125um Au over 3-6um Ni - over bare copper only" at 7727.55,2569.88 h100
  text "7. Solderability test: Category 2 of J-STD-003" at 7727.76,2423.7 h100
  text "8. Finished boards shall not have nicks, scratches, voids, exposed copper, poor plating or misdrilled holes" at 7727.76,2273.7 h100
  text "9. All holes sizes are after plating" at 7727.76,2123.7 h100
  text "10. PCB manufacturer may add copper thieving as needed to improve manufacturability," at 7677.76,1973.7 h100
  text "thieving to be 0.030\" round pads at 0.050\" spacing." at 7827.76,1873.7 h100
  text "Thieving will have a minimum of 0.100\" clearance from existing copper and should not be placed under surface mounted devices" at 7827.76,1773.7 h100
  text "11. PCB manufacturer may use tear drops to improve annular rings as long as DRC rules are followed" at 7682.76,1633.7 h100
  text "12. All via connections to power and ground planes are solid" at 7682.76,1493.7 h100
  text "13. All unconnected pads on inner signal layers are removed" at 7682.76,1353.7 h100
  text "14. All finished boards are to be 100% electrically tested" at 7682.78,1213.7 h100
  text "15. Unless otherwise indicated, all linear toleracnes shall be XX.X +/-0.2mm and XX.XX +/- 0.1mm" at 7682.76,1073.7 h100
  text "16. Gerber file GM1 shows board outline (milling line)" at 7682.75,933.68 h100
  text "17. Table 1 shows Layer stack details" at 7682.75,793.67 h100
  text "18. Gerber files GTP ans DBP shows stencil cut out, stencil should be flat with no bent tabs on sides." at 7682.75,636.19 h100
  text "Symbol" at 7589.39,-1333.67 h72
  text "Count" at 8095.27,-1333.67 h72
  text "Hole Size" at 8745.09,-1333.67 h72
  text "Plated" at 9894.76,-1333.67 h72
  text "Hole Type" at 10400.63,-1333.67 h72
  text "Hole Length" at 11134.43,-1333.67 h72
  text "9" at 8095.27,-1483.67 h60
  text "157.00mil (3.988mm)" at 8745.09,-1483.67 h60
  text "PTH" at 9894.76,-1483.67 h60
  text "Round" at 10400.63,-1483.67 h60
  text "-" at 11134.43,-1483.67 h60
  text "11" at 8095.27,-1633.67 h60
  text "19.69mil (0.500mm)" at 8745.09,-1633.67 h60
  text "PTH" at 9894.76,-1633.67 h60
  text "Round" at 10400.63,-1633.67 h60
  text "-" at 11134.43,-1633.67 h60
  text "16" at 8095.27,-1783.67 h60
  text "110.24mil (2.800mm)" at 8745.09,-1783.67 h60
  text "PTH" at 9894.76,-1783.67 h60
  text "Round" at 10400.63,-1783.67 h60
  text "-" at 11134.43,-1783.67 h60
  text "42" at 8095.27,-1933.67 h60
  text "76.00mil (1.930mm)" at 8745.09,-1933.67 h60
  text "PTH" at 9894.76,-1933.67 h60
  text "Round" at 10400.63,-1933.67 h60
  text "-" at 11134.43,-1933.67 h60
  text "427" at 8095.27,-2083.67 h60
  text "11.81mil (0.300mm)" at 8745.09,-2083.67 h60
  text "PTH" at 9894.76,-2083.67 h60
  text "Round" at 10400.63,-2083.67 h60
  text "-" at 11134.43,-2083.67 h60
  text "508" at 8095.27,-2233.67 h60
  text "30.00mil (0.762mm)" at 8745.09,-2233.67 h60
  text "PTH" at 9894.76,-2233.67 h60
  text "Round" at 10400.63,-2233.67 h60
  text "-" at 11134.43,-2233.67 h60
  text "769" at 8095.27,-2383.67 h60
  text "39.37mil (1.000mm)" at 8745.09,-2383.67 h60
  text "PTH" at 9894.76,-2383.67 h60
  text "Round" at 10400.63,-2383.67 h60
  text "-" at 11134.43,-2383.67 h60
  text "1782 Total" at 8095.27,-2533.67 h60
  text "Layer" at 7540.2,-2823.89 h60
  text "Name" at 7950.11,-2823.89 h60
  text "Material" at 8879.85,-2823.89 h60
  text "Thickness" at 9739.62,-2823.89 h60
  text "Constant" at 10389.45,-2823.89 h60
  text "Board Layer Stack" at 10959.32,-2823.89 h60
  text "1" at 7540.2,-2943.89 h60
  text "Top Overlay" at 7950.11,-2943.89 h60
  text "2" at 7540.2,-3063.89 h60
  text "Top Solder" at 7950.11,-3063.89 h60
  text "Solder Resist" at 8879.85,-3063.89 h60
  text "0.40mil" at 9739.62,-3063.89 h60
  text "3.5" at 10389.45,-3063.89 h60
  text "3" at 7540.2,-3183.89 h60
  text "Top Signal" at 7950.11,-3183.89 h60
  text "Copper" at 8879.85,-3183.89 h60
  text "2.70mil" at 9739.62,-3183.89 h60
  text "4" at 7540.2,-3303.89 h60
  text "Dielectric 1" at 7950.11,-3303.89 h60
  text "FR-4" at 8879.85,-3303.89 h60
  text "10.00mil" at 9739.62,-3303.89 h60
  text "4.2" at 10389.45,-3303.89 h60
  text "5" at 7540.2,-3423.89 h60
  text "3.3 Volt" at 7950.11,-3423.89 h60
  text "Copper" at 8879.85,-3423.89 h60
  text "2.70mil" at 9739.62,-3423.89 h60
  text "6" at 7540.2,-3543.89 h60
  text "Dielectric2" at 7950.11,-3543.89 h60
  text "FR-4" at 8879.85,-3543.89 h60
  text "10.00mil" at 9739.62,-3543.89 h60
  text "4.2" at 10389.45,-3543.89 h60
  text "7" at 7540.2,-3663.89 h60
  text "GND" at 7950.11,-3663.89 h60
  text "Copper" at 8879.85,-3663.89 h60
  text "2.70mil" at 9739.62,-3663.89 h60
  text "8" at 7540.2,-3783.89 h60
  text "Dielectric 5" at 7950.11,-3783.89 h60
  text "FR-4" at 8879.85,-3783.89 h60
  text "10.00mil" at 9739.62,-3783.89 h60
  text "4.2" at 10389.45,-3783.89 h60
  text "9" at 7540.2,-3903.89 h60
  text "5 Volt" at 7950.11,-3903.89 h60
  text "Copper" at 8879.85,-3903.89 h60
  text "2.70mil" at 9739.62,-3903.89 h60
  text "10" at 7540.2,-4023.89 h60
  text "Dielectric 6" at 7950.11,-4023.89 h60
  text "FR-4" at 8879.85,-4023.89 h60
  text "10.00mil" at 9739.62,-4023.89 h60
  text "4.2" at 10389.45,-4023.89 h60
  text "11" at 7540.2,-4143.89 h60
  text "Split Plane" at 7950.11,-4143.89 h60
  text "Copper" at 8879.85,-4143.89 h60
  text "2.70mil" at 9739.62,-4143.89 h60
  text "12" at 7540.2,-4263.89 h60
  text "Dielectric3" at 7950.11,-4263.89 h60
  text "FR-4" at 8879.85,-4263.89 h60
  text "10.00mil" at 9739.62,-4263.89 h60
  text "4.2" at 10389.45,-4263.89 h60
  text "13" at 7540.2,-4383.89 h60
  text "Bot Signal" at 7950.11,-4383.89 h60
  text "Copper" at 8879.85,-4383.89 h60
  text "2.70mil" at 9739.62,-4383.89 h60
  text "14" at 7540.2,-4503.89 h60
  text "Bottom Solder" at 7950.11,-4503.89 h60
  text "Solder Resist" at 8879.85,-4503.89 h60
  text "0.40mil" at 9739.62,-4503.89 h60
  text "3.5" at 10389.45,-4503.89 h60
  text "15" at 7540.2,-4623.89 h60
  text "Bottom Overlay" at 7950.11,-4623.89 h60

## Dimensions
-237,-5173 to 4882.97,-5173 on Mechanical 1
148.83,-5031.5 to -237,-5173 on Mechanical 1
148.83,-5031.5 to -237,-5173 on Mechanical 1
140.07,-4395.42 to -237,-5173 on Mechanical 1
140.07,-4395.42 to -237,-5173 on Mechanical 1
-157.48,-708.54 to -237,-5173 on Mechanical 1
140.07,854.58 to -237,5177 on Mechanical 1
141.09,4397.89 to -237,-5173 on Mechanical 1
-157.48,-708.54 to -237,-5173 on Mechanical 1
148.83,5031.5 to -237,5177 on Mechanical 1
148.83,5031.5 to -237,-5173 on Mechanical 1
941.09,4397.89 to -237,5177 on Mechanical 1
1741.09,4397.89 to -237,5177 on Mechanical 1
2541.09,4397.89 to -237,5177 on Mechanical 1
3348.83,5031.5 to -237,5177 on Mechanical 1
642.52,-708.54 to -237,-5173 on Mechanical 1
1442.52,-708.54 to -237,-5173 on Mechanical 1
2242.52,-708.54 to -237,-5173 on Mechanical 1
4882.97,5018.28 to 4497.14,5163.78 on Mechanical 1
